VERSION 5.8 ;
BUSBITCHARS "[]" ;
DIVIDERCHAR "/" ;
UNITS
    DATABASE MICRONS 1000 ;
END UNITS

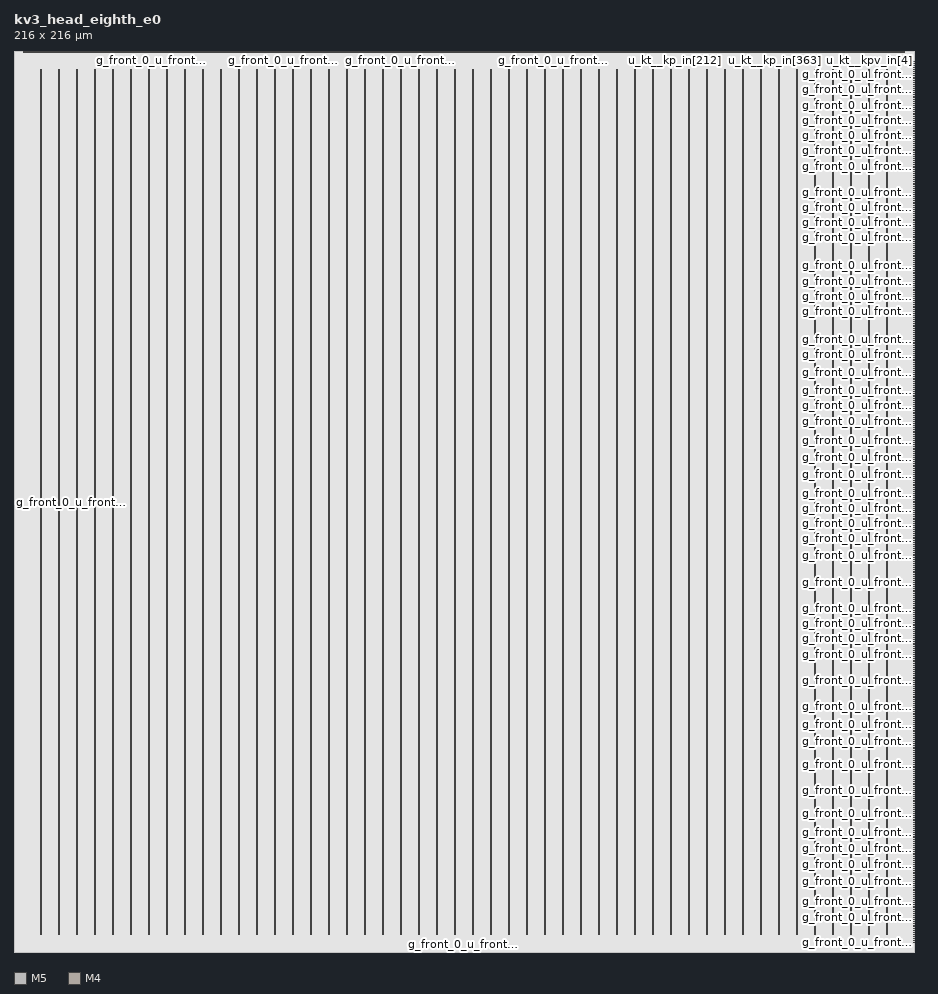
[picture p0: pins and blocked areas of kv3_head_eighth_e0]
MACRO kv3_head_eighth_e0
  FOREIGN kv3_head_eighth_e0 0 0 ;
  CLASS BLOCK ;
  SIZE 216 BY 216 ;
  PIN g_front_0_u_front__c_in[0]
    DIRECTION INPUT ;
    USE SIGNAL ;
    PORT
      LAYER M5 ;
        RECT  2.22 215.808 2.244 216 ;
    END
  END g_front_0_u_front__c_in[0]
  PIN g_front_0_u_front__c_in[1]
    DIRECTION INPUT ;
    USE SIGNAL ;
    PORT
      LAYER M5 ;
        RECT  2.364 215.808 2.388 216 ;
    END
  END g_front_0_u_front__c_in[1]
  PIN g_front_0_u_front__c_in[2]
    DIRECTION INPUT ;
    USE SIGNAL ;
    PORT
      LAYER M5 ;
        RECT  2.556 215.808 2.58 216 ;
    END
  END g_front_0_u_front__c_in[2]
  PIN g_front_0_u_front__c_in[3]
    DIRECTION INPUT ;
    USE SIGNAL ;
    PORT
      LAYER M5 ;
        RECT  2.7 215.808 2.724 216 ;
    END
  END g_front_0_u_front__c_in[3]
  PIN g_front_0_u_front__clk[0]
    DIRECTION INPUT ;
    USE SIGNAL ;
    PORT
      LAYER M5 ;
        RECT  2.844 215.808 2.868 216 ;
    END
  END g_front_0_u_front__clk[0]
  PIN g_front_0_u_front__e_in[0]
    DIRECTION INPUT ;
    USE SIGNAL ;
    PORT
      LAYER M5 ;
        RECT  3.036 215.808 3.06 216 ;
    END
  END g_front_0_u_front__e_in[0]
  PIN g_front_0_u_front__e_in[10]
    DIRECTION INPUT ;
    USE SIGNAL ;
    PORT
      LAYER M5 ;
        RECT  4.62 215.808 4.644 216 ;
    END
  END g_front_0_u_front__e_in[10]
  PIN g_front_0_u_front__e_in[11]
    DIRECTION INPUT ;
    USE SIGNAL ;
    PORT
      LAYER M5 ;
        RECT  4.764 215.808 4.788 216 ;
    END
  END g_front_0_u_front__e_in[11]
  PIN g_front_0_u_front__e_in[12]
    DIRECTION INPUT ;
    USE SIGNAL ;
    PORT
      LAYER M5 ;
        RECT  4.908 215.808 4.932 216 ;
    END
  END g_front_0_u_front__e_in[12]
  PIN g_front_0_u_front__e_in[13]
    DIRECTION INPUT ;
    USE SIGNAL ;
    PORT
      LAYER M5 ;
        RECT  5.1 215.808 5.124 216 ;
    END
  END g_front_0_u_front__e_in[13]
  PIN g_front_0_u_front__e_in[14]
    DIRECTION INPUT ;
    USE SIGNAL ;
    PORT
      LAYER M5 ;
        RECT  5.244 215.808 5.268 216 ;
    END
  END g_front_0_u_front__e_in[14]
  PIN g_front_0_u_front__e_in[15]
    DIRECTION INPUT ;
    USE SIGNAL ;
    PORT
      LAYER M5 ;
        RECT  5.388 215.808 5.412 216 ;
    END
  END g_front_0_u_front__e_in[15]
  PIN g_front_0_u_front__e_in[1]
    DIRECTION INPUT ;
    USE SIGNAL ;
    PORT
      LAYER M5 ;
        RECT  3.18 215.808 3.204 216 ;
    END
  END g_front_0_u_front__e_in[1]
  PIN g_front_0_u_front__e_in[2]
    DIRECTION INPUT ;
    USE SIGNAL ;
    PORT
      LAYER M5 ;
        RECT  3.324 215.808 3.348 216 ;
    END
  END g_front_0_u_front__e_in[2]
  PIN g_front_0_u_front__e_in[3]
    DIRECTION INPUT ;
    USE SIGNAL ;
    PORT
      LAYER M5 ;
        RECT  3.516 215.808 3.54 216 ;
    END
  END g_front_0_u_front__e_in[3]
  PIN g_front_0_u_front__e_in[4]
    DIRECTION INPUT ;
    USE SIGNAL ;
    PORT
      LAYER M5 ;
        RECT  3.66 215.808 3.684 216 ;
    END
  END g_front_0_u_front__e_in[4]
  PIN g_front_0_u_front__e_in[5]
    DIRECTION INPUT ;
    USE SIGNAL ;
    PORT
      LAYER M5 ;
        RECT  3.804 215.808 3.828 216 ;
    END
  END g_front_0_u_front__e_in[5]
  PIN g_front_0_u_front__e_in[6]
    DIRECTION INPUT ;
    USE SIGNAL ;
    PORT
      LAYER M5 ;
        RECT  3.996 215.808 4.02 216 ;
    END
  END g_front_0_u_front__e_in[6]
  PIN g_front_0_u_front__e_in[7]
    DIRECTION INPUT ;
    USE SIGNAL ;
    PORT
      LAYER M5 ;
        RECT  4.14 215.808 4.164 216 ;
    END
  END g_front_0_u_front__e_in[7]
  PIN g_front_0_u_front__e_in[8]
    DIRECTION INPUT ;
    USE SIGNAL ;
    PORT
      LAYER M5 ;
        RECT  4.284 215.808 4.308 216 ;
    END
  END g_front_0_u_front__e_in[8]
  PIN g_front_0_u_front__e_in[9]
    DIRECTION INPUT ;
    USE SIGNAL ;
    PORT
      LAYER M5 ;
        RECT  4.476 215.808 4.5 216 ;
    END
  END g_front_0_u_front__e_in[9]
  PIN g_front_0_u_front__f_t2[0]
    DIRECTION OUTPUT ;
    USE SIGNAL ;
    PORT
      LAYER M4 ;
        RECT  215.808 2.364 216 2.388 ;
    END
  END g_front_0_u_front__f_t2[0]
  PIN g_front_0_u_front__f_t2[100]
    DIRECTION OUTPUT ;
    USE SIGNAL ;
    PORT
      LAYER M4 ;
        RECT  215.808 47.82 216 47.844 ;
    END
  END g_front_0_u_front__f_t2[100]
  PIN g_front_0_u_front__f_t2[101]
    DIRECTION OUTPUT ;
    USE SIGNAL ;
    PORT
      LAYER M4 ;
        RECT  215.808 48.252 216 48.276 ;
    END
  END g_front_0_u_front__f_t2[101]
  PIN g_front_0_u_front__f_t2[102]
    DIRECTION OUTPUT ;
    USE SIGNAL ;
    PORT
      LAYER M4 ;
        RECT  215.808 48.732 216 48.756 ;
    END
  END g_front_0_u_front__f_t2[102]
  PIN g_front_0_u_front__f_t2[103]
    DIRECTION OUTPUT ;
    USE SIGNAL ;
    PORT
      LAYER M4 ;
        RECT  215.808 49.164 216 49.188 ;
    END
  END g_front_0_u_front__f_t2[103]
  PIN g_front_0_u_front__f_t2[104]
    DIRECTION OUTPUT ;
    USE SIGNAL ;
    PORT
      LAYER M4 ;
        RECT  215.808 49.596 216 49.62 ;
    END
  END g_front_0_u_front__f_t2[104]
  PIN g_front_0_u_front__f_t2[105]
    DIRECTION OUTPUT ;
    USE SIGNAL ;
    PORT
      LAYER M4 ;
        RECT  215.808 50.076 216 50.1 ;
    END
  END g_front_0_u_front__f_t2[105]
  PIN g_front_0_u_front__f_t2[106]
    DIRECTION OUTPUT ;
    USE SIGNAL ;
    PORT
      LAYER M4 ;
        RECT  215.808 50.508 216 50.532 ;
    END
  END g_front_0_u_front__f_t2[106]
  PIN g_front_0_u_front__f_t2[107]
    DIRECTION OUTPUT ;
    USE SIGNAL ;
    PORT
      LAYER M4 ;
        RECT  215.808 50.988 216 51.012 ;
    END
  END g_front_0_u_front__f_t2[107]
  PIN g_front_0_u_front__f_t2[108]
    DIRECTION OUTPUT ;
    USE SIGNAL ;
    PORT
      LAYER M4 ;
        RECT  215.808 51.42 216 51.444 ;
    END
  END g_front_0_u_front__f_t2[108]
  PIN g_front_0_u_front__f_t2[109]
    DIRECTION OUTPUT ;
    USE SIGNAL ;
    PORT
      LAYER M4 ;
        RECT  215.808 51.9 216 51.924 ;
    END
  END g_front_0_u_front__f_t2[109]
  PIN g_front_0_u_front__f_t2[10]
    DIRECTION OUTPUT ;
    USE SIGNAL ;
    PORT
      LAYER M4 ;
        RECT  215.808 6.924 216 6.948 ;
    END
  END g_front_0_u_front__f_t2[10]
  PIN g_front_0_u_front__f_t2[110]
    DIRECTION OUTPUT ;
    USE SIGNAL ;
    PORT
      LAYER M4 ;
        RECT  215.808 52.332 216 52.356 ;
    END
  END g_front_0_u_front__f_t2[110]
  PIN g_front_0_u_front__f_t2[111]
    DIRECTION OUTPUT ;
    USE SIGNAL ;
    PORT
      LAYER M4 ;
        RECT  215.808 52.812 216 52.836 ;
    END
  END g_front_0_u_front__f_t2[111]
  PIN g_front_0_u_front__f_t2[112]
    DIRECTION OUTPUT ;
    USE SIGNAL ;
    PORT
      LAYER M4 ;
        RECT  215.808 53.244 216 53.268 ;
    END
  END g_front_0_u_front__f_t2[112]
  PIN g_front_0_u_front__f_t2[113]
    DIRECTION OUTPUT ;
    USE SIGNAL ;
    PORT
      LAYER M4 ;
        RECT  215.808 53.724 216 53.748 ;
    END
  END g_front_0_u_front__f_t2[113]
  PIN g_front_0_u_front__f_t2[114]
    DIRECTION OUTPUT ;
    USE SIGNAL ;
    PORT
      LAYER M4 ;
        RECT  215.808 54.156 216 54.18 ;
    END
  END g_front_0_u_front__f_t2[114]
  PIN g_front_0_u_front__f_t2[115]
    DIRECTION OUTPUT ;
    USE SIGNAL ;
    PORT
      LAYER M4 ;
        RECT  215.808 54.636 216 54.66 ;
    END
  END g_front_0_u_front__f_t2[115]
  PIN g_front_0_u_front__f_t2[116]
    DIRECTION OUTPUT ;
    USE SIGNAL ;
    PORT
      LAYER M4 ;
        RECT  215.808 55.068 216 55.092 ;
    END
  END g_front_0_u_front__f_t2[116]
  PIN g_front_0_u_front__f_t2[117]
    DIRECTION OUTPUT ;
    USE SIGNAL ;
    PORT
      LAYER M4 ;
        RECT  215.808 55.5 216 55.524 ;
    END
  END g_front_0_u_front__f_t2[117]
  PIN g_front_0_u_front__f_t2[118]
    DIRECTION OUTPUT ;
    USE SIGNAL ;
    PORT
      LAYER M4 ;
        RECT  215.808 55.98 216 56.004 ;
    END
  END g_front_0_u_front__f_t2[118]
  PIN g_front_0_u_front__f_t2[119]
    DIRECTION OUTPUT ;
    USE SIGNAL ;
    PORT
      LAYER M4 ;
        RECT  215.808 56.412 216 56.436 ;
    END
  END g_front_0_u_front__f_t2[119]
  PIN g_front_0_u_front__f_t2[11]
    DIRECTION OUTPUT ;
    USE SIGNAL ;
    PORT
      LAYER M4 ;
        RECT  215.808 7.356 216 7.38 ;
    END
  END g_front_0_u_front__f_t2[11]
  PIN g_front_0_u_front__f_t2[120]
    DIRECTION OUTPUT ;
    USE SIGNAL ;
    PORT
      LAYER M4 ;
        RECT  215.808 56.892 216 56.916 ;
    END
  END g_front_0_u_front__f_t2[120]
  PIN g_front_0_u_front__f_t2[121]
    DIRECTION OUTPUT ;
    USE SIGNAL ;
    PORT
      LAYER M4 ;
        RECT  215.808 57.324 216 57.348 ;
    END
  END g_front_0_u_front__f_t2[121]
  PIN g_front_0_u_front__f_t2[122]
    DIRECTION OUTPUT ;
    USE SIGNAL ;
    PORT
      LAYER M4 ;
        RECT  215.808 57.804 216 57.828 ;
    END
  END g_front_0_u_front__f_t2[122]
  PIN g_front_0_u_front__f_t2[123]
    DIRECTION OUTPUT ;
    USE SIGNAL ;
    PORT
      LAYER M4 ;
        RECT  215.808 58.236 216 58.26 ;
    END
  END g_front_0_u_front__f_t2[123]
  PIN g_front_0_u_front__f_t2[124]
    DIRECTION OUTPUT ;
    USE SIGNAL ;
    PORT
      LAYER M4 ;
        RECT  215.808 58.716 216 58.74 ;
    END
  END g_front_0_u_front__f_t2[124]
  PIN g_front_0_u_front__f_t2[125]
    DIRECTION OUTPUT ;
    USE SIGNAL ;
    PORT
      LAYER M4 ;
        RECT  215.808 59.148 216 59.172 ;
    END
  END g_front_0_u_front__f_t2[125]
  PIN g_front_0_u_front__f_t2[126]
    DIRECTION OUTPUT ;
    USE SIGNAL ;
    PORT
      LAYER M4 ;
        RECT  215.808 59.628 216 59.652 ;
    END
  END g_front_0_u_front__f_t2[126]
  PIN g_front_0_u_front__f_t2[127]
    DIRECTION OUTPUT ;
    USE SIGNAL ;
    PORT
      LAYER M4 ;
        RECT  215.808 60.06 216 60.084 ;
    END
  END g_front_0_u_front__f_t2[127]
  PIN g_front_0_u_front__f_t2[128]
    DIRECTION OUTPUT ;
    USE SIGNAL ;
    PORT
      LAYER M4 ;
        RECT  215.808 60.54 216 60.564 ;
    END
  END g_front_0_u_front__f_t2[128]
  PIN g_front_0_u_front__f_t2[129]
    DIRECTION OUTPUT ;
    USE SIGNAL ;
    PORT
      LAYER M4 ;
        RECT  215.808 60.972 216 60.996 ;
    END
  END g_front_0_u_front__f_t2[129]
  PIN g_front_0_u_front__f_t2[12]
    DIRECTION OUTPUT ;
    USE SIGNAL ;
    PORT
      LAYER M4 ;
        RECT  215.808 7.836 216 7.86 ;
    END
  END g_front_0_u_front__f_t2[12]
  PIN g_front_0_u_front__f_t2[130]
    DIRECTION OUTPUT ;
    USE SIGNAL ;
    PORT
      LAYER M4 ;
        RECT  215.808 61.404 216 61.428 ;
    END
  END g_front_0_u_front__f_t2[130]
  PIN g_front_0_u_front__f_t2[131]
    DIRECTION OUTPUT ;
    USE SIGNAL ;
    PORT
      LAYER M4 ;
        RECT  215.808 61.884 216 61.908 ;
    END
  END g_front_0_u_front__f_t2[131]
  PIN g_front_0_u_front__f_t2[132]
    DIRECTION OUTPUT ;
    USE SIGNAL ;
    PORT
      LAYER M4 ;
        RECT  215.808 62.316 216 62.34 ;
    END
  END g_front_0_u_front__f_t2[132]
  PIN g_front_0_u_front__f_t2[133]
    DIRECTION OUTPUT ;
    USE SIGNAL ;
    PORT
      LAYER M4 ;
        RECT  215.808 62.796 216 62.82 ;
    END
  END g_front_0_u_front__f_t2[133]
  PIN g_front_0_u_front__f_t2[134]
    DIRECTION OUTPUT ;
    USE SIGNAL ;
    PORT
      LAYER M4 ;
        RECT  215.808 63.228 216 63.252 ;
    END
  END g_front_0_u_front__f_t2[134]
  PIN g_front_0_u_front__f_t2[135]
    DIRECTION OUTPUT ;
    USE SIGNAL ;
    PORT
      LAYER M4 ;
        RECT  215.808 63.708 216 63.732 ;
    END
  END g_front_0_u_front__f_t2[135]
  PIN g_front_0_u_front__f_t2[136]
    DIRECTION OUTPUT ;
    USE SIGNAL ;
    PORT
      LAYER M4 ;
        RECT  215.808 64.14 216 64.164 ;
    END
  END g_front_0_u_front__f_t2[136]
  PIN g_front_0_u_front__f_t2[137]
    DIRECTION OUTPUT ;
    USE SIGNAL ;
    PORT
      LAYER M4 ;
        RECT  215.808 64.62 216 64.644 ;
    END
  END g_front_0_u_front__f_t2[137]
  PIN g_front_0_u_front__f_t2[138]
    DIRECTION OUTPUT ;
    USE SIGNAL ;
    PORT
      LAYER M4 ;
        RECT  215.808 65.052 216 65.076 ;
    END
  END g_front_0_u_front__f_t2[138]
  PIN g_front_0_u_front__f_t2[139]
    DIRECTION OUTPUT ;
    USE SIGNAL ;
    PORT
      LAYER M4 ;
        RECT  215.808 65.532 216 65.556 ;
    END
  END g_front_0_u_front__f_t2[139]
  PIN g_front_0_u_front__f_t2[13]
    DIRECTION OUTPUT ;
    USE SIGNAL ;
    PORT
      LAYER M4 ;
        RECT  215.808 8.268 216 8.292 ;
    END
  END g_front_0_u_front__f_t2[13]
  PIN g_front_0_u_front__f_t2[140]
    DIRECTION OUTPUT ;
    USE SIGNAL ;
    PORT
      LAYER M4 ;
        RECT  215.808 65.964 216 65.988 ;
    END
  END g_front_0_u_front__f_t2[140]
  PIN g_front_0_u_front__f_t2[141]
    DIRECTION OUTPUT ;
    USE SIGNAL ;
    PORT
      LAYER M4 ;
        RECT  215.808 66.444 216 66.468 ;
    END
  END g_front_0_u_front__f_t2[141]
  PIN g_front_0_u_front__f_t2[142]
    DIRECTION OUTPUT ;
    USE SIGNAL ;
    PORT
      LAYER M4 ;
        RECT  215.808 66.876 216 66.9 ;
    END
  END g_front_0_u_front__f_t2[142]
  PIN g_front_0_u_front__f_t2[143]
    DIRECTION OUTPUT ;
    USE SIGNAL ;
    PORT
      LAYER M4 ;
        RECT  215.808 67.356 216 67.38 ;
    END
  END g_front_0_u_front__f_t2[143]
  PIN g_front_0_u_front__f_t2[144]
    DIRECTION OUTPUT ;
    USE SIGNAL ;
    PORT
      LAYER M4 ;
        RECT  215.808 67.788 216 67.812 ;
    END
  END g_front_0_u_front__f_t2[144]
  PIN g_front_0_u_front__f_t2[145]
    DIRECTION OUTPUT ;
    USE SIGNAL ;
    PORT
      LAYER M4 ;
        RECT  215.808 68.22 216 68.244 ;
    END
  END g_front_0_u_front__f_t2[145]
  PIN g_front_0_u_front__f_t2[146]
    DIRECTION OUTPUT ;
    USE SIGNAL ;
    PORT
      LAYER M4 ;
        RECT  215.808 68.7 216 68.724 ;
    END
  END g_front_0_u_front__f_t2[146]
  PIN g_front_0_u_front__f_t2[147]
    DIRECTION OUTPUT ;
    USE SIGNAL ;
    PORT
      LAYER M4 ;
        RECT  215.808 69.132 216 69.156 ;
    END
  END g_front_0_u_front__f_t2[147]
  PIN g_front_0_u_front__f_t2[148]
    DIRECTION OUTPUT ;
    USE SIGNAL ;
    PORT
      LAYER M4 ;
        RECT  215.808 69.612 216 69.636 ;
    END
  END g_front_0_u_front__f_t2[148]
  PIN g_front_0_u_front__f_t2[149]
    DIRECTION OUTPUT ;
    USE SIGNAL ;
    PORT
      LAYER M4 ;
        RECT  215.808 70.044 216 70.068 ;
    END
  END g_front_0_u_front__f_t2[149]
  PIN g_front_0_u_front__f_t2[14]
    DIRECTION OUTPUT ;
    USE SIGNAL ;
    PORT
      LAYER M4 ;
        RECT  215.808 8.748 216 8.772 ;
    END
  END g_front_0_u_front__f_t2[14]
  PIN g_front_0_u_front__f_t2[150]
    DIRECTION OUTPUT ;
    USE SIGNAL ;
    PORT
      LAYER M4 ;
        RECT  215.808 70.524 216 70.548 ;
    END
  END g_front_0_u_front__f_t2[150]
  PIN g_front_0_u_front__f_t2[151]
    DIRECTION OUTPUT ;
    USE SIGNAL ;
    PORT
      LAYER M4 ;
        RECT  215.808 70.956 216 70.98 ;
    END
  END g_front_0_u_front__f_t2[151]
  PIN g_front_0_u_front__f_t2[152]
    DIRECTION OUTPUT ;
    USE SIGNAL ;
    PORT
      LAYER M4 ;
        RECT  215.808 71.436 216 71.46 ;
    END
  END g_front_0_u_front__f_t2[152]
  PIN g_front_0_u_front__f_t2[153]
    DIRECTION OUTPUT ;
    USE SIGNAL ;
    PORT
      LAYER M4 ;
        RECT  215.808 71.868 216 71.892 ;
    END
  END g_front_0_u_front__f_t2[153]
  PIN g_front_0_u_front__f_t2[154]
    DIRECTION OUTPUT ;
    USE SIGNAL ;
    PORT
      LAYER M4 ;
        RECT  215.808 72.348 216 72.372 ;
    END
  END g_front_0_u_front__f_t2[154]
  PIN g_front_0_u_front__f_t2[155]
    DIRECTION OUTPUT ;
    USE SIGNAL ;
    PORT
      LAYER M4 ;
        RECT  215.808 72.78 216 72.804 ;
    END
  END g_front_0_u_front__f_t2[155]
  PIN g_front_0_u_front__f_t2[156]
    DIRECTION OUTPUT ;
    USE SIGNAL ;
    PORT
      LAYER M4 ;
        RECT  215.808 73.26 216 73.284 ;
    END
  END g_front_0_u_front__f_t2[156]
  PIN g_front_0_u_front__f_t2[157]
    DIRECTION OUTPUT ;
    USE SIGNAL ;
    PORT
      LAYER M4 ;
        RECT  215.808 73.692 216 73.716 ;
    END
  END g_front_0_u_front__f_t2[157]
  PIN g_front_0_u_front__f_t2[158]
    DIRECTION OUTPUT ;
    USE SIGNAL ;
    PORT
      LAYER M4 ;
        RECT  215.808 74.124 216 74.148 ;
    END
  END g_front_0_u_front__f_t2[158]
  PIN g_front_0_u_front__f_t2[159]
    DIRECTION OUTPUT ;
    USE SIGNAL ;
    PORT
      LAYER M4 ;
        RECT  215.808 74.604 216 74.628 ;
    END
  END g_front_0_u_front__f_t2[159]
  PIN g_front_0_u_front__f_t2[15]
    DIRECTION OUTPUT ;
    USE SIGNAL ;
    PORT
      LAYER M4 ;
        RECT  215.808 9.18 216 9.204 ;
    END
  END g_front_0_u_front__f_t2[15]
  PIN g_front_0_u_front__f_t2[160]
    DIRECTION OUTPUT ;
    USE SIGNAL ;
    PORT
      LAYER M4 ;
        RECT  215.808 75.036 216 75.06 ;
    END
  END g_front_0_u_front__f_t2[160]
  PIN g_front_0_u_front__f_t2[161]
    DIRECTION OUTPUT ;
    USE SIGNAL ;
    PORT
      LAYER M4 ;
        RECT  215.808 75.516 216 75.54 ;
    END
  END g_front_0_u_front__f_t2[161]
  PIN g_front_0_u_front__f_t2[162]
    DIRECTION OUTPUT ;
    USE SIGNAL ;
    PORT
      LAYER M4 ;
        RECT  215.808 75.948 216 75.972 ;
    END
  END g_front_0_u_front__f_t2[162]
  PIN g_front_0_u_front__f_t2[163]
    DIRECTION OUTPUT ;
    USE SIGNAL ;
    PORT
      LAYER M4 ;
        RECT  215.808 76.428 216 76.452 ;
    END
  END g_front_0_u_front__f_t2[163]
  PIN g_front_0_u_front__f_t2[164]
    DIRECTION OUTPUT ;
    USE SIGNAL ;
    PORT
      LAYER M4 ;
        RECT  215.808 76.86 216 76.884 ;
    END
  END g_front_0_u_front__f_t2[164]
  PIN g_front_0_u_front__f_t2[165]
    DIRECTION OUTPUT ;
    USE SIGNAL ;
    PORT
      LAYER M4 ;
        RECT  215.808 77.34 216 77.364 ;
    END
  END g_front_0_u_front__f_t2[165]
  PIN g_front_0_u_front__f_t2[166]
    DIRECTION OUTPUT ;
    USE SIGNAL ;
    PORT
      LAYER M4 ;
        RECT  215.808 77.772 216 77.796 ;
    END
  END g_front_0_u_front__f_t2[166]
  PIN g_front_0_u_front__f_t2[167]
    DIRECTION OUTPUT ;
    USE SIGNAL ;
    PORT
      LAYER M4 ;
        RECT  215.808 78.252 216 78.276 ;
    END
  END g_front_0_u_front__f_t2[167]
  PIN g_front_0_u_front__f_t2[168]
    DIRECTION OUTPUT ;
    USE SIGNAL ;
    PORT
      LAYER M4 ;
        RECT  215.808 78.684 216 78.708 ;
    END
  END g_front_0_u_front__f_t2[168]
  PIN g_front_0_u_front__f_t2[169]
    DIRECTION OUTPUT ;
    USE SIGNAL ;
    PORT
      LAYER M4 ;
        RECT  215.808 79.164 216 79.188 ;
    END
  END g_front_0_u_front__f_t2[169]
  PIN g_front_0_u_front__f_t2[16]
    DIRECTION OUTPUT ;
    USE SIGNAL ;
    PORT
      LAYER M4 ;
        RECT  215.808 9.66 216 9.684 ;
    END
  END g_front_0_u_front__f_t2[16]
  PIN g_front_0_u_front__f_t2[170]
    DIRECTION OUTPUT ;
    USE SIGNAL ;
    PORT
      LAYER M4 ;
        RECT  215.808 79.596 216 79.62 ;
    END
  END g_front_0_u_front__f_t2[170]
  PIN g_front_0_u_front__f_t2[171]
    DIRECTION OUTPUT ;
    USE SIGNAL ;
    PORT
      LAYER M4 ;
        RECT  215.808 80.028 216 80.052 ;
    END
  END g_front_0_u_front__f_t2[171]
  PIN g_front_0_u_front__f_t2[172]
    DIRECTION OUTPUT ;
    USE SIGNAL ;
    PORT
      LAYER M4 ;
        RECT  215.808 80.508 216 80.532 ;
    END
  END g_front_0_u_front__f_t2[172]
  PIN g_front_0_u_front__f_t2[173]
    DIRECTION OUTPUT ;
    USE SIGNAL ;
    PORT
      LAYER M4 ;
        RECT  215.808 80.94 216 80.964 ;
    END
  END g_front_0_u_front__f_t2[173]
  PIN g_front_0_u_front__f_t2[174]
    DIRECTION OUTPUT ;
    USE SIGNAL ;
    PORT
      LAYER M4 ;
        RECT  215.808 81.42 216 81.444 ;
    END
  END g_front_0_u_front__f_t2[174]
  PIN g_front_0_u_front__f_t2[175]
    DIRECTION OUTPUT ;
    USE SIGNAL ;
    PORT
      LAYER M4 ;
        RECT  215.808 81.852 216 81.876 ;
    END
  END g_front_0_u_front__f_t2[175]
  PIN g_front_0_u_front__f_t2[176]
    DIRECTION OUTPUT ;
    USE SIGNAL ;
    PORT
      LAYER M4 ;
        RECT  215.808 82.332 216 82.356 ;
    END
  END g_front_0_u_front__f_t2[176]
  PIN g_front_0_u_front__f_t2[177]
    DIRECTION OUTPUT ;
    USE SIGNAL ;
    PORT
      LAYER M4 ;
        RECT  215.808 82.764 216 82.788 ;
    END
  END g_front_0_u_front__f_t2[177]
  PIN g_front_0_u_front__f_t2[178]
    DIRECTION OUTPUT ;
    USE SIGNAL ;
    PORT
      LAYER M4 ;
        RECT  215.808 83.244 216 83.268 ;
    END
  END g_front_0_u_front__f_t2[178]
  PIN g_front_0_u_front__f_t2[179]
    DIRECTION OUTPUT ;
    USE SIGNAL ;
    PORT
      LAYER M4 ;
        RECT  215.808 83.676 216 83.7 ;
    END
  END g_front_0_u_front__f_t2[179]
  PIN g_front_0_u_front__f_t2[17]
    DIRECTION OUTPUT ;
    USE SIGNAL ;
    PORT
      LAYER M4 ;
        RECT  215.808 10.092 216 10.116 ;
    END
  END g_front_0_u_front__f_t2[17]
  PIN g_front_0_u_front__f_t2[180]
    DIRECTION OUTPUT ;
    USE SIGNAL ;
    PORT
      LAYER M4 ;
        RECT  215.808 84.156 216 84.18 ;
    END
  END g_front_0_u_front__f_t2[180]
  PIN g_front_0_u_front__f_t2[181]
    DIRECTION OUTPUT ;
    USE SIGNAL ;
    PORT
      LAYER M4 ;
        RECT  215.808 84.588 216 84.612 ;
    END
  END g_front_0_u_front__f_t2[181]
  PIN g_front_0_u_front__f_t2[182]
    DIRECTION OUTPUT ;
    USE SIGNAL ;
    PORT
      LAYER M4 ;
        RECT  215.808 85.068 216 85.092 ;
    END
  END g_front_0_u_front__f_t2[182]
  PIN g_front_0_u_front__f_t2[183]
    DIRECTION OUTPUT ;
    USE SIGNAL ;
    PORT
      LAYER M4 ;
        RECT  215.808 85.5 216 85.524 ;
    END
  END g_front_0_u_front__f_t2[183]
  PIN g_front_0_u_front__f_t2[184]
    DIRECTION OUTPUT ;
    USE SIGNAL ;
    PORT
      LAYER M4 ;
        RECT  215.808 85.98 216 86.004 ;
    END
  END g_front_0_u_front__f_t2[184]
  PIN g_front_0_u_front__f_t2[185]
    DIRECTION OUTPUT ;
    USE SIGNAL ;
    PORT
      LAYER M4 ;
        RECT  215.808 86.412 216 86.436 ;
    END
  END g_front_0_u_front__f_t2[185]
  PIN g_front_0_u_front__f_t2[186]
    DIRECTION OUTPUT ;
    USE SIGNAL ;
    PORT
      LAYER M4 ;
        RECT  215.808 86.844 216 86.868 ;
    END
  END g_front_0_u_front__f_t2[186]
  PIN g_front_0_u_front__f_t2[187]
    DIRECTION OUTPUT ;
    USE SIGNAL ;
    PORT
      LAYER M4 ;
        RECT  215.808 87.324 216 87.348 ;
    END
  END g_front_0_u_front__f_t2[187]
  PIN g_front_0_u_front__f_t2[188]
    DIRECTION OUTPUT ;
    USE SIGNAL ;
    PORT
      LAYER M4 ;
        RECT  215.808 87.756 216 87.78 ;
    END
  END g_front_0_u_front__f_t2[188]
  PIN g_front_0_u_front__f_t2[189]
    DIRECTION OUTPUT ;
    USE SIGNAL ;
    PORT
      LAYER M4 ;
        RECT  215.808 88.236 216 88.26 ;
    END
  END g_front_0_u_front__f_t2[189]
  PIN g_front_0_u_front__f_t2[18]
    DIRECTION OUTPUT ;
    USE SIGNAL ;
    PORT
      LAYER M4 ;
        RECT  215.808 10.572 216 10.596 ;
    END
  END g_front_0_u_front__f_t2[18]
  PIN g_front_0_u_front__f_t2[190]
    DIRECTION OUTPUT ;
    USE SIGNAL ;
    PORT
      LAYER M4 ;
        RECT  215.808 88.668 216 88.692 ;
    END
  END g_front_0_u_front__f_t2[190]
  PIN g_front_0_u_front__f_t2[191]
    DIRECTION OUTPUT ;
    USE SIGNAL ;
    PORT
      LAYER M4 ;
        RECT  215.808 89.148 216 89.172 ;
    END
  END g_front_0_u_front__f_t2[191]
  PIN g_front_0_u_front__f_t2[192]
    DIRECTION OUTPUT ;
    USE SIGNAL ;
    PORT
      LAYER M4 ;
        RECT  215.808 89.58 216 89.604 ;
    END
  END g_front_0_u_front__f_t2[192]
  PIN g_front_0_u_front__f_t2[193]
    DIRECTION OUTPUT ;
    USE SIGNAL ;
    PORT
      LAYER M4 ;
        RECT  215.808 90.06 216 90.084 ;
    END
  END g_front_0_u_front__f_t2[193]
  PIN g_front_0_u_front__f_t2[194]
    DIRECTION OUTPUT ;
    USE SIGNAL ;
    PORT
      LAYER M4 ;
        RECT  215.808 90.492 216 90.516 ;
    END
  END g_front_0_u_front__f_t2[194]
  PIN g_front_0_u_front__f_t2[195]
    DIRECTION OUTPUT ;
    USE SIGNAL ;
    PORT
      LAYER M4 ;
        RECT  215.808 90.972 216 90.996 ;
    END
  END g_front_0_u_front__f_t2[195]
  PIN g_front_0_u_front__f_t2[196]
    DIRECTION OUTPUT ;
    USE SIGNAL ;
    PORT
      LAYER M4 ;
        RECT  215.808 91.404 216 91.428 ;
    END
  END g_front_0_u_front__f_t2[196]
  PIN g_front_0_u_front__f_t2[197]
    DIRECTION OUTPUT ;
    USE SIGNAL ;
    PORT
      LAYER M4 ;
        RECT  215.808 91.884 216 91.908 ;
    END
  END g_front_0_u_front__f_t2[197]
  PIN g_front_0_u_front__f_t2[198]
    DIRECTION OUTPUT ;
    USE SIGNAL ;
    PORT
      LAYER M4 ;
        RECT  215.808 92.316 216 92.34 ;
    END
  END g_front_0_u_front__f_t2[198]
  PIN g_front_0_u_front__f_t2[199]
    DIRECTION OUTPUT ;
    USE SIGNAL ;
    PORT
      LAYER M4 ;
        RECT  215.808 92.748 216 92.772 ;
    END
  END g_front_0_u_front__f_t2[199]
  PIN g_front_0_u_front__f_t2[19]
    DIRECTION OUTPUT ;
    USE SIGNAL ;
    PORT
      LAYER M4 ;
        RECT  215.808 11.004 216 11.028 ;
    END
  END g_front_0_u_front__f_t2[19]
  PIN g_front_0_u_front__f_t2[1]
    DIRECTION OUTPUT ;
    USE SIGNAL ;
    PORT
      LAYER M4 ;
        RECT  215.808 2.844 216 2.868 ;
    END
  END g_front_0_u_front__f_t2[1]
  PIN g_front_0_u_front__f_t2[200]
    DIRECTION OUTPUT ;
    USE SIGNAL ;
    PORT
      LAYER M4 ;
        RECT  215.808 93.228 216 93.252 ;
    END
  END g_front_0_u_front__f_t2[200]
  PIN g_front_0_u_front__f_t2[201]
    DIRECTION OUTPUT ;
    USE SIGNAL ;
    PORT
      LAYER M4 ;
        RECT  215.808 93.66 216 93.684 ;
    END
  END g_front_0_u_front__f_t2[201]
  PIN g_front_0_u_front__f_t2[202]
    DIRECTION OUTPUT ;
    USE SIGNAL ;
    PORT
      LAYER M4 ;
        RECT  215.808 94.14 216 94.164 ;
    END
  END g_front_0_u_front__f_t2[202]
  PIN g_front_0_u_front__f_t2[203]
    DIRECTION OUTPUT ;
    USE SIGNAL ;
    PORT
      LAYER M4 ;
        RECT  215.808 94.572 216 94.596 ;
    END
  END g_front_0_u_front__f_t2[203]
  PIN g_front_0_u_front__f_t2[204]
    DIRECTION OUTPUT ;
    USE SIGNAL ;
    PORT
      LAYER M4 ;
        RECT  215.808 95.052 216 95.076 ;
    END
  END g_front_0_u_front__f_t2[204]
  PIN g_front_0_u_front__f_t2[205]
    DIRECTION OUTPUT ;
    USE SIGNAL ;
    PORT
      LAYER M4 ;
        RECT  215.808 95.484 216 95.508 ;
    END
  END g_front_0_u_front__f_t2[205]
  PIN g_front_0_u_front__f_t2[206]
    DIRECTION OUTPUT ;
    USE SIGNAL ;
    PORT
      LAYER M4 ;
        RECT  215.808 95.964 216 95.988 ;
    END
  END g_front_0_u_front__f_t2[206]
  PIN g_front_0_u_front__f_t2[207]
    DIRECTION OUTPUT ;
    USE SIGNAL ;
    PORT
      LAYER M4 ;
        RECT  215.808 96.396 216 96.42 ;
    END
  END g_front_0_u_front__f_t2[207]
  PIN g_front_0_u_front__f_t2[208]
    DIRECTION OUTPUT ;
    USE SIGNAL ;
    PORT
      LAYER M4 ;
        RECT  215.808 96.876 216 96.9 ;
    END
  END g_front_0_u_front__f_t2[208]
  PIN g_front_0_u_front__f_t2[209]
    DIRECTION OUTPUT ;
    USE SIGNAL ;
    PORT
      LAYER M4 ;
        RECT  215.808 97.308 216 97.332 ;
    END
  END g_front_0_u_front__f_t2[209]
  PIN g_front_0_u_front__f_t2[20]
    DIRECTION OUTPUT ;
    USE SIGNAL ;
    PORT
      LAYER M4 ;
        RECT  215.808 11.484 216 11.508 ;
    END
  END g_front_0_u_front__f_t2[20]
  PIN g_front_0_u_front__f_t2[210]
    DIRECTION OUTPUT ;
    USE SIGNAL ;
    PORT
      LAYER M4 ;
        RECT  215.808 97.788 216 97.812 ;
    END
  END g_front_0_u_front__f_t2[210]
  PIN g_front_0_u_front__f_t2[211]
    DIRECTION OUTPUT ;
    USE SIGNAL ;
    PORT
      LAYER M4 ;
        RECT  215.808 98.22 216 98.244 ;
    END
  END g_front_0_u_front__f_t2[211]
  PIN g_front_0_u_front__f_t2[212]
    DIRECTION OUTPUT ;
    USE SIGNAL ;
    PORT
      LAYER M4 ;
        RECT  215.808 98.652 216 98.676 ;
    END
  END g_front_0_u_front__f_t2[212]
  PIN g_front_0_u_front__f_t2[213]
    DIRECTION OUTPUT ;
    USE SIGNAL ;
    PORT
      LAYER M4 ;
        RECT  215.808 99.132 216 99.156 ;
    END
  END g_front_0_u_front__f_t2[213]
  PIN g_front_0_u_front__f_t2[214]
    DIRECTION OUTPUT ;
    USE SIGNAL ;
    PORT
      LAYER M4 ;
        RECT  215.808 99.564 216 99.588 ;
    END
  END g_front_0_u_front__f_t2[214]
  PIN g_front_0_u_front__f_t2[215]
    DIRECTION OUTPUT ;
    USE SIGNAL ;
    PORT
      LAYER M4 ;
        RECT  215.808 100.044 216 100.068 ;
    END
  END g_front_0_u_front__f_t2[215]
  PIN g_front_0_u_front__f_t2[216]
    DIRECTION OUTPUT ;
    USE SIGNAL ;
    PORT
      LAYER M4 ;
        RECT  215.808 100.476 216 100.5 ;
    END
  END g_front_0_u_front__f_t2[216]
  PIN g_front_0_u_front__f_t2[217]
    DIRECTION OUTPUT ;
    USE SIGNAL ;
    PORT
      LAYER M4 ;
        RECT  215.808 100.956 216 100.98 ;
    END
  END g_front_0_u_front__f_t2[217]
  PIN g_front_0_u_front__f_t2[218]
    DIRECTION OUTPUT ;
    USE SIGNAL ;
    PORT
      LAYER M4 ;
        RECT  215.808 101.388 216 101.412 ;
    END
  END g_front_0_u_front__f_t2[218]
  PIN g_front_0_u_front__f_t2[219]
    DIRECTION OUTPUT ;
    USE SIGNAL ;
    PORT
      LAYER M4 ;
        RECT  215.808 101.868 216 101.892 ;
    END
  END g_front_0_u_front__f_t2[219]
  PIN g_front_0_u_front__f_t2[21]
    DIRECTION OUTPUT ;
    USE SIGNAL ;
    PORT
      LAYER M4 ;
        RECT  215.808 11.916 216 11.94 ;
    END
  END g_front_0_u_front__f_t2[21]
  PIN g_front_0_u_front__f_t2[220]
    DIRECTION OUTPUT ;
    USE SIGNAL ;
    PORT
      LAYER M4 ;
        RECT  215.808 102.3 216 102.324 ;
    END
  END g_front_0_u_front__f_t2[220]
  PIN g_front_0_u_front__f_t2[221]
    DIRECTION OUTPUT ;
    USE SIGNAL ;
    PORT
      LAYER M4 ;
        RECT  215.808 102.78 216 102.804 ;
    END
  END g_front_0_u_front__f_t2[221]
  PIN g_front_0_u_front__f_t2[222]
    DIRECTION OUTPUT ;
    USE SIGNAL ;
    PORT
      LAYER M4 ;
        RECT  215.808 103.212 216 103.236 ;
    END
  END g_front_0_u_front__f_t2[222]
  PIN g_front_0_u_front__f_t2[223]
    DIRECTION OUTPUT ;
    USE SIGNAL ;
    PORT
      LAYER M4 ;
        RECT  215.808 103.692 216 103.716 ;
    END
  END g_front_0_u_front__f_t2[223]
  PIN g_front_0_u_front__f_t2[224]
    DIRECTION OUTPUT ;
    USE SIGNAL ;
    PORT
      LAYER M4 ;
        RECT  215.808 104.124 216 104.148 ;
    END
  END g_front_0_u_front__f_t2[224]
  PIN g_front_0_u_front__f_t2[225]
    DIRECTION OUTPUT ;
    USE SIGNAL ;
    PORT
      LAYER M4 ;
        RECT  215.808 104.604 216 104.628 ;
    END
  END g_front_0_u_front__f_t2[225]
  PIN g_front_0_u_front__f_t2[226]
    DIRECTION OUTPUT ;
    USE SIGNAL ;
    PORT
      LAYER M4 ;
        RECT  215.808 105.036 216 105.06 ;
    END
  END g_front_0_u_front__f_t2[226]
  PIN g_front_0_u_front__f_t2[227]
    DIRECTION OUTPUT ;
    USE SIGNAL ;
    PORT
      LAYER M4 ;
        RECT  215.808 105.468 216 105.492 ;
    END
  END g_front_0_u_front__f_t2[227]
  PIN g_front_0_u_front__f_t2[228]
    DIRECTION OUTPUT ;
    USE SIGNAL ;
    PORT
      LAYER M4 ;
        RECT  215.808 105.948 216 105.972 ;
    END
  END g_front_0_u_front__f_t2[228]
  PIN g_front_0_u_front__f_t2[229]
    DIRECTION OUTPUT ;
    USE SIGNAL ;
    PORT
      LAYER M4 ;
        RECT  215.808 106.38 216 106.404 ;
    END
  END g_front_0_u_front__f_t2[229]
  PIN g_front_0_u_front__f_t2[22]
    DIRECTION OUTPUT ;
    USE SIGNAL ;
    PORT
      LAYER M4 ;
        RECT  215.808 12.348 216 12.372 ;
    END
  END g_front_0_u_front__f_t2[22]
  PIN g_front_0_u_front__f_t2[230]
    DIRECTION OUTPUT ;
    USE SIGNAL ;
    PORT
      LAYER M4 ;
        RECT  215.808 106.86 216 106.884 ;
    END
  END g_front_0_u_front__f_t2[230]
  PIN g_front_0_u_front__f_t2[231]
    DIRECTION OUTPUT ;
    USE SIGNAL ;
    PORT
      LAYER M4 ;
        RECT  215.808 107.292 216 107.316 ;
    END
  END g_front_0_u_front__f_t2[231]
  PIN g_front_0_u_front__f_t2[232]
    DIRECTION OUTPUT ;
    USE SIGNAL ;
    PORT
      LAYER M4 ;
        RECT  215.808 107.772 216 107.796 ;
    END
  END g_front_0_u_front__f_t2[232]
  PIN g_front_0_u_front__f_t2[23]
    DIRECTION OUTPUT ;
    USE SIGNAL ;
    PORT
      LAYER M4 ;
        RECT  215.808 12.828 216 12.852 ;
    END
  END g_front_0_u_front__f_t2[23]
  PIN g_front_0_u_front__f_t2[24]
    DIRECTION OUTPUT ;
    USE SIGNAL ;
    PORT
      LAYER M4 ;
        RECT  215.808 13.26 216 13.284 ;
    END
  END g_front_0_u_front__f_t2[24]
  PIN g_front_0_u_front__f_t2[25]
    DIRECTION OUTPUT ;
    USE SIGNAL ;
    PORT
      LAYER M4 ;
        RECT  215.808 13.74 216 13.764 ;
    END
  END g_front_0_u_front__f_t2[25]
  PIN g_front_0_u_front__f_t2[26]
    DIRECTION OUTPUT ;
    USE SIGNAL ;
    PORT
      LAYER M4 ;
        RECT  215.808 14.172 216 14.196 ;
    END
  END g_front_0_u_front__f_t2[26]
  PIN g_front_0_u_front__f_t2[27]
    DIRECTION OUTPUT ;
    USE SIGNAL ;
    PORT
      LAYER M4 ;
        RECT  215.808 14.652 216 14.676 ;
    END
  END g_front_0_u_front__f_t2[27]
  PIN g_front_0_u_front__f_t2[28]
    DIRECTION OUTPUT ;
    USE SIGNAL ;
    PORT
      LAYER M4 ;
        RECT  215.808 15.084 216 15.108 ;
    END
  END g_front_0_u_front__f_t2[28]
  PIN g_front_0_u_front__f_t2[29]
    DIRECTION OUTPUT ;
    USE SIGNAL ;
    PORT
      LAYER M4 ;
        RECT  215.808 15.564 216 15.588 ;
    END
  END g_front_0_u_front__f_t2[29]
  PIN g_front_0_u_front__f_t2[2]
    DIRECTION OUTPUT ;
    USE SIGNAL ;
    PORT
      LAYER M4 ;
        RECT  215.808 3.276 216 3.3 ;
    END
  END g_front_0_u_front__f_t2[2]
  PIN g_front_0_u_front__f_t2[30]
    DIRECTION OUTPUT ;
    USE SIGNAL ;
    PORT
      LAYER M4 ;
        RECT  215.808 15.996 216 16.02 ;
    END
  END g_front_0_u_front__f_t2[30]
  PIN g_front_0_u_front__f_t2[31]
    DIRECTION OUTPUT ;
    USE SIGNAL ;
    PORT
      LAYER M4 ;
        RECT  215.808 16.476 216 16.5 ;
    END
  END g_front_0_u_front__f_t2[31]
  PIN g_front_0_u_front__f_t2[32]
    DIRECTION OUTPUT ;
    USE SIGNAL ;
    PORT
      LAYER M4 ;
        RECT  215.808 16.908 216 16.932 ;
    END
  END g_front_0_u_front__f_t2[32]
  PIN g_front_0_u_front__f_t2[33]
    DIRECTION OUTPUT ;
    USE SIGNAL ;
    PORT
      LAYER M4 ;
        RECT  215.808 17.388 216 17.412 ;
    END
  END g_front_0_u_front__f_t2[33]
  PIN g_front_0_u_front__f_t2[34]
    DIRECTION OUTPUT ;
    USE SIGNAL ;
    PORT
      LAYER M4 ;
        RECT  215.808 17.82 216 17.844 ;
    END
  END g_front_0_u_front__f_t2[34]
  PIN g_front_0_u_front__f_t2[35]
    DIRECTION OUTPUT ;
    USE SIGNAL ;
    PORT
      LAYER M4 ;
        RECT  215.808 18.252 216 18.276 ;
    END
  END g_front_0_u_front__f_t2[35]
  PIN g_front_0_u_front__f_t2[36]
    DIRECTION OUTPUT ;
    USE SIGNAL ;
    PORT
      LAYER M4 ;
        RECT  215.808 18.732 216 18.756 ;
    END
  END g_front_0_u_front__f_t2[36]
  PIN g_front_0_u_front__f_t2[37]
    DIRECTION OUTPUT ;
    USE SIGNAL ;
    PORT
      LAYER M4 ;
        RECT  215.808 19.164 216 19.188 ;
    END
  END g_front_0_u_front__f_t2[37]
  PIN g_front_0_u_front__f_t2[38]
    DIRECTION OUTPUT ;
    USE SIGNAL ;
    PORT
      LAYER M4 ;
        RECT  215.808 19.644 216 19.668 ;
    END
  END g_front_0_u_front__f_t2[38]
  PIN g_front_0_u_front__f_t2[39]
    DIRECTION OUTPUT ;
    USE SIGNAL ;
    PORT
      LAYER M4 ;
        RECT  215.808 20.076 216 20.1 ;
    END
  END g_front_0_u_front__f_t2[39]
  PIN g_front_0_u_front__f_t2[3]
    DIRECTION OUTPUT ;
    USE SIGNAL ;
    PORT
      LAYER M4 ;
        RECT  215.808 3.756 216 3.78 ;
    END
  END g_front_0_u_front__f_t2[3]
  PIN g_front_0_u_front__f_t2[40]
    DIRECTION OUTPUT ;
    USE SIGNAL ;
    PORT
      LAYER M4 ;
        RECT  215.808 20.556 216 20.58 ;
    END
  END g_front_0_u_front__f_t2[40]
  PIN g_front_0_u_front__f_t2[41]
    DIRECTION OUTPUT ;
    USE SIGNAL ;
    PORT
      LAYER M4 ;
        RECT  215.808 20.988 216 21.012 ;
    END
  END g_front_0_u_front__f_t2[41]
  PIN g_front_0_u_front__f_t2[42]
    DIRECTION OUTPUT ;
    USE SIGNAL ;
    PORT
      LAYER M4 ;
        RECT  215.808 21.468 216 21.492 ;
    END
  END g_front_0_u_front__f_t2[42]
  PIN g_front_0_u_front__f_t2[43]
    DIRECTION OUTPUT ;
    USE SIGNAL ;
    PORT
      LAYER M4 ;
        RECT  215.808 21.9 216 21.924 ;
    END
  END g_front_0_u_front__f_t2[43]
  PIN g_front_0_u_front__f_t2[44]
    DIRECTION OUTPUT ;
    USE SIGNAL ;
    PORT
      LAYER M4 ;
        RECT  215.808 22.38 216 22.404 ;
    END
  END g_front_0_u_front__f_t2[44]
  PIN g_front_0_u_front__f_t2[45]
    DIRECTION OUTPUT ;
    USE SIGNAL ;
    PORT
      LAYER M4 ;
        RECT  215.808 22.812 216 22.836 ;
    END
  END g_front_0_u_front__f_t2[45]
  PIN g_front_0_u_front__f_t2[46]
    DIRECTION OUTPUT ;
    USE SIGNAL ;
    PORT
      LAYER M4 ;
        RECT  215.808 23.292 216 23.316 ;
    END
  END g_front_0_u_front__f_t2[46]
  PIN g_front_0_u_front__f_t2[47]
    DIRECTION OUTPUT ;
    USE SIGNAL ;
    PORT
      LAYER M4 ;
        RECT  215.808 23.724 216 23.748 ;
    END
  END g_front_0_u_front__f_t2[47]
  PIN g_front_0_u_front__f_t2[48]
    DIRECTION OUTPUT ;
    USE SIGNAL ;
    PORT
      LAYER M4 ;
        RECT  215.808 24.156 216 24.18 ;
    END
  END g_front_0_u_front__f_t2[48]
  PIN g_front_0_u_front__f_t2[49]
    DIRECTION OUTPUT ;
    USE SIGNAL ;
    PORT
      LAYER M4 ;
        RECT  215.808 24.636 216 24.66 ;
    END
  END g_front_0_u_front__f_t2[49]
  PIN g_front_0_u_front__f_t2[4]
    DIRECTION OUTPUT ;
    USE SIGNAL ;
    PORT
      LAYER M4 ;
        RECT  215.808 4.188 216 4.212 ;
    END
  END g_front_0_u_front__f_t2[4]
  PIN g_front_0_u_front__f_t2[50]
    DIRECTION OUTPUT ;
    USE SIGNAL ;
    PORT
      LAYER M4 ;
        RECT  215.808 25.068 216 25.092 ;
    END
  END g_front_0_u_front__f_t2[50]
  PIN g_front_0_u_front__f_t2[51]
    DIRECTION OUTPUT ;
    USE SIGNAL ;
    PORT
      LAYER M4 ;
        RECT  215.808 25.548 216 25.572 ;
    END
  END g_front_0_u_front__f_t2[51]
  PIN g_front_0_u_front__f_t2[52]
    DIRECTION OUTPUT ;
    USE SIGNAL ;
    PORT
      LAYER M4 ;
        RECT  215.808 25.98 216 26.004 ;
    END
  END g_front_0_u_front__f_t2[52]
  PIN g_front_0_u_front__f_t2[53]
    DIRECTION OUTPUT ;
    USE SIGNAL ;
    PORT
      LAYER M4 ;
        RECT  215.808 26.46 216 26.484 ;
    END
  END g_front_0_u_front__f_t2[53]
  PIN g_front_0_u_front__f_t2[54]
    DIRECTION OUTPUT ;
    USE SIGNAL ;
    PORT
      LAYER M4 ;
        RECT  215.808 26.892 216 26.916 ;
    END
  END g_front_0_u_front__f_t2[54]
  PIN g_front_0_u_front__f_t2[55]
    DIRECTION OUTPUT ;
    USE SIGNAL ;
    PORT
      LAYER M4 ;
        RECT  215.808 27.372 216 27.396 ;
    END
  END g_front_0_u_front__f_t2[55]
  PIN g_front_0_u_front__f_t2[56]
    DIRECTION OUTPUT ;
    USE SIGNAL ;
    PORT
      LAYER M4 ;
        RECT  215.808 27.804 216 27.828 ;
    END
  END g_front_0_u_front__f_t2[56]
  PIN g_front_0_u_front__f_t2[57]
    DIRECTION OUTPUT ;
    USE SIGNAL ;
    PORT
      LAYER M4 ;
        RECT  215.808 28.284 216 28.308 ;
    END
  END g_front_0_u_front__f_t2[57]
  PIN g_front_0_u_front__f_t2[58]
    DIRECTION OUTPUT ;
    USE SIGNAL ;
    PORT
      LAYER M4 ;
        RECT  215.808 28.716 216 28.74 ;
    END
  END g_front_0_u_front__f_t2[58]
  PIN g_front_0_u_front__f_t2[59]
    DIRECTION OUTPUT ;
    USE SIGNAL ;
    PORT
      LAYER M4 ;
        RECT  215.808 29.196 216 29.22 ;
    END
  END g_front_0_u_front__f_t2[59]
  PIN g_front_0_u_front__f_t2[5]
    DIRECTION OUTPUT ;
    USE SIGNAL ;
    PORT
      LAYER M4 ;
        RECT  215.808 4.668 216 4.692 ;
    END
  END g_front_0_u_front__f_t2[5]
  PIN g_front_0_u_front__f_t2[60]
    DIRECTION OUTPUT ;
    USE SIGNAL ;
    PORT
      LAYER M4 ;
        RECT  215.808 29.628 216 29.652 ;
    END
  END g_front_0_u_front__f_t2[60]
  PIN g_front_0_u_front__f_t2[61]
    DIRECTION OUTPUT ;
    USE SIGNAL ;
    PORT
      LAYER M4 ;
        RECT  215.808 30.108 216 30.132 ;
    END
  END g_front_0_u_front__f_t2[61]
  PIN g_front_0_u_front__f_t2[62]
    DIRECTION OUTPUT ;
    USE SIGNAL ;
    PORT
      LAYER M4 ;
        RECT  215.808 30.54 216 30.564 ;
    END
  END g_front_0_u_front__f_t2[62]
  PIN g_front_0_u_front__f_t2[63]
    DIRECTION OUTPUT ;
    USE SIGNAL ;
    PORT
      LAYER M4 ;
        RECT  215.808 30.972 216 30.996 ;
    END
  END g_front_0_u_front__f_t2[63]
  PIN g_front_0_u_front__f_t2[64]
    DIRECTION OUTPUT ;
    USE SIGNAL ;
    PORT
      LAYER M4 ;
        RECT  215.808 31.452 216 31.476 ;
    END
  END g_front_0_u_front__f_t2[64]
  PIN g_front_0_u_front__f_t2[65]
    DIRECTION OUTPUT ;
    USE SIGNAL ;
    PORT
      LAYER M4 ;
        RECT  215.808 31.884 216 31.908 ;
    END
  END g_front_0_u_front__f_t2[65]
  PIN g_front_0_u_front__f_t2[66]
    DIRECTION OUTPUT ;
    USE SIGNAL ;
    PORT
      LAYER M4 ;
        RECT  215.808 32.364 216 32.388 ;
    END
  END g_front_0_u_front__f_t2[66]
  PIN g_front_0_u_front__f_t2[67]
    DIRECTION OUTPUT ;
    USE SIGNAL ;
    PORT
      LAYER M4 ;
        RECT  215.808 32.796 216 32.82 ;
    END
  END g_front_0_u_front__f_t2[67]
  PIN g_front_0_u_front__f_t2[68]
    DIRECTION OUTPUT ;
    USE SIGNAL ;
    PORT
      LAYER M4 ;
        RECT  215.808 33.276 216 33.3 ;
    END
  END g_front_0_u_front__f_t2[68]
  PIN g_front_0_u_front__f_t2[69]
    DIRECTION OUTPUT ;
    USE SIGNAL ;
    PORT
      LAYER M4 ;
        RECT  215.808 33.708 216 33.732 ;
    END
  END g_front_0_u_front__f_t2[69]
  PIN g_front_0_u_front__f_t2[6]
    DIRECTION OUTPUT ;
    USE SIGNAL ;
    PORT
      LAYER M4 ;
        RECT  215.808 5.1 216 5.124 ;
    END
  END g_front_0_u_front__f_t2[6]
  PIN g_front_0_u_front__f_t2[70]
    DIRECTION OUTPUT ;
    USE SIGNAL ;
    PORT
      LAYER M4 ;
        RECT  215.808 34.188 216 34.212 ;
    END
  END g_front_0_u_front__f_t2[70]
  PIN g_front_0_u_front__f_t2[71]
    DIRECTION OUTPUT ;
    USE SIGNAL ;
    PORT
      LAYER M4 ;
        RECT  215.808 34.62 216 34.644 ;
    END
  END g_front_0_u_front__f_t2[71]
  PIN g_front_0_u_front__f_t2[72]
    DIRECTION OUTPUT ;
    USE SIGNAL ;
    PORT
      LAYER M4 ;
        RECT  215.808 35.1 216 35.124 ;
    END
  END g_front_0_u_front__f_t2[72]
  PIN g_front_0_u_front__f_t2[73]
    DIRECTION OUTPUT ;
    USE SIGNAL ;
    PORT
      LAYER M4 ;
        RECT  215.808 35.532 216 35.556 ;
    END
  END g_front_0_u_front__f_t2[73]
  PIN g_front_0_u_front__f_t2[74]
    DIRECTION OUTPUT ;
    USE SIGNAL ;
    PORT
      LAYER M4 ;
        RECT  215.808 36.012 216 36.036 ;
    END
  END g_front_0_u_front__f_t2[74]
  PIN g_front_0_u_front__f_t2[75]
    DIRECTION OUTPUT ;
    USE SIGNAL ;
    PORT
      LAYER M4 ;
        RECT  215.808 36.444 216 36.468 ;
    END
  END g_front_0_u_front__f_t2[75]
  PIN g_front_0_u_front__f_t2[76]
    DIRECTION OUTPUT ;
    USE SIGNAL ;
    PORT
      LAYER M4 ;
        RECT  215.808 36.876 216 36.9 ;
    END
  END g_front_0_u_front__f_t2[76]
  PIN g_front_0_u_front__f_t2[77]
    DIRECTION OUTPUT ;
    USE SIGNAL ;
    PORT
      LAYER M4 ;
        RECT  215.808 37.356 216 37.38 ;
    END
  END g_front_0_u_front__f_t2[77]
  PIN g_front_0_u_front__f_t2[78]
    DIRECTION OUTPUT ;
    USE SIGNAL ;
    PORT
      LAYER M4 ;
        RECT  215.808 37.788 216 37.812 ;
    END
  END g_front_0_u_front__f_t2[78]
  PIN g_front_0_u_front__f_t2[79]
    DIRECTION OUTPUT ;
    USE SIGNAL ;
    PORT
      LAYER M4 ;
        RECT  215.808 38.268 216 38.292 ;
    END
  END g_front_0_u_front__f_t2[79]
  PIN g_front_0_u_front__f_t2[7]
    DIRECTION OUTPUT ;
    USE SIGNAL ;
    PORT
      LAYER M4 ;
        RECT  215.808 5.532 216 5.556 ;
    END
  END g_front_0_u_front__f_t2[7]
  PIN g_front_0_u_front__f_t2[80]
    DIRECTION OUTPUT ;
    USE SIGNAL ;
    PORT
      LAYER M4 ;
        RECT  215.808 38.7 216 38.724 ;
    END
  END g_front_0_u_front__f_t2[80]
  PIN g_front_0_u_front__f_t2[81]
    DIRECTION OUTPUT ;
    USE SIGNAL ;
    PORT
      LAYER M4 ;
        RECT  215.808 39.18 216 39.204 ;
    END
  END g_front_0_u_front__f_t2[81]
  PIN g_front_0_u_front__f_t2[82]
    DIRECTION OUTPUT ;
    USE SIGNAL ;
    PORT
      LAYER M4 ;
        RECT  215.808 39.612 216 39.636 ;
    END
  END g_front_0_u_front__f_t2[82]
  PIN g_front_0_u_front__f_t2[83]
    DIRECTION OUTPUT ;
    USE SIGNAL ;
    PORT
      LAYER M4 ;
        RECT  215.808 40.092 216 40.116 ;
    END
  END g_front_0_u_front__f_t2[83]
  PIN g_front_0_u_front__f_t2[84]
    DIRECTION OUTPUT ;
    USE SIGNAL ;
    PORT
      LAYER M4 ;
        RECT  215.808 40.524 216 40.548 ;
    END
  END g_front_0_u_front__f_t2[84]
  PIN g_front_0_u_front__f_t2[85]
    DIRECTION OUTPUT ;
    USE SIGNAL ;
    PORT
      LAYER M4 ;
        RECT  215.808 41.004 216 41.028 ;
    END
  END g_front_0_u_front__f_t2[85]
  PIN g_front_0_u_front__f_t2[86]
    DIRECTION OUTPUT ;
    USE SIGNAL ;
    PORT
      LAYER M4 ;
        RECT  215.808 41.436 216 41.46 ;
    END
  END g_front_0_u_front__f_t2[86]
  PIN g_front_0_u_front__f_t2[87]
    DIRECTION OUTPUT ;
    USE SIGNAL ;
    PORT
      LAYER M4 ;
        RECT  215.808 41.916 216 41.94 ;
    END
  END g_front_0_u_front__f_t2[87]
  PIN g_front_0_u_front__f_t2[88]
    DIRECTION OUTPUT ;
    USE SIGNAL ;
    PORT
      LAYER M4 ;
        RECT  215.808 42.348 216 42.372 ;
    END
  END g_front_0_u_front__f_t2[88]
  PIN g_front_0_u_front__f_t2[89]
    DIRECTION OUTPUT ;
    USE SIGNAL ;
    PORT
      LAYER M4 ;
        RECT  215.808 42.78 216 42.804 ;
    END
  END g_front_0_u_front__f_t2[89]
  PIN g_front_0_u_front__f_t2[8]
    DIRECTION OUTPUT ;
    USE SIGNAL ;
    PORT
      LAYER M4 ;
        RECT  215.808 6.012 216 6.036 ;
    END
  END g_front_0_u_front__f_t2[8]
  PIN g_front_0_u_front__f_t2[90]
    DIRECTION OUTPUT ;
    USE SIGNAL ;
    PORT
      LAYER M4 ;
        RECT  215.808 43.26 216 43.284 ;
    END
  END g_front_0_u_front__f_t2[90]
  PIN g_front_0_u_front__f_t2[91]
    DIRECTION OUTPUT ;
    USE SIGNAL ;
    PORT
      LAYER M4 ;
        RECT  215.808 43.692 216 43.716 ;
    END
  END g_front_0_u_front__f_t2[91]
  PIN g_front_0_u_front__f_t2[92]
    DIRECTION OUTPUT ;
    USE SIGNAL ;
    PORT
      LAYER M4 ;
        RECT  215.808 44.172 216 44.196 ;
    END
  END g_front_0_u_front__f_t2[92]
  PIN g_front_0_u_front__f_t2[93]
    DIRECTION OUTPUT ;
    USE SIGNAL ;
    PORT
      LAYER M4 ;
        RECT  215.808 44.604 216 44.628 ;
    END
  END g_front_0_u_front__f_t2[93]
  PIN g_front_0_u_front__f_t2[94]
    DIRECTION OUTPUT ;
    USE SIGNAL ;
    PORT
      LAYER M4 ;
        RECT  215.808 45.084 216 45.108 ;
    END
  END g_front_0_u_front__f_t2[94]
  PIN g_front_0_u_front__f_t2[95]
    DIRECTION OUTPUT ;
    USE SIGNAL ;
    PORT
      LAYER M4 ;
        RECT  215.808 45.516 216 45.54 ;
    END
  END g_front_0_u_front__f_t2[95]
  PIN g_front_0_u_front__f_t2[96]
    DIRECTION OUTPUT ;
    USE SIGNAL ;
    PORT
      LAYER M4 ;
        RECT  215.808 45.996 216 46.02 ;
    END
  END g_front_0_u_front__f_t2[96]
  PIN g_front_0_u_front__f_t2[97]
    DIRECTION OUTPUT ;
    USE SIGNAL ;
    PORT
      LAYER M4 ;
        RECT  215.808 46.428 216 46.452 ;
    END
  END g_front_0_u_front__f_t2[97]
  PIN g_front_0_u_front__f_t2[98]
    DIRECTION OUTPUT ;
    USE SIGNAL ;
    PORT
      LAYER M4 ;
        RECT  215.808 46.908 216 46.932 ;
    END
  END g_front_0_u_front__f_t2[98]
  PIN g_front_0_u_front__f_t2[99]
    DIRECTION OUTPUT ;
    USE SIGNAL ;
    PORT
      LAYER M4 ;
        RECT  215.808 47.34 216 47.364 ;
    END
  END g_front_0_u_front__f_t2[99]
  PIN g_front_0_u_front__f_t2[9]
    DIRECTION OUTPUT ;
    USE SIGNAL ;
    PORT
      LAYER M4 ;
        RECT  215.808 6.444 216 6.468 ;
    END
  END g_front_0_u_front__f_t2[9]
  PIN g_front_0_u_front__f_t3[0]
    DIRECTION OUTPUT ;
    USE SIGNAL ;
    PORT
      LAYER M4 ;
        RECT  215.808 108.204 216 108.228 ;
    END
  END g_front_0_u_front__f_t3[0]
  PIN g_front_0_u_front__f_t3[100]
    DIRECTION OUTPUT ;
    USE SIGNAL ;
    PORT
      LAYER M4 ;
        RECT  215.808 153.66 216 153.684 ;
    END
  END g_front_0_u_front__f_t3[100]
  PIN g_front_0_u_front__f_t3[101]
    DIRECTION OUTPUT ;
    USE SIGNAL ;
    PORT
      LAYER M4 ;
        RECT  215.808 154.092 216 154.116 ;
    END
  END g_front_0_u_front__f_t3[101]
  PIN g_front_0_u_front__f_t3[102]
    DIRECTION OUTPUT ;
    USE SIGNAL ;
    PORT
      LAYER M4 ;
        RECT  215.808 154.572 216 154.596 ;
    END
  END g_front_0_u_front__f_t3[102]
  PIN g_front_0_u_front__f_t3[103]
    DIRECTION OUTPUT ;
    USE SIGNAL ;
    PORT
      LAYER M4 ;
        RECT  215.808 155.004 216 155.028 ;
    END
  END g_front_0_u_front__f_t3[103]
  PIN g_front_0_u_front__f_t3[104]
    DIRECTION OUTPUT ;
    USE SIGNAL ;
    PORT
      LAYER M4 ;
        RECT  215.808 155.436 216 155.46 ;
    END
  END g_front_0_u_front__f_t3[104]
  PIN g_front_0_u_front__f_t3[105]
    DIRECTION OUTPUT ;
    USE SIGNAL ;
    PORT
      LAYER M4 ;
        RECT  215.808 155.916 216 155.94 ;
    END
  END g_front_0_u_front__f_t3[105]
  PIN g_front_0_u_front__f_t3[106]
    DIRECTION OUTPUT ;
    USE SIGNAL ;
    PORT
      LAYER M4 ;
        RECT  215.808 156.348 216 156.372 ;
    END
  END g_front_0_u_front__f_t3[106]
  PIN g_front_0_u_front__f_t3[107]
    DIRECTION OUTPUT ;
    USE SIGNAL ;
    PORT
      LAYER M4 ;
        RECT  215.808 156.828 216 156.852 ;
    END
  END g_front_0_u_front__f_t3[107]
  PIN g_front_0_u_front__f_t3[108]
    DIRECTION OUTPUT ;
    USE SIGNAL ;
    PORT
      LAYER M4 ;
        RECT  215.808 157.26 216 157.284 ;
    END
  END g_front_0_u_front__f_t3[108]
  PIN g_front_0_u_front__f_t3[109]
    DIRECTION OUTPUT ;
    USE SIGNAL ;
    PORT
      LAYER M4 ;
        RECT  215.808 157.74 216 157.764 ;
    END
  END g_front_0_u_front__f_t3[109]
  PIN g_front_0_u_front__f_t3[10]
    DIRECTION OUTPUT ;
    USE SIGNAL ;
    PORT
      LAYER M4 ;
        RECT  215.808 112.764 216 112.788 ;
    END
  END g_front_0_u_front__f_t3[10]
  PIN g_front_0_u_front__f_t3[110]
    DIRECTION OUTPUT ;
    USE SIGNAL ;
    PORT
      LAYER M4 ;
        RECT  215.808 158.172 216 158.196 ;
    END
  END g_front_0_u_front__f_t3[110]
  PIN g_front_0_u_front__f_t3[111]
    DIRECTION OUTPUT ;
    USE SIGNAL ;
    PORT
      LAYER M4 ;
        RECT  215.808 158.652 216 158.676 ;
    END
  END g_front_0_u_front__f_t3[111]
  PIN g_front_0_u_front__f_t3[112]
    DIRECTION OUTPUT ;
    USE SIGNAL ;
    PORT
      LAYER M4 ;
        RECT  215.808 159.084 216 159.108 ;
    END
  END g_front_0_u_front__f_t3[112]
  PIN g_front_0_u_front__f_t3[113]
    DIRECTION OUTPUT ;
    USE SIGNAL ;
    PORT
      LAYER M4 ;
        RECT  215.808 159.564 216 159.588 ;
    END
  END g_front_0_u_front__f_t3[113]
  PIN g_front_0_u_front__f_t3[114]
    DIRECTION OUTPUT ;
    USE SIGNAL ;
    PORT
      LAYER M4 ;
        RECT  215.808 159.996 216 160.02 ;
    END
  END g_front_0_u_front__f_t3[114]
  PIN g_front_0_u_front__f_t3[115]
    DIRECTION OUTPUT ;
    USE SIGNAL ;
    PORT
      LAYER M4 ;
        RECT  215.808 160.476 216 160.5 ;
    END
  END g_front_0_u_front__f_t3[115]
  PIN g_front_0_u_front__f_t3[116]
    DIRECTION OUTPUT ;
    USE SIGNAL ;
    PORT
      LAYER M4 ;
        RECT  215.808 160.908 216 160.932 ;
    END
  END g_front_0_u_front__f_t3[116]
  PIN g_front_0_u_front__f_t3[117]
    DIRECTION OUTPUT ;
    USE SIGNAL ;
    PORT
      LAYER M4 ;
        RECT  215.808 161.34 216 161.364 ;
    END
  END g_front_0_u_front__f_t3[117]
  PIN g_front_0_u_front__f_t3[118]
    DIRECTION OUTPUT ;
    USE SIGNAL ;
    PORT
      LAYER M4 ;
        RECT  215.808 161.82 216 161.844 ;
    END
  END g_front_0_u_front__f_t3[118]
  PIN g_front_0_u_front__f_t3[119]
    DIRECTION OUTPUT ;
    USE SIGNAL ;
    PORT
      LAYER M4 ;
        RECT  215.808 162.252 216 162.276 ;
    END
  END g_front_0_u_front__f_t3[119]
  PIN g_front_0_u_front__f_t3[11]
    DIRECTION OUTPUT ;
    USE SIGNAL ;
    PORT
      LAYER M4 ;
        RECT  215.808 113.196 216 113.22 ;
    END
  END g_front_0_u_front__f_t3[11]
  PIN g_front_0_u_front__f_t3[120]
    DIRECTION OUTPUT ;
    USE SIGNAL ;
    PORT
      LAYER M4 ;
        RECT  215.808 162.732 216 162.756 ;
    END
  END g_front_0_u_front__f_t3[120]
  PIN g_front_0_u_front__f_t3[121]
    DIRECTION OUTPUT ;
    USE SIGNAL ;
    PORT
      LAYER M4 ;
        RECT  215.808 163.164 216 163.188 ;
    END
  END g_front_0_u_front__f_t3[121]
  PIN g_front_0_u_front__f_t3[122]
    DIRECTION OUTPUT ;
    USE SIGNAL ;
    PORT
      LAYER M4 ;
        RECT  215.808 163.644 216 163.668 ;
    END
  END g_front_0_u_front__f_t3[122]
  PIN g_front_0_u_front__f_t3[123]
    DIRECTION OUTPUT ;
    USE SIGNAL ;
    PORT
      LAYER M4 ;
        RECT  215.808 164.076 216 164.1 ;
    END
  END g_front_0_u_front__f_t3[123]
  PIN g_front_0_u_front__f_t3[124]
    DIRECTION OUTPUT ;
    USE SIGNAL ;
    PORT
      LAYER M4 ;
        RECT  215.808 164.556 216 164.58 ;
    END
  END g_front_0_u_front__f_t3[124]
  PIN g_front_0_u_front__f_t3[125]
    DIRECTION OUTPUT ;
    USE SIGNAL ;
    PORT
      LAYER M4 ;
        RECT  215.808 164.988 216 165.012 ;
    END
  END g_front_0_u_front__f_t3[125]
  PIN g_front_0_u_front__f_t3[126]
    DIRECTION OUTPUT ;
    USE SIGNAL ;
    PORT
      LAYER M4 ;
        RECT  215.808 165.468 216 165.492 ;
    END
  END g_front_0_u_front__f_t3[126]
  PIN g_front_0_u_front__f_t3[127]
    DIRECTION OUTPUT ;
    USE SIGNAL ;
    PORT
      LAYER M4 ;
        RECT  215.808 165.9 216 165.924 ;
    END
  END g_front_0_u_front__f_t3[127]
  PIN g_front_0_u_front__f_t3[128]
    DIRECTION OUTPUT ;
    USE SIGNAL ;
    PORT
      LAYER M4 ;
        RECT  215.808 166.38 216 166.404 ;
    END
  END g_front_0_u_front__f_t3[128]
  PIN g_front_0_u_front__f_t3[129]
    DIRECTION OUTPUT ;
    USE SIGNAL ;
    PORT
      LAYER M4 ;
        RECT  215.808 166.812 216 166.836 ;
    END
  END g_front_0_u_front__f_t3[129]
  PIN g_front_0_u_front__f_t3[12]
    DIRECTION OUTPUT ;
    USE SIGNAL ;
    PORT
      LAYER M4 ;
        RECT  215.808 113.676 216 113.7 ;
    END
  END g_front_0_u_front__f_t3[12]
  PIN g_front_0_u_front__f_t3[130]
    DIRECTION OUTPUT ;
    USE SIGNAL ;
    PORT
      LAYER M4 ;
        RECT  215.808 167.244 216 167.268 ;
    END
  END g_front_0_u_front__f_t3[130]
  PIN g_front_0_u_front__f_t3[131]
    DIRECTION OUTPUT ;
    USE SIGNAL ;
    PORT
      LAYER M4 ;
        RECT  215.808 167.724 216 167.748 ;
    END
  END g_front_0_u_front__f_t3[131]
  PIN g_front_0_u_front__f_t3[132]
    DIRECTION OUTPUT ;
    USE SIGNAL ;
    PORT
      LAYER M4 ;
        RECT  215.808 168.156 216 168.18 ;
    END
  END g_front_0_u_front__f_t3[132]
  PIN g_front_0_u_front__f_t3[133]
    DIRECTION OUTPUT ;
    USE SIGNAL ;
    PORT
      LAYER M4 ;
        RECT  215.808 168.636 216 168.66 ;
    END
  END g_front_0_u_front__f_t3[133]
  PIN g_front_0_u_front__f_t3[134]
    DIRECTION OUTPUT ;
    USE SIGNAL ;
    PORT
      LAYER M4 ;
        RECT  215.808 169.068 216 169.092 ;
    END
  END g_front_0_u_front__f_t3[134]
  PIN g_front_0_u_front__f_t3[135]
    DIRECTION OUTPUT ;
    USE SIGNAL ;
    PORT
      LAYER M4 ;
        RECT  215.808 169.548 216 169.572 ;
    END
  END g_front_0_u_front__f_t3[135]
  PIN g_front_0_u_front__f_t3[136]
    DIRECTION OUTPUT ;
    USE SIGNAL ;
    PORT
      LAYER M4 ;
        RECT  215.808 169.98 216 170.004 ;
    END
  END g_front_0_u_front__f_t3[136]
  PIN g_front_0_u_front__f_t3[137]
    DIRECTION OUTPUT ;
    USE SIGNAL ;
    PORT
      LAYER M4 ;
        RECT  215.808 170.46 216 170.484 ;
    END
  END g_front_0_u_front__f_t3[137]
  PIN g_front_0_u_front__f_t3[138]
    DIRECTION OUTPUT ;
    USE SIGNAL ;
    PORT
      LAYER M4 ;
        RECT  215.808 170.892 216 170.916 ;
    END
  END g_front_0_u_front__f_t3[138]
  PIN g_front_0_u_front__f_t3[139]
    DIRECTION OUTPUT ;
    USE SIGNAL ;
    PORT
      LAYER M4 ;
        RECT  215.808 171.372 216 171.396 ;
    END
  END g_front_0_u_front__f_t3[139]
  PIN g_front_0_u_front__f_t3[13]
    DIRECTION OUTPUT ;
    USE SIGNAL ;
    PORT
      LAYER M4 ;
        RECT  215.808 114.108 216 114.132 ;
    END
  END g_front_0_u_front__f_t3[13]
  PIN g_front_0_u_front__f_t3[140]
    DIRECTION OUTPUT ;
    USE SIGNAL ;
    PORT
      LAYER M4 ;
        RECT  215.808 171.804 216 171.828 ;
    END
  END g_front_0_u_front__f_t3[140]
  PIN g_front_0_u_front__f_t3[141]
    DIRECTION OUTPUT ;
    USE SIGNAL ;
    PORT
      LAYER M4 ;
        RECT  215.808 172.284 216 172.308 ;
    END
  END g_front_0_u_front__f_t3[141]
  PIN g_front_0_u_front__f_t3[142]
    DIRECTION OUTPUT ;
    USE SIGNAL ;
    PORT
      LAYER M4 ;
        RECT  215.808 172.716 216 172.74 ;
    END
  END g_front_0_u_front__f_t3[142]
  PIN g_front_0_u_front__f_t3[143]
    DIRECTION OUTPUT ;
    USE SIGNAL ;
    PORT
      LAYER M4 ;
        RECT  215.808 173.196 216 173.22 ;
    END
  END g_front_0_u_front__f_t3[143]
  PIN g_front_0_u_front__f_t3[144]
    DIRECTION OUTPUT ;
    USE SIGNAL ;
    PORT
      LAYER M4 ;
        RECT  215.808 173.628 216 173.652 ;
    END
  END g_front_0_u_front__f_t3[144]
  PIN g_front_0_u_front__f_t3[145]
    DIRECTION OUTPUT ;
    USE SIGNAL ;
    PORT
      LAYER M4 ;
        RECT  215.808 174.06 216 174.084 ;
    END
  END g_front_0_u_front__f_t3[145]
  PIN g_front_0_u_front__f_t3[146]
    DIRECTION OUTPUT ;
    USE SIGNAL ;
    PORT
      LAYER M4 ;
        RECT  215.808 174.54 216 174.564 ;
    END
  END g_front_0_u_front__f_t3[146]
  PIN g_front_0_u_front__f_t3[147]
    DIRECTION OUTPUT ;
    USE SIGNAL ;
    PORT
      LAYER M4 ;
        RECT  215.808 174.972 216 174.996 ;
    END
  END g_front_0_u_front__f_t3[147]
  PIN g_front_0_u_front__f_t3[148]
    DIRECTION OUTPUT ;
    USE SIGNAL ;
    PORT
      LAYER M4 ;
        RECT  215.808 175.452 216 175.476 ;
    END
  END g_front_0_u_front__f_t3[148]
  PIN g_front_0_u_front__f_t3[149]
    DIRECTION OUTPUT ;
    USE SIGNAL ;
    PORT
      LAYER M4 ;
        RECT  215.808 175.884 216 175.908 ;
    END
  END g_front_0_u_front__f_t3[149]
  PIN g_front_0_u_front__f_t3[14]
    DIRECTION OUTPUT ;
    USE SIGNAL ;
    PORT
      LAYER M4 ;
        RECT  215.808 114.588 216 114.612 ;
    END
  END g_front_0_u_front__f_t3[14]
  PIN g_front_0_u_front__f_t3[150]
    DIRECTION OUTPUT ;
    USE SIGNAL ;
    PORT
      LAYER M4 ;
        RECT  215.808 176.364 216 176.388 ;
    END
  END g_front_0_u_front__f_t3[150]
  PIN g_front_0_u_front__f_t3[151]
    DIRECTION OUTPUT ;
    USE SIGNAL ;
    PORT
      LAYER M4 ;
        RECT  215.808 176.796 216 176.82 ;
    END
  END g_front_0_u_front__f_t3[151]
  PIN g_front_0_u_front__f_t3[152]
    DIRECTION OUTPUT ;
    USE SIGNAL ;
    PORT
      LAYER M4 ;
        RECT  215.808 177.276 216 177.3 ;
    END
  END g_front_0_u_front__f_t3[152]
  PIN g_front_0_u_front__f_t3[153]
    DIRECTION OUTPUT ;
    USE SIGNAL ;
    PORT
      LAYER M4 ;
        RECT  215.808 177.708 216 177.732 ;
    END
  END g_front_0_u_front__f_t3[153]
  PIN g_front_0_u_front__f_t3[154]
    DIRECTION OUTPUT ;
    USE SIGNAL ;
    PORT
      LAYER M4 ;
        RECT  215.808 178.188 216 178.212 ;
    END
  END g_front_0_u_front__f_t3[154]
  PIN g_front_0_u_front__f_t3[155]
    DIRECTION OUTPUT ;
    USE SIGNAL ;
    PORT
      LAYER M4 ;
        RECT  215.808 178.62 216 178.644 ;
    END
  END g_front_0_u_front__f_t3[155]
  PIN g_front_0_u_front__f_t3[156]
    DIRECTION OUTPUT ;
    USE SIGNAL ;
    PORT
      LAYER M4 ;
        RECT  215.808 179.1 216 179.124 ;
    END
  END g_front_0_u_front__f_t3[156]
  PIN g_front_0_u_front__f_t3[157]
    DIRECTION OUTPUT ;
    USE SIGNAL ;
    PORT
      LAYER M4 ;
        RECT  215.808 179.532 216 179.556 ;
    END
  END g_front_0_u_front__f_t3[157]
  PIN g_front_0_u_front__f_t3[158]
    DIRECTION OUTPUT ;
    USE SIGNAL ;
    PORT
      LAYER M4 ;
        RECT  215.808 179.964 216 179.988 ;
    END
  END g_front_0_u_front__f_t3[158]
  PIN g_front_0_u_front__f_t3[159]
    DIRECTION OUTPUT ;
    USE SIGNAL ;
    PORT
      LAYER M4 ;
        RECT  215.808 180.444 216 180.468 ;
    END
  END g_front_0_u_front__f_t3[159]
  PIN g_front_0_u_front__f_t3[15]
    DIRECTION OUTPUT ;
    USE SIGNAL ;
    PORT
      LAYER M4 ;
        RECT  215.808 115.02 216 115.044 ;
    END
  END g_front_0_u_front__f_t3[15]
  PIN g_front_0_u_front__f_t3[160]
    DIRECTION OUTPUT ;
    USE SIGNAL ;
    PORT
      LAYER M4 ;
        RECT  215.808 180.876 216 180.9 ;
    END
  END g_front_0_u_front__f_t3[160]
  PIN g_front_0_u_front__f_t3[161]
    DIRECTION OUTPUT ;
    USE SIGNAL ;
    PORT
      LAYER M4 ;
        RECT  215.808 181.356 216 181.38 ;
    END
  END g_front_0_u_front__f_t3[161]
  PIN g_front_0_u_front__f_t3[162]
    DIRECTION OUTPUT ;
    USE SIGNAL ;
    PORT
      LAYER M4 ;
        RECT  215.808 181.788 216 181.812 ;
    END
  END g_front_0_u_front__f_t3[162]
  PIN g_front_0_u_front__f_t3[163]
    DIRECTION OUTPUT ;
    USE SIGNAL ;
    PORT
      LAYER M4 ;
        RECT  215.808 182.268 216 182.292 ;
    END
  END g_front_0_u_front__f_t3[163]
  PIN g_front_0_u_front__f_t3[164]
    DIRECTION OUTPUT ;
    USE SIGNAL ;
    PORT
      LAYER M4 ;
        RECT  215.808 182.7 216 182.724 ;
    END
  END g_front_0_u_front__f_t3[164]
  PIN g_front_0_u_front__f_t3[165]
    DIRECTION OUTPUT ;
    USE SIGNAL ;
    PORT
      LAYER M4 ;
        RECT  215.808 183.18 216 183.204 ;
    END
  END g_front_0_u_front__f_t3[165]
  PIN g_front_0_u_front__f_t3[166]
    DIRECTION OUTPUT ;
    USE SIGNAL ;
    PORT
      LAYER M4 ;
        RECT  215.808 183.612 216 183.636 ;
    END
  END g_front_0_u_front__f_t3[166]
  PIN g_front_0_u_front__f_t3[167]
    DIRECTION OUTPUT ;
    USE SIGNAL ;
    PORT
      LAYER M4 ;
        RECT  215.808 184.092 216 184.116 ;
    END
  END g_front_0_u_front__f_t3[167]
  PIN g_front_0_u_front__f_t3[168]
    DIRECTION OUTPUT ;
    USE SIGNAL ;
    PORT
      LAYER M4 ;
        RECT  215.808 184.524 216 184.548 ;
    END
  END g_front_0_u_front__f_t3[168]
  PIN g_front_0_u_front__f_t3[169]
    DIRECTION OUTPUT ;
    USE SIGNAL ;
    PORT
      LAYER M4 ;
        RECT  215.808 185.004 216 185.028 ;
    END
  END g_front_0_u_front__f_t3[169]
  PIN g_front_0_u_front__f_t3[16]
    DIRECTION OUTPUT ;
    USE SIGNAL ;
    PORT
      LAYER M4 ;
        RECT  215.808 115.5 216 115.524 ;
    END
  END g_front_0_u_front__f_t3[16]
  PIN g_front_0_u_front__f_t3[170]
    DIRECTION OUTPUT ;
    USE SIGNAL ;
    PORT
      LAYER M4 ;
        RECT  215.808 185.436 216 185.46 ;
    END
  END g_front_0_u_front__f_t3[170]
  PIN g_front_0_u_front__f_t3[171]
    DIRECTION OUTPUT ;
    USE SIGNAL ;
    PORT
      LAYER M4 ;
        RECT  215.808 185.868 216 185.892 ;
    END
  END g_front_0_u_front__f_t3[171]
  PIN g_front_0_u_front__f_t3[172]
    DIRECTION OUTPUT ;
    USE SIGNAL ;
    PORT
      LAYER M4 ;
        RECT  215.808 186.348 216 186.372 ;
    END
  END g_front_0_u_front__f_t3[172]
  PIN g_front_0_u_front__f_t3[173]
    DIRECTION OUTPUT ;
    USE SIGNAL ;
    PORT
      LAYER M4 ;
        RECT  215.808 186.78 216 186.804 ;
    END
  END g_front_0_u_front__f_t3[173]
  PIN g_front_0_u_front__f_t3[174]
    DIRECTION OUTPUT ;
    USE SIGNAL ;
    PORT
      LAYER M4 ;
        RECT  215.808 187.26 216 187.284 ;
    END
  END g_front_0_u_front__f_t3[174]
  PIN g_front_0_u_front__f_t3[175]
    DIRECTION OUTPUT ;
    USE SIGNAL ;
    PORT
      LAYER M4 ;
        RECT  215.808 187.692 216 187.716 ;
    END
  END g_front_0_u_front__f_t3[175]
  PIN g_front_0_u_front__f_t3[176]
    DIRECTION OUTPUT ;
    USE SIGNAL ;
    PORT
      LAYER M4 ;
        RECT  215.808 188.172 216 188.196 ;
    END
  END g_front_0_u_front__f_t3[176]
  PIN g_front_0_u_front__f_t3[177]
    DIRECTION OUTPUT ;
    USE SIGNAL ;
    PORT
      LAYER M4 ;
        RECT  215.808 188.604 216 188.628 ;
    END
  END g_front_0_u_front__f_t3[177]
  PIN g_front_0_u_front__f_t3[178]
    DIRECTION OUTPUT ;
    USE SIGNAL ;
    PORT
      LAYER M4 ;
        RECT  215.808 189.084 216 189.108 ;
    END
  END g_front_0_u_front__f_t3[178]
  PIN g_front_0_u_front__f_t3[179]
    DIRECTION OUTPUT ;
    USE SIGNAL ;
    PORT
      LAYER M4 ;
        RECT  215.808 189.516 216 189.54 ;
    END
  END g_front_0_u_front__f_t3[179]
  PIN g_front_0_u_front__f_t3[17]
    DIRECTION OUTPUT ;
    USE SIGNAL ;
    PORT
      LAYER M4 ;
        RECT  215.808 115.932 216 115.956 ;
    END
  END g_front_0_u_front__f_t3[17]
  PIN g_front_0_u_front__f_t3[180]
    DIRECTION OUTPUT ;
    USE SIGNAL ;
    PORT
      LAYER M4 ;
        RECT  215.808 189.996 216 190.02 ;
    END
  END g_front_0_u_front__f_t3[180]
  PIN g_front_0_u_front__f_t3[181]
    DIRECTION OUTPUT ;
    USE SIGNAL ;
    PORT
      LAYER M4 ;
        RECT  215.808 190.428 216 190.452 ;
    END
  END g_front_0_u_front__f_t3[181]
  PIN g_front_0_u_front__f_t3[182]
    DIRECTION OUTPUT ;
    USE SIGNAL ;
    PORT
      LAYER M4 ;
        RECT  215.808 190.908 216 190.932 ;
    END
  END g_front_0_u_front__f_t3[182]
  PIN g_front_0_u_front__f_t3[183]
    DIRECTION OUTPUT ;
    USE SIGNAL ;
    PORT
      LAYER M4 ;
        RECT  215.808 191.34 216 191.364 ;
    END
  END g_front_0_u_front__f_t3[183]
  PIN g_front_0_u_front__f_t3[184]
    DIRECTION OUTPUT ;
    USE SIGNAL ;
    PORT
      LAYER M4 ;
        RECT  215.808 191.82 216 191.844 ;
    END
  END g_front_0_u_front__f_t3[184]
  PIN g_front_0_u_front__f_t3[185]
    DIRECTION OUTPUT ;
    USE SIGNAL ;
    PORT
      LAYER M4 ;
        RECT  215.808 192.252 216 192.276 ;
    END
  END g_front_0_u_front__f_t3[185]
  PIN g_front_0_u_front__f_t3[186]
    DIRECTION OUTPUT ;
    USE SIGNAL ;
    PORT
      LAYER M4 ;
        RECT  215.808 192.684 216 192.708 ;
    END
  END g_front_0_u_front__f_t3[186]
  PIN g_front_0_u_front__f_t3[187]
    DIRECTION OUTPUT ;
    USE SIGNAL ;
    PORT
      LAYER M4 ;
        RECT  215.808 193.164 216 193.188 ;
    END
  END g_front_0_u_front__f_t3[187]
  PIN g_front_0_u_front__f_t3[188]
    DIRECTION OUTPUT ;
    USE SIGNAL ;
    PORT
      LAYER M4 ;
        RECT  215.808 193.596 216 193.62 ;
    END
  END g_front_0_u_front__f_t3[188]
  PIN g_front_0_u_front__f_t3[189]
    DIRECTION OUTPUT ;
    USE SIGNAL ;
    PORT
      LAYER M4 ;
        RECT  215.808 194.076 216 194.1 ;
    END
  END g_front_0_u_front__f_t3[189]
  PIN g_front_0_u_front__f_t3[18]
    DIRECTION OUTPUT ;
    USE SIGNAL ;
    PORT
      LAYER M4 ;
        RECT  215.808 116.412 216 116.436 ;
    END
  END g_front_0_u_front__f_t3[18]
  PIN g_front_0_u_front__f_t3[190]
    DIRECTION OUTPUT ;
    USE SIGNAL ;
    PORT
      LAYER M4 ;
        RECT  215.808 194.508 216 194.532 ;
    END
  END g_front_0_u_front__f_t3[190]
  PIN g_front_0_u_front__f_t3[191]
    DIRECTION OUTPUT ;
    USE SIGNAL ;
    PORT
      LAYER M4 ;
        RECT  215.808 194.988 216 195.012 ;
    END
  END g_front_0_u_front__f_t3[191]
  PIN g_front_0_u_front__f_t3[192]
    DIRECTION OUTPUT ;
    USE SIGNAL ;
    PORT
      LAYER M4 ;
        RECT  215.808 195.42 216 195.444 ;
    END
  END g_front_0_u_front__f_t3[192]
  PIN g_front_0_u_front__f_t3[193]
    DIRECTION OUTPUT ;
    USE SIGNAL ;
    PORT
      LAYER M4 ;
        RECT  215.808 195.9 216 195.924 ;
    END
  END g_front_0_u_front__f_t3[193]
  PIN g_front_0_u_front__f_t3[194]
    DIRECTION OUTPUT ;
    USE SIGNAL ;
    PORT
      LAYER M4 ;
        RECT  215.808 196.332 216 196.356 ;
    END
  END g_front_0_u_front__f_t3[194]
  PIN g_front_0_u_front__f_t3[195]
    DIRECTION OUTPUT ;
    USE SIGNAL ;
    PORT
      LAYER M4 ;
        RECT  215.808 196.812 216 196.836 ;
    END
  END g_front_0_u_front__f_t3[195]
  PIN g_front_0_u_front__f_t3[196]
    DIRECTION OUTPUT ;
    USE SIGNAL ;
    PORT
      LAYER M4 ;
        RECT  215.808 197.244 216 197.268 ;
    END
  END g_front_0_u_front__f_t3[196]
  PIN g_front_0_u_front__f_t3[197]
    DIRECTION OUTPUT ;
    USE SIGNAL ;
    PORT
      LAYER M4 ;
        RECT  215.808 197.724 216 197.748 ;
    END
  END g_front_0_u_front__f_t3[197]
  PIN g_front_0_u_front__f_t3[198]
    DIRECTION OUTPUT ;
    USE SIGNAL ;
    PORT
      LAYER M4 ;
        RECT  215.808 198.156 216 198.18 ;
    END
  END g_front_0_u_front__f_t3[198]
  PIN g_front_0_u_front__f_t3[199]
    DIRECTION OUTPUT ;
    USE SIGNAL ;
    PORT
      LAYER M4 ;
        RECT  215.808 198.588 216 198.612 ;
    END
  END g_front_0_u_front__f_t3[199]
  PIN g_front_0_u_front__f_t3[19]
    DIRECTION OUTPUT ;
    USE SIGNAL ;
    PORT
      LAYER M4 ;
        RECT  215.808 116.844 216 116.868 ;
    END
  END g_front_0_u_front__f_t3[19]
  PIN g_front_0_u_front__f_t3[1]
    DIRECTION OUTPUT ;
    USE SIGNAL ;
    PORT
      LAYER M4 ;
        RECT  215.808 108.684 216 108.708 ;
    END
  END g_front_0_u_front__f_t3[1]
  PIN g_front_0_u_front__f_t3[200]
    DIRECTION OUTPUT ;
    USE SIGNAL ;
    PORT
      LAYER M4 ;
        RECT  215.808 199.068 216 199.092 ;
    END
  END g_front_0_u_front__f_t3[200]
  PIN g_front_0_u_front__f_t3[201]
    DIRECTION OUTPUT ;
    USE SIGNAL ;
    PORT
      LAYER M4 ;
        RECT  215.808 199.5 216 199.524 ;
    END
  END g_front_0_u_front__f_t3[201]
  PIN g_front_0_u_front__f_t3[202]
    DIRECTION OUTPUT ;
    USE SIGNAL ;
    PORT
      LAYER M4 ;
        RECT  215.808 199.98 216 200.004 ;
    END
  END g_front_0_u_front__f_t3[202]
  PIN g_front_0_u_front__f_t3[203]
    DIRECTION OUTPUT ;
    USE SIGNAL ;
    PORT
      LAYER M4 ;
        RECT  215.808 200.412 216 200.436 ;
    END
  END g_front_0_u_front__f_t3[203]
  PIN g_front_0_u_front__f_t3[204]
    DIRECTION OUTPUT ;
    USE SIGNAL ;
    PORT
      LAYER M4 ;
        RECT  215.808 200.892 216 200.916 ;
    END
  END g_front_0_u_front__f_t3[204]
  PIN g_front_0_u_front__f_t3[205]
    DIRECTION OUTPUT ;
    USE SIGNAL ;
    PORT
      LAYER M4 ;
        RECT  215.808 201.324 216 201.348 ;
    END
  END g_front_0_u_front__f_t3[205]
  PIN g_front_0_u_front__f_t3[206]
    DIRECTION OUTPUT ;
    USE SIGNAL ;
    PORT
      LAYER M4 ;
        RECT  215.808 201.804 216 201.828 ;
    END
  END g_front_0_u_front__f_t3[206]
  PIN g_front_0_u_front__f_t3[207]
    DIRECTION OUTPUT ;
    USE SIGNAL ;
    PORT
      LAYER M4 ;
        RECT  215.808 202.236 216 202.26 ;
    END
  END g_front_0_u_front__f_t3[207]
  PIN g_front_0_u_front__f_t3[208]
    DIRECTION OUTPUT ;
    USE SIGNAL ;
    PORT
      LAYER M4 ;
        RECT  215.808 202.716 216 202.74 ;
    END
  END g_front_0_u_front__f_t3[208]
  PIN g_front_0_u_front__f_t3[209]
    DIRECTION OUTPUT ;
    USE SIGNAL ;
    PORT
      LAYER M4 ;
        RECT  215.808 203.148 216 203.172 ;
    END
  END g_front_0_u_front__f_t3[209]
  PIN g_front_0_u_front__f_t3[20]
    DIRECTION OUTPUT ;
    USE SIGNAL ;
    PORT
      LAYER M4 ;
        RECT  215.808 117.324 216 117.348 ;
    END
  END g_front_0_u_front__f_t3[20]
  PIN g_front_0_u_front__f_t3[210]
    DIRECTION OUTPUT ;
    USE SIGNAL ;
    PORT
      LAYER M4 ;
        RECT  215.808 203.628 216 203.652 ;
    END
  END g_front_0_u_front__f_t3[210]
  PIN g_front_0_u_front__f_t3[211]
    DIRECTION OUTPUT ;
    USE SIGNAL ;
    PORT
      LAYER M4 ;
        RECT  215.808 204.06 216 204.084 ;
    END
  END g_front_0_u_front__f_t3[211]
  PIN g_front_0_u_front__f_t3[212]
    DIRECTION OUTPUT ;
    USE SIGNAL ;
    PORT
      LAYER M4 ;
        RECT  215.808 204.492 216 204.516 ;
    END
  END g_front_0_u_front__f_t3[212]
  PIN g_front_0_u_front__f_t3[213]
    DIRECTION OUTPUT ;
    USE SIGNAL ;
    PORT
      LAYER M4 ;
        RECT  215.808 204.972 216 204.996 ;
    END
  END g_front_0_u_front__f_t3[213]
  PIN g_front_0_u_front__f_t3[214]
    DIRECTION OUTPUT ;
    USE SIGNAL ;
    PORT
      LAYER M4 ;
        RECT  215.808 205.404 216 205.428 ;
    END
  END g_front_0_u_front__f_t3[214]
  PIN g_front_0_u_front__f_t3[215]
    DIRECTION OUTPUT ;
    USE SIGNAL ;
    PORT
      LAYER M4 ;
        RECT  215.808 205.884 216 205.908 ;
    END
  END g_front_0_u_front__f_t3[215]
  PIN g_front_0_u_front__f_t3[216]
    DIRECTION OUTPUT ;
    USE SIGNAL ;
    PORT
      LAYER M4 ;
        RECT  215.808 206.316 216 206.34 ;
    END
  END g_front_0_u_front__f_t3[216]
  PIN g_front_0_u_front__f_t3[217]
    DIRECTION OUTPUT ;
    USE SIGNAL ;
    PORT
      LAYER M4 ;
        RECT  215.808 206.796 216 206.82 ;
    END
  END g_front_0_u_front__f_t3[217]
  PIN g_front_0_u_front__f_t3[218]
    DIRECTION OUTPUT ;
    USE SIGNAL ;
    PORT
      LAYER M4 ;
        RECT  215.808 207.228 216 207.252 ;
    END
  END g_front_0_u_front__f_t3[218]
  PIN g_front_0_u_front__f_t3[219]
    DIRECTION OUTPUT ;
    USE SIGNAL ;
    PORT
      LAYER M4 ;
        RECT  215.808 207.708 216 207.732 ;
    END
  END g_front_0_u_front__f_t3[219]
  PIN g_front_0_u_front__f_t3[21]
    DIRECTION OUTPUT ;
    USE SIGNAL ;
    PORT
      LAYER M4 ;
        RECT  215.808 117.756 216 117.78 ;
    END
  END g_front_0_u_front__f_t3[21]
  PIN g_front_0_u_front__f_t3[220]
    DIRECTION OUTPUT ;
    USE SIGNAL ;
    PORT
      LAYER M4 ;
        RECT  215.808 208.14 216 208.164 ;
    END
  END g_front_0_u_front__f_t3[220]
  PIN g_front_0_u_front__f_t3[221]
    DIRECTION OUTPUT ;
    USE SIGNAL ;
    PORT
      LAYER M4 ;
        RECT  215.808 208.62 216 208.644 ;
    END
  END g_front_0_u_front__f_t3[221]
  PIN g_front_0_u_front__f_t3[222]
    DIRECTION OUTPUT ;
    USE SIGNAL ;
    PORT
      LAYER M4 ;
        RECT  215.808 209.052 216 209.076 ;
    END
  END g_front_0_u_front__f_t3[222]
  PIN g_front_0_u_front__f_t3[223]
    DIRECTION OUTPUT ;
    USE SIGNAL ;
    PORT
      LAYER M4 ;
        RECT  215.808 209.532 216 209.556 ;
    END
  END g_front_0_u_front__f_t3[223]
  PIN g_front_0_u_front__f_t3[224]
    DIRECTION OUTPUT ;
    USE SIGNAL ;
    PORT
      LAYER M4 ;
        RECT  215.808 209.964 216 209.988 ;
    END
  END g_front_0_u_front__f_t3[224]
  PIN g_front_0_u_front__f_t3[225]
    DIRECTION OUTPUT ;
    USE SIGNAL ;
    PORT
      LAYER M4 ;
        RECT  215.808 210.444 216 210.468 ;
    END
  END g_front_0_u_front__f_t3[225]
  PIN g_front_0_u_front__f_t3[226]
    DIRECTION OUTPUT ;
    USE SIGNAL ;
    PORT
      LAYER M4 ;
        RECT  215.808 210.876 216 210.9 ;
    END
  END g_front_0_u_front__f_t3[226]
  PIN g_front_0_u_front__f_t3[227]
    DIRECTION OUTPUT ;
    USE SIGNAL ;
    PORT
      LAYER M4 ;
        RECT  215.808 211.308 216 211.332 ;
    END
  END g_front_0_u_front__f_t3[227]
  PIN g_front_0_u_front__f_t3[228]
    DIRECTION OUTPUT ;
    USE SIGNAL ;
    PORT
      LAYER M4 ;
        RECT  215.808 211.788 216 211.812 ;
    END
  END g_front_0_u_front__f_t3[228]
  PIN g_front_0_u_front__f_t3[229]
    DIRECTION OUTPUT ;
    USE SIGNAL ;
    PORT
      LAYER M4 ;
        RECT  215.808 212.22 216 212.244 ;
    END
  END g_front_0_u_front__f_t3[229]
  PIN g_front_0_u_front__f_t3[22]
    DIRECTION OUTPUT ;
    USE SIGNAL ;
    PORT
      LAYER M4 ;
        RECT  215.808 118.188 216 118.212 ;
    END
  END g_front_0_u_front__f_t3[22]
  PIN g_front_0_u_front__f_t3[230]
    DIRECTION OUTPUT ;
    USE SIGNAL ;
    PORT
      LAYER M4 ;
        RECT  215.808 212.7 216 212.724 ;
    END
  END g_front_0_u_front__f_t3[230]
  PIN g_front_0_u_front__f_t3[231]
    DIRECTION OUTPUT ;
    USE SIGNAL ;
    PORT
      LAYER M4 ;
        RECT  215.808 213.132 216 213.156 ;
    END
  END g_front_0_u_front__f_t3[231]
  PIN g_front_0_u_front__f_t3[232]
    DIRECTION OUTPUT ;
    USE SIGNAL ;
    PORT
      LAYER M4 ;
        RECT  215.808 213.612 216 213.636 ;
    END
  END g_front_0_u_front__f_t3[232]
  PIN g_front_0_u_front__f_t3[23]
    DIRECTION OUTPUT ;
    USE SIGNAL ;
    PORT
      LAYER M4 ;
        RECT  215.808 118.668 216 118.692 ;
    END
  END g_front_0_u_front__f_t3[23]
  PIN g_front_0_u_front__f_t3[24]
    DIRECTION OUTPUT ;
    USE SIGNAL ;
    PORT
      LAYER M4 ;
        RECT  215.808 119.1 216 119.124 ;
    END
  END g_front_0_u_front__f_t3[24]
  PIN g_front_0_u_front__f_t3[25]
    DIRECTION OUTPUT ;
    USE SIGNAL ;
    PORT
      LAYER M4 ;
        RECT  215.808 119.58 216 119.604 ;
    END
  END g_front_0_u_front__f_t3[25]
  PIN g_front_0_u_front__f_t3[26]
    DIRECTION OUTPUT ;
    USE SIGNAL ;
    PORT
      LAYER M4 ;
        RECT  215.808 120.012 216 120.036 ;
    END
  END g_front_0_u_front__f_t3[26]
  PIN g_front_0_u_front__f_t3[27]
    DIRECTION OUTPUT ;
    USE SIGNAL ;
    PORT
      LAYER M4 ;
        RECT  215.808 120.492 216 120.516 ;
    END
  END g_front_0_u_front__f_t3[27]
  PIN g_front_0_u_front__f_t3[28]
    DIRECTION OUTPUT ;
    USE SIGNAL ;
    PORT
      LAYER M4 ;
        RECT  215.808 120.924 216 120.948 ;
    END
  END g_front_0_u_front__f_t3[28]
  PIN g_front_0_u_front__f_t3[29]
    DIRECTION OUTPUT ;
    USE SIGNAL ;
    PORT
      LAYER M4 ;
        RECT  215.808 121.404 216 121.428 ;
    END
  END g_front_0_u_front__f_t3[29]
  PIN g_front_0_u_front__f_t3[2]
    DIRECTION OUTPUT ;
    USE SIGNAL ;
    PORT
      LAYER M4 ;
        RECT  215.808 109.116 216 109.14 ;
    END
  END g_front_0_u_front__f_t3[2]
  PIN g_front_0_u_front__f_t3[30]
    DIRECTION OUTPUT ;
    USE SIGNAL ;
    PORT
      LAYER M4 ;
        RECT  215.808 121.836 216 121.86 ;
    END
  END g_front_0_u_front__f_t3[30]
  PIN g_front_0_u_front__f_t3[31]
    DIRECTION OUTPUT ;
    USE SIGNAL ;
    PORT
      LAYER M4 ;
        RECT  215.808 122.316 216 122.34 ;
    END
  END g_front_0_u_front__f_t3[31]
  PIN g_front_0_u_front__f_t3[32]
    DIRECTION OUTPUT ;
    USE SIGNAL ;
    PORT
      LAYER M4 ;
        RECT  215.808 122.748 216 122.772 ;
    END
  END g_front_0_u_front__f_t3[32]
  PIN g_front_0_u_front__f_t3[33]
    DIRECTION OUTPUT ;
    USE SIGNAL ;
    PORT
      LAYER M4 ;
        RECT  215.808 123.228 216 123.252 ;
    END
  END g_front_0_u_front__f_t3[33]
  PIN g_front_0_u_front__f_t3[34]
    DIRECTION OUTPUT ;
    USE SIGNAL ;
    PORT
      LAYER M4 ;
        RECT  215.808 123.66 216 123.684 ;
    END
  END g_front_0_u_front__f_t3[34]
  PIN g_front_0_u_front__f_t3[35]
    DIRECTION OUTPUT ;
    USE SIGNAL ;
    PORT
      LAYER M4 ;
        RECT  215.808 124.092 216 124.116 ;
    END
  END g_front_0_u_front__f_t3[35]
  PIN g_front_0_u_front__f_t3[36]
    DIRECTION OUTPUT ;
    USE SIGNAL ;
    PORT
      LAYER M4 ;
        RECT  215.808 124.572 216 124.596 ;
    END
  END g_front_0_u_front__f_t3[36]
  PIN g_front_0_u_front__f_t3[37]
    DIRECTION OUTPUT ;
    USE SIGNAL ;
    PORT
      LAYER M4 ;
        RECT  215.808 125.004 216 125.028 ;
    END
  END g_front_0_u_front__f_t3[37]
  PIN g_front_0_u_front__f_t3[38]
    DIRECTION OUTPUT ;
    USE SIGNAL ;
    PORT
      LAYER M4 ;
        RECT  215.808 125.484 216 125.508 ;
    END
  END g_front_0_u_front__f_t3[38]
  PIN g_front_0_u_front__f_t3[39]
    DIRECTION OUTPUT ;
    USE SIGNAL ;
    PORT
      LAYER M4 ;
        RECT  215.808 125.916 216 125.94 ;
    END
  END g_front_0_u_front__f_t3[39]
  PIN g_front_0_u_front__f_t3[3]
    DIRECTION OUTPUT ;
    USE SIGNAL ;
    PORT
      LAYER M4 ;
        RECT  215.808 109.596 216 109.62 ;
    END
  END g_front_0_u_front__f_t3[3]
  PIN g_front_0_u_front__f_t3[40]
    DIRECTION OUTPUT ;
    USE SIGNAL ;
    PORT
      LAYER M4 ;
        RECT  215.808 126.396 216 126.42 ;
    END
  END g_front_0_u_front__f_t3[40]
  PIN g_front_0_u_front__f_t3[41]
    DIRECTION OUTPUT ;
    USE SIGNAL ;
    PORT
      LAYER M4 ;
        RECT  215.808 126.828 216 126.852 ;
    END
  END g_front_0_u_front__f_t3[41]
  PIN g_front_0_u_front__f_t3[42]
    DIRECTION OUTPUT ;
    USE SIGNAL ;
    PORT
      LAYER M4 ;
        RECT  215.808 127.308 216 127.332 ;
    END
  END g_front_0_u_front__f_t3[42]
  PIN g_front_0_u_front__f_t3[43]
    DIRECTION OUTPUT ;
    USE SIGNAL ;
    PORT
      LAYER M4 ;
        RECT  215.808 127.74 216 127.764 ;
    END
  END g_front_0_u_front__f_t3[43]
  PIN g_front_0_u_front__f_t3[44]
    DIRECTION OUTPUT ;
    USE SIGNAL ;
    PORT
      LAYER M4 ;
        RECT  215.808 128.22 216 128.244 ;
    END
  END g_front_0_u_front__f_t3[44]
  PIN g_front_0_u_front__f_t3[45]
    DIRECTION OUTPUT ;
    USE SIGNAL ;
    PORT
      LAYER M4 ;
        RECT  215.808 128.652 216 128.676 ;
    END
  END g_front_0_u_front__f_t3[45]
  PIN g_front_0_u_front__f_t3[46]
    DIRECTION OUTPUT ;
    USE SIGNAL ;
    PORT
      LAYER M4 ;
        RECT  215.808 129.132 216 129.156 ;
    END
  END g_front_0_u_front__f_t3[46]
  PIN g_front_0_u_front__f_t3[47]
    DIRECTION OUTPUT ;
    USE SIGNAL ;
    PORT
      LAYER M4 ;
        RECT  215.808 129.564 216 129.588 ;
    END
  END g_front_0_u_front__f_t3[47]
  PIN g_front_0_u_front__f_t3[48]
    DIRECTION OUTPUT ;
    USE SIGNAL ;
    PORT
      LAYER M4 ;
        RECT  215.808 129.996 216 130.02 ;
    END
  END g_front_0_u_front__f_t3[48]
  PIN g_front_0_u_front__f_t3[49]
    DIRECTION OUTPUT ;
    USE SIGNAL ;
    PORT
      LAYER M4 ;
        RECT  215.808 130.476 216 130.5 ;
    END
  END g_front_0_u_front__f_t3[49]
  PIN g_front_0_u_front__f_t3[4]
    DIRECTION OUTPUT ;
    USE SIGNAL ;
    PORT
      LAYER M4 ;
        RECT  215.808 110.028 216 110.052 ;
    END
  END g_front_0_u_front__f_t3[4]
  PIN g_front_0_u_front__f_t3[50]
    DIRECTION OUTPUT ;
    USE SIGNAL ;
    PORT
      LAYER M4 ;
        RECT  215.808 130.908 216 130.932 ;
    END
  END g_front_0_u_front__f_t3[50]
  PIN g_front_0_u_front__f_t3[51]
    DIRECTION OUTPUT ;
    USE SIGNAL ;
    PORT
      LAYER M4 ;
        RECT  215.808 131.388 216 131.412 ;
    END
  END g_front_0_u_front__f_t3[51]
  PIN g_front_0_u_front__f_t3[52]
    DIRECTION OUTPUT ;
    USE SIGNAL ;
    PORT
      LAYER M4 ;
        RECT  215.808 131.82 216 131.844 ;
    END
  END g_front_0_u_front__f_t3[52]
  PIN g_front_0_u_front__f_t3[53]
    DIRECTION OUTPUT ;
    USE SIGNAL ;
    PORT
      LAYER M4 ;
        RECT  215.808 132.3 216 132.324 ;
    END
  END g_front_0_u_front__f_t3[53]
  PIN g_front_0_u_front__f_t3[54]
    DIRECTION OUTPUT ;
    USE SIGNAL ;
    PORT
      LAYER M4 ;
        RECT  215.808 132.732 216 132.756 ;
    END
  END g_front_0_u_front__f_t3[54]
  PIN g_front_0_u_front__f_t3[55]
    DIRECTION OUTPUT ;
    USE SIGNAL ;
    PORT
      LAYER M4 ;
        RECT  215.808 133.212 216 133.236 ;
    END
  END g_front_0_u_front__f_t3[55]
  PIN g_front_0_u_front__f_t3[56]
    DIRECTION OUTPUT ;
    USE SIGNAL ;
    PORT
      LAYER M4 ;
        RECT  215.808 133.644 216 133.668 ;
    END
  END g_front_0_u_front__f_t3[56]
  PIN g_front_0_u_front__f_t3[57]
    DIRECTION OUTPUT ;
    USE SIGNAL ;
    PORT
      LAYER M4 ;
        RECT  215.808 134.124 216 134.148 ;
    END
  END g_front_0_u_front__f_t3[57]
  PIN g_front_0_u_front__f_t3[58]
    DIRECTION OUTPUT ;
    USE SIGNAL ;
    PORT
      LAYER M4 ;
        RECT  215.808 134.556 216 134.58 ;
    END
  END g_front_0_u_front__f_t3[58]
  PIN g_front_0_u_front__f_t3[59]
    DIRECTION OUTPUT ;
    USE SIGNAL ;
    PORT
      LAYER M4 ;
        RECT  215.808 135.036 216 135.06 ;
    END
  END g_front_0_u_front__f_t3[59]
  PIN g_front_0_u_front__f_t3[5]
    DIRECTION OUTPUT ;
    USE SIGNAL ;
    PORT
      LAYER M4 ;
        RECT  215.808 110.508 216 110.532 ;
    END
  END g_front_0_u_front__f_t3[5]
  PIN g_front_0_u_front__f_t3[60]
    DIRECTION OUTPUT ;
    USE SIGNAL ;
    PORT
      LAYER M4 ;
        RECT  215.808 135.468 216 135.492 ;
    END
  END g_front_0_u_front__f_t3[60]
  PIN g_front_0_u_front__f_t3[61]
    DIRECTION OUTPUT ;
    USE SIGNAL ;
    PORT
      LAYER M4 ;
        RECT  215.808 135.948 216 135.972 ;
    END
  END g_front_0_u_front__f_t3[61]
  PIN g_front_0_u_front__f_t3[62]
    DIRECTION OUTPUT ;
    USE SIGNAL ;
    PORT
      LAYER M4 ;
        RECT  215.808 136.38 216 136.404 ;
    END
  END g_front_0_u_front__f_t3[62]
  PIN g_front_0_u_front__f_t3[63]
    DIRECTION OUTPUT ;
    USE SIGNAL ;
    PORT
      LAYER M4 ;
        RECT  215.808 136.812 216 136.836 ;
    END
  END g_front_0_u_front__f_t3[63]
  PIN g_front_0_u_front__f_t3[64]
    DIRECTION OUTPUT ;
    USE SIGNAL ;
    PORT
      LAYER M4 ;
        RECT  215.808 137.292 216 137.316 ;
    END
  END g_front_0_u_front__f_t3[64]
  PIN g_front_0_u_front__f_t3[65]
    DIRECTION OUTPUT ;
    USE SIGNAL ;
    PORT
      LAYER M4 ;
        RECT  215.808 137.724 216 137.748 ;
    END
  END g_front_0_u_front__f_t3[65]
  PIN g_front_0_u_front__f_t3[66]
    DIRECTION OUTPUT ;
    USE SIGNAL ;
    PORT
      LAYER M4 ;
        RECT  215.808 138.204 216 138.228 ;
    END
  END g_front_0_u_front__f_t3[66]
  PIN g_front_0_u_front__f_t3[67]
    DIRECTION OUTPUT ;
    USE SIGNAL ;
    PORT
      LAYER M4 ;
        RECT  215.808 138.636 216 138.66 ;
    END
  END g_front_0_u_front__f_t3[67]
  PIN g_front_0_u_front__f_t3[68]
    DIRECTION OUTPUT ;
    USE SIGNAL ;
    PORT
      LAYER M4 ;
        RECT  215.808 139.116 216 139.14 ;
    END
  END g_front_0_u_front__f_t3[68]
  PIN g_front_0_u_front__f_t3[69]
    DIRECTION OUTPUT ;
    USE SIGNAL ;
    PORT
      LAYER M4 ;
        RECT  215.808 139.548 216 139.572 ;
    END
  END g_front_0_u_front__f_t3[69]
  PIN g_front_0_u_front__f_t3[6]
    DIRECTION OUTPUT ;
    USE SIGNAL ;
    PORT
      LAYER M4 ;
        RECT  215.808 110.94 216 110.964 ;
    END
  END g_front_0_u_front__f_t3[6]
  PIN g_front_0_u_front__f_t3[70]
    DIRECTION OUTPUT ;
    USE SIGNAL ;
    PORT
      LAYER M4 ;
        RECT  215.808 140.028 216 140.052 ;
    END
  END g_front_0_u_front__f_t3[70]
  PIN g_front_0_u_front__f_t3[71]
    DIRECTION OUTPUT ;
    USE SIGNAL ;
    PORT
      LAYER M4 ;
        RECT  215.808 140.46 216 140.484 ;
    END
  END g_front_0_u_front__f_t3[71]
  PIN g_front_0_u_front__f_t3[72]
    DIRECTION OUTPUT ;
    USE SIGNAL ;
    PORT
      LAYER M4 ;
        RECT  215.808 140.94 216 140.964 ;
    END
  END g_front_0_u_front__f_t3[72]
  PIN g_front_0_u_front__f_t3[73]
    DIRECTION OUTPUT ;
    USE SIGNAL ;
    PORT
      LAYER M4 ;
        RECT  215.808 141.372 216 141.396 ;
    END
  END g_front_0_u_front__f_t3[73]
  PIN g_front_0_u_front__f_t3[74]
    DIRECTION OUTPUT ;
    USE SIGNAL ;
    PORT
      LAYER M4 ;
        RECT  215.808 141.852 216 141.876 ;
    END
  END g_front_0_u_front__f_t3[74]
  PIN g_front_0_u_front__f_t3[75]
    DIRECTION OUTPUT ;
    USE SIGNAL ;
    PORT
      LAYER M4 ;
        RECT  215.808 142.284 216 142.308 ;
    END
  END g_front_0_u_front__f_t3[75]
  PIN g_front_0_u_front__f_t3[76]
    DIRECTION OUTPUT ;
    USE SIGNAL ;
    PORT
      LAYER M4 ;
        RECT  215.808 142.716 216 142.74 ;
    END
  END g_front_0_u_front__f_t3[76]
  PIN g_front_0_u_front__f_t3[77]
    DIRECTION OUTPUT ;
    USE SIGNAL ;
    PORT
      LAYER M4 ;
        RECT  215.808 143.196 216 143.22 ;
    END
  END g_front_0_u_front__f_t3[77]
  PIN g_front_0_u_front__f_t3[78]
    DIRECTION OUTPUT ;
    USE SIGNAL ;
    PORT
      LAYER M4 ;
        RECT  215.808 143.628 216 143.652 ;
    END
  END g_front_0_u_front__f_t3[78]
  PIN g_front_0_u_front__f_t3[79]
    DIRECTION OUTPUT ;
    USE SIGNAL ;
    PORT
      LAYER M4 ;
        RECT  215.808 144.108 216 144.132 ;
    END
  END g_front_0_u_front__f_t3[79]
  PIN g_front_0_u_front__f_t3[7]
    DIRECTION OUTPUT ;
    USE SIGNAL ;
    PORT
      LAYER M4 ;
        RECT  215.808 111.372 216 111.396 ;
    END
  END g_front_0_u_front__f_t3[7]
  PIN g_front_0_u_front__f_t3[80]
    DIRECTION OUTPUT ;
    USE SIGNAL ;
    PORT
      LAYER M4 ;
        RECT  215.808 144.54 216 144.564 ;
    END
  END g_front_0_u_front__f_t3[80]
  PIN g_front_0_u_front__f_t3[81]
    DIRECTION OUTPUT ;
    USE SIGNAL ;
    PORT
      LAYER M4 ;
        RECT  215.808 145.02 216 145.044 ;
    END
  END g_front_0_u_front__f_t3[81]
  PIN g_front_0_u_front__f_t3[82]
    DIRECTION OUTPUT ;
    USE SIGNAL ;
    PORT
      LAYER M4 ;
        RECT  215.808 145.452 216 145.476 ;
    END
  END g_front_0_u_front__f_t3[82]
  PIN g_front_0_u_front__f_t3[83]
    DIRECTION OUTPUT ;
    USE SIGNAL ;
    PORT
      LAYER M4 ;
        RECT  215.808 145.932 216 145.956 ;
    END
  END g_front_0_u_front__f_t3[83]
  PIN g_front_0_u_front__f_t3[84]
    DIRECTION OUTPUT ;
    USE SIGNAL ;
    PORT
      LAYER M4 ;
        RECT  215.808 146.364 216 146.388 ;
    END
  END g_front_0_u_front__f_t3[84]
  PIN g_front_0_u_front__f_t3[85]
    DIRECTION OUTPUT ;
    USE SIGNAL ;
    PORT
      LAYER M4 ;
        RECT  215.808 146.844 216 146.868 ;
    END
  END g_front_0_u_front__f_t3[85]
  PIN g_front_0_u_front__f_t3[86]
    DIRECTION OUTPUT ;
    USE SIGNAL ;
    PORT
      LAYER M4 ;
        RECT  215.808 147.276 216 147.3 ;
    END
  END g_front_0_u_front__f_t3[86]
  PIN g_front_0_u_front__f_t3[87]
    DIRECTION OUTPUT ;
    USE SIGNAL ;
    PORT
      LAYER M4 ;
        RECT  215.808 147.756 216 147.78 ;
    END
  END g_front_0_u_front__f_t3[87]
  PIN g_front_0_u_front__f_t3[88]
    DIRECTION OUTPUT ;
    USE SIGNAL ;
    PORT
      LAYER M4 ;
        RECT  215.808 148.188 216 148.212 ;
    END
  END g_front_0_u_front__f_t3[88]
  PIN g_front_0_u_front__f_t3[89]
    DIRECTION OUTPUT ;
    USE SIGNAL ;
    PORT
      LAYER M4 ;
        RECT  215.808 148.62 216 148.644 ;
    END
  END g_front_0_u_front__f_t3[89]
  PIN g_front_0_u_front__f_t3[8]
    DIRECTION OUTPUT ;
    USE SIGNAL ;
    PORT
      LAYER M4 ;
        RECT  215.808 111.852 216 111.876 ;
    END
  END g_front_0_u_front__f_t3[8]
  PIN g_front_0_u_front__f_t3[90]
    DIRECTION OUTPUT ;
    USE SIGNAL ;
    PORT
      LAYER M4 ;
        RECT  215.808 149.1 216 149.124 ;
    END
  END g_front_0_u_front__f_t3[90]
  PIN g_front_0_u_front__f_t3[91]
    DIRECTION OUTPUT ;
    USE SIGNAL ;
    PORT
      LAYER M4 ;
        RECT  215.808 149.532 216 149.556 ;
    END
  END g_front_0_u_front__f_t3[91]
  PIN g_front_0_u_front__f_t3[92]
    DIRECTION OUTPUT ;
    USE SIGNAL ;
    PORT
      LAYER M4 ;
        RECT  215.808 150.012 216 150.036 ;
    END
  END g_front_0_u_front__f_t3[92]
  PIN g_front_0_u_front__f_t3[93]
    DIRECTION OUTPUT ;
    USE SIGNAL ;
    PORT
      LAYER M4 ;
        RECT  215.808 150.444 216 150.468 ;
    END
  END g_front_0_u_front__f_t3[93]
  PIN g_front_0_u_front__f_t3[94]
    DIRECTION OUTPUT ;
    USE SIGNAL ;
    PORT
      LAYER M4 ;
        RECT  215.808 150.924 216 150.948 ;
    END
  END g_front_0_u_front__f_t3[94]
  PIN g_front_0_u_front__f_t3[95]
    DIRECTION OUTPUT ;
    USE SIGNAL ;
    PORT
      LAYER M4 ;
        RECT  215.808 151.356 216 151.38 ;
    END
  END g_front_0_u_front__f_t3[95]
  PIN g_front_0_u_front__f_t3[96]
    DIRECTION OUTPUT ;
    USE SIGNAL ;
    PORT
      LAYER M4 ;
        RECT  215.808 151.836 216 151.86 ;
    END
  END g_front_0_u_front__f_t3[96]
  PIN g_front_0_u_front__f_t3[97]
    DIRECTION OUTPUT ;
    USE SIGNAL ;
    PORT
      LAYER M4 ;
        RECT  215.808 152.268 216 152.292 ;
    END
  END g_front_0_u_front__f_t3[97]
  PIN g_front_0_u_front__f_t3[98]
    DIRECTION OUTPUT ;
    USE SIGNAL ;
    PORT
      LAYER M4 ;
        RECT  215.808 152.748 216 152.772 ;
    END
  END g_front_0_u_front__f_t3[98]
  PIN g_front_0_u_front__f_t3[99]
    DIRECTION OUTPUT ;
    USE SIGNAL ;
    PORT
      LAYER M4 ;
        RECT  215.808 153.18 216 153.204 ;
    END
  END g_front_0_u_front__f_t3[99]
  PIN g_front_0_u_front__f_t3[9]
    DIRECTION OUTPUT ;
    USE SIGNAL ;
    PORT
      LAYER M4 ;
        RECT  215.808 112.284 216 112.308 ;
    END
  END g_front_0_u_front__f_t3[9]
  PIN g_front_0_u_front__hid[0]
    DIRECTION INPUT ;
    USE SIGNAL ;
    PORT
      LAYER M4 ;
        RECT  0 107.964 0.192 107.988 ;
    END
  END g_front_0_u_front__hid[0]
  PIN g_front_0_u_front__hid[1]
    DIRECTION INPUT ;
    USE SIGNAL ;
    PORT
      LAYER M5 ;
        RECT  107.964 0 107.988 0.192 ;
    END
  END g_front_0_u_front__hid[1]
  PIN g_front_0_u_front__lt_in[0]
    DIRECTION INPUT ;
    USE SIGNAL ;
    PORT
      LAYER M5 ;
        RECT  5.58 215.808 5.604 216 ;
    END
  END g_front_0_u_front__lt_in[0]
  PIN g_front_0_u_front__lt_in[10]
    DIRECTION INPUT ;
    USE SIGNAL ;
    PORT
      LAYER M5 ;
        RECT  7.164 215.808 7.188 216 ;
    END
  END g_front_0_u_front__lt_in[10]
  PIN g_front_0_u_front__lt_in[11]
    DIRECTION INPUT ;
    USE SIGNAL ;
    PORT
      LAYER M5 ;
        RECT  7.308 215.808 7.332 216 ;
    END
  END g_front_0_u_front__lt_in[11]
  PIN g_front_0_u_front__lt_in[1]
    DIRECTION INPUT ;
    USE SIGNAL ;
    PORT
      LAYER M5 ;
        RECT  5.724 215.808 5.748 216 ;
    END
  END g_front_0_u_front__lt_in[1]
  PIN g_front_0_u_front__lt_in[2]
    DIRECTION INPUT ;
    USE SIGNAL ;
    PORT
      LAYER M5 ;
        RECT  5.868 215.808 5.892 216 ;
    END
  END g_front_0_u_front__lt_in[2]
  PIN g_front_0_u_front__lt_in[3]
    DIRECTION INPUT ;
    USE SIGNAL ;
    PORT
      LAYER M5 ;
        RECT  6.06 215.808 6.084 216 ;
    END
  END g_front_0_u_front__lt_in[3]
  PIN g_front_0_u_front__lt_in[4]
    DIRECTION INPUT ;
    USE SIGNAL ;
    PORT
      LAYER M5 ;
        RECT  6.204 215.808 6.228 216 ;
    END
  END g_front_0_u_front__lt_in[4]
  PIN g_front_0_u_front__lt_in[5]
    DIRECTION INPUT ;
    USE SIGNAL ;
    PORT
      LAYER M5 ;
        RECT  6.348 215.808 6.372 216 ;
    END
  END g_front_0_u_front__lt_in[5]
  PIN g_front_0_u_front__lt_in[6]
    DIRECTION INPUT ;
    USE SIGNAL ;
    PORT
      LAYER M5 ;
        RECT  6.54 215.808 6.564 216 ;
    END
  END g_front_0_u_front__lt_in[6]
  PIN g_front_0_u_front__lt_in[7]
    DIRECTION INPUT ;
    USE SIGNAL ;
    PORT
      LAYER M5 ;
        RECT  6.684 215.808 6.708 216 ;
    END
  END g_front_0_u_front__lt_in[7]
  PIN g_front_0_u_front__lt_in[8]
    DIRECTION INPUT ;
    USE SIGNAL ;
    PORT
      LAYER M5 ;
        RECT  6.828 215.808 6.852 216 ;
    END
  END g_front_0_u_front__lt_in[8]
  PIN g_front_0_u_front__lt_in[9]
    DIRECTION INPUT ;
    USE SIGNAL ;
    PORT
      LAYER M5 ;
        RECT  6.972 215.808 6.996 216 ;
    END
  END g_front_0_u_front__lt_in[9]
  PIN g_front_0_u_front__pack_fault[0]
    DIRECTION OUTPUT ;
    USE SIGNAL ;
    PORT
      LAYER M5 ;
        RECT  7.452 215.808 7.476 216 ;
    END
  END g_front_0_u_front__pack_fault[0]
  PIN g_front_0_u_front__q_beat_in[0]
    DIRECTION INPUT ;
    USE SIGNAL ;
    PORT
      LAYER M5 ;
        RECT  7.644 215.808 7.668 216 ;
    END
  END g_front_0_u_front__q_beat_in[0]
  PIN g_front_0_u_front__q_beat_in[1]
    DIRECTION INPUT ;
    USE SIGNAL ;
    PORT
      LAYER M5 ;
        RECT  7.788 215.808 7.812 216 ;
    END
  END g_front_0_u_front__q_beat_in[1]
  PIN g_front_0_u_front__q_beat_in[2]
    DIRECTION INPUT ;
    USE SIGNAL ;
    PORT
      LAYER M5 ;
        RECT  7.932 215.808 7.956 216 ;
    END
  END g_front_0_u_front__q_beat_in[2]
  PIN g_front_0_u_front__q_beat_in[3]
    DIRECTION INPUT ;
    USE SIGNAL ;
    PORT
      LAYER M5 ;
        RECT  8.124 215.808 8.148 216 ;
    END
  END g_front_0_u_front__q_beat_in[3]
  PIN g_front_0_u_front__q_beat_in[4]
    DIRECTION INPUT ;
    USE SIGNAL ;
    PORT
      LAYER M5 ;
        RECT  8.268 215.808 8.292 216 ;
    END
  END g_front_0_u_front__q_beat_in[4]
  PIN g_front_0_u_front__q_beat_in[5]
    DIRECTION INPUT ;
    USE SIGNAL ;
    PORT
      LAYER M5 ;
        RECT  8.412 215.808 8.436 216 ;
    END
  END g_front_0_u_front__q_beat_in[5]
  PIN g_front_0_u_front__q_data_in[0]
    DIRECTION INPUT ;
    USE SIGNAL ;
    PORT
      LAYER M5 ;
        RECT  8.604 215.808 8.628 216 ;
    END
  END g_front_0_u_front__q_data_in[0]
  PIN g_front_0_u_front__q_data_in[100]
    DIRECTION INPUT ;
    USE SIGNAL ;
    PORT
      LAYER M5 ;
        RECT  24.492 215.808 24.516 216 ;
    END
  END g_front_0_u_front__q_data_in[100]
  PIN g_front_0_u_front__q_data_in[101]
    DIRECTION INPUT ;
    USE SIGNAL ;
    PORT
      LAYER M5 ;
        RECT  24.636 215.808 24.66 216 ;
    END
  END g_front_0_u_front__q_data_in[101]
  PIN g_front_0_u_front__q_data_in[102]
    DIRECTION INPUT ;
    USE SIGNAL ;
    PORT
      LAYER M5 ;
        RECT  24.78 215.808 24.804 216 ;
    END
  END g_front_0_u_front__q_data_in[102]
  PIN g_front_0_u_front__q_data_in[103]
    DIRECTION INPUT ;
    USE SIGNAL ;
    PORT
      LAYER M5 ;
        RECT  24.972 215.808 24.996 216 ;
    END
  END g_front_0_u_front__q_data_in[103]
  PIN g_front_0_u_front__q_data_in[104]
    DIRECTION INPUT ;
    USE SIGNAL ;
    PORT
      LAYER M5 ;
        RECT  25.116 215.808 25.14 216 ;
    END
  END g_front_0_u_front__q_data_in[104]
  PIN g_front_0_u_front__q_data_in[105]
    DIRECTION INPUT ;
    USE SIGNAL ;
    PORT
      LAYER M5 ;
        RECT  25.26 215.808 25.284 216 ;
    END
  END g_front_0_u_front__q_data_in[105]
  PIN g_front_0_u_front__q_data_in[106]
    DIRECTION INPUT ;
    USE SIGNAL ;
    PORT
      LAYER M5 ;
        RECT  25.452 215.808 25.476 216 ;
    END
  END g_front_0_u_front__q_data_in[106]
  PIN g_front_0_u_front__q_data_in[107]
    DIRECTION INPUT ;
    USE SIGNAL ;
    PORT
      LAYER M5 ;
        RECT  25.596 215.808 25.62 216 ;
    END
  END g_front_0_u_front__q_data_in[107]
  PIN g_front_0_u_front__q_data_in[108]
    DIRECTION INPUT ;
    USE SIGNAL ;
    PORT
      LAYER M5 ;
        RECT  25.74 215.808 25.764 216 ;
    END
  END g_front_0_u_front__q_data_in[108]
  PIN g_front_0_u_front__q_data_in[109]
    DIRECTION INPUT ;
    USE SIGNAL ;
    PORT
      LAYER M5 ;
        RECT  25.884 215.808 25.908 216 ;
    END
  END g_front_0_u_front__q_data_in[109]
  PIN g_front_0_u_front__q_data_in[10]
    DIRECTION INPUT ;
    USE SIGNAL ;
    PORT
      LAYER M5 ;
        RECT  10.188 215.808 10.212 216 ;
    END
  END g_front_0_u_front__q_data_in[10]
  PIN g_front_0_u_front__q_data_in[110]
    DIRECTION INPUT ;
    USE SIGNAL ;
    PORT
      LAYER M5 ;
        RECT  26.076 215.808 26.1 216 ;
    END
  END g_front_0_u_front__q_data_in[110]
  PIN g_front_0_u_front__q_data_in[111]
    DIRECTION INPUT ;
    USE SIGNAL ;
    PORT
      LAYER M5 ;
        RECT  26.22 215.808 26.244 216 ;
    END
  END g_front_0_u_front__q_data_in[111]
  PIN g_front_0_u_front__q_data_in[112]
    DIRECTION INPUT ;
    USE SIGNAL ;
    PORT
      LAYER M5 ;
        RECT  26.364 215.808 26.388 216 ;
    END
  END g_front_0_u_front__q_data_in[112]
  PIN g_front_0_u_front__q_data_in[113]
    DIRECTION INPUT ;
    USE SIGNAL ;
    PORT
      LAYER M5 ;
        RECT  26.556 215.808 26.58 216 ;
    END
  END g_front_0_u_front__q_data_in[113]
  PIN g_front_0_u_front__q_data_in[114]
    DIRECTION INPUT ;
    USE SIGNAL ;
    PORT
      LAYER M5 ;
        RECT  26.7 215.808 26.724 216 ;
    END
  END g_front_0_u_front__q_data_in[114]
  PIN g_front_0_u_front__q_data_in[115]
    DIRECTION INPUT ;
    USE SIGNAL ;
    PORT
      LAYER M5 ;
        RECT  26.844 215.808 26.868 216 ;
    END
  END g_front_0_u_front__q_data_in[115]
  PIN g_front_0_u_front__q_data_in[116]
    DIRECTION INPUT ;
    USE SIGNAL ;
    PORT
      LAYER M5 ;
        RECT  27.036 215.808 27.06 216 ;
    END
  END g_front_0_u_front__q_data_in[116]
  PIN g_front_0_u_front__q_data_in[117]
    DIRECTION INPUT ;
    USE SIGNAL ;
    PORT
      LAYER M5 ;
        RECT  27.18 215.808 27.204 216 ;
    END
  END g_front_0_u_front__q_data_in[117]
  PIN g_front_0_u_front__q_data_in[118]
    DIRECTION INPUT ;
    USE SIGNAL ;
    PORT
      LAYER M5 ;
        RECT  27.324 215.808 27.348 216 ;
    END
  END g_front_0_u_front__q_data_in[118]
  PIN g_front_0_u_front__q_data_in[119]
    DIRECTION INPUT ;
    USE SIGNAL ;
    PORT
      LAYER M5 ;
        RECT  27.516 215.808 27.54 216 ;
    END
  END g_front_0_u_front__q_data_in[119]
  PIN g_front_0_u_front__q_data_in[11]
    DIRECTION INPUT ;
    USE SIGNAL ;
    PORT
      LAYER M5 ;
        RECT  10.332 215.808 10.356 216 ;
    END
  END g_front_0_u_front__q_data_in[11]
  PIN g_front_0_u_front__q_data_in[120]
    DIRECTION INPUT ;
    USE SIGNAL ;
    PORT
      LAYER M5 ;
        RECT  27.66 215.808 27.684 216 ;
    END
  END g_front_0_u_front__q_data_in[120]
  PIN g_front_0_u_front__q_data_in[121]
    DIRECTION INPUT ;
    USE SIGNAL ;
    PORT
      LAYER M5 ;
        RECT  27.804 215.808 27.828 216 ;
    END
  END g_front_0_u_front__q_data_in[121]
  PIN g_front_0_u_front__q_data_in[122]
    DIRECTION INPUT ;
    USE SIGNAL ;
    PORT
      LAYER M5 ;
        RECT  27.996 215.808 28.02 216 ;
    END
  END g_front_0_u_front__q_data_in[122]
  PIN g_front_0_u_front__q_data_in[123]
    DIRECTION INPUT ;
    USE SIGNAL ;
    PORT
      LAYER M5 ;
        RECT  28.14 215.808 28.164 216 ;
    END
  END g_front_0_u_front__q_data_in[123]
  PIN g_front_0_u_front__q_data_in[124]
    DIRECTION INPUT ;
    USE SIGNAL ;
    PORT
      LAYER M5 ;
        RECT  28.284 215.808 28.308 216 ;
    END
  END g_front_0_u_front__q_data_in[124]
  PIN g_front_0_u_front__q_data_in[125]
    DIRECTION INPUT ;
    USE SIGNAL ;
    PORT
      LAYER M5 ;
        RECT  28.428 215.808 28.452 216 ;
    END
  END g_front_0_u_front__q_data_in[125]
  PIN g_front_0_u_front__q_data_in[126]
    DIRECTION INPUT ;
    USE SIGNAL ;
    PORT
      LAYER M5 ;
        RECT  28.62 215.808 28.644 216 ;
    END
  END g_front_0_u_front__q_data_in[126]
  PIN g_front_0_u_front__q_data_in[127]
    DIRECTION INPUT ;
    USE SIGNAL ;
    PORT
      LAYER M5 ;
        RECT  28.764 215.808 28.788 216 ;
    END
  END g_front_0_u_front__q_data_in[127]
  PIN g_front_0_u_front__q_data_in[128]
    DIRECTION INPUT ;
    USE SIGNAL ;
    PORT
      LAYER M5 ;
        RECT  28.908 215.808 28.932 216 ;
    END
  END g_front_0_u_front__q_data_in[128]
  PIN g_front_0_u_front__q_data_in[129]
    DIRECTION INPUT ;
    USE SIGNAL ;
    PORT
      LAYER M5 ;
        RECT  29.1 215.808 29.124 216 ;
    END
  END g_front_0_u_front__q_data_in[129]
  PIN g_front_0_u_front__q_data_in[12]
    DIRECTION INPUT ;
    USE SIGNAL ;
    PORT
      LAYER M5 ;
        RECT  10.476 215.808 10.5 216 ;
    END
  END g_front_0_u_front__q_data_in[12]
  PIN g_front_0_u_front__q_data_in[130]
    DIRECTION INPUT ;
    USE SIGNAL ;
    PORT
      LAYER M5 ;
        RECT  29.244 215.808 29.268 216 ;
    END
  END g_front_0_u_front__q_data_in[130]
  PIN g_front_0_u_front__q_data_in[131]
    DIRECTION INPUT ;
    USE SIGNAL ;
    PORT
      LAYER M5 ;
        RECT  29.388 215.808 29.412 216 ;
    END
  END g_front_0_u_front__q_data_in[131]
  PIN g_front_0_u_front__q_data_in[132]
    DIRECTION INPUT ;
    USE SIGNAL ;
    PORT
      LAYER M5 ;
        RECT  29.58 215.808 29.604 216 ;
    END
  END g_front_0_u_front__q_data_in[132]
  PIN g_front_0_u_front__q_data_in[133]
    DIRECTION INPUT ;
    USE SIGNAL ;
    PORT
      LAYER M5 ;
        RECT  29.724 215.808 29.748 216 ;
    END
  END g_front_0_u_front__q_data_in[133]
  PIN g_front_0_u_front__q_data_in[134]
    DIRECTION INPUT ;
    USE SIGNAL ;
    PORT
      LAYER M5 ;
        RECT  29.868 215.808 29.892 216 ;
    END
  END g_front_0_u_front__q_data_in[134]
  PIN g_front_0_u_front__q_data_in[135]
    DIRECTION INPUT ;
    USE SIGNAL ;
    PORT
      LAYER M5 ;
        RECT  30.06 215.808 30.084 216 ;
    END
  END g_front_0_u_front__q_data_in[135]
  PIN g_front_0_u_front__q_data_in[136]
    DIRECTION INPUT ;
    USE SIGNAL ;
    PORT
      LAYER M5 ;
        RECT  30.204 215.808 30.228 216 ;
    END
  END g_front_0_u_front__q_data_in[136]
  PIN g_front_0_u_front__q_data_in[137]
    DIRECTION INPUT ;
    USE SIGNAL ;
    PORT
      LAYER M5 ;
        RECT  30.348 215.808 30.372 216 ;
    END
  END g_front_0_u_front__q_data_in[137]
  PIN g_front_0_u_front__q_data_in[138]
    DIRECTION INPUT ;
    USE SIGNAL ;
    PORT
      LAYER M5 ;
        RECT  30.492 215.808 30.516 216 ;
    END
  END g_front_0_u_front__q_data_in[138]
  PIN g_front_0_u_front__q_data_in[139]
    DIRECTION INPUT ;
    USE SIGNAL ;
    PORT
      LAYER M5 ;
        RECT  30.684 215.808 30.708 216 ;
    END
  END g_front_0_u_front__q_data_in[139]
  PIN g_front_0_u_front__q_data_in[13]
    DIRECTION INPUT ;
    USE SIGNAL ;
    PORT
      LAYER M5 ;
        RECT  10.668 215.808 10.692 216 ;
    END
  END g_front_0_u_front__q_data_in[13]
  PIN g_front_0_u_front__q_data_in[140]
    DIRECTION INPUT ;
    USE SIGNAL ;
    PORT
      LAYER M5 ;
        RECT  30.828 215.808 30.852 216 ;
    END
  END g_front_0_u_front__q_data_in[140]
  PIN g_front_0_u_front__q_data_in[141]
    DIRECTION INPUT ;
    USE SIGNAL ;
    PORT
      LAYER M5 ;
        RECT  30.972 215.808 30.996 216 ;
    END
  END g_front_0_u_front__q_data_in[141]
  PIN g_front_0_u_front__q_data_in[142]
    DIRECTION INPUT ;
    USE SIGNAL ;
    PORT
      LAYER M5 ;
        RECT  31.164 215.808 31.188 216 ;
    END
  END g_front_0_u_front__q_data_in[142]
  PIN g_front_0_u_front__q_data_in[143]
    DIRECTION INPUT ;
    USE SIGNAL ;
    PORT
      LAYER M5 ;
        RECT  31.308 215.808 31.332 216 ;
    END
  END g_front_0_u_front__q_data_in[143]
  PIN g_front_0_u_front__q_data_in[144]
    DIRECTION INPUT ;
    USE SIGNAL ;
    PORT
      LAYER M5 ;
        RECT  31.452 215.808 31.476 216 ;
    END
  END g_front_0_u_front__q_data_in[144]
  PIN g_front_0_u_front__q_data_in[145]
    DIRECTION INPUT ;
    USE SIGNAL ;
    PORT
      LAYER M5 ;
        RECT  31.644 215.808 31.668 216 ;
    END
  END g_front_0_u_front__q_data_in[145]
  PIN g_front_0_u_front__q_data_in[146]
    DIRECTION INPUT ;
    USE SIGNAL ;
    PORT
      LAYER M5 ;
        RECT  31.788 215.808 31.812 216 ;
    END
  END g_front_0_u_front__q_data_in[146]
  PIN g_front_0_u_front__q_data_in[147]
    DIRECTION INPUT ;
    USE SIGNAL ;
    PORT
      LAYER M5 ;
        RECT  31.932 215.808 31.956 216 ;
    END
  END g_front_0_u_front__q_data_in[147]
  PIN g_front_0_u_front__q_data_in[148]
    DIRECTION INPUT ;
    USE SIGNAL ;
    PORT
      LAYER M5 ;
        RECT  32.124 215.808 32.148 216 ;
    END
  END g_front_0_u_front__q_data_in[148]
  PIN g_front_0_u_front__q_data_in[149]
    DIRECTION INPUT ;
    USE SIGNAL ;
    PORT
      LAYER M5 ;
        RECT  32.268 215.808 32.292 216 ;
    END
  END g_front_0_u_front__q_data_in[149]
  PIN g_front_0_u_front__q_data_in[14]
    DIRECTION INPUT ;
    USE SIGNAL ;
    PORT
      LAYER M5 ;
        RECT  10.812 215.808 10.836 216 ;
    END
  END g_front_0_u_front__q_data_in[14]
  PIN g_front_0_u_front__q_data_in[150]
    DIRECTION INPUT ;
    USE SIGNAL ;
    PORT
      LAYER M5 ;
        RECT  32.412 215.808 32.436 216 ;
    END
  END g_front_0_u_front__q_data_in[150]
  PIN g_front_0_u_front__q_data_in[151]
    DIRECTION INPUT ;
    USE SIGNAL ;
    PORT
      LAYER M5 ;
        RECT  32.604 215.808 32.628 216 ;
    END
  END g_front_0_u_front__q_data_in[151]
  PIN g_front_0_u_front__q_data_in[152]
    DIRECTION INPUT ;
    USE SIGNAL ;
    PORT
      LAYER M5 ;
        RECT  32.748 215.808 32.772 216 ;
    END
  END g_front_0_u_front__q_data_in[152]
  PIN g_front_0_u_front__q_data_in[153]
    DIRECTION INPUT ;
    USE SIGNAL ;
    PORT
      LAYER M5 ;
        RECT  32.892 215.808 32.916 216 ;
    END
  END g_front_0_u_front__q_data_in[153]
  PIN g_front_0_u_front__q_data_in[154]
    DIRECTION INPUT ;
    USE SIGNAL ;
    PORT
      LAYER M5 ;
        RECT  33.036 215.808 33.06 216 ;
    END
  END g_front_0_u_front__q_data_in[154]
  PIN g_front_0_u_front__q_data_in[155]
    DIRECTION INPUT ;
    USE SIGNAL ;
    PORT
      LAYER M5 ;
        RECT  33.228 215.808 33.252 216 ;
    END
  END g_front_0_u_front__q_data_in[155]
  PIN g_front_0_u_front__q_data_in[156]
    DIRECTION INPUT ;
    USE SIGNAL ;
    PORT
      LAYER M5 ;
        RECT  33.372 215.808 33.396 216 ;
    END
  END g_front_0_u_front__q_data_in[156]
  PIN g_front_0_u_front__q_data_in[157]
    DIRECTION INPUT ;
    USE SIGNAL ;
    PORT
      LAYER M5 ;
        RECT  33.516 215.808 33.54 216 ;
    END
  END g_front_0_u_front__q_data_in[157]
  PIN g_front_0_u_front__q_data_in[158]
    DIRECTION INPUT ;
    USE SIGNAL ;
    PORT
      LAYER M5 ;
        RECT  33.708 215.808 33.732 216 ;
    END
  END g_front_0_u_front__q_data_in[158]
  PIN g_front_0_u_front__q_data_in[159]
    DIRECTION INPUT ;
    USE SIGNAL ;
    PORT
      LAYER M5 ;
        RECT  33.852 215.808 33.876 216 ;
    END
  END g_front_0_u_front__q_data_in[159]
  PIN g_front_0_u_front__q_data_in[15]
    DIRECTION INPUT ;
    USE SIGNAL ;
    PORT
      LAYER M5 ;
        RECT  10.956 215.808 10.98 216 ;
    END
  END g_front_0_u_front__q_data_in[15]
  PIN g_front_0_u_front__q_data_in[160]
    DIRECTION INPUT ;
    USE SIGNAL ;
    PORT
      LAYER M5 ;
        RECT  33.996 215.808 34.02 216 ;
    END
  END g_front_0_u_front__q_data_in[160]
  PIN g_front_0_u_front__q_data_in[161]
    DIRECTION INPUT ;
    USE SIGNAL ;
    PORT
      LAYER M5 ;
        RECT  34.188 215.808 34.212 216 ;
    END
  END g_front_0_u_front__q_data_in[161]
  PIN g_front_0_u_front__q_data_in[162]
    DIRECTION INPUT ;
    USE SIGNAL ;
    PORT
      LAYER M5 ;
        RECT  34.332 215.808 34.356 216 ;
    END
  END g_front_0_u_front__q_data_in[162]
  PIN g_front_0_u_front__q_data_in[163]
    DIRECTION INPUT ;
    USE SIGNAL ;
    PORT
      LAYER M5 ;
        RECT  34.476 215.808 34.5 216 ;
    END
  END g_front_0_u_front__q_data_in[163]
  PIN g_front_0_u_front__q_data_in[164]
    DIRECTION INPUT ;
    USE SIGNAL ;
    PORT
      LAYER M5 ;
        RECT  34.668 215.808 34.692 216 ;
    END
  END g_front_0_u_front__q_data_in[164]
  PIN g_front_0_u_front__q_data_in[165]
    DIRECTION INPUT ;
    USE SIGNAL ;
    PORT
      LAYER M5 ;
        RECT  34.812 215.808 34.836 216 ;
    END
  END g_front_0_u_front__q_data_in[165]
  PIN g_front_0_u_front__q_data_in[166]
    DIRECTION INPUT ;
    USE SIGNAL ;
    PORT
      LAYER M5 ;
        RECT  34.956 215.808 34.98 216 ;
    END
  END g_front_0_u_front__q_data_in[166]
  PIN g_front_0_u_front__q_data_in[167]
    DIRECTION INPUT ;
    USE SIGNAL ;
    PORT
      LAYER M5 ;
        RECT  35.1 215.808 35.124 216 ;
    END
  END g_front_0_u_front__q_data_in[167]
  PIN g_front_0_u_front__q_data_in[168]
    DIRECTION INPUT ;
    USE SIGNAL ;
    PORT
      LAYER M5 ;
        RECT  35.292 215.808 35.316 216 ;
    END
  END g_front_0_u_front__q_data_in[168]
  PIN g_front_0_u_front__q_data_in[169]
    DIRECTION INPUT ;
    USE SIGNAL ;
    PORT
      LAYER M5 ;
        RECT  35.436 215.808 35.46 216 ;
    END
  END g_front_0_u_front__q_data_in[169]
  PIN g_front_0_u_front__q_data_in[16]
    DIRECTION INPUT ;
    USE SIGNAL ;
    PORT
      LAYER M5 ;
        RECT  11.148 215.808 11.172 216 ;
    END
  END g_front_0_u_front__q_data_in[16]
  PIN g_front_0_u_front__q_data_in[170]
    DIRECTION INPUT ;
    USE SIGNAL ;
    PORT
      LAYER M5 ;
        RECT  35.58 215.808 35.604 216 ;
    END
  END g_front_0_u_front__q_data_in[170]
  PIN g_front_0_u_front__q_data_in[171]
    DIRECTION INPUT ;
    USE SIGNAL ;
    PORT
      LAYER M5 ;
        RECT  35.772 215.808 35.796 216 ;
    END
  END g_front_0_u_front__q_data_in[171]
  PIN g_front_0_u_front__q_data_in[172]
    DIRECTION INPUT ;
    USE SIGNAL ;
    PORT
      LAYER M5 ;
        RECT  35.916 215.808 35.94 216 ;
    END
  END g_front_0_u_front__q_data_in[172]
  PIN g_front_0_u_front__q_data_in[173]
    DIRECTION INPUT ;
    USE SIGNAL ;
    PORT
      LAYER M5 ;
        RECT  36.06 215.808 36.084 216 ;
    END
  END g_front_0_u_front__q_data_in[173]
  PIN g_front_0_u_front__q_data_in[174]
    DIRECTION INPUT ;
    USE SIGNAL ;
    PORT
      LAYER M5 ;
        RECT  36.252 215.808 36.276 216 ;
    END
  END g_front_0_u_front__q_data_in[174]
  PIN g_front_0_u_front__q_data_in[175]
    DIRECTION INPUT ;
    USE SIGNAL ;
    PORT
      LAYER M5 ;
        RECT  36.396 215.808 36.42 216 ;
    END
  END g_front_0_u_front__q_data_in[175]
  PIN g_front_0_u_front__q_data_in[176]
    DIRECTION INPUT ;
    USE SIGNAL ;
    PORT
      LAYER M5 ;
        RECT  36.54 215.808 36.564 216 ;
    END
  END g_front_0_u_front__q_data_in[176]
  PIN g_front_0_u_front__q_data_in[177]
    DIRECTION INPUT ;
    USE SIGNAL ;
    PORT
      LAYER M5 ;
        RECT  36.732 215.808 36.756 216 ;
    END
  END g_front_0_u_front__q_data_in[177]
  PIN g_front_0_u_front__q_data_in[178]
    DIRECTION INPUT ;
    USE SIGNAL ;
    PORT
      LAYER M5 ;
        RECT  36.876 215.808 36.9 216 ;
    END
  END g_front_0_u_front__q_data_in[178]
  PIN g_front_0_u_front__q_data_in[179]
    DIRECTION INPUT ;
    USE SIGNAL ;
    PORT
      LAYER M5 ;
        RECT  37.02 215.808 37.044 216 ;
    END
  END g_front_0_u_front__q_data_in[179]
  PIN g_front_0_u_front__q_data_in[17]
    DIRECTION INPUT ;
    USE SIGNAL ;
    PORT
      LAYER M5 ;
        RECT  11.292 215.808 11.316 216 ;
    END
  END g_front_0_u_front__q_data_in[17]
  PIN g_front_0_u_front__q_data_in[180]
    DIRECTION INPUT ;
    USE SIGNAL ;
    PORT
      LAYER M5 ;
        RECT  37.212 215.808 37.236 216 ;
    END
  END g_front_0_u_front__q_data_in[180]
  PIN g_front_0_u_front__q_data_in[181]
    DIRECTION INPUT ;
    USE SIGNAL ;
    PORT
      LAYER M5 ;
        RECT  37.356 215.808 37.38 216 ;
    END
  END g_front_0_u_front__q_data_in[181]
  PIN g_front_0_u_front__q_data_in[182]
    DIRECTION INPUT ;
    USE SIGNAL ;
    PORT
      LAYER M5 ;
        RECT  37.5 215.808 37.524 216 ;
    END
  END g_front_0_u_front__q_data_in[182]
  PIN g_front_0_u_front__q_data_in[183]
    DIRECTION INPUT ;
    USE SIGNAL ;
    PORT
      LAYER M5 ;
        RECT  37.644 215.808 37.668 216 ;
    END
  END g_front_0_u_front__q_data_in[183]
  PIN g_front_0_u_front__q_data_in[184]
    DIRECTION INPUT ;
    USE SIGNAL ;
    PORT
      LAYER M5 ;
        RECT  37.836 215.808 37.86 216 ;
    END
  END g_front_0_u_front__q_data_in[184]
  PIN g_front_0_u_front__q_data_in[185]
    DIRECTION INPUT ;
    USE SIGNAL ;
    PORT
      LAYER M5 ;
        RECT  37.98 215.808 38.004 216 ;
    END
  END g_front_0_u_front__q_data_in[185]
  PIN g_front_0_u_front__q_data_in[186]
    DIRECTION INPUT ;
    USE SIGNAL ;
    PORT
      LAYER M5 ;
        RECT  38.124 215.808 38.148 216 ;
    END
  END g_front_0_u_front__q_data_in[186]
  PIN g_front_0_u_front__q_data_in[187]
    DIRECTION INPUT ;
    USE SIGNAL ;
    PORT
      LAYER M5 ;
        RECT  38.316 215.808 38.34 216 ;
    END
  END g_front_0_u_front__q_data_in[187]
  PIN g_front_0_u_front__q_data_in[188]
    DIRECTION INPUT ;
    USE SIGNAL ;
    PORT
      LAYER M5 ;
        RECT  38.46 215.808 38.484 216 ;
    END
  END g_front_0_u_front__q_data_in[188]
  PIN g_front_0_u_front__q_data_in[189]
    DIRECTION INPUT ;
    USE SIGNAL ;
    PORT
      LAYER M5 ;
        RECT  38.604 215.808 38.628 216 ;
    END
  END g_front_0_u_front__q_data_in[189]
  PIN g_front_0_u_front__q_data_in[18]
    DIRECTION INPUT ;
    USE SIGNAL ;
    PORT
      LAYER M5 ;
        RECT  11.436 215.808 11.46 216 ;
    END
  END g_front_0_u_front__q_data_in[18]
  PIN g_front_0_u_front__q_data_in[190]
    DIRECTION INPUT ;
    USE SIGNAL ;
    PORT
      LAYER M5 ;
        RECT  38.796 215.808 38.82 216 ;
    END
  END g_front_0_u_front__q_data_in[190]
  PIN g_front_0_u_front__q_data_in[191]
    DIRECTION INPUT ;
    USE SIGNAL ;
    PORT
      LAYER M5 ;
        RECT  38.94 215.808 38.964 216 ;
    END
  END g_front_0_u_front__q_data_in[191]
  PIN g_front_0_u_front__q_data_in[192]
    DIRECTION INPUT ;
    USE SIGNAL ;
    PORT
      LAYER M5 ;
        RECT  39.084 215.808 39.108 216 ;
    END
  END g_front_0_u_front__q_data_in[192]
  PIN g_front_0_u_front__q_data_in[193]
    DIRECTION INPUT ;
    USE SIGNAL ;
    PORT
      LAYER M5 ;
        RECT  39.276 215.808 39.3 216 ;
    END
  END g_front_0_u_front__q_data_in[193]
  PIN g_front_0_u_front__q_data_in[194]
    DIRECTION INPUT ;
    USE SIGNAL ;
    PORT
      LAYER M5 ;
        RECT  39.42 215.808 39.444 216 ;
    END
  END g_front_0_u_front__q_data_in[194]
  PIN g_front_0_u_front__q_data_in[195]
    DIRECTION INPUT ;
    USE SIGNAL ;
    PORT
      LAYER M5 ;
        RECT  39.564 215.808 39.588 216 ;
    END
  END g_front_0_u_front__q_data_in[195]
  PIN g_front_0_u_front__q_data_in[196]
    DIRECTION INPUT ;
    USE SIGNAL ;
    PORT
      LAYER M5 ;
        RECT  39.756 215.808 39.78 216 ;
    END
  END g_front_0_u_front__q_data_in[196]
  PIN g_front_0_u_front__q_data_in[197]
    DIRECTION INPUT ;
    USE SIGNAL ;
    PORT
      LAYER M5 ;
        RECT  39.9 215.808 39.924 216 ;
    END
  END g_front_0_u_front__q_data_in[197]
  PIN g_front_0_u_front__q_data_in[198]
    DIRECTION INPUT ;
    USE SIGNAL ;
    PORT
      LAYER M5 ;
        RECT  40.044 215.808 40.068 216 ;
    END
  END g_front_0_u_front__q_data_in[198]
  PIN g_front_0_u_front__q_data_in[199]
    DIRECTION INPUT ;
    USE SIGNAL ;
    PORT
      LAYER M5 ;
        RECT  40.188 215.808 40.212 216 ;
    END
  END g_front_0_u_front__q_data_in[199]
  PIN g_front_0_u_front__q_data_in[19]
    DIRECTION INPUT ;
    USE SIGNAL ;
    PORT
      LAYER M5 ;
        RECT  11.58 215.808 11.604 216 ;
    END
  END g_front_0_u_front__q_data_in[19]
  PIN g_front_0_u_front__q_data_in[1]
    DIRECTION INPUT ;
    USE SIGNAL ;
    PORT
      LAYER M5 ;
        RECT  8.748 215.808 8.772 216 ;
    END
  END g_front_0_u_front__q_data_in[1]
  PIN g_front_0_u_front__q_data_in[200]
    DIRECTION INPUT ;
    USE SIGNAL ;
    PORT
      LAYER M5 ;
        RECT  40.38 215.808 40.404 216 ;
    END
  END g_front_0_u_front__q_data_in[200]
  PIN g_front_0_u_front__q_data_in[201]
    DIRECTION INPUT ;
    USE SIGNAL ;
    PORT
      LAYER M5 ;
        RECT  40.524 215.808 40.548 216 ;
    END
  END g_front_0_u_front__q_data_in[201]
  PIN g_front_0_u_front__q_data_in[202]
    DIRECTION INPUT ;
    USE SIGNAL ;
    PORT
      LAYER M5 ;
        RECT  40.668 215.808 40.692 216 ;
    END
  END g_front_0_u_front__q_data_in[202]
  PIN g_front_0_u_front__q_data_in[203]
    DIRECTION INPUT ;
    USE SIGNAL ;
    PORT
      LAYER M5 ;
        RECT  40.86 215.808 40.884 216 ;
    END
  END g_front_0_u_front__q_data_in[203]
  PIN g_front_0_u_front__q_data_in[204]
    DIRECTION INPUT ;
    USE SIGNAL ;
    PORT
      LAYER M5 ;
        RECT  41.004 215.808 41.028 216 ;
    END
  END g_front_0_u_front__q_data_in[204]
  PIN g_front_0_u_front__q_data_in[205]
    DIRECTION INPUT ;
    USE SIGNAL ;
    PORT
      LAYER M5 ;
        RECT  41.148 215.808 41.172 216 ;
    END
  END g_front_0_u_front__q_data_in[205]
  PIN g_front_0_u_front__q_data_in[206]
    DIRECTION INPUT ;
    USE SIGNAL ;
    PORT
      LAYER M5 ;
        RECT  41.34 215.808 41.364 216 ;
    END
  END g_front_0_u_front__q_data_in[206]
  PIN g_front_0_u_front__q_data_in[207]
    DIRECTION INPUT ;
    USE SIGNAL ;
    PORT
      LAYER M5 ;
        RECT  41.484 215.808 41.508 216 ;
    END
  END g_front_0_u_front__q_data_in[207]
  PIN g_front_0_u_front__q_data_in[208]
    DIRECTION INPUT ;
    USE SIGNAL ;
    PORT
      LAYER M5 ;
        RECT  41.628 215.808 41.652 216 ;
    END
  END g_front_0_u_front__q_data_in[208]
  PIN g_front_0_u_front__q_data_in[209]
    DIRECTION INPUT ;
    USE SIGNAL ;
    PORT
      LAYER M5 ;
        RECT  41.82 215.808 41.844 216 ;
    END
  END g_front_0_u_front__q_data_in[209]
  PIN g_front_0_u_front__q_data_in[20]
    DIRECTION INPUT ;
    USE SIGNAL ;
    PORT
      LAYER M5 ;
        RECT  11.772 215.808 11.796 216 ;
    END
  END g_front_0_u_front__q_data_in[20]
  PIN g_front_0_u_front__q_data_in[210]
    DIRECTION INPUT ;
    USE SIGNAL ;
    PORT
      LAYER M5 ;
        RECT  41.964 215.808 41.988 216 ;
    END
  END g_front_0_u_front__q_data_in[210]
  PIN g_front_0_u_front__q_data_in[211]
    DIRECTION INPUT ;
    USE SIGNAL ;
    PORT
      LAYER M5 ;
        RECT  42.108 215.808 42.132 216 ;
    END
  END g_front_0_u_front__q_data_in[211]
  PIN g_front_0_u_front__q_data_in[212]
    DIRECTION INPUT ;
    USE SIGNAL ;
    PORT
      LAYER M5 ;
        RECT  42.252 215.808 42.276 216 ;
    END
  END g_front_0_u_front__q_data_in[212]
  PIN g_front_0_u_front__q_data_in[213]
    DIRECTION INPUT ;
    USE SIGNAL ;
    PORT
      LAYER M5 ;
        RECT  42.444 215.808 42.468 216 ;
    END
  END g_front_0_u_front__q_data_in[213]
  PIN g_front_0_u_front__q_data_in[214]
    DIRECTION INPUT ;
    USE SIGNAL ;
    PORT
      LAYER M5 ;
        RECT  42.588 215.808 42.612 216 ;
    END
  END g_front_0_u_front__q_data_in[214]
  PIN g_front_0_u_front__q_data_in[215]
    DIRECTION INPUT ;
    USE SIGNAL ;
    PORT
      LAYER M5 ;
        RECT  42.732 215.808 42.756 216 ;
    END
  END g_front_0_u_front__q_data_in[215]
  PIN g_front_0_u_front__q_data_in[216]
    DIRECTION INPUT ;
    USE SIGNAL ;
    PORT
      LAYER M5 ;
        RECT  42.924 215.808 42.948 216 ;
    END
  END g_front_0_u_front__q_data_in[216]
  PIN g_front_0_u_front__q_data_in[217]
    DIRECTION INPUT ;
    USE SIGNAL ;
    PORT
      LAYER M5 ;
        RECT  43.068 215.808 43.092 216 ;
    END
  END g_front_0_u_front__q_data_in[217]
  PIN g_front_0_u_front__q_data_in[218]
    DIRECTION INPUT ;
    USE SIGNAL ;
    PORT
      LAYER M5 ;
        RECT  43.212 215.808 43.236 216 ;
    END
  END g_front_0_u_front__q_data_in[218]
  PIN g_front_0_u_front__q_data_in[219]
    DIRECTION INPUT ;
    USE SIGNAL ;
    PORT
      LAYER M5 ;
        RECT  43.404 215.808 43.428 216 ;
    END
  END g_front_0_u_front__q_data_in[219]
  PIN g_front_0_u_front__q_data_in[21]
    DIRECTION INPUT ;
    USE SIGNAL ;
    PORT
      LAYER M5 ;
        RECT  11.916 215.808 11.94 216 ;
    END
  END g_front_0_u_front__q_data_in[21]
  PIN g_front_0_u_front__q_data_in[220]
    DIRECTION INPUT ;
    USE SIGNAL ;
    PORT
      LAYER M5 ;
        RECT  43.548 215.808 43.572 216 ;
    END
  END g_front_0_u_front__q_data_in[220]
  PIN g_front_0_u_front__q_data_in[221]
    DIRECTION INPUT ;
    USE SIGNAL ;
    PORT
      LAYER M5 ;
        RECT  43.692 215.808 43.716 216 ;
    END
  END g_front_0_u_front__q_data_in[221]
  PIN g_front_0_u_front__q_data_in[222]
    DIRECTION INPUT ;
    USE SIGNAL ;
    PORT
      LAYER M5 ;
        RECT  43.884 215.808 43.908 216 ;
    END
  END g_front_0_u_front__q_data_in[222]
  PIN g_front_0_u_front__q_data_in[223]
    DIRECTION INPUT ;
    USE SIGNAL ;
    PORT
      LAYER M5 ;
        RECT  44.028 215.808 44.052 216 ;
    END
  END g_front_0_u_front__q_data_in[223]
  PIN g_front_0_u_front__q_data_in[224]
    DIRECTION INPUT ;
    USE SIGNAL ;
    PORT
      LAYER M5 ;
        RECT  44.172 215.808 44.196 216 ;
    END
  END g_front_0_u_front__q_data_in[224]
  PIN g_front_0_u_front__q_data_in[225]
    DIRECTION INPUT ;
    USE SIGNAL ;
    PORT
      LAYER M5 ;
        RECT  44.364 215.808 44.388 216 ;
    END
  END g_front_0_u_front__q_data_in[225]
  PIN g_front_0_u_front__q_data_in[226]
    DIRECTION INPUT ;
    USE SIGNAL ;
    PORT
      LAYER M5 ;
        RECT  44.508 215.808 44.532 216 ;
    END
  END g_front_0_u_front__q_data_in[226]
  PIN g_front_0_u_front__q_data_in[227]
    DIRECTION INPUT ;
    USE SIGNAL ;
    PORT
      LAYER M5 ;
        RECT  44.652 215.808 44.676 216 ;
    END
  END g_front_0_u_front__q_data_in[227]
  PIN g_front_0_u_front__q_data_in[228]
    DIRECTION INPUT ;
    USE SIGNAL ;
    PORT
      LAYER M5 ;
        RECT  44.796 215.808 44.82 216 ;
    END
  END g_front_0_u_front__q_data_in[228]
  PIN g_front_0_u_front__q_data_in[229]
    DIRECTION INPUT ;
    USE SIGNAL ;
    PORT
      LAYER M5 ;
        RECT  44.988 215.808 45.012 216 ;
    END
  END g_front_0_u_front__q_data_in[229]
  PIN g_front_0_u_front__q_data_in[22]
    DIRECTION INPUT ;
    USE SIGNAL ;
    PORT
      LAYER M5 ;
        RECT  12.06 215.808 12.084 216 ;
    END
  END g_front_0_u_front__q_data_in[22]
  PIN g_front_0_u_front__q_data_in[230]
    DIRECTION INPUT ;
    USE SIGNAL ;
    PORT
      LAYER M5 ;
        RECT  45.132 215.808 45.156 216 ;
    END
  END g_front_0_u_front__q_data_in[230]
  PIN g_front_0_u_front__q_data_in[231]
    DIRECTION INPUT ;
    USE SIGNAL ;
    PORT
      LAYER M5 ;
        RECT  45.276 215.808 45.3 216 ;
    END
  END g_front_0_u_front__q_data_in[231]
  PIN g_front_0_u_front__q_data_in[232]
    DIRECTION INPUT ;
    USE SIGNAL ;
    PORT
      LAYER M5 ;
        RECT  45.468 215.808 45.492 216 ;
    END
  END g_front_0_u_front__q_data_in[232]
  PIN g_front_0_u_front__q_data_in[233]
    DIRECTION INPUT ;
    USE SIGNAL ;
    PORT
      LAYER M5 ;
        RECT  45.612 215.808 45.636 216 ;
    END
  END g_front_0_u_front__q_data_in[233]
  PIN g_front_0_u_front__q_data_in[234]
    DIRECTION INPUT ;
    USE SIGNAL ;
    PORT
      LAYER M5 ;
        RECT  45.756 215.808 45.78 216 ;
    END
  END g_front_0_u_front__q_data_in[234]
  PIN g_front_0_u_front__q_data_in[235]
    DIRECTION INPUT ;
    USE SIGNAL ;
    PORT
      LAYER M5 ;
        RECT  45.948 215.808 45.972 216 ;
    END
  END g_front_0_u_front__q_data_in[235]
  PIN g_front_0_u_front__q_data_in[236]
    DIRECTION INPUT ;
    USE SIGNAL ;
    PORT
      LAYER M5 ;
        RECT  46.092 215.808 46.116 216 ;
    END
  END g_front_0_u_front__q_data_in[236]
  PIN g_front_0_u_front__q_data_in[237]
    DIRECTION INPUT ;
    USE SIGNAL ;
    PORT
      LAYER M5 ;
        RECT  46.236 215.808 46.26 216 ;
    END
  END g_front_0_u_front__q_data_in[237]
  PIN g_front_0_u_front__q_data_in[238]
    DIRECTION INPUT ;
    USE SIGNAL ;
    PORT
      LAYER M5 ;
        RECT  46.428 215.808 46.452 216 ;
    END
  END g_front_0_u_front__q_data_in[238]
  PIN g_front_0_u_front__q_data_in[239]
    DIRECTION INPUT ;
    USE SIGNAL ;
    PORT
      LAYER M5 ;
        RECT  46.572 215.808 46.596 216 ;
    END
  END g_front_0_u_front__q_data_in[239]
  PIN g_front_0_u_front__q_data_in[23]
    DIRECTION INPUT ;
    USE SIGNAL ;
    PORT
      LAYER M5 ;
        RECT  12.252 215.808 12.276 216 ;
    END
  END g_front_0_u_front__q_data_in[23]
  PIN g_front_0_u_front__q_data_in[240]
    DIRECTION INPUT ;
    USE SIGNAL ;
    PORT
      LAYER M5 ;
        RECT  46.716 215.808 46.74 216 ;
    END
  END g_front_0_u_front__q_data_in[240]
  PIN g_front_0_u_front__q_data_in[241]
    DIRECTION INPUT ;
    USE SIGNAL ;
    PORT
      LAYER M5 ;
        RECT  46.86 215.808 46.884 216 ;
    END
  END g_front_0_u_front__q_data_in[241]
  PIN g_front_0_u_front__q_data_in[242]
    DIRECTION INPUT ;
    USE SIGNAL ;
    PORT
      LAYER M5 ;
        RECT  47.052 215.808 47.076 216 ;
    END
  END g_front_0_u_front__q_data_in[242]
  PIN g_front_0_u_front__q_data_in[243]
    DIRECTION INPUT ;
    USE SIGNAL ;
    PORT
      LAYER M5 ;
        RECT  47.196 215.808 47.22 216 ;
    END
  END g_front_0_u_front__q_data_in[243]
  PIN g_front_0_u_front__q_data_in[244]
    DIRECTION INPUT ;
    USE SIGNAL ;
    PORT
      LAYER M5 ;
        RECT  47.34 215.808 47.364 216 ;
    END
  END g_front_0_u_front__q_data_in[244]
  PIN g_front_0_u_front__q_data_in[245]
    DIRECTION INPUT ;
    USE SIGNAL ;
    PORT
      LAYER M5 ;
        RECT  47.532 215.808 47.556 216 ;
    END
  END g_front_0_u_front__q_data_in[245]
  PIN g_front_0_u_front__q_data_in[246]
    DIRECTION INPUT ;
    USE SIGNAL ;
    PORT
      LAYER M5 ;
        RECT  47.676 215.808 47.7 216 ;
    END
  END g_front_0_u_front__q_data_in[246]
  PIN g_front_0_u_front__q_data_in[247]
    DIRECTION INPUT ;
    USE SIGNAL ;
    PORT
      LAYER M5 ;
        RECT  47.82 215.808 47.844 216 ;
    END
  END g_front_0_u_front__q_data_in[247]
  PIN g_front_0_u_front__q_data_in[248]
    DIRECTION INPUT ;
    USE SIGNAL ;
    PORT
      LAYER M5 ;
        RECT  48.012 215.808 48.036 216 ;
    END
  END g_front_0_u_front__q_data_in[248]
  PIN g_front_0_u_front__q_data_in[249]
    DIRECTION INPUT ;
    USE SIGNAL ;
    PORT
      LAYER M5 ;
        RECT  48.156 215.808 48.18 216 ;
    END
  END g_front_0_u_front__q_data_in[249]
  PIN g_front_0_u_front__q_data_in[24]
    DIRECTION INPUT ;
    USE SIGNAL ;
    PORT
      LAYER M5 ;
        RECT  12.396 215.808 12.42 216 ;
    END
  END g_front_0_u_front__q_data_in[24]
  PIN g_front_0_u_front__q_data_in[250]
    DIRECTION INPUT ;
    USE SIGNAL ;
    PORT
      LAYER M5 ;
        RECT  48.3 215.808 48.324 216 ;
    END
  END g_front_0_u_front__q_data_in[250]
  PIN g_front_0_u_front__q_data_in[251]
    DIRECTION INPUT ;
    USE SIGNAL ;
    PORT
      LAYER M5 ;
        RECT  48.492 215.808 48.516 216 ;
    END
  END g_front_0_u_front__q_data_in[251]
  PIN g_front_0_u_front__q_data_in[252]
    DIRECTION INPUT ;
    USE SIGNAL ;
    PORT
      LAYER M5 ;
        RECT  48.636 215.808 48.66 216 ;
    END
  END g_front_0_u_front__q_data_in[252]
  PIN g_front_0_u_front__q_data_in[253]
    DIRECTION INPUT ;
    USE SIGNAL ;
    PORT
      LAYER M5 ;
        RECT  48.78 215.808 48.804 216 ;
    END
  END g_front_0_u_front__q_data_in[253]
  PIN g_front_0_u_front__q_data_in[254]
    DIRECTION INPUT ;
    USE SIGNAL ;
    PORT
      LAYER M5 ;
        RECT  48.972 215.808 48.996 216 ;
    END
  END g_front_0_u_front__q_data_in[254]
  PIN g_front_0_u_front__q_data_in[255]
    DIRECTION INPUT ;
    USE SIGNAL ;
    PORT
      LAYER M5 ;
        RECT  49.116 215.808 49.14 216 ;
    END
  END g_front_0_u_front__q_data_in[255]
  PIN g_front_0_u_front__q_data_in[256]
    DIRECTION INPUT ;
    USE SIGNAL ;
    PORT
      LAYER M5 ;
        RECT  49.26 215.808 49.284 216 ;
    END
  END g_front_0_u_front__q_data_in[256]
  PIN g_front_0_u_front__q_data_in[257]
    DIRECTION INPUT ;
    USE SIGNAL ;
    PORT
      LAYER M5 ;
        RECT  49.404 215.808 49.428 216 ;
    END
  END g_front_0_u_front__q_data_in[257]
  PIN g_front_0_u_front__q_data_in[258]
    DIRECTION INPUT ;
    USE SIGNAL ;
    PORT
      LAYER M5 ;
        RECT  49.596 215.808 49.62 216 ;
    END
  END g_front_0_u_front__q_data_in[258]
  PIN g_front_0_u_front__q_data_in[259]
    DIRECTION INPUT ;
    USE SIGNAL ;
    PORT
      LAYER M5 ;
        RECT  49.74 215.808 49.764 216 ;
    END
  END g_front_0_u_front__q_data_in[259]
  PIN g_front_0_u_front__q_data_in[25]
    DIRECTION INPUT ;
    USE SIGNAL ;
    PORT
      LAYER M5 ;
        RECT  12.54 215.808 12.564 216 ;
    END
  END g_front_0_u_front__q_data_in[25]
  PIN g_front_0_u_front__q_data_in[260]
    DIRECTION INPUT ;
    USE SIGNAL ;
    PORT
      LAYER M5 ;
        RECT  49.884 215.808 49.908 216 ;
    END
  END g_front_0_u_front__q_data_in[260]
  PIN g_front_0_u_front__q_data_in[261]
    DIRECTION INPUT ;
    USE SIGNAL ;
    PORT
      LAYER M5 ;
        RECT  50.076 215.808 50.1 216 ;
    END
  END g_front_0_u_front__q_data_in[261]
  PIN g_front_0_u_front__q_data_in[262]
    DIRECTION INPUT ;
    USE SIGNAL ;
    PORT
      LAYER M5 ;
        RECT  50.22 215.808 50.244 216 ;
    END
  END g_front_0_u_front__q_data_in[262]
  PIN g_front_0_u_front__q_data_in[263]
    DIRECTION INPUT ;
    USE SIGNAL ;
    PORT
      LAYER M5 ;
        RECT  50.364 215.808 50.388 216 ;
    END
  END g_front_0_u_front__q_data_in[263]
  PIN g_front_0_u_front__q_data_in[264]
    DIRECTION INPUT ;
    USE SIGNAL ;
    PORT
      LAYER M5 ;
        RECT  50.556 215.808 50.58 216 ;
    END
  END g_front_0_u_front__q_data_in[264]
  PIN g_front_0_u_front__q_data_in[265]
    DIRECTION INPUT ;
    USE SIGNAL ;
    PORT
      LAYER M5 ;
        RECT  50.7 215.808 50.724 216 ;
    END
  END g_front_0_u_front__q_data_in[265]
  PIN g_front_0_u_front__q_data_in[266]
    DIRECTION INPUT ;
    USE SIGNAL ;
    PORT
      LAYER M5 ;
        RECT  50.844 215.808 50.868 216 ;
    END
  END g_front_0_u_front__q_data_in[266]
  PIN g_front_0_u_front__q_data_in[267]
    DIRECTION INPUT ;
    USE SIGNAL ;
    PORT
      LAYER M5 ;
        RECT  51.036 215.808 51.06 216 ;
    END
  END g_front_0_u_front__q_data_in[267]
  PIN g_front_0_u_front__q_data_in[268]
    DIRECTION INPUT ;
    USE SIGNAL ;
    PORT
      LAYER M5 ;
        RECT  51.18 215.808 51.204 216 ;
    END
  END g_front_0_u_front__q_data_in[268]
  PIN g_front_0_u_front__q_data_in[269]
    DIRECTION INPUT ;
    USE SIGNAL ;
    PORT
      LAYER M5 ;
        RECT  51.324 215.808 51.348 216 ;
    END
  END g_front_0_u_front__q_data_in[269]
  PIN g_front_0_u_front__q_data_in[26]
    DIRECTION INPUT ;
    USE SIGNAL ;
    PORT
      LAYER M5 ;
        RECT  12.732 215.808 12.756 216 ;
    END
  END g_front_0_u_front__q_data_in[26]
  PIN g_front_0_u_front__q_data_in[270]
    DIRECTION INPUT ;
    USE SIGNAL ;
    PORT
      LAYER M5 ;
        RECT  51.516 215.808 51.54 216 ;
    END
  END g_front_0_u_front__q_data_in[270]
  PIN g_front_0_u_front__q_data_in[271]
    DIRECTION INPUT ;
    USE SIGNAL ;
    PORT
      LAYER M5 ;
        RECT  51.66 215.808 51.684 216 ;
    END
  END g_front_0_u_front__q_data_in[271]
  PIN g_front_0_u_front__q_data_in[272]
    DIRECTION INPUT ;
    USE SIGNAL ;
    PORT
      LAYER M5 ;
        RECT  51.804 215.808 51.828 216 ;
    END
  END g_front_0_u_front__q_data_in[272]
  PIN g_front_0_u_front__q_data_in[273]
    DIRECTION INPUT ;
    USE SIGNAL ;
    PORT
      LAYER M5 ;
        RECT  51.948 215.808 51.972 216 ;
    END
  END g_front_0_u_front__q_data_in[273]
  PIN g_front_0_u_front__q_data_in[274]
    DIRECTION INPUT ;
    USE SIGNAL ;
    PORT
      LAYER M5 ;
        RECT  52.14 215.808 52.164 216 ;
    END
  END g_front_0_u_front__q_data_in[274]
  PIN g_front_0_u_front__q_data_in[275]
    DIRECTION INPUT ;
    USE SIGNAL ;
    PORT
      LAYER M5 ;
        RECT  52.284 215.808 52.308 216 ;
    END
  END g_front_0_u_front__q_data_in[275]
  PIN g_front_0_u_front__q_data_in[276]
    DIRECTION INPUT ;
    USE SIGNAL ;
    PORT
      LAYER M5 ;
        RECT  52.428 215.808 52.452 216 ;
    END
  END g_front_0_u_front__q_data_in[276]
  PIN g_front_0_u_front__q_data_in[277]
    DIRECTION INPUT ;
    USE SIGNAL ;
    PORT
      LAYER M5 ;
        RECT  52.62 215.808 52.644 216 ;
    END
  END g_front_0_u_front__q_data_in[277]
  PIN g_front_0_u_front__q_data_in[278]
    DIRECTION INPUT ;
    USE SIGNAL ;
    PORT
      LAYER M5 ;
        RECT  52.764 215.808 52.788 216 ;
    END
  END g_front_0_u_front__q_data_in[278]
  PIN g_front_0_u_front__q_data_in[279]
    DIRECTION INPUT ;
    USE SIGNAL ;
    PORT
      LAYER M5 ;
        RECT  52.908 215.808 52.932 216 ;
    END
  END g_front_0_u_front__q_data_in[279]
  PIN g_front_0_u_front__q_data_in[27]
    DIRECTION INPUT ;
    USE SIGNAL ;
    PORT
      LAYER M5 ;
        RECT  12.876 215.808 12.9 216 ;
    END
  END g_front_0_u_front__q_data_in[27]
  PIN g_front_0_u_front__q_data_in[280]
    DIRECTION INPUT ;
    USE SIGNAL ;
    PORT
      LAYER M5 ;
        RECT  53.1 215.808 53.124 216 ;
    END
  END g_front_0_u_front__q_data_in[280]
  PIN g_front_0_u_front__q_data_in[281]
    DIRECTION INPUT ;
    USE SIGNAL ;
    PORT
      LAYER M5 ;
        RECT  53.244 215.808 53.268 216 ;
    END
  END g_front_0_u_front__q_data_in[281]
  PIN g_front_0_u_front__q_data_in[282]
    DIRECTION INPUT ;
    USE SIGNAL ;
    PORT
      LAYER M5 ;
        RECT  53.388 215.808 53.412 216 ;
    END
  END g_front_0_u_front__q_data_in[282]
  PIN g_front_0_u_front__q_data_in[283]
    DIRECTION INPUT ;
    USE SIGNAL ;
    PORT
      LAYER M5 ;
        RECT  53.58 215.808 53.604 216 ;
    END
  END g_front_0_u_front__q_data_in[283]
  PIN g_front_0_u_front__q_data_in[284]
    DIRECTION INPUT ;
    USE SIGNAL ;
    PORT
      LAYER M5 ;
        RECT  53.724 215.808 53.748 216 ;
    END
  END g_front_0_u_front__q_data_in[284]
  PIN g_front_0_u_front__q_data_in[285]
    DIRECTION INPUT ;
    USE SIGNAL ;
    PORT
      LAYER M5 ;
        RECT  53.868 215.808 53.892 216 ;
    END
  END g_front_0_u_front__q_data_in[285]
  PIN g_front_0_u_front__q_data_in[286]
    DIRECTION INPUT ;
    USE SIGNAL ;
    PORT
      LAYER M5 ;
        RECT  54.012 215.808 54.036 216 ;
    END
  END g_front_0_u_front__q_data_in[286]
  PIN g_front_0_u_front__q_data_in[287]
    DIRECTION INPUT ;
    USE SIGNAL ;
    PORT
      LAYER M5 ;
        RECT  54.204 215.808 54.228 216 ;
    END
  END g_front_0_u_front__q_data_in[287]
  PIN g_front_0_u_front__q_data_in[288]
    DIRECTION INPUT ;
    USE SIGNAL ;
    PORT
      LAYER M5 ;
        RECT  54.348 215.808 54.372 216 ;
    END
  END g_front_0_u_front__q_data_in[288]
  PIN g_front_0_u_front__q_data_in[289]
    DIRECTION INPUT ;
    USE SIGNAL ;
    PORT
      LAYER M5 ;
        RECT  54.492 215.808 54.516 216 ;
    END
  END g_front_0_u_front__q_data_in[289]
  PIN g_front_0_u_front__q_data_in[28]
    DIRECTION INPUT ;
    USE SIGNAL ;
    PORT
      LAYER M5 ;
        RECT  13.02 215.808 13.044 216 ;
    END
  END g_front_0_u_front__q_data_in[28]
  PIN g_front_0_u_front__q_data_in[290]
    DIRECTION INPUT ;
    USE SIGNAL ;
    PORT
      LAYER M5 ;
        RECT  54.684 215.808 54.708 216 ;
    END
  END g_front_0_u_front__q_data_in[290]
  PIN g_front_0_u_front__q_data_in[291]
    DIRECTION INPUT ;
    USE SIGNAL ;
    PORT
      LAYER M5 ;
        RECT  54.828 215.808 54.852 216 ;
    END
  END g_front_0_u_front__q_data_in[291]
  PIN g_front_0_u_front__q_data_in[292]
    DIRECTION INPUT ;
    USE SIGNAL ;
    PORT
      LAYER M5 ;
        RECT  54.972 215.808 54.996 216 ;
    END
  END g_front_0_u_front__q_data_in[292]
  PIN g_front_0_u_front__q_data_in[293]
    DIRECTION INPUT ;
    USE SIGNAL ;
    PORT
      LAYER M5 ;
        RECT  55.164 215.808 55.188 216 ;
    END
  END g_front_0_u_front__q_data_in[293]
  PIN g_front_0_u_front__q_data_in[294]
    DIRECTION INPUT ;
    USE SIGNAL ;
    PORT
      LAYER M5 ;
        RECT  55.308 215.808 55.332 216 ;
    END
  END g_front_0_u_front__q_data_in[294]
  PIN g_front_0_u_front__q_data_in[295]
    DIRECTION INPUT ;
    USE SIGNAL ;
    PORT
      LAYER M5 ;
        RECT  55.452 215.808 55.476 216 ;
    END
  END g_front_0_u_front__q_data_in[295]
  PIN g_front_0_u_front__q_data_in[296]
    DIRECTION INPUT ;
    USE SIGNAL ;
    PORT
      LAYER M5 ;
        RECT  55.644 215.808 55.668 216 ;
    END
  END g_front_0_u_front__q_data_in[296]
  PIN g_front_0_u_front__q_data_in[297]
    DIRECTION INPUT ;
    USE SIGNAL ;
    PORT
      LAYER M5 ;
        RECT  55.788 215.808 55.812 216 ;
    END
  END g_front_0_u_front__q_data_in[297]
  PIN g_front_0_u_front__q_data_in[298]
    DIRECTION INPUT ;
    USE SIGNAL ;
    PORT
      LAYER M5 ;
        RECT  55.932 215.808 55.956 216 ;
    END
  END g_front_0_u_front__q_data_in[298]
  PIN g_front_0_u_front__q_data_in[299]
    DIRECTION INPUT ;
    USE SIGNAL ;
    PORT
      LAYER M5 ;
        RECT  56.124 215.808 56.148 216 ;
    END
  END g_front_0_u_front__q_data_in[299]
  PIN g_front_0_u_front__q_data_in[29]
    DIRECTION INPUT ;
    USE SIGNAL ;
    PORT
      LAYER M5 ;
        RECT  13.212 215.808 13.236 216 ;
    END
  END g_front_0_u_front__q_data_in[29]
  PIN g_front_0_u_front__q_data_in[2]
    DIRECTION INPUT ;
    USE SIGNAL ;
    PORT
      LAYER M5 ;
        RECT  8.892 215.808 8.916 216 ;
    END
  END g_front_0_u_front__q_data_in[2]
  PIN g_front_0_u_front__q_data_in[300]
    DIRECTION INPUT ;
    USE SIGNAL ;
    PORT
      LAYER M5 ;
        RECT  56.268 215.808 56.292 216 ;
    END
  END g_front_0_u_front__q_data_in[300]
  PIN g_front_0_u_front__q_data_in[301]
    DIRECTION INPUT ;
    USE SIGNAL ;
    PORT
      LAYER M5 ;
        RECT  56.412 215.808 56.436 216 ;
    END
  END g_front_0_u_front__q_data_in[301]
  PIN g_front_0_u_front__q_data_in[302]
    DIRECTION INPUT ;
    USE SIGNAL ;
    PORT
      LAYER M5 ;
        RECT  56.556 215.808 56.58 216 ;
    END
  END g_front_0_u_front__q_data_in[302]
  PIN g_front_0_u_front__q_data_in[303]
    DIRECTION INPUT ;
    USE SIGNAL ;
    PORT
      LAYER M5 ;
        RECT  56.748 215.808 56.772 216 ;
    END
  END g_front_0_u_front__q_data_in[303]
  PIN g_front_0_u_front__q_data_in[304]
    DIRECTION INPUT ;
    USE SIGNAL ;
    PORT
      LAYER M5 ;
        RECT  56.892 215.808 56.916 216 ;
    END
  END g_front_0_u_front__q_data_in[304]
  PIN g_front_0_u_front__q_data_in[305]
    DIRECTION INPUT ;
    USE SIGNAL ;
    PORT
      LAYER M5 ;
        RECT  57.036 215.808 57.06 216 ;
    END
  END g_front_0_u_front__q_data_in[305]
  PIN g_front_0_u_front__q_data_in[306]
    DIRECTION INPUT ;
    USE SIGNAL ;
    PORT
      LAYER M5 ;
        RECT  57.228 215.808 57.252 216 ;
    END
  END g_front_0_u_front__q_data_in[306]
  PIN g_front_0_u_front__q_data_in[307]
    DIRECTION INPUT ;
    USE SIGNAL ;
    PORT
      LAYER M5 ;
        RECT  57.372 215.808 57.396 216 ;
    END
  END g_front_0_u_front__q_data_in[307]
  PIN g_front_0_u_front__q_data_in[308]
    DIRECTION INPUT ;
    USE SIGNAL ;
    PORT
      LAYER M5 ;
        RECT  57.516 215.808 57.54 216 ;
    END
  END g_front_0_u_front__q_data_in[308]
  PIN g_front_0_u_front__q_data_in[309]
    DIRECTION INPUT ;
    USE SIGNAL ;
    PORT
      LAYER M5 ;
        RECT  57.708 215.808 57.732 216 ;
    END
  END g_front_0_u_front__q_data_in[309]
  PIN g_front_0_u_front__q_data_in[30]
    DIRECTION INPUT ;
    USE SIGNAL ;
    PORT
      LAYER M5 ;
        RECT  13.356 215.808 13.38 216 ;
    END
  END g_front_0_u_front__q_data_in[30]
  PIN g_front_0_u_front__q_data_in[310]
    DIRECTION INPUT ;
    USE SIGNAL ;
    PORT
      LAYER M5 ;
        RECT  57.852 215.808 57.876 216 ;
    END
  END g_front_0_u_front__q_data_in[310]
  PIN g_front_0_u_front__q_data_in[311]
    DIRECTION INPUT ;
    USE SIGNAL ;
    PORT
      LAYER M5 ;
        RECT  57.996 215.808 58.02 216 ;
    END
  END g_front_0_u_front__q_data_in[311]
  PIN g_front_0_u_front__q_data_in[312]
    DIRECTION INPUT ;
    USE SIGNAL ;
    PORT
      LAYER M5 ;
        RECT  58.188 215.808 58.212 216 ;
    END
  END g_front_0_u_front__q_data_in[312]
  PIN g_front_0_u_front__q_data_in[313]
    DIRECTION INPUT ;
    USE SIGNAL ;
    PORT
      LAYER M5 ;
        RECT  58.332 215.808 58.356 216 ;
    END
  END g_front_0_u_front__q_data_in[313]
  PIN g_front_0_u_front__q_data_in[314]
    DIRECTION INPUT ;
    USE SIGNAL ;
    PORT
      LAYER M5 ;
        RECT  58.476 215.808 58.5 216 ;
    END
  END g_front_0_u_front__q_data_in[314]
  PIN g_front_0_u_front__q_data_in[315]
    DIRECTION INPUT ;
    USE SIGNAL ;
    PORT
      LAYER M5 ;
        RECT  58.62 215.808 58.644 216 ;
    END
  END g_front_0_u_front__q_data_in[315]
  PIN g_front_0_u_front__q_data_in[316]
    DIRECTION INPUT ;
    USE SIGNAL ;
    PORT
      LAYER M5 ;
        RECT  58.812 215.808 58.836 216 ;
    END
  END g_front_0_u_front__q_data_in[316]
  PIN g_front_0_u_front__q_data_in[317]
    DIRECTION INPUT ;
    USE SIGNAL ;
    PORT
      LAYER M5 ;
        RECT  58.956 215.808 58.98 216 ;
    END
  END g_front_0_u_front__q_data_in[317]
  PIN g_front_0_u_front__q_data_in[318]
    DIRECTION INPUT ;
    USE SIGNAL ;
    PORT
      LAYER M5 ;
        RECT  59.1 215.808 59.124 216 ;
    END
  END g_front_0_u_front__q_data_in[318]
  PIN g_front_0_u_front__q_data_in[319]
    DIRECTION INPUT ;
    USE SIGNAL ;
    PORT
      LAYER M5 ;
        RECT  59.292 215.808 59.316 216 ;
    END
  END g_front_0_u_front__q_data_in[319]
  PIN g_front_0_u_front__q_data_in[31]
    DIRECTION INPUT ;
    USE SIGNAL ;
    PORT
      LAYER M5 ;
        RECT  13.5 215.808 13.524 216 ;
    END
  END g_front_0_u_front__q_data_in[31]
  PIN g_front_0_u_front__q_data_in[320]
    DIRECTION INPUT ;
    USE SIGNAL ;
    PORT
      LAYER M5 ;
        RECT  59.436 215.808 59.46 216 ;
    END
  END g_front_0_u_front__q_data_in[320]
  PIN g_front_0_u_front__q_data_in[321]
    DIRECTION INPUT ;
    USE SIGNAL ;
    PORT
      LAYER M5 ;
        RECT  59.58 215.808 59.604 216 ;
    END
  END g_front_0_u_front__q_data_in[321]
  PIN g_front_0_u_front__q_data_in[322]
    DIRECTION INPUT ;
    USE SIGNAL ;
    PORT
      LAYER M5 ;
        RECT  59.772 215.808 59.796 216 ;
    END
  END g_front_0_u_front__q_data_in[322]
  PIN g_front_0_u_front__q_data_in[323]
    DIRECTION INPUT ;
    USE SIGNAL ;
    PORT
      LAYER M5 ;
        RECT  59.916 215.808 59.94 216 ;
    END
  END g_front_0_u_front__q_data_in[323]
  PIN g_front_0_u_front__q_data_in[324]
    DIRECTION INPUT ;
    USE SIGNAL ;
    PORT
      LAYER M5 ;
        RECT  60.06 215.808 60.084 216 ;
    END
  END g_front_0_u_front__q_data_in[324]
  PIN g_front_0_u_front__q_data_in[325]
    DIRECTION INPUT ;
    USE SIGNAL ;
    PORT
      LAYER M5 ;
        RECT  60.252 215.808 60.276 216 ;
    END
  END g_front_0_u_front__q_data_in[325]
  PIN g_front_0_u_front__q_data_in[326]
    DIRECTION INPUT ;
    USE SIGNAL ;
    PORT
      LAYER M5 ;
        RECT  60.396 215.808 60.42 216 ;
    END
  END g_front_0_u_front__q_data_in[326]
  PIN g_front_0_u_front__q_data_in[327]
    DIRECTION INPUT ;
    USE SIGNAL ;
    PORT
      LAYER M5 ;
        RECT  60.54 215.808 60.564 216 ;
    END
  END g_front_0_u_front__q_data_in[327]
  PIN g_front_0_u_front__q_data_in[328]
    DIRECTION INPUT ;
    USE SIGNAL ;
    PORT
      LAYER M5 ;
        RECT  60.732 215.808 60.756 216 ;
    END
  END g_front_0_u_front__q_data_in[328]
  PIN g_front_0_u_front__q_data_in[329]
    DIRECTION INPUT ;
    USE SIGNAL ;
    PORT
      LAYER M5 ;
        RECT  60.876 215.808 60.9 216 ;
    END
  END g_front_0_u_front__q_data_in[329]
  PIN g_front_0_u_front__q_data_in[32]
    DIRECTION INPUT ;
    USE SIGNAL ;
    PORT
      LAYER M5 ;
        RECT  13.692 215.808 13.716 216 ;
    END
  END g_front_0_u_front__q_data_in[32]
  PIN g_front_0_u_front__q_data_in[330]
    DIRECTION INPUT ;
    USE SIGNAL ;
    PORT
      LAYER M5 ;
        RECT  61.02 215.808 61.044 216 ;
    END
  END g_front_0_u_front__q_data_in[330]
  PIN g_front_0_u_front__q_data_in[331]
    DIRECTION INPUT ;
    USE SIGNAL ;
    PORT
      LAYER M5 ;
        RECT  61.164 215.808 61.188 216 ;
    END
  END g_front_0_u_front__q_data_in[331]
  PIN g_front_0_u_front__q_data_in[332]
    DIRECTION INPUT ;
    USE SIGNAL ;
    PORT
      LAYER M5 ;
        RECT  61.356 215.808 61.38 216 ;
    END
  END g_front_0_u_front__q_data_in[332]
  PIN g_front_0_u_front__q_data_in[333]
    DIRECTION INPUT ;
    USE SIGNAL ;
    PORT
      LAYER M5 ;
        RECT  61.5 215.808 61.524 216 ;
    END
  END g_front_0_u_front__q_data_in[333]
  PIN g_front_0_u_front__q_data_in[334]
    DIRECTION INPUT ;
    USE SIGNAL ;
    PORT
      LAYER M5 ;
        RECT  61.644 215.808 61.668 216 ;
    END
  END g_front_0_u_front__q_data_in[334]
  PIN g_front_0_u_front__q_data_in[335]
    DIRECTION INPUT ;
    USE SIGNAL ;
    PORT
      LAYER M5 ;
        RECT  61.836 215.808 61.86 216 ;
    END
  END g_front_0_u_front__q_data_in[335]
  PIN g_front_0_u_front__q_data_in[336]
    DIRECTION INPUT ;
    USE SIGNAL ;
    PORT
      LAYER M5 ;
        RECT  61.98 215.808 62.004 216 ;
    END
  END g_front_0_u_front__q_data_in[336]
  PIN g_front_0_u_front__q_data_in[337]
    DIRECTION INPUT ;
    USE SIGNAL ;
    PORT
      LAYER M5 ;
        RECT  62.124 215.808 62.148 216 ;
    END
  END g_front_0_u_front__q_data_in[337]
  PIN g_front_0_u_front__q_data_in[338]
    DIRECTION INPUT ;
    USE SIGNAL ;
    PORT
      LAYER M5 ;
        RECT  62.316 215.808 62.34 216 ;
    END
  END g_front_0_u_front__q_data_in[338]
  PIN g_front_0_u_front__q_data_in[339]
    DIRECTION INPUT ;
    USE SIGNAL ;
    PORT
      LAYER M5 ;
        RECT  62.46 215.808 62.484 216 ;
    END
  END g_front_0_u_front__q_data_in[339]
  PIN g_front_0_u_front__q_data_in[33]
    DIRECTION INPUT ;
    USE SIGNAL ;
    PORT
      LAYER M5 ;
        RECT  13.836 215.808 13.86 216 ;
    END
  END g_front_0_u_front__q_data_in[33]
  PIN g_front_0_u_front__q_data_in[340]
    DIRECTION INPUT ;
    USE SIGNAL ;
    PORT
      LAYER M5 ;
        RECT  62.604 215.808 62.628 216 ;
    END
  END g_front_0_u_front__q_data_in[340]
  PIN g_front_0_u_front__q_data_in[341]
    DIRECTION INPUT ;
    USE SIGNAL ;
    PORT
      LAYER M5 ;
        RECT  62.796 215.808 62.82 216 ;
    END
  END g_front_0_u_front__q_data_in[341]
  PIN g_front_0_u_front__q_data_in[342]
    DIRECTION INPUT ;
    USE SIGNAL ;
    PORT
      LAYER M5 ;
        RECT  62.94 215.808 62.964 216 ;
    END
  END g_front_0_u_front__q_data_in[342]
  PIN g_front_0_u_front__q_data_in[343]
    DIRECTION INPUT ;
    USE SIGNAL ;
    PORT
      LAYER M5 ;
        RECT  63.084 215.808 63.108 216 ;
    END
  END g_front_0_u_front__q_data_in[343]
  PIN g_front_0_u_front__q_data_in[344]
    DIRECTION INPUT ;
    USE SIGNAL ;
    PORT
      LAYER M5 ;
        RECT  63.276 215.808 63.3 216 ;
    END
  END g_front_0_u_front__q_data_in[344]
  PIN g_front_0_u_front__q_data_in[345]
    DIRECTION INPUT ;
    USE SIGNAL ;
    PORT
      LAYER M5 ;
        RECT  63.42 215.808 63.444 216 ;
    END
  END g_front_0_u_front__q_data_in[345]
  PIN g_front_0_u_front__q_data_in[346]
    DIRECTION INPUT ;
    USE SIGNAL ;
    PORT
      LAYER M5 ;
        RECT  63.564 215.808 63.588 216 ;
    END
  END g_front_0_u_front__q_data_in[346]
  PIN g_front_0_u_front__q_data_in[347]
    DIRECTION INPUT ;
    USE SIGNAL ;
    PORT
      LAYER M5 ;
        RECT  63.708 215.808 63.732 216 ;
    END
  END g_front_0_u_front__q_data_in[347]
  PIN g_front_0_u_front__q_data_in[348]
    DIRECTION INPUT ;
    USE SIGNAL ;
    PORT
      LAYER M5 ;
        RECT  63.9 215.808 63.924 216 ;
    END
  END g_front_0_u_front__q_data_in[348]
  PIN g_front_0_u_front__q_data_in[349]
    DIRECTION INPUT ;
    USE SIGNAL ;
    PORT
      LAYER M5 ;
        RECT  64.044 215.808 64.068 216 ;
    END
  END g_front_0_u_front__q_data_in[349]
  PIN g_front_0_u_front__q_data_in[34]
    DIRECTION INPUT ;
    USE SIGNAL ;
    PORT
      LAYER M5 ;
        RECT  13.98 215.808 14.004 216 ;
    END
  END g_front_0_u_front__q_data_in[34]
  PIN g_front_0_u_front__q_data_in[350]
    DIRECTION INPUT ;
    USE SIGNAL ;
    PORT
      LAYER M5 ;
        RECT  64.188 215.808 64.212 216 ;
    END
  END g_front_0_u_front__q_data_in[350]
  PIN g_front_0_u_front__q_data_in[351]
    DIRECTION INPUT ;
    USE SIGNAL ;
    PORT
      LAYER M5 ;
        RECT  64.38 215.808 64.404 216 ;
    END
  END g_front_0_u_front__q_data_in[351]
  PIN g_front_0_u_front__q_data_in[352]
    DIRECTION INPUT ;
    USE SIGNAL ;
    PORT
      LAYER M5 ;
        RECT  64.524 215.808 64.548 216 ;
    END
  END g_front_0_u_front__q_data_in[352]
  PIN g_front_0_u_front__q_data_in[353]
    DIRECTION INPUT ;
    USE SIGNAL ;
    PORT
      LAYER M5 ;
        RECT  64.668 215.808 64.692 216 ;
    END
  END g_front_0_u_front__q_data_in[353]
  PIN g_front_0_u_front__q_data_in[354]
    DIRECTION INPUT ;
    USE SIGNAL ;
    PORT
      LAYER M5 ;
        RECT  64.86 215.808 64.884 216 ;
    END
  END g_front_0_u_front__q_data_in[354]
  PIN g_front_0_u_front__q_data_in[355]
    DIRECTION INPUT ;
    USE SIGNAL ;
    PORT
      LAYER M5 ;
        RECT  65.004 215.808 65.028 216 ;
    END
  END g_front_0_u_front__q_data_in[355]
  PIN g_front_0_u_front__q_data_in[356]
    DIRECTION INPUT ;
    USE SIGNAL ;
    PORT
      LAYER M5 ;
        RECT  65.148 215.808 65.172 216 ;
    END
  END g_front_0_u_front__q_data_in[356]
  PIN g_front_0_u_front__q_data_in[357]
    DIRECTION INPUT ;
    USE SIGNAL ;
    PORT
      LAYER M5 ;
        RECT  65.34 215.808 65.364 216 ;
    END
  END g_front_0_u_front__q_data_in[357]
  PIN g_front_0_u_front__q_data_in[358]
    DIRECTION INPUT ;
    USE SIGNAL ;
    PORT
      LAYER M5 ;
        RECT  65.484 215.808 65.508 216 ;
    END
  END g_front_0_u_front__q_data_in[358]
  PIN g_front_0_u_front__q_data_in[359]
    DIRECTION INPUT ;
    USE SIGNAL ;
    PORT
      LAYER M5 ;
        RECT  65.628 215.808 65.652 216 ;
    END
  END g_front_0_u_front__q_data_in[359]
  PIN g_front_0_u_front__q_data_in[35]
    DIRECTION INPUT ;
    USE SIGNAL ;
    PORT
      LAYER M5 ;
        RECT  14.124 215.808 14.148 216 ;
    END
  END g_front_0_u_front__q_data_in[35]
  PIN g_front_0_u_front__q_data_in[360]
    DIRECTION INPUT ;
    USE SIGNAL ;
    PORT
      LAYER M5 ;
        RECT  65.772 215.808 65.796 216 ;
    END
  END g_front_0_u_front__q_data_in[360]
  PIN g_front_0_u_front__q_data_in[361]
    DIRECTION INPUT ;
    USE SIGNAL ;
    PORT
      LAYER M5 ;
        RECT  65.964 215.808 65.988 216 ;
    END
  END g_front_0_u_front__q_data_in[361]
  PIN g_front_0_u_front__q_data_in[362]
    DIRECTION INPUT ;
    USE SIGNAL ;
    PORT
      LAYER M5 ;
        RECT  66.108 215.808 66.132 216 ;
    END
  END g_front_0_u_front__q_data_in[362]
  PIN g_front_0_u_front__q_data_in[363]
    DIRECTION INPUT ;
    USE SIGNAL ;
    PORT
      LAYER M5 ;
        RECT  66.252 215.808 66.276 216 ;
    END
  END g_front_0_u_front__q_data_in[363]
  PIN g_front_0_u_front__q_data_in[364]
    DIRECTION INPUT ;
    USE SIGNAL ;
    PORT
      LAYER M5 ;
        RECT  66.444 215.808 66.468 216 ;
    END
  END g_front_0_u_front__q_data_in[364]
  PIN g_front_0_u_front__q_data_in[365]
    DIRECTION INPUT ;
    USE SIGNAL ;
    PORT
      LAYER M5 ;
        RECT  66.588 215.808 66.612 216 ;
    END
  END g_front_0_u_front__q_data_in[365]
  PIN g_front_0_u_front__q_data_in[366]
    DIRECTION INPUT ;
    USE SIGNAL ;
    PORT
      LAYER M5 ;
        RECT  66.732 215.808 66.756 216 ;
    END
  END g_front_0_u_front__q_data_in[366]
  PIN g_front_0_u_front__q_data_in[367]
    DIRECTION INPUT ;
    USE SIGNAL ;
    PORT
      LAYER M5 ;
        RECT  66.924 215.808 66.948 216 ;
    END
  END g_front_0_u_front__q_data_in[367]
  PIN g_front_0_u_front__q_data_in[368]
    DIRECTION INPUT ;
    USE SIGNAL ;
    PORT
      LAYER M5 ;
        RECT  67.068 215.808 67.092 216 ;
    END
  END g_front_0_u_front__q_data_in[368]
  PIN g_front_0_u_front__q_data_in[369]
    DIRECTION INPUT ;
    USE SIGNAL ;
    PORT
      LAYER M5 ;
        RECT  67.212 215.808 67.236 216 ;
    END
  END g_front_0_u_front__q_data_in[369]
  PIN g_front_0_u_front__q_data_in[36]
    DIRECTION INPUT ;
    USE SIGNAL ;
    PORT
      LAYER M5 ;
        RECT  14.316 215.808 14.34 216 ;
    END
  END g_front_0_u_front__q_data_in[36]
  PIN g_front_0_u_front__q_data_in[370]
    DIRECTION INPUT ;
    USE SIGNAL ;
    PORT
      LAYER M5 ;
        RECT  67.404 215.808 67.428 216 ;
    END
  END g_front_0_u_front__q_data_in[370]
  PIN g_front_0_u_front__q_data_in[371]
    DIRECTION INPUT ;
    USE SIGNAL ;
    PORT
      LAYER M5 ;
        RECT  67.548 215.808 67.572 216 ;
    END
  END g_front_0_u_front__q_data_in[371]
  PIN g_front_0_u_front__q_data_in[372]
    DIRECTION INPUT ;
    USE SIGNAL ;
    PORT
      LAYER M5 ;
        RECT  67.692 215.808 67.716 216 ;
    END
  END g_front_0_u_front__q_data_in[372]
  PIN g_front_0_u_front__q_data_in[373]
    DIRECTION INPUT ;
    USE SIGNAL ;
    PORT
      LAYER M5 ;
        RECT  67.884 215.808 67.908 216 ;
    END
  END g_front_0_u_front__q_data_in[373]
  PIN g_front_0_u_front__q_data_in[374]
    DIRECTION INPUT ;
    USE SIGNAL ;
    PORT
      LAYER M5 ;
        RECT  68.028 215.808 68.052 216 ;
    END
  END g_front_0_u_front__q_data_in[374]
  PIN g_front_0_u_front__q_data_in[375]
    DIRECTION INPUT ;
    USE SIGNAL ;
    PORT
      LAYER M5 ;
        RECT  68.172 215.808 68.196 216 ;
    END
  END g_front_0_u_front__q_data_in[375]
  PIN g_front_0_u_front__q_data_in[376]
    DIRECTION INPUT ;
    USE SIGNAL ;
    PORT
      LAYER M5 ;
        RECT  68.316 215.808 68.34 216 ;
    END
  END g_front_0_u_front__q_data_in[376]
  PIN g_front_0_u_front__q_data_in[377]
    DIRECTION INPUT ;
    USE SIGNAL ;
    PORT
      LAYER M5 ;
        RECT  68.508 215.808 68.532 216 ;
    END
  END g_front_0_u_front__q_data_in[377]
  PIN g_front_0_u_front__q_data_in[378]
    DIRECTION INPUT ;
    USE SIGNAL ;
    PORT
      LAYER M5 ;
        RECT  68.652 215.808 68.676 216 ;
    END
  END g_front_0_u_front__q_data_in[378]
  PIN g_front_0_u_front__q_data_in[379]
    DIRECTION INPUT ;
    USE SIGNAL ;
    PORT
      LAYER M5 ;
        RECT  68.796 215.808 68.82 216 ;
    END
  END g_front_0_u_front__q_data_in[379]
  PIN g_front_0_u_front__q_data_in[37]
    DIRECTION INPUT ;
    USE SIGNAL ;
    PORT
      LAYER M5 ;
        RECT  14.46 215.808 14.484 216 ;
    END
  END g_front_0_u_front__q_data_in[37]
  PIN g_front_0_u_front__q_data_in[380]
    DIRECTION INPUT ;
    USE SIGNAL ;
    PORT
      LAYER M5 ;
        RECT  68.988 215.808 69.012 216 ;
    END
  END g_front_0_u_front__q_data_in[380]
  PIN g_front_0_u_front__q_data_in[381]
    DIRECTION INPUT ;
    USE SIGNAL ;
    PORT
      LAYER M5 ;
        RECT  69.132 215.808 69.156 216 ;
    END
  END g_front_0_u_front__q_data_in[381]
  PIN g_front_0_u_front__q_data_in[382]
    DIRECTION INPUT ;
    USE SIGNAL ;
    PORT
      LAYER M5 ;
        RECT  69.276 215.808 69.3 216 ;
    END
  END g_front_0_u_front__q_data_in[382]
  PIN g_front_0_u_front__q_data_in[383]
    DIRECTION INPUT ;
    USE SIGNAL ;
    PORT
      LAYER M5 ;
        RECT  69.468 215.808 69.492 216 ;
    END
  END g_front_0_u_front__q_data_in[383]
  PIN g_front_0_u_front__q_data_in[384]
    DIRECTION INPUT ;
    USE SIGNAL ;
    PORT
      LAYER M5 ;
        RECT  69.612 215.808 69.636 216 ;
    END
  END g_front_0_u_front__q_data_in[384]
  PIN g_front_0_u_front__q_data_in[385]
    DIRECTION INPUT ;
    USE SIGNAL ;
    PORT
      LAYER M5 ;
        RECT  69.756 215.808 69.78 216 ;
    END
  END g_front_0_u_front__q_data_in[385]
  PIN g_front_0_u_front__q_data_in[386]
    DIRECTION INPUT ;
    USE SIGNAL ;
    PORT
      LAYER M5 ;
        RECT  69.948 215.808 69.972 216 ;
    END
  END g_front_0_u_front__q_data_in[386]
  PIN g_front_0_u_front__q_data_in[387]
    DIRECTION INPUT ;
    USE SIGNAL ;
    PORT
      LAYER M5 ;
        RECT  70.092 215.808 70.116 216 ;
    END
  END g_front_0_u_front__q_data_in[387]
  PIN g_front_0_u_front__q_data_in[388]
    DIRECTION INPUT ;
    USE SIGNAL ;
    PORT
      LAYER M5 ;
        RECT  70.236 215.808 70.26 216 ;
    END
  END g_front_0_u_front__q_data_in[388]
  PIN g_front_0_u_front__q_data_in[389]
    DIRECTION INPUT ;
    USE SIGNAL ;
    PORT
      LAYER M5 ;
        RECT  70.38 215.808 70.404 216 ;
    END
  END g_front_0_u_front__q_data_in[389]
  PIN g_front_0_u_front__q_data_in[38]
    DIRECTION INPUT ;
    USE SIGNAL ;
    PORT
      LAYER M5 ;
        RECT  14.604 215.808 14.628 216 ;
    END
  END g_front_0_u_front__q_data_in[38]
  PIN g_front_0_u_front__q_data_in[390]
    DIRECTION INPUT ;
    USE SIGNAL ;
    PORT
      LAYER M5 ;
        RECT  70.572 215.808 70.596 216 ;
    END
  END g_front_0_u_front__q_data_in[390]
  PIN g_front_0_u_front__q_data_in[391]
    DIRECTION INPUT ;
    USE SIGNAL ;
    PORT
      LAYER M5 ;
        RECT  70.716 215.808 70.74 216 ;
    END
  END g_front_0_u_front__q_data_in[391]
  PIN g_front_0_u_front__q_data_in[392]
    DIRECTION INPUT ;
    USE SIGNAL ;
    PORT
      LAYER M5 ;
        RECT  70.86 215.808 70.884 216 ;
    END
  END g_front_0_u_front__q_data_in[392]
  PIN g_front_0_u_front__q_data_in[393]
    DIRECTION INPUT ;
    USE SIGNAL ;
    PORT
      LAYER M5 ;
        RECT  71.052 215.808 71.076 216 ;
    END
  END g_front_0_u_front__q_data_in[393]
  PIN g_front_0_u_front__q_data_in[394]
    DIRECTION INPUT ;
    USE SIGNAL ;
    PORT
      LAYER M5 ;
        RECT  71.196 215.808 71.22 216 ;
    END
  END g_front_0_u_front__q_data_in[394]
  PIN g_front_0_u_front__q_data_in[395]
    DIRECTION INPUT ;
    USE SIGNAL ;
    PORT
      LAYER M5 ;
        RECT  71.34 215.808 71.364 216 ;
    END
  END g_front_0_u_front__q_data_in[395]
  PIN g_front_0_u_front__q_data_in[396]
    DIRECTION INPUT ;
    USE SIGNAL ;
    PORT
      LAYER M5 ;
        RECT  71.532 215.808 71.556 216 ;
    END
  END g_front_0_u_front__q_data_in[396]
  PIN g_front_0_u_front__q_data_in[397]
    DIRECTION INPUT ;
    USE SIGNAL ;
    PORT
      LAYER M5 ;
        RECT  71.676 215.808 71.7 216 ;
    END
  END g_front_0_u_front__q_data_in[397]
  PIN g_front_0_u_front__q_data_in[398]
    DIRECTION INPUT ;
    USE SIGNAL ;
    PORT
      LAYER M5 ;
        RECT  71.82 215.808 71.844 216 ;
    END
  END g_front_0_u_front__q_data_in[398]
  PIN g_front_0_u_front__q_data_in[399]
    DIRECTION INPUT ;
    USE SIGNAL ;
    PORT
      LAYER M5 ;
        RECT  72.012 215.808 72.036 216 ;
    END
  END g_front_0_u_front__q_data_in[399]
  PIN g_front_0_u_front__q_data_in[39]
    DIRECTION INPUT ;
    USE SIGNAL ;
    PORT
      LAYER M5 ;
        RECT  14.796 215.808 14.82 216 ;
    END
  END g_front_0_u_front__q_data_in[39]
  PIN g_front_0_u_front__q_data_in[3]
    DIRECTION INPUT ;
    USE SIGNAL ;
    PORT
      LAYER M5 ;
        RECT  9.084 215.808 9.108 216 ;
    END
  END g_front_0_u_front__q_data_in[3]
  PIN g_front_0_u_front__q_data_in[400]
    DIRECTION INPUT ;
    USE SIGNAL ;
    PORT
      LAYER M5 ;
        RECT  72.156 215.808 72.18 216 ;
    END
  END g_front_0_u_front__q_data_in[400]
  PIN g_front_0_u_front__q_data_in[401]
    DIRECTION INPUT ;
    USE SIGNAL ;
    PORT
      LAYER M5 ;
        RECT  72.3 215.808 72.324 216 ;
    END
  END g_front_0_u_front__q_data_in[401]
  PIN g_front_0_u_front__q_data_in[402]
    DIRECTION INPUT ;
    USE SIGNAL ;
    PORT
      LAYER M5 ;
        RECT  72.492 215.808 72.516 216 ;
    END
  END g_front_0_u_front__q_data_in[402]
  PIN g_front_0_u_front__q_data_in[403]
    DIRECTION INPUT ;
    USE SIGNAL ;
    PORT
      LAYER M5 ;
        RECT  72.636 215.808 72.66 216 ;
    END
  END g_front_0_u_front__q_data_in[403]
  PIN g_front_0_u_front__q_data_in[404]
    DIRECTION INPUT ;
    USE SIGNAL ;
    PORT
      LAYER M5 ;
        RECT  72.78 215.808 72.804 216 ;
    END
  END g_front_0_u_front__q_data_in[404]
  PIN g_front_0_u_front__q_data_in[405]
    DIRECTION INPUT ;
    USE SIGNAL ;
    PORT
      LAYER M5 ;
        RECT  72.924 215.808 72.948 216 ;
    END
  END g_front_0_u_front__q_data_in[405]
  PIN g_front_0_u_front__q_data_in[406]
    DIRECTION INPUT ;
    USE SIGNAL ;
    PORT
      LAYER M5 ;
        RECT  73.116 215.808 73.14 216 ;
    END
  END g_front_0_u_front__q_data_in[406]
  PIN g_front_0_u_front__q_data_in[407]
    DIRECTION INPUT ;
    USE SIGNAL ;
    PORT
      LAYER M5 ;
        RECT  73.26 215.808 73.284 216 ;
    END
  END g_front_0_u_front__q_data_in[407]
  PIN g_front_0_u_front__q_data_in[408]
    DIRECTION INPUT ;
    USE SIGNAL ;
    PORT
      LAYER M5 ;
        RECT  73.404 215.808 73.428 216 ;
    END
  END g_front_0_u_front__q_data_in[408]
  PIN g_front_0_u_front__q_data_in[409]
    DIRECTION INPUT ;
    USE SIGNAL ;
    PORT
      LAYER M5 ;
        RECT  73.596 215.808 73.62 216 ;
    END
  END g_front_0_u_front__q_data_in[409]
  PIN g_front_0_u_front__q_data_in[40]
    DIRECTION INPUT ;
    USE SIGNAL ;
    PORT
      LAYER M5 ;
        RECT  14.94 215.808 14.964 216 ;
    END
  END g_front_0_u_front__q_data_in[40]
  PIN g_front_0_u_front__q_data_in[410]
    DIRECTION INPUT ;
    USE SIGNAL ;
    PORT
      LAYER M5 ;
        RECT  73.74 215.808 73.764 216 ;
    END
  END g_front_0_u_front__q_data_in[410]
  PIN g_front_0_u_front__q_data_in[411]
    DIRECTION INPUT ;
    USE SIGNAL ;
    PORT
      LAYER M5 ;
        RECT  73.884 215.808 73.908 216 ;
    END
  END g_front_0_u_front__q_data_in[411]
  PIN g_front_0_u_front__q_data_in[412]
    DIRECTION INPUT ;
    USE SIGNAL ;
    PORT
      LAYER M5 ;
        RECT  74.076 215.808 74.1 216 ;
    END
  END g_front_0_u_front__q_data_in[412]
  PIN g_front_0_u_front__q_data_in[413]
    DIRECTION INPUT ;
    USE SIGNAL ;
    PORT
      LAYER M5 ;
        RECT  74.22 215.808 74.244 216 ;
    END
  END g_front_0_u_front__q_data_in[413]
  PIN g_front_0_u_front__q_data_in[414]
    DIRECTION INPUT ;
    USE SIGNAL ;
    PORT
      LAYER M5 ;
        RECT  74.364 215.808 74.388 216 ;
    END
  END g_front_0_u_front__q_data_in[414]
  PIN g_front_0_u_front__q_data_in[415]
    DIRECTION INPUT ;
    USE SIGNAL ;
    PORT
      LAYER M5 ;
        RECT  74.556 215.808 74.58 216 ;
    END
  END g_front_0_u_front__q_data_in[415]
  PIN g_front_0_u_front__q_data_in[416]
    DIRECTION INPUT ;
    USE SIGNAL ;
    PORT
      LAYER M5 ;
        RECT  74.7 215.808 74.724 216 ;
    END
  END g_front_0_u_front__q_data_in[416]
  PIN g_front_0_u_front__q_data_in[417]
    DIRECTION INPUT ;
    USE SIGNAL ;
    PORT
      LAYER M5 ;
        RECT  74.844 215.808 74.868 216 ;
    END
  END g_front_0_u_front__q_data_in[417]
  PIN g_front_0_u_front__q_data_in[418]
    DIRECTION INPUT ;
    USE SIGNAL ;
    PORT
      LAYER M5 ;
        RECT  75.036 215.808 75.06 216 ;
    END
  END g_front_0_u_front__q_data_in[418]
  PIN g_front_0_u_front__q_data_in[419]
    DIRECTION INPUT ;
    USE SIGNAL ;
    PORT
      LAYER M5 ;
        RECT  75.18 215.808 75.204 216 ;
    END
  END g_front_0_u_front__q_data_in[419]
  PIN g_front_0_u_front__q_data_in[41]
    DIRECTION INPUT ;
    USE SIGNAL ;
    PORT
      LAYER M5 ;
        RECT  15.084 215.808 15.108 216 ;
    END
  END g_front_0_u_front__q_data_in[41]
  PIN g_front_0_u_front__q_data_in[420]
    DIRECTION INPUT ;
    USE SIGNAL ;
    PORT
      LAYER M5 ;
        RECT  75.324 215.808 75.348 216 ;
    END
  END g_front_0_u_front__q_data_in[420]
  PIN g_front_0_u_front__q_data_in[421]
    DIRECTION INPUT ;
    USE SIGNAL ;
    PORT
      LAYER M5 ;
        RECT  75.468 215.808 75.492 216 ;
    END
  END g_front_0_u_front__q_data_in[421]
  PIN g_front_0_u_front__q_data_in[422]
    DIRECTION INPUT ;
    USE SIGNAL ;
    PORT
      LAYER M5 ;
        RECT  75.66 215.808 75.684 216 ;
    END
  END g_front_0_u_front__q_data_in[422]
  PIN g_front_0_u_front__q_data_in[423]
    DIRECTION INPUT ;
    USE SIGNAL ;
    PORT
      LAYER M5 ;
        RECT  75.804 215.808 75.828 216 ;
    END
  END g_front_0_u_front__q_data_in[423]
  PIN g_front_0_u_front__q_data_in[424]
    DIRECTION INPUT ;
    USE SIGNAL ;
    PORT
      LAYER M5 ;
        RECT  75.948 215.808 75.972 216 ;
    END
  END g_front_0_u_front__q_data_in[424]
  PIN g_front_0_u_front__q_data_in[425]
    DIRECTION INPUT ;
    USE SIGNAL ;
    PORT
      LAYER M5 ;
        RECT  76.14 215.808 76.164 216 ;
    END
  END g_front_0_u_front__q_data_in[425]
  PIN g_front_0_u_front__q_data_in[426]
    DIRECTION INPUT ;
    USE SIGNAL ;
    PORT
      LAYER M5 ;
        RECT  76.284 215.808 76.308 216 ;
    END
  END g_front_0_u_front__q_data_in[426]
  PIN g_front_0_u_front__q_data_in[427]
    DIRECTION INPUT ;
    USE SIGNAL ;
    PORT
      LAYER M5 ;
        RECT  76.428 215.808 76.452 216 ;
    END
  END g_front_0_u_front__q_data_in[427]
  PIN g_front_0_u_front__q_data_in[428]
    DIRECTION INPUT ;
    USE SIGNAL ;
    PORT
      LAYER M5 ;
        RECT  76.62 215.808 76.644 216 ;
    END
  END g_front_0_u_front__q_data_in[428]
  PIN g_front_0_u_front__q_data_in[429]
    DIRECTION INPUT ;
    USE SIGNAL ;
    PORT
      LAYER M5 ;
        RECT  76.764 215.808 76.788 216 ;
    END
  END g_front_0_u_front__q_data_in[429]
  PIN g_front_0_u_front__q_data_in[42]
    DIRECTION INPUT ;
    USE SIGNAL ;
    PORT
      LAYER M5 ;
        RECT  15.276 215.808 15.3 216 ;
    END
  END g_front_0_u_front__q_data_in[42]
  PIN g_front_0_u_front__q_data_in[430]
    DIRECTION INPUT ;
    USE SIGNAL ;
    PORT
      LAYER M5 ;
        RECT  76.908 215.808 76.932 216 ;
    END
  END g_front_0_u_front__q_data_in[430]
  PIN g_front_0_u_front__q_data_in[431]
    DIRECTION INPUT ;
    USE SIGNAL ;
    PORT
      LAYER M5 ;
        RECT  77.1 215.808 77.124 216 ;
    END
  END g_front_0_u_front__q_data_in[431]
  PIN g_front_0_u_front__q_data_in[432]
    DIRECTION INPUT ;
    USE SIGNAL ;
    PORT
      LAYER M5 ;
        RECT  77.244 215.808 77.268 216 ;
    END
  END g_front_0_u_front__q_data_in[432]
  PIN g_front_0_u_front__q_data_in[433]
    DIRECTION INPUT ;
    USE SIGNAL ;
    PORT
      LAYER M5 ;
        RECT  77.388 215.808 77.412 216 ;
    END
  END g_front_0_u_front__q_data_in[433]
  PIN g_front_0_u_front__q_data_in[434]
    DIRECTION INPUT ;
    USE SIGNAL ;
    PORT
      LAYER M5 ;
        RECT  77.532 215.808 77.556 216 ;
    END
  END g_front_0_u_front__q_data_in[434]
  PIN g_front_0_u_front__q_data_in[435]
    DIRECTION INPUT ;
    USE SIGNAL ;
    PORT
      LAYER M5 ;
        RECT  77.724 215.808 77.748 216 ;
    END
  END g_front_0_u_front__q_data_in[435]
  PIN g_front_0_u_front__q_data_in[436]
    DIRECTION INPUT ;
    USE SIGNAL ;
    PORT
      LAYER M5 ;
        RECT  77.868 215.808 77.892 216 ;
    END
  END g_front_0_u_front__q_data_in[436]
  PIN g_front_0_u_front__q_data_in[437]
    DIRECTION INPUT ;
    USE SIGNAL ;
    PORT
      LAYER M5 ;
        RECT  78.012 215.808 78.036 216 ;
    END
  END g_front_0_u_front__q_data_in[437]
  PIN g_front_0_u_front__q_data_in[438]
    DIRECTION INPUT ;
    USE SIGNAL ;
    PORT
      LAYER M5 ;
        RECT  78.204 215.808 78.228 216 ;
    END
  END g_front_0_u_front__q_data_in[438]
  PIN g_front_0_u_front__q_data_in[439]
    DIRECTION INPUT ;
    USE SIGNAL ;
    PORT
      LAYER M5 ;
        RECT  78.348 215.808 78.372 216 ;
    END
  END g_front_0_u_front__q_data_in[439]
  PIN g_front_0_u_front__q_data_in[43]
    DIRECTION INPUT ;
    USE SIGNAL ;
    PORT
      LAYER M5 ;
        RECT  15.42 215.808 15.444 216 ;
    END
  END g_front_0_u_front__q_data_in[43]
  PIN g_front_0_u_front__q_data_in[440]
    DIRECTION INPUT ;
    USE SIGNAL ;
    PORT
      LAYER M5 ;
        RECT  78.492 215.808 78.516 216 ;
    END
  END g_front_0_u_front__q_data_in[440]
  PIN g_front_0_u_front__q_data_in[441]
    DIRECTION INPUT ;
    USE SIGNAL ;
    PORT
      LAYER M5 ;
        RECT  78.684 215.808 78.708 216 ;
    END
  END g_front_0_u_front__q_data_in[441]
  PIN g_front_0_u_front__q_data_in[442]
    DIRECTION INPUT ;
    USE SIGNAL ;
    PORT
      LAYER M5 ;
        RECT  78.828 215.808 78.852 216 ;
    END
  END g_front_0_u_front__q_data_in[442]
  PIN g_front_0_u_front__q_data_in[443]
    DIRECTION INPUT ;
    USE SIGNAL ;
    PORT
      LAYER M5 ;
        RECT  78.972 215.808 78.996 216 ;
    END
  END g_front_0_u_front__q_data_in[443]
  PIN g_front_0_u_front__q_data_in[444]
    DIRECTION INPUT ;
    USE SIGNAL ;
    PORT
      LAYER M5 ;
        RECT  79.164 215.808 79.188 216 ;
    END
  END g_front_0_u_front__q_data_in[444]
  PIN g_front_0_u_front__q_data_in[445]
    DIRECTION INPUT ;
    USE SIGNAL ;
    PORT
      LAYER M5 ;
        RECT  79.308 215.808 79.332 216 ;
    END
  END g_front_0_u_front__q_data_in[445]
  PIN g_front_0_u_front__q_data_in[446]
    DIRECTION INPUT ;
    USE SIGNAL ;
    PORT
      LAYER M5 ;
        RECT  79.452 215.808 79.476 216 ;
    END
  END g_front_0_u_front__q_data_in[446]
  PIN g_front_0_u_front__q_data_in[447]
    DIRECTION INPUT ;
    USE SIGNAL ;
    PORT
      LAYER M5 ;
        RECT  79.644 215.808 79.668 216 ;
    END
  END g_front_0_u_front__q_data_in[447]
  PIN g_front_0_u_front__q_data_in[448]
    DIRECTION INPUT ;
    USE SIGNAL ;
    PORT
      LAYER M5 ;
        RECT  79.788 215.808 79.812 216 ;
    END
  END g_front_0_u_front__q_data_in[448]
  PIN g_front_0_u_front__q_data_in[449]
    DIRECTION INPUT ;
    USE SIGNAL ;
    PORT
      LAYER M5 ;
        RECT  79.932 215.808 79.956 216 ;
    END
  END g_front_0_u_front__q_data_in[449]
  PIN g_front_0_u_front__q_data_in[44]
    DIRECTION INPUT ;
    USE SIGNAL ;
    PORT
      LAYER M5 ;
        RECT  15.564 215.808 15.588 216 ;
    END
  END g_front_0_u_front__q_data_in[44]
  PIN g_front_0_u_front__q_data_in[450]
    DIRECTION INPUT ;
    USE SIGNAL ;
    PORT
      LAYER M5 ;
        RECT  80.076 215.808 80.1 216 ;
    END
  END g_front_0_u_front__q_data_in[450]
  PIN g_front_0_u_front__q_data_in[451]
    DIRECTION INPUT ;
    USE SIGNAL ;
    PORT
      LAYER M5 ;
        RECT  80.268 215.808 80.292 216 ;
    END
  END g_front_0_u_front__q_data_in[451]
  PIN g_front_0_u_front__q_data_in[452]
    DIRECTION INPUT ;
    USE SIGNAL ;
    PORT
      LAYER M5 ;
        RECT  80.412 215.808 80.436 216 ;
    END
  END g_front_0_u_front__q_data_in[452]
  PIN g_front_0_u_front__q_data_in[453]
    DIRECTION INPUT ;
    USE SIGNAL ;
    PORT
      LAYER M5 ;
        RECT  80.556 215.808 80.58 216 ;
    END
  END g_front_0_u_front__q_data_in[453]
  PIN g_front_0_u_front__q_data_in[454]
    DIRECTION INPUT ;
    USE SIGNAL ;
    PORT
      LAYER M5 ;
        RECT  80.748 215.808 80.772 216 ;
    END
  END g_front_0_u_front__q_data_in[454]
  PIN g_front_0_u_front__q_data_in[455]
    DIRECTION INPUT ;
    USE SIGNAL ;
    PORT
      LAYER M5 ;
        RECT  80.892 215.808 80.916 216 ;
    END
  END g_front_0_u_front__q_data_in[455]
  PIN g_front_0_u_front__q_data_in[456]
    DIRECTION INPUT ;
    USE SIGNAL ;
    PORT
      LAYER M5 ;
        RECT  81.036 215.808 81.06 216 ;
    END
  END g_front_0_u_front__q_data_in[456]
  PIN g_front_0_u_front__q_data_in[457]
    DIRECTION INPUT ;
    USE SIGNAL ;
    PORT
      LAYER M5 ;
        RECT  81.228 215.808 81.252 216 ;
    END
  END g_front_0_u_front__q_data_in[457]
  PIN g_front_0_u_front__q_data_in[458]
    DIRECTION INPUT ;
    USE SIGNAL ;
    PORT
      LAYER M5 ;
        RECT  81.372 215.808 81.396 216 ;
    END
  END g_front_0_u_front__q_data_in[458]
  PIN g_front_0_u_front__q_data_in[459]
    DIRECTION INPUT ;
    USE SIGNAL ;
    PORT
      LAYER M5 ;
        RECT  81.516 215.808 81.54 216 ;
    END
  END g_front_0_u_front__q_data_in[459]
  PIN g_front_0_u_front__q_data_in[45]
    DIRECTION INPUT ;
    USE SIGNAL ;
    PORT
      LAYER M5 ;
        RECT  15.756 215.808 15.78 216 ;
    END
  END g_front_0_u_front__q_data_in[45]
  PIN g_front_0_u_front__q_data_in[460]
    DIRECTION INPUT ;
    USE SIGNAL ;
    PORT
      LAYER M5 ;
        RECT  81.708 215.808 81.732 216 ;
    END
  END g_front_0_u_front__q_data_in[460]
  PIN g_front_0_u_front__q_data_in[461]
    DIRECTION INPUT ;
    USE SIGNAL ;
    PORT
      LAYER M5 ;
        RECT  81.852 215.808 81.876 216 ;
    END
  END g_front_0_u_front__q_data_in[461]
  PIN g_front_0_u_front__q_data_in[462]
    DIRECTION INPUT ;
    USE SIGNAL ;
    PORT
      LAYER M5 ;
        RECT  81.996 215.808 82.02 216 ;
    END
  END g_front_0_u_front__q_data_in[462]
  PIN g_front_0_u_front__q_data_in[463]
    DIRECTION INPUT ;
    USE SIGNAL ;
    PORT
      LAYER M5 ;
        RECT  82.14 215.808 82.164 216 ;
    END
  END g_front_0_u_front__q_data_in[463]
  PIN g_front_0_u_front__q_data_in[464]
    DIRECTION INPUT ;
    USE SIGNAL ;
    PORT
      LAYER M5 ;
        RECT  82.332 215.808 82.356 216 ;
    END
  END g_front_0_u_front__q_data_in[464]
  PIN g_front_0_u_front__q_data_in[465]
    DIRECTION INPUT ;
    USE SIGNAL ;
    PORT
      LAYER M5 ;
        RECT  82.476 215.808 82.5 216 ;
    END
  END g_front_0_u_front__q_data_in[465]
  PIN g_front_0_u_front__q_data_in[466]
    DIRECTION INPUT ;
    USE SIGNAL ;
    PORT
      LAYER M5 ;
        RECT  82.62 215.808 82.644 216 ;
    END
  END g_front_0_u_front__q_data_in[466]
  PIN g_front_0_u_front__q_data_in[467]
    DIRECTION INPUT ;
    USE SIGNAL ;
    PORT
      LAYER M5 ;
        RECT  82.812 215.808 82.836 216 ;
    END
  END g_front_0_u_front__q_data_in[467]
  PIN g_front_0_u_front__q_data_in[468]
    DIRECTION INPUT ;
    USE SIGNAL ;
    PORT
      LAYER M5 ;
        RECT  82.956 215.808 82.98 216 ;
    END
  END g_front_0_u_front__q_data_in[468]
  PIN g_front_0_u_front__q_data_in[469]
    DIRECTION INPUT ;
    USE SIGNAL ;
    PORT
      LAYER M5 ;
        RECT  83.1 215.808 83.124 216 ;
    END
  END g_front_0_u_front__q_data_in[469]
  PIN g_front_0_u_front__q_data_in[46]
    DIRECTION INPUT ;
    USE SIGNAL ;
    PORT
      LAYER M5 ;
        RECT  15.9 215.808 15.924 216 ;
    END
  END g_front_0_u_front__q_data_in[46]
  PIN g_front_0_u_front__q_data_in[470]
    DIRECTION INPUT ;
    USE SIGNAL ;
    PORT
      LAYER M5 ;
        RECT  83.292 215.808 83.316 216 ;
    END
  END g_front_0_u_front__q_data_in[470]
  PIN g_front_0_u_front__q_data_in[471]
    DIRECTION INPUT ;
    USE SIGNAL ;
    PORT
      LAYER M5 ;
        RECT  83.436 215.808 83.46 216 ;
    END
  END g_front_0_u_front__q_data_in[471]
  PIN g_front_0_u_front__q_data_in[472]
    DIRECTION INPUT ;
    USE SIGNAL ;
    PORT
      LAYER M5 ;
        RECT  83.58 215.808 83.604 216 ;
    END
  END g_front_0_u_front__q_data_in[472]
  PIN g_front_0_u_front__q_data_in[473]
    DIRECTION INPUT ;
    USE SIGNAL ;
    PORT
      LAYER M5 ;
        RECT  83.772 215.808 83.796 216 ;
    END
  END g_front_0_u_front__q_data_in[473]
  PIN g_front_0_u_front__q_data_in[474]
    DIRECTION INPUT ;
    USE SIGNAL ;
    PORT
      LAYER M5 ;
        RECT  83.916 215.808 83.94 216 ;
    END
  END g_front_0_u_front__q_data_in[474]
  PIN g_front_0_u_front__q_data_in[475]
    DIRECTION INPUT ;
    USE SIGNAL ;
    PORT
      LAYER M5 ;
        RECT  84.06 215.808 84.084 216 ;
    END
  END g_front_0_u_front__q_data_in[475]
  PIN g_front_0_u_front__q_data_in[476]
    DIRECTION INPUT ;
    USE SIGNAL ;
    PORT
      LAYER M5 ;
        RECT  84.252 215.808 84.276 216 ;
    END
  END g_front_0_u_front__q_data_in[476]
  PIN g_front_0_u_front__q_data_in[477]
    DIRECTION INPUT ;
    USE SIGNAL ;
    PORT
      LAYER M5 ;
        RECT  84.396 215.808 84.42 216 ;
    END
  END g_front_0_u_front__q_data_in[477]
  PIN g_front_0_u_front__q_data_in[478]
    DIRECTION INPUT ;
    USE SIGNAL ;
    PORT
      LAYER M5 ;
        RECT  84.54 215.808 84.564 216 ;
    END
  END g_front_0_u_front__q_data_in[478]
  PIN g_front_0_u_front__q_data_in[479]
    DIRECTION INPUT ;
    USE SIGNAL ;
    PORT
      LAYER M5 ;
        RECT  84.684 215.808 84.708 216 ;
    END
  END g_front_0_u_front__q_data_in[479]
  PIN g_front_0_u_front__q_data_in[47]
    DIRECTION INPUT ;
    USE SIGNAL ;
    PORT
      LAYER M5 ;
        RECT  16.044 215.808 16.068 216 ;
    END
  END g_front_0_u_front__q_data_in[47]
  PIN g_front_0_u_front__q_data_in[480]
    DIRECTION INPUT ;
    USE SIGNAL ;
    PORT
      LAYER M5 ;
        RECT  84.876 215.808 84.9 216 ;
    END
  END g_front_0_u_front__q_data_in[480]
  PIN g_front_0_u_front__q_data_in[481]
    DIRECTION INPUT ;
    USE SIGNAL ;
    PORT
      LAYER M5 ;
        RECT  85.02 215.808 85.044 216 ;
    END
  END g_front_0_u_front__q_data_in[481]
  PIN g_front_0_u_front__q_data_in[482]
    DIRECTION INPUT ;
    USE SIGNAL ;
    PORT
      LAYER M5 ;
        RECT  85.164 215.808 85.188 216 ;
    END
  END g_front_0_u_front__q_data_in[482]
  PIN g_front_0_u_front__q_data_in[483]
    DIRECTION INPUT ;
    USE SIGNAL ;
    PORT
      LAYER M5 ;
        RECT  85.356 215.808 85.38 216 ;
    END
  END g_front_0_u_front__q_data_in[483]
  PIN g_front_0_u_front__q_data_in[484]
    DIRECTION INPUT ;
    USE SIGNAL ;
    PORT
      LAYER M5 ;
        RECT  85.5 215.808 85.524 216 ;
    END
  END g_front_0_u_front__q_data_in[484]
  PIN g_front_0_u_front__q_data_in[485]
    DIRECTION INPUT ;
    USE SIGNAL ;
    PORT
      LAYER M5 ;
        RECT  85.644 215.808 85.668 216 ;
    END
  END g_front_0_u_front__q_data_in[485]
  PIN g_front_0_u_front__q_data_in[486]
    DIRECTION INPUT ;
    USE SIGNAL ;
    PORT
      LAYER M5 ;
        RECT  85.836 215.808 85.86 216 ;
    END
  END g_front_0_u_front__q_data_in[486]
  PIN g_front_0_u_front__q_data_in[487]
    DIRECTION INPUT ;
    USE SIGNAL ;
    PORT
      LAYER M5 ;
        RECT  85.98 215.808 86.004 216 ;
    END
  END g_front_0_u_front__q_data_in[487]
  PIN g_front_0_u_front__q_data_in[488]
    DIRECTION INPUT ;
    USE SIGNAL ;
    PORT
      LAYER M5 ;
        RECT  86.124 215.808 86.148 216 ;
    END
  END g_front_0_u_front__q_data_in[488]
  PIN g_front_0_u_front__q_data_in[489]
    DIRECTION INPUT ;
    USE SIGNAL ;
    PORT
      LAYER M5 ;
        RECT  86.316 215.808 86.34 216 ;
    END
  END g_front_0_u_front__q_data_in[489]
  PIN g_front_0_u_front__q_data_in[48]
    DIRECTION INPUT ;
    USE SIGNAL ;
    PORT
      LAYER M5 ;
        RECT  16.236 215.808 16.26 216 ;
    END
  END g_front_0_u_front__q_data_in[48]
  PIN g_front_0_u_front__q_data_in[490]
    DIRECTION INPUT ;
    USE SIGNAL ;
    PORT
      LAYER M5 ;
        RECT  86.46 215.808 86.484 216 ;
    END
  END g_front_0_u_front__q_data_in[490]
  PIN g_front_0_u_front__q_data_in[491]
    DIRECTION INPUT ;
    USE SIGNAL ;
    PORT
      LAYER M5 ;
        RECT  86.604 215.808 86.628 216 ;
    END
  END g_front_0_u_front__q_data_in[491]
  PIN g_front_0_u_front__q_data_in[492]
    DIRECTION INPUT ;
    USE SIGNAL ;
    PORT
      LAYER M5 ;
        RECT  86.796 215.808 86.82 216 ;
    END
  END g_front_0_u_front__q_data_in[492]
  PIN g_front_0_u_front__q_data_in[493]
    DIRECTION INPUT ;
    USE SIGNAL ;
    PORT
      LAYER M5 ;
        RECT  86.94 215.808 86.964 216 ;
    END
  END g_front_0_u_front__q_data_in[493]
  PIN g_front_0_u_front__q_data_in[494]
    DIRECTION INPUT ;
    USE SIGNAL ;
    PORT
      LAYER M5 ;
        RECT  87.084 215.808 87.108 216 ;
    END
  END g_front_0_u_front__q_data_in[494]
  PIN g_front_0_u_front__q_data_in[495]
    DIRECTION INPUT ;
    USE SIGNAL ;
    PORT
      LAYER M5 ;
        RECT  87.228 215.808 87.252 216 ;
    END
  END g_front_0_u_front__q_data_in[495]
  PIN g_front_0_u_front__q_data_in[496]
    DIRECTION INPUT ;
    USE SIGNAL ;
    PORT
      LAYER M5 ;
        RECT  87.42 215.808 87.444 216 ;
    END
  END g_front_0_u_front__q_data_in[496]
  PIN g_front_0_u_front__q_data_in[497]
    DIRECTION INPUT ;
    USE SIGNAL ;
    PORT
      LAYER M5 ;
        RECT  87.564 215.808 87.588 216 ;
    END
  END g_front_0_u_front__q_data_in[497]
  PIN g_front_0_u_front__q_data_in[498]
    DIRECTION INPUT ;
    USE SIGNAL ;
    PORT
      LAYER M5 ;
        RECT  87.708 215.808 87.732 216 ;
    END
  END g_front_0_u_front__q_data_in[498]
  PIN g_front_0_u_front__q_data_in[499]
    DIRECTION INPUT ;
    USE SIGNAL ;
    PORT
      LAYER M5 ;
        RECT  87.9 215.808 87.924 216 ;
    END
  END g_front_0_u_front__q_data_in[499]
  PIN g_front_0_u_front__q_data_in[49]
    DIRECTION INPUT ;
    USE SIGNAL ;
    PORT
      LAYER M5 ;
        RECT  16.38 215.808 16.404 216 ;
    END
  END g_front_0_u_front__q_data_in[49]
  PIN g_front_0_u_front__q_data_in[4]
    DIRECTION INPUT ;
    USE SIGNAL ;
    PORT
      LAYER M5 ;
        RECT  9.228 215.808 9.252 216 ;
    END
  END g_front_0_u_front__q_data_in[4]
  PIN g_front_0_u_front__q_data_in[500]
    DIRECTION INPUT ;
    USE SIGNAL ;
    PORT
      LAYER M5 ;
        RECT  88.044 215.808 88.068 216 ;
    END
  END g_front_0_u_front__q_data_in[500]
  PIN g_front_0_u_front__q_data_in[501]
    DIRECTION INPUT ;
    USE SIGNAL ;
    PORT
      LAYER M5 ;
        RECT  88.188 215.808 88.212 216 ;
    END
  END g_front_0_u_front__q_data_in[501]
  PIN g_front_0_u_front__q_data_in[502]
    DIRECTION INPUT ;
    USE SIGNAL ;
    PORT
      LAYER M5 ;
        RECT  88.38 215.808 88.404 216 ;
    END
  END g_front_0_u_front__q_data_in[502]
  PIN g_front_0_u_front__q_data_in[503]
    DIRECTION INPUT ;
    USE SIGNAL ;
    PORT
      LAYER M5 ;
        RECT  88.524 215.808 88.548 216 ;
    END
  END g_front_0_u_front__q_data_in[503]
  PIN g_front_0_u_front__q_data_in[504]
    DIRECTION INPUT ;
    USE SIGNAL ;
    PORT
      LAYER M5 ;
        RECT  88.668 215.808 88.692 216 ;
    END
  END g_front_0_u_front__q_data_in[504]
  PIN g_front_0_u_front__q_data_in[505]
    DIRECTION INPUT ;
    USE SIGNAL ;
    PORT
      LAYER M5 ;
        RECT  88.86 215.808 88.884 216 ;
    END
  END g_front_0_u_front__q_data_in[505]
  PIN g_front_0_u_front__q_data_in[506]
    DIRECTION INPUT ;
    USE SIGNAL ;
    PORT
      LAYER M5 ;
        RECT  89.004 215.808 89.028 216 ;
    END
  END g_front_0_u_front__q_data_in[506]
  PIN g_front_0_u_front__q_data_in[507]
    DIRECTION INPUT ;
    USE SIGNAL ;
    PORT
      LAYER M5 ;
        RECT  89.148 215.808 89.172 216 ;
    END
  END g_front_0_u_front__q_data_in[507]
  PIN g_front_0_u_front__q_data_in[508]
    DIRECTION INPUT ;
    USE SIGNAL ;
    PORT
      LAYER M5 ;
        RECT  89.292 215.808 89.316 216 ;
    END
  END g_front_0_u_front__q_data_in[508]
  PIN g_front_0_u_front__q_data_in[509]
    DIRECTION INPUT ;
    USE SIGNAL ;
    PORT
      LAYER M5 ;
        RECT  89.484 215.808 89.508 216 ;
    END
  END g_front_0_u_front__q_data_in[509]
  PIN g_front_0_u_front__q_data_in[50]
    DIRECTION INPUT ;
    USE SIGNAL ;
    PORT
      LAYER M5 ;
        RECT  16.524 215.808 16.548 216 ;
    END
  END g_front_0_u_front__q_data_in[50]
  PIN g_front_0_u_front__q_data_in[510]
    DIRECTION INPUT ;
    USE SIGNAL ;
    PORT
      LAYER M5 ;
        RECT  89.628 215.808 89.652 216 ;
    END
  END g_front_0_u_front__q_data_in[510]
  PIN g_front_0_u_front__q_data_in[511]
    DIRECTION INPUT ;
    USE SIGNAL ;
    PORT
      LAYER M5 ;
        RECT  89.772 215.808 89.796 216 ;
    END
  END g_front_0_u_front__q_data_in[511]
  PIN g_front_0_u_front__q_data_in[51]
    DIRECTION INPUT ;
    USE SIGNAL ;
    PORT
      LAYER M5 ;
        RECT  16.668 215.808 16.692 216 ;
    END
  END g_front_0_u_front__q_data_in[51]
  PIN g_front_0_u_front__q_data_in[52]
    DIRECTION INPUT ;
    USE SIGNAL ;
    PORT
      LAYER M5 ;
        RECT  16.86 215.808 16.884 216 ;
    END
  END g_front_0_u_front__q_data_in[52]
  PIN g_front_0_u_front__q_data_in[53]
    DIRECTION INPUT ;
    USE SIGNAL ;
    PORT
      LAYER M5 ;
        RECT  17.004 215.808 17.028 216 ;
    END
  END g_front_0_u_front__q_data_in[53]
  PIN g_front_0_u_front__q_data_in[54]
    DIRECTION INPUT ;
    USE SIGNAL ;
    PORT
      LAYER M5 ;
        RECT  17.148 215.808 17.172 216 ;
    END
  END g_front_0_u_front__q_data_in[54]
  PIN g_front_0_u_front__q_data_in[55]
    DIRECTION INPUT ;
    USE SIGNAL ;
    PORT
      LAYER M5 ;
        RECT  17.34 215.808 17.364 216 ;
    END
  END g_front_0_u_front__q_data_in[55]
  PIN g_front_0_u_front__q_data_in[56]
    DIRECTION INPUT ;
    USE SIGNAL ;
    PORT
      LAYER M5 ;
        RECT  17.484 215.808 17.508 216 ;
    END
  END g_front_0_u_front__q_data_in[56]
  PIN g_front_0_u_front__q_data_in[57]
    DIRECTION INPUT ;
    USE SIGNAL ;
    PORT
      LAYER M5 ;
        RECT  17.628 215.808 17.652 216 ;
    END
  END g_front_0_u_front__q_data_in[57]
  PIN g_front_0_u_front__q_data_in[58]
    DIRECTION INPUT ;
    USE SIGNAL ;
    PORT
      LAYER M5 ;
        RECT  17.82 215.808 17.844 216 ;
    END
  END g_front_0_u_front__q_data_in[58]
  PIN g_front_0_u_front__q_data_in[59]
    DIRECTION INPUT ;
    USE SIGNAL ;
    PORT
      LAYER M5 ;
        RECT  17.964 215.808 17.988 216 ;
    END
  END g_front_0_u_front__q_data_in[59]
  PIN g_front_0_u_front__q_data_in[5]
    DIRECTION INPUT ;
    USE SIGNAL ;
    PORT
      LAYER M5 ;
        RECT  9.372 215.808 9.396 216 ;
    END
  END g_front_0_u_front__q_data_in[5]
  PIN g_front_0_u_front__q_data_in[60]
    DIRECTION INPUT ;
    USE SIGNAL ;
    PORT
      LAYER M5 ;
        RECT  18.108 215.808 18.132 216 ;
    END
  END g_front_0_u_front__q_data_in[60]
  PIN g_front_0_u_front__q_data_in[61]
    DIRECTION INPUT ;
    USE SIGNAL ;
    PORT
      LAYER M5 ;
        RECT  18.3 215.808 18.324 216 ;
    END
  END g_front_0_u_front__q_data_in[61]
  PIN g_front_0_u_front__q_data_in[62]
    DIRECTION INPUT ;
    USE SIGNAL ;
    PORT
      LAYER M5 ;
        RECT  18.444 215.808 18.468 216 ;
    END
  END g_front_0_u_front__q_data_in[62]
  PIN g_front_0_u_front__q_data_in[63]
    DIRECTION INPUT ;
    USE SIGNAL ;
    PORT
      LAYER M5 ;
        RECT  18.588 215.808 18.612 216 ;
    END
  END g_front_0_u_front__q_data_in[63]
  PIN g_front_0_u_front__q_data_in[64]
    DIRECTION INPUT ;
    USE SIGNAL ;
    PORT
      LAYER M5 ;
        RECT  18.732 215.808 18.756 216 ;
    END
  END g_front_0_u_front__q_data_in[64]
  PIN g_front_0_u_front__q_data_in[65]
    DIRECTION INPUT ;
    USE SIGNAL ;
    PORT
      LAYER M5 ;
        RECT  18.924 215.808 18.948 216 ;
    END
  END g_front_0_u_front__q_data_in[65]
  PIN g_front_0_u_front__q_data_in[66]
    DIRECTION INPUT ;
    USE SIGNAL ;
    PORT
      LAYER M5 ;
        RECT  19.068 215.808 19.092 216 ;
    END
  END g_front_0_u_front__q_data_in[66]
  PIN g_front_0_u_front__q_data_in[67]
    DIRECTION INPUT ;
    USE SIGNAL ;
    PORT
      LAYER M5 ;
        RECT  19.212 215.808 19.236 216 ;
    END
  END g_front_0_u_front__q_data_in[67]
  PIN g_front_0_u_front__q_data_in[68]
    DIRECTION INPUT ;
    USE SIGNAL ;
    PORT
      LAYER M5 ;
        RECT  19.404 215.808 19.428 216 ;
    END
  END g_front_0_u_front__q_data_in[68]
  PIN g_front_0_u_front__q_data_in[69]
    DIRECTION INPUT ;
    USE SIGNAL ;
    PORT
      LAYER M5 ;
        RECT  19.548 215.808 19.572 216 ;
    END
  END g_front_0_u_front__q_data_in[69]
  PIN g_front_0_u_front__q_data_in[6]
    DIRECTION INPUT ;
    USE SIGNAL ;
    PORT
      LAYER M5 ;
        RECT  9.516 215.808 9.54 216 ;
    END
  END g_front_0_u_front__q_data_in[6]
  PIN g_front_0_u_front__q_data_in[70]
    DIRECTION INPUT ;
    USE SIGNAL ;
    PORT
      LAYER M5 ;
        RECT  19.692 215.808 19.716 216 ;
    END
  END g_front_0_u_front__q_data_in[70]
  PIN g_front_0_u_front__q_data_in[71]
    DIRECTION INPUT ;
    USE SIGNAL ;
    PORT
      LAYER M5 ;
        RECT  19.884 215.808 19.908 216 ;
    END
  END g_front_0_u_front__q_data_in[71]
  PIN g_front_0_u_front__q_data_in[72]
    DIRECTION INPUT ;
    USE SIGNAL ;
    PORT
      LAYER M5 ;
        RECT  20.028 215.808 20.052 216 ;
    END
  END g_front_0_u_front__q_data_in[72]
  PIN g_front_0_u_front__q_data_in[73]
    DIRECTION INPUT ;
    USE SIGNAL ;
    PORT
      LAYER M5 ;
        RECT  20.172 215.808 20.196 216 ;
    END
  END g_front_0_u_front__q_data_in[73]
  PIN g_front_0_u_front__q_data_in[74]
    DIRECTION INPUT ;
    USE SIGNAL ;
    PORT
      LAYER M5 ;
        RECT  20.364 215.808 20.388 216 ;
    END
  END g_front_0_u_front__q_data_in[74]
  PIN g_front_0_u_front__q_data_in[75]
    DIRECTION INPUT ;
    USE SIGNAL ;
    PORT
      LAYER M5 ;
        RECT  20.508 215.808 20.532 216 ;
    END
  END g_front_0_u_front__q_data_in[75]
  PIN g_front_0_u_front__q_data_in[76]
    DIRECTION INPUT ;
    USE SIGNAL ;
    PORT
      LAYER M5 ;
        RECT  20.652 215.808 20.676 216 ;
    END
  END g_front_0_u_front__q_data_in[76]
  PIN g_front_0_u_front__q_data_in[77]
    DIRECTION INPUT ;
    USE SIGNAL ;
    PORT
      LAYER M5 ;
        RECT  20.844 215.808 20.868 216 ;
    END
  END g_front_0_u_front__q_data_in[77]
  PIN g_front_0_u_front__q_data_in[78]
    DIRECTION INPUT ;
    USE SIGNAL ;
    PORT
      LAYER M5 ;
        RECT  20.988 215.808 21.012 216 ;
    END
  END g_front_0_u_front__q_data_in[78]
  PIN g_front_0_u_front__q_data_in[79]
    DIRECTION INPUT ;
    USE SIGNAL ;
    PORT
      LAYER M5 ;
        RECT  21.132 215.808 21.156 216 ;
    END
  END g_front_0_u_front__q_data_in[79]
  PIN g_front_0_u_front__q_data_in[7]
    DIRECTION INPUT ;
    USE SIGNAL ;
    PORT
      LAYER M5 ;
        RECT  9.708 215.808 9.732 216 ;
    END
  END g_front_0_u_front__q_data_in[7]
  PIN g_front_0_u_front__q_data_in[80]
    DIRECTION INPUT ;
    USE SIGNAL ;
    PORT
      LAYER M5 ;
        RECT  21.276 215.808 21.3 216 ;
    END
  END g_front_0_u_front__q_data_in[80]
  PIN g_front_0_u_front__q_data_in[81]
    DIRECTION INPUT ;
    USE SIGNAL ;
    PORT
      LAYER M5 ;
        RECT  21.468 215.808 21.492 216 ;
    END
  END g_front_0_u_front__q_data_in[81]
  PIN g_front_0_u_front__q_data_in[82]
    DIRECTION INPUT ;
    USE SIGNAL ;
    PORT
      LAYER M5 ;
        RECT  21.612 215.808 21.636 216 ;
    END
  END g_front_0_u_front__q_data_in[82]
  PIN g_front_0_u_front__q_data_in[83]
    DIRECTION INPUT ;
    USE SIGNAL ;
    PORT
      LAYER M5 ;
        RECT  21.756 215.808 21.78 216 ;
    END
  END g_front_0_u_front__q_data_in[83]
  PIN g_front_0_u_front__q_data_in[84]
    DIRECTION INPUT ;
    USE SIGNAL ;
    PORT
      LAYER M5 ;
        RECT  21.948 215.808 21.972 216 ;
    END
  END g_front_0_u_front__q_data_in[84]
  PIN g_front_0_u_front__q_data_in[85]
    DIRECTION INPUT ;
    USE SIGNAL ;
    PORT
      LAYER M5 ;
        RECT  22.092 215.808 22.116 216 ;
    END
  END g_front_0_u_front__q_data_in[85]
  PIN g_front_0_u_front__q_data_in[86]
    DIRECTION INPUT ;
    USE SIGNAL ;
    PORT
      LAYER M5 ;
        RECT  22.236 215.808 22.26 216 ;
    END
  END g_front_0_u_front__q_data_in[86]
  PIN g_front_0_u_front__q_data_in[87]
    DIRECTION INPUT ;
    USE SIGNAL ;
    PORT
      LAYER M5 ;
        RECT  22.428 215.808 22.452 216 ;
    END
  END g_front_0_u_front__q_data_in[87]
  PIN g_front_0_u_front__q_data_in[88]
    DIRECTION INPUT ;
    USE SIGNAL ;
    PORT
      LAYER M5 ;
        RECT  22.572 215.808 22.596 216 ;
    END
  END g_front_0_u_front__q_data_in[88]
  PIN g_front_0_u_front__q_data_in[89]
    DIRECTION INPUT ;
    USE SIGNAL ;
    PORT
      LAYER M5 ;
        RECT  22.716 215.808 22.74 216 ;
    END
  END g_front_0_u_front__q_data_in[89]
  PIN g_front_0_u_front__q_data_in[8]
    DIRECTION INPUT ;
    USE SIGNAL ;
    PORT
      LAYER M5 ;
        RECT  9.852 215.808 9.876 216 ;
    END
  END g_front_0_u_front__q_data_in[8]
  PIN g_front_0_u_front__q_data_in[90]
    DIRECTION INPUT ;
    USE SIGNAL ;
    PORT
      LAYER M5 ;
        RECT  22.908 215.808 22.932 216 ;
    END
  END g_front_0_u_front__q_data_in[90]
  PIN g_front_0_u_front__q_data_in[91]
    DIRECTION INPUT ;
    USE SIGNAL ;
    PORT
      LAYER M5 ;
        RECT  23.052 215.808 23.076 216 ;
    END
  END g_front_0_u_front__q_data_in[91]
  PIN g_front_0_u_front__q_data_in[92]
    DIRECTION INPUT ;
    USE SIGNAL ;
    PORT
      LAYER M5 ;
        RECT  23.196 215.808 23.22 216 ;
    END
  END g_front_0_u_front__q_data_in[92]
  PIN g_front_0_u_front__q_data_in[93]
    DIRECTION INPUT ;
    USE SIGNAL ;
    PORT
      LAYER M5 ;
        RECT  23.34 215.808 23.364 216 ;
    END
  END g_front_0_u_front__q_data_in[93]
  PIN g_front_0_u_front__q_data_in[94]
    DIRECTION INPUT ;
    USE SIGNAL ;
    PORT
      LAYER M5 ;
        RECT  23.532 215.808 23.556 216 ;
    END
  END g_front_0_u_front__q_data_in[94]
  PIN g_front_0_u_front__q_data_in[95]
    DIRECTION INPUT ;
    USE SIGNAL ;
    PORT
      LAYER M5 ;
        RECT  23.676 215.808 23.7 216 ;
    END
  END g_front_0_u_front__q_data_in[95]
  PIN g_front_0_u_front__q_data_in[96]
    DIRECTION INPUT ;
    USE SIGNAL ;
    PORT
      LAYER M5 ;
        RECT  23.82 215.808 23.844 216 ;
    END
  END g_front_0_u_front__q_data_in[96]
  PIN g_front_0_u_front__q_data_in[97]
    DIRECTION INPUT ;
    USE SIGNAL ;
    PORT
      LAYER M5 ;
        RECT  24.012 215.808 24.036 216 ;
    END
  END g_front_0_u_front__q_data_in[97]
  PIN g_front_0_u_front__q_data_in[98]
    DIRECTION INPUT ;
    USE SIGNAL ;
    PORT
      LAYER M5 ;
        RECT  24.156 215.808 24.18 216 ;
    END
  END g_front_0_u_front__q_data_in[98]
  PIN g_front_0_u_front__q_data_in[99]
    DIRECTION INPUT ;
    USE SIGNAL ;
    PORT
      LAYER M5 ;
        RECT  24.3 215.808 24.324 216 ;
    END
  END g_front_0_u_front__q_data_in[99]
  PIN g_front_0_u_front__q_data_in[9]
    DIRECTION INPUT ;
    USE SIGNAL ;
    PORT
      LAYER M5 ;
        RECT  9.996 215.808 10.02 216 ;
    END
  END g_front_0_u_front__q_data_in[9]
  PIN g_front_0_u_front__q_valid_in[0]
    DIRECTION INPUT ;
    USE SIGNAL ;
    PORT
      LAYER M5 ;
        RECT  89.964 215.808 89.988 216 ;
    END
  END g_front_0_u_front__q_valid_in[0]
  PIN g_front_0_u_front__row_in[0]
    DIRECTION INPUT ;
    USE SIGNAL ;
    PORT
      LAYER M5 ;
        RECT  90.108 215.808 90.132 216 ;
    END
  END g_front_0_u_front__row_in[0]
  PIN g_front_0_u_front__row_in[100]
    DIRECTION INPUT ;
    USE SIGNAL ;
    PORT
      LAYER M5 ;
        RECT  105.996 215.808 106.02 216 ;
    END
  END g_front_0_u_front__row_in[100]
  PIN g_front_0_u_front__row_in[101]
    DIRECTION INPUT ;
    USE SIGNAL ;
    PORT
      LAYER M5 ;
        RECT  106.14 215.808 106.164 216 ;
    END
  END g_front_0_u_front__row_in[101]
  PIN g_front_0_u_front__row_in[102]
    DIRECTION INPUT ;
    USE SIGNAL ;
    PORT
      LAYER M5 ;
        RECT  106.332 215.808 106.356 216 ;
    END
  END g_front_0_u_front__row_in[102]
  PIN g_front_0_u_front__row_in[103]
    DIRECTION INPUT ;
    USE SIGNAL ;
    PORT
      LAYER M5 ;
        RECT  106.476 215.808 106.5 216 ;
    END
  END g_front_0_u_front__row_in[103]
  PIN g_front_0_u_front__row_in[104]
    DIRECTION INPUT ;
    USE SIGNAL ;
    PORT
      LAYER M5 ;
        RECT  106.62 215.808 106.644 216 ;
    END
  END g_front_0_u_front__row_in[104]
  PIN g_front_0_u_front__row_in[105]
    DIRECTION INPUT ;
    USE SIGNAL ;
    PORT
      LAYER M5 ;
        RECT  106.812 215.808 106.836 216 ;
    END
  END g_front_0_u_front__row_in[105]
  PIN g_front_0_u_front__row_in[106]
    DIRECTION INPUT ;
    USE SIGNAL ;
    PORT
      LAYER M5 ;
        RECT  106.956 215.808 106.98 216 ;
    END
  END g_front_0_u_front__row_in[106]
  PIN g_front_0_u_front__row_in[107]
    DIRECTION INPUT ;
    USE SIGNAL ;
    PORT
      LAYER M5 ;
        RECT  107.1 215.808 107.124 216 ;
    END
  END g_front_0_u_front__row_in[107]
  PIN g_front_0_u_front__row_in[108]
    DIRECTION INPUT ;
    USE SIGNAL ;
    PORT
      LAYER M5 ;
        RECT  107.292 215.808 107.316 216 ;
    END
  END g_front_0_u_front__row_in[108]
  PIN g_front_0_u_front__row_in[109]
    DIRECTION INPUT ;
    USE SIGNAL ;
    PORT
      LAYER M5 ;
        RECT  107.436 215.808 107.46 216 ;
    END
  END g_front_0_u_front__row_in[109]
  PIN g_front_0_u_front__row_in[10]
    DIRECTION INPUT ;
    USE SIGNAL ;
    PORT
      LAYER M5 ;
        RECT  91.692 215.808 91.716 216 ;
    END
  END g_front_0_u_front__row_in[10]
  PIN g_front_0_u_front__row_in[110]
    DIRECTION INPUT ;
    USE SIGNAL ;
    PORT
      LAYER M5 ;
        RECT  107.58 215.808 107.604 216 ;
    END
  END g_front_0_u_front__row_in[110]
  PIN g_front_0_u_front__row_in[111]
    DIRECTION INPUT ;
    USE SIGNAL ;
    PORT
      LAYER M5 ;
        RECT  107.772 215.808 107.796 216 ;
    END
  END g_front_0_u_front__row_in[111]
  PIN g_front_0_u_front__row_in[112]
    DIRECTION INPUT ;
    USE SIGNAL ;
    PORT
      LAYER M5 ;
        RECT  107.916 215.808 107.94 216 ;
    END
  END g_front_0_u_front__row_in[112]
  PIN g_front_0_u_front__row_in[113]
    DIRECTION INPUT ;
    USE SIGNAL ;
    PORT
      LAYER M5 ;
        RECT  108.06 215.808 108.084 216 ;
    END
  END g_front_0_u_front__row_in[113]
  PIN g_front_0_u_front__row_in[114]
    DIRECTION INPUT ;
    USE SIGNAL ;
    PORT
      LAYER M5 ;
        RECT  108.204 215.808 108.228 216 ;
    END
  END g_front_0_u_front__row_in[114]
  PIN g_front_0_u_front__row_in[115]
    DIRECTION INPUT ;
    USE SIGNAL ;
    PORT
      LAYER M5 ;
        RECT  108.396 215.808 108.42 216 ;
    END
  END g_front_0_u_front__row_in[115]
  PIN g_front_0_u_front__row_in[116]
    DIRECTION INPUT ;
    USE SIGNAL ;
    PORT
      LAYER M5 ;
        RECT  108.54 215.808 108.564 216 ;
    END
  END g_front_0_u_front__row_in[116]
  PIN g_front_0_u_front__row_in[117]
    DIRECTION INPUT ;
    USE SIGNAL ;
    PORT
      LAYER M5 ;
        RECT  108.684 215.808 108.708 216 ;
    END
  END g_front_0_u_front__row_in[117]
  PIN g_front_0_u_front__row_in[118]
    DIRECTION INPUT ;
    USE SIGNAL ;
    PORT
      LAYER M5 ;
        RECT  108.876 215.808 108.9 216 ;
    END
  END g_front_0_u_front__row_in[118]
  PIN g_front_0_u_front__row_in[119]
    DIRECTION INPUT ;
    USE SIGNAL ;
    PORT
      LAYER M5 ;
        RECT  109.02 215.808 109.044 216 ;
    END
  END g_front_0_u_front__row_in[119]
  PIN g_front_0_u_front__row_in[11]
    DIRECTION INPUT ;
    USE SIGNAL ;
    PORT
      LAYER M5 ;
        RECT  91.836 215.808 91.86 216 ;
    END
  END g_front_0_u_front__row_in[11]
  PIN g_front_0_u_front__row_in[120]
    DIRECTION INPUT ;
    USE SIGNAL ;
    PORT
      LAYER M5 ;
        RECT  109.164 215.808 109.188 216 ;
    END
  END g_front_0_u_front__row_in[120]
  PIN g_front_0_u_front__row_in[121]
    DIRECTION INPUT ;
    USE SIGNAL ;
    PORT
      LAYER M5 ;
        RECT  109.356 215.808 109.38 216 ;
    END
  END g_front_0_u_front__row_in[121]
  PIN g_front_0_u_front__row_in[122]
    DIRECTION INPUT ;
    USE SIGNAL ;
    PORT
      LAYER M5 ;
        RECT  109.5 215.808 109.524 216 ;
    END
  END g_front_0_u_front__row_in[122]
  PIN g_front_0_u_front__row_in[123]
    DIRECTION INPUT ;
    USE SIGNAL ;
    PORT
      LAYER M5 ;
        RECT  109.644 215.808 109.668 216 ;
    END
  END g_front_0_u_front__row_in[123]
  PIN g_front_0_u_front__row_in[124]
    DIRECTION INPUT ;
    USE SIGNAL ;
    PORT
      LAYER M5 ;
        RECT  109.836 215.808 109.86 216 ;
    END
  END g_front_0_u_front__row_in[124]
  PIN g_front_0_u_front__row_in[125]
    DIRECTION INPUT ;
    USE SIGNAL ;
    PORT
      LAYER M5 ;
        RECT  109.98 215.808 110.004 216 ;
    END
  END g_front_0_u_front__row_in[125]
  PIN g_front_0_u_front__row_in[126]
    DIRECTION INPUT ;
    USE SIGNAL ;
    PORT
      LAYER M5 ;
        RECT  110.124 215.808 110.148 216 ;
    END
  END g_front_0_u_front__row_in[126]
  PIN g_front_0_u_front__row_in[127]
    DIRECTION INPUT ;
    USE SIGNAL ;
    PORT
      LAYER M5 ;
        RECT  110.316 215.808 110.34 216 ;
    END
  END g_front_0_u_front__row_in[127]
  PIN g_front_0_u_front__row_in[128]
    DIRECTION INPUT ;
    USE SIGNAL ;
    PORT
      LAYER M5 ;
        RECT  110.46 215.808 110.484 216 ;
    END
  END g_front_0_u_front__row_in[128]
  PIN g_front_0_u_front__row_in[129]
    DIRECTION INPUT ;
    USE SIGNAL ;
    PORT
      LAYER M5 ;
        RECT  110.604 215.808 110.628 216 ;
    END
  END g_front_0_u_front__row_in[129]
  PIN g_front_0_u_front__row_in[12]
    DIRECTION INPUT ;
    USE SIGNAL ;
    PORT
      LAYER M5 ;
        RECT  92.028 215.808 92.052 216 ;
    END
  END g_front_0_u_front__row_in[12]
  PIN g_front_0_u_front__row_in[130]
    DIRECTION INPUT ;
    USE SIGNAL ;
    PORT
      LAYER M5 ;
        RECT  110.748 215.808 110.772 216 ;
    END
  END g_front_0_u_front__row_in[130]
  PIN g_front_0_u_front__row_in[131]
    DIRECTION INPUT ;
    USE SIGNAL ;
    PORT
      LAYER M5 ;
        RECT  110.94 215.808 110.964 216 ;
    END
  END g_front_0_u_front__row_in[131]
  PIN g_front_0_u_front__row_in[132]
    DIRECTION INPUT ;
    USE SIGNAL ;
    PORT
      LAYER M5 ;
        RECT  111.084 215.808 111.108 216 ;
    END
  END g_front_0_u_front__row_in[132]
  PIN g_front_0_u_front__row_in[133]
    DIRECTION INPUT ;
    USE SIGNAL ;
    PORT
      LAYER M5 ;
        RECT  111.228 215.808 111.252 216 ;
    END
  END g_front_0_u_front__row_in[133]
  PIN g_front_0_u_front__row_in[134]
    DIRECTION INPUT ;
    USE SIGNAL ;
    PORT
      LAYER M5 ;
        RECT  111.42 215.808 111.444 216 ;
    END
  END g_front_0_u_front__row_in[134]
  PIN g_front_0_u_front__row_in[135]
    DIRECTION INPUT ;
    USE SIGNAL ;
    PORT
      LAYER M5 ;
        RECT  111.564 215.808 111.588 216 ;
    END
  END g_front_0_u_front__row_in[135]
  PIN g_front_0_u_front__row_in[136]
    DIRECTION INPUT ;
    USE SIGNAL ;
    PORT
      LAYER M5 ;
        RECT  111.708 215.808 111.732 216 ;
    END
  END g_front_0_u_front__row_in[136]
  PIN g_front_0_u_front__row_in[137]
    DIRECTION INPUT ;
    USE SIGNAL ;
    PORT
      LAYER M5 ;
        RECT  111.9 215.808 111.924 216 ;
    END
  END g_front_0_u_front__row_in[137]
  PIN g_front_0_u_front__row_in[138]
    DIRECTION INPUT ;
    USE SIGNAL ;
    PORT
      LAYER M5 ;
        RECT  112.044 215.808 112.068 216 ;
    END
  END g_front_0_u_front__row_in[138]
  PIN g_front_0_u_front__row_in[139]
    DIRECTION INPUT ;
    USE SIGNAL ;
    PORT
      LAYER M5 ;
        RECT  112.188 215.808 112.212 216 ;
    END
  END g_front_0_u_front__row_in[139]
  PIN g_front_0_u_front__row_in[13]
    DIRECTION INPUT ;
    USE SIGNAL ;
    PORT
      LAYER M5 ;
        RECT  92.172 215.808 92.196 216 ;
    END
  END g_front_0_u_front__row_in[13]
  PIN g_front_0_u_front__row_in[140]
    DIRECTION INPUT ;
    USE SIGNAL ;
    PORT
      LAYER M5 ;
        RECT  112.38 215.808 112.404 216 ;
    END
  END g_front_0_u_front__row_in[140]
  PIN g_front_0_u_front__row_in[141]
    DIRECTION INPUT ;
    USE SIGNAL ;
    PORT
      LAYER M5 ;
        RECT  112.524 215.808 112.548 216 ;
    END
  END g_front_0_u_front__row_in[141]
  PIN g_front_0_u_front__row_in[142]
    DIRECTION INPUT ;
    USE SIGNAL ;
    PORT
      LAYER M5 ;
        RECT  112.668 215.808 112.692 216 ;
    END
  END g_front_0_u_front__row_in[142]
  PIN g_front_0_u_front__row_in[143]
    DIRECTION INPUT ;
    USE SIGNAL ;
    PORT
      LAYER M5 ;
        RECT  112.812 215.808 112.836 216 ;
    END
  END g_front_0_u_front__row_in[143]
  PIN g_front_0_u_front__row_in[144]
    DIRECTION INPUT ;
    USE SIGNAL ;
    PORT
      LAYER M5 ;
        RECT  113.004 215.808 113.028 216 ;
    END
  END g_front_0_u_front__row_in[144]
  PIN g_front_0_u_front__row_in[145]
    DIRECTION INPUT ;
    USE SIGNAL ;
    PORT
      LAYER M5 ;
        RECT  113.148 215.808 113.172 216 ;
    END
  END g_front_0_u_front__row_in[145]
  PIN g_front_0_u_front__row_in[146]
    DIRECTION INPUT ;
    USE SIGNAL ;
    PORT
      LAYER M5 ;
        RECT  113.292 215.808 113.316 216 ;
    END
  END g_front_0_u_front__row_in[146]
  PIN g_front_0_u_front__row_in[147]
    DIRECTION INPUT ;
    USE SIGNAL ;
    PORT
      LAYER M5 ;
        RECT  113.484 215.808 113.508 216 ;
    END
  END g_front_0_u_front__row_in[147]
  PIN g_front_0_u_front__row_in[148]
    DIRECTION INPUT ;
    USE SIGNAL ;
    PORT
      LAYER M5 ;
        RECT  113.628 215.808 113.652 216 ;
    END
  END g_front_0_u_front__row_in[148]
  PIN g_front_0_u_front__row_in[149]
    DIRECTION INPUT ;
    USE SIGNAL ;
    PORT
      LAYER M5 ;
        RECT  113.772 215.808 113.796 216 ;
    END
  END g_front_0_u_front__row_in[149]
  PIN g_front_0_u_front__row_in[14]
    DIRECTION INPUT ;
    USE SIGNAL ;
    PORT
      LAYER M5 ;
        RECT  92.316 215.808 92.34 216 ;
    END
  END g_front_0_u_front__row_in[14]
  PIN g_front_0_u_front__row_in[150]
    DIRECTION INPUT ;
    USE SIGNAL ;
    PORT
      LAYER M5 ;
        RECT  113.964 215.808 113.988 216 ;
    END
  END g_front_0_u_front__row_in[150]
  PIN g_front_0_u_front__row_in[151]
    DIRECTION INPUT ;
    USE SIGNAL ;
    PORT
      LAYER M5 ;
        RECT  114.108 215.808 114.132 216 ;
    END
  END g_front_0_u_front__row_in[151]
  PIN g_front_0_u_front__row_in[152]
    DIRECTION INPUT ;
    USE SIGNAL ;
    PORT
      LAYER M5 ;
        RECT  114.252 215.808 114.276 216 ;
    END
  END g_front_0_u_front__row_in[152]
  PIN g_front_0_u_front__row_in[153]
    DIRECTION INPUT ;
    USE SIGNAL ;
    PORT
      LAYER M5 ;
        RECT  114.444 215.808 114.468 216 ;
    END
  END g_front_0_u_front__row_in[153]
  PIN g_front_0_u_front__row_in[154]
    DIRECTION INPUT ;
    USE SIGNAL ;
    PORT
      LAYER M5 ;
        RECT  114.588 215.808 114.612 216 ;
    END
  END g_front_0_u_front__row_in[154]
  PIN g_front_0_u_front__row_in[155]
    DIRECTION INPUT ;
    USE SIGNAL ;
    PORT
      LAYER M5 ;
        RECT  114.732 215.808 114.756 216 ;
    END
  END g_front_0_u_front__row_in[155]
  PIN g_front_0_u_front__row_in[156]
    DIRECTION INPUT ;
    USE SIGNAL ;
    PORT
      LAYER M5 ;
        RECT  114.924 215.808 114.948 216 ;
    END
  END g_front_0_u_front__row_in[156]
  PIN g_front_0_u_front__row_in[157]
    DIRECTION INPUT ;
    USE SIGNAL ;
    PORT
      LAYER M5 ;
        RECT  115.068 215.808 115.092 216 ;
    END
  END g_front_0_u_front__row_in[157]
  PIN g_front_0_u_front__row_in[158]
    DIRECTION INPUT ;
    USE SIGNAL ;
    PORT
      LAYER M5 ;
        RECT  115.212 215.808 115.236 216 ;
    END
  END g_front_0_u_front__row_in[158]
  PIN g_front_0_u_front__row_in[159]
    DIRECTION INPUT ;
    USE SIGNAL ;
    PORT
      LAYER M5 ;
        RECT  115.356 215.808 115.38 216 ;
    END
  END g_front_0_u_front__row_in[159]
  PIN g_front_0_u_front__row_in[15]
    DIRECTION INPUT ;
    USE SIGNAL ;
    PORT
      LAYER M5 ;
        RECT  92.508 215.808 92.532 216 ;
    END
  END g_front_0_u_front__row_in[15]
  PIN g_front_0_u_front__row_in[160]
    DIRECTION INPUT ;
    USE SIGNAL ;
    PORT
      LAYER M5 ;
        RECT  115.548 215.808 115.572 216 ;
    END
  END g_front_0_u_front__row_in[160]
  PIN g_front_0_u_front__row_in[161]
    DIRECTION INPUT ;
    USE SIGNAL ;
    PORT
      LAYER M5 ;
        RECT  115.692 215.808 115.716 216 ;
    END
  END g_front_0_u_front__row_in[161]
  PIN g_front_0_u_front__row_in[162]
    DIRECTION INPUT ;
    USE SIGNAL ;
    PORT
      LAYER M5 ;
        RECT  115.836 215.808 115.86 216 ;
    END
  END g_front_0_u_front__row_in[162]
  PIN g_front_0_u_front__row_in[163]
    DIRECTION INPUT ;
    USE SIGNAL ;
    PORT
      LAYER M5 ;
        RECT  116.028 215.808 116.052 216 ;
    END
  END g_front_0_u_front__row_in[163]
  PIN g_front_0_u_front__row_in[164]
    DIRECTION INPUT ;
    USE SIGNAL ;
    PORT
      LAYER M5 ;
        RECT  116.172 215.808 116.196 216 ;
    END
  END g_front_0_u_front__row_in[164]
  PIN g_front_0_u_front__row_in[165]
    DIRECTION INPUT ;
    USE SIGNAL ;
    PORT
      LAYER M5 ;
        RECT  116.316 215.808 116.34 216 ;
    END
  END g_front_0_u_front__row_in[165]
  PIN g_front_0_u_front__row_in[166]
    DIRECTION INPUT ;
    USE SIGNAL ;
    PORT
      LAYER M5 ;
        RECT  116.508 215.808 116.532 216 ;
    END
  END g_front_0_u_front__row_in[166]
  PIN g_front_0_u_front__row_in[167]
    DIRECTION INPUT ;
    USE SIGNAL ;
    PORT
      LAYER M5 ;
        RECT  116.652 215.808 116.676 216 ;
    END
  END g_front_0_u_front__row_in[167]
  PIN g_front_0_u_front__row_in[168]
    DIRECTION INPUT ;
    USE SIGNAL ;
    PORT
      LAYER M5 ;
        RECT  116.796 215.808 116.82 216 ;
    END
  END g_front_0_u_front__row_in[168]
  PIN g_front_0_u_front__row_in[169]
    DIRECTION INPUT ;
    USE SIGNAL ;
    PORT
      LAYER M5 ;
        RECT  116.988 215.808 117.012 216 ;
    END
  END g_front_0_u_front__row_in[169]
  PIN g_front_0_u_front__row_in[16]
    DIRECTION INPUT ;
    USE SIGNAL ;
    PORT
      LAYER M5 ;
        RECT  92.652 215.808 92.676 216 ;
    END
  END g_front_0_u_front__row_in[16]
  PIN g_front_0_u_front__row_in[170]
    DIRECTION INPUT ;
    USE SIGNAL ;
    PORT
      LAYER M5 ;
        RECT  117.132 215.808 117.156 216 ;
    END
  END g_front_0_u_front__row_in[170]
  PIN g_front_0_u_front__row_in[171]
    DIRECTION INPUT ;
    USE SIGNAL ;
    PORT
      LAYER M5 ;
        RECT  117.276 215.808 117.3 216 ;
    END
  END g_front_0_u_front__row_in[171]
  PIN g_front_0_u_front__row_in[172]
    DIRECTION INPUT ;
    USE SIGNAL ;
    PORT
      LAYER M5 ;
        RECT  117.42 215.808 117.444 216 ;
    END
  END g_front_0_u_front__row_in[172]
  PIN g_front_0_u_front__row_in[173]
    DIRECTION INPUT ;
    USE SIGNAL ;
    PORT
      LAYER M5 ;
        RECT  117.612 215.808 117.636 216 ;
    END
  END g_front_0_u_front__row_in[173]
  PIN g_front_0_u_front__row_in[174]
    DIRECTION INPUT ;
    USE SIGNAL ;
    PORT
      LAYER M5 ;
        RECT  117.756 215.808 117.78 216 ;
    END
  END g_front_0_u_front__row_in[174]
  PIN g_front_0_u_front__row_in[175]
    DIRECTION INPUT ;
    USE SIGNAL ;
    PORT
      LAYER M5 ;
        RECT  117.9 215.808 117.924 216 ;
    END
  END g_front_0_u_front__row_in[175]
  PIN g_front_0_u_front__row_in[176]
    DIRECTION INPUT ;
    USE SIGNAL ;
    PORT
      LAYER M5 ;
        RECT  118.092 215.808 118.116 216 ;
    END
  END g_front_0_u_front__row_in[176]
  PIN g_front_0_u_front__row_in[177]
    DIRECTION INPUT ;
    USE SIGNAL ;
    PORT
      LAYER M5 ;
        RECT  118.236 215.808 118.26 216 ;
    END
  END g_front_0_u_front__row_in[177]
  PIN g_front_0_u_front__row_in[178]
    DIRECTION INPUT ;
    USE SIGNAL ;
    PORT
      LAYER M5 ;
        RECT  118.38 215.808 118.404 216 ;
    END
  END g_front_0_u_front__row_in[178]
  PIN g_front_0_u_front__row_in[179]
    DIRECTION INPUT ;
    USE SIGNAL ;
    PORT
      LAYER M5 ;
        RECT  118.572 215.808 118.596 216 ;
    END
  END g_front_0_u_front__row_in[179]
  PIN g_front_0_u_front__row_in[17]
    DIRECTION INPUT ;
    USE SIGNAL ;
    PORT
      LAYER M5 ;
        RECT  92.796 215.808 92.82 216 ;
    END
  END g_front_0_u_front__row_in[17]
  PIN g_front_0_u_front__row_in[180]
    DIRECTION INPUT ;
    USE SIGNAL ;
    PORT
      LAYER M5 ;
        RECT  118.716 215.808 118.74 216 ;
    END
  END g_front_0_u_front__row_in[180]
  PIN g_front_0_u_front__row_in[181]
    DIRECTION INPUT ;
    USE SIGNAL ;
    PORT
      LAYER M5 ;
        RECT  118.86 215.808 118.884 216 ;
    END
  END g_front_0_u_front__row_in[181]
  PIN g_front_0_u_front__row_in[182]
    DIRECTION INPUT ;
    USE SIGNAL ;
    PORT
      LAYER M5 ;
        RECT  119.052 215.808 119.076 216 ;
    END
  END g_front_0_u_front__row_in[182]
  PIN g_front_0_u_front__row_in[183]
    DIRECTION INPUT ;
    USE SIGNAL ;
    PORT
      LAYER M5 ;
        RECT  119.196 215.808 119.22 216 ;
    END
  END g_front_0_u_front__row_in[183]
  PIN g_front_0_u_front__row_in[184]
    DIRECTION INPUT ;
    USE SIGNAL ;
    PORT
      LAYER M5 ;
        RECT  119.34 215.808 119.364 216 ;
    END
  END g_front_0_u_front__row_in[184]
  PIN g_front_0_u_front__row_in[185]
    DIRECTION INPUT ;
    USE SIGNAL ;
    PORT
      LAYER M5 ;
        RECT  119.532 215.808 119.556 216 ;
    END
  END g_front_0_u_front__row_in[185]
  PIN g_front_0_u_front__row_in[186]
    DIRECTION INPUT ;
    USE SIGNAL ;
    PORT
      LAYER M5 ;
        RECT  119.676 215.808 119.7 216 ;
    END
  END g_front_0_u_front__row_in[186]
  PIN g_front_0_u_front__row_in[187]
    DIRECTION INPUT ;
    USE SIGNAL ;
    PORT
      LAYER M5 ;
        RECT  119.82 215.808 119.844 216 ;
    END
  END g_front_0_u_front__row_in[187]
  PIN g_front_0_u_front__row_in[188]
    DIRECTION INPUT ;
    USE SIGNAL ;
    PORT
      LAYER M5 ;
        RECT  119.964 215.808 119.988 216 ;
    END
  END g_front_0_u_front__row_in[188]
  PIN g_front_0_u_front__row_in[189]
    DIRECTION INPUT ;
    USE SIGNAL ;
    PORT
      LAYER M5 ;
        RECT  120.156 215.808 120.18 216 ;
    END
  END g_front_0_u_front__row_in[189]
  PIN g_front_0_u_front__row_in[18]
    DIRECTION INPUT ;
    USE SIGNAL ;
    PORT
      LAYER M5 ;
        RECT  92.988 215.808 93.012 216 ;
    END
  END g_front_0_u_front__row_in[18]
  PIN g_front_0_u_front__row_in[190]
    DIRECTION INPUT ;
    USE SIGNAL ;
    PORT
      LAYER M5 ;
        RECT  120.3 215.808 120.324 216 ;
    END
  END g_front_0_u_front__row_in[190]
  PIN g_front_0_u_front__row_in[191]
    DIRECTION INPUT ;
    USE SIGNAL ;
    PORT
      LAYER M5 ;
        RECT  120.444 215.808 120.468 216 ;
    END
  END g_front_0_u_front__row_in[191]
  PIN g_front_0_u_front__row_in[192]
    DIRECTION INPUT ;
    USE SIGNAL ;
    PORT
      LAYER M5 ;
        RECT  120.636 215.808 120.66 216 ;
    END
  END g_front_0_u_front__row_in[192]
  PIN g_front_0_u_front__row_in[193]
    DIRECTION INPUT ;
    USE SIGNAL ;
    PORT
      LAYER M5 ;
        RECT  120.78 215.808 120.804 216 ;
    END
  END g_front_0_u_front__row_in[193]
  PIN g_front_0_u_front__row_in[194]
    DIRECTION INPUT ;
    USE SIGNAL ;
    PORT
      LAYER M5 ;
        RECT  120.924 215.808 120.948 216 ;
    END
  END g_front_0_u_front__row_in[194]
  PIN g_front_0_u_front__row_in[195]
    DIRECTION INPUT ;
    USE SIGNAL ;
    PORT
      LAYER M5 ;
        RECT  121.116 215.808 121.14 216 ;
    END
  END g_front_0_u_front__row_in[195]
  PIN g_front_0_u_front__row_in[196]
    DIRECTION INPUT ;
    USE SIGNAL ;
    PORT
      LAYER M5 ;
        RECT  121.26 215.808 121.284 216 ;
    END
  END g_front_0_u_front__row_in[196]
  PIN g_front_0_u_front__row_in[197]
    DIRECTION INPUT ;
    USE SIGNAL ;
    PORT
      LAYER M5 ;
        RECT  121.404 215.808 121.428 216 ;
    END
  END g_front_0_u_front__row_in[197]
  PIN g_front_0_u_front__row_in[198]
    DIRECTION INPUT ;
    USE SIGNAL ;
    PORT
      LAYER M5 ;
        RECT  121.596 215.808 121.62 216 ;
    END
  END g_front_0_u_front__row_in[198]
  PIN g_front_0_u_front__row_in[199]
    DIRECTION INPUT ;
    USE SIGNAL ;
    PORT
      LAYER M5 ;
        RECT  121.74 215.808 121.764 216 ;
    END
  END g_front_0_u_front__row_in[199]
  PIN g_front_0_u_front__row_in[19]
    DIRECTION INPUT ;
    USE SIGNAL ;
    PORT
      LAYER M5 ;
        RECT  93.132 215.808 93.156 216 ;
    END
  END g_front_0_u_front__row_in[19]
  PIN g_front_0_u_front__row_in[1]
    DIRECTION INPUT ;
    USE SIGNAL ;
    PORT
      LAYER M5 ;
        RECT  90.252 215.808 90.276 216 ;
    END
  END g_front_0_u_front__row_in[1]
  PIN g_front_0_u_front__row_in[200]
    DIRECTION INPUT ;
    USE SIGNAL ;
    PORT
      LAYER M5 ;
        RECT  121.884 215.808 121.908 216 ;
    END
  END g_front_0_u_front__row_in[200]
  PIN g_front_0_u_front__row_in[201]
    DIRECTION INPUT ;
    USE SIGNAL ;
    PORT
      LAYER M5 ;
        RECT  122.076 215.808 122.1 216 ;
    END
  END g_front_0_u_front__row_in[201]
  PIN g_front_0_u_front__row_in[202]
    DIRECTION INPUT ;
    USE SIGNAL ;
    PORT
      LAYER M5 ;
        RECT  122.22 215.808 122.244 216 ;
    END
  END g_front_0_u_front__row_in[202]
  PIN g_front_0_u_front__row_in[203]
    DIRECTION INPUT ;
    USE SIGNAL ;
    PORT
      LAYER M5 ;
        RECT  122.364 215.808 122.388 216 ;
    END
  END g_front_0_u_front__row_in[203]
  PIN g_front_0_u_front__row_in[204]
    DIRECTION INPUT ;
    USE SIGNAL ;
    PORT
      LAYER M5 ;
        RECT  122.508 215.808 122.532 216 ;
    END
  END g_front_0_u_front__row_in[204]
  PIN g_front_0_u_front__row_in[205]
    DIRECTION INPUT ;
    USE SIGNAL ;
    PORT
      LAYER M5 ;
        RECT  122.7 215.808 122.724 216 ;
    END
  END g_front_0_u_front__row_in[205]
  PIN g_front_0_u_front__row_in[206]
    DIRECTION INPUT ;
    USE SIGNAL ;
    PORT
      LAYER M5 ;
        RECT  122.844 215.808 122.868 216 ;
    END
  END g_front_0_u_front__row_in[206]
  PIN g_front_0_u_front__row_in[207]
    DIRECTION INPUT ;
    USE SIGNAL ;
    PORT
      LAYER M5 ;
        RECT  122.988 215.808 123.012 216 ;
    END
  END g_front_0_u_front__row_in[207]
  PIN g_front_0_u_front__row_in[208]
    DIRECTION INPUT ;
    USE SIGNAL ;
    PORT
      LAYER M5 ;
        RECT  123.18 215.808 123.204 216 ;
    END
  END g_front_0_u_front__row_in[208]
  PIN g_front_0_u_front__row_in[209]
    DIRECTION INPUT ;
    USE SIGNAL ;
    PORT
      LAYER M5 ;
        RECT  123.324 215.808 123.348 216 ;
    END
  END g_front_0_u_front__row_in[209]
  PIN g_front_0_u_front__row_in[20]
    DIRECTION INPUT ;
    USE SIGNAL ;
    PORT
      LAYER M5 ;
        RECT  93.276 215.808 93.3 216 ;
    END
  END g_front_0_u_front__row_in[20]
  PIN g_front_0_u_front__row_in[210]
    DIRECTION INPUT ;
    USE SIGNAL ;
    PORT
      LAYER M5 ;
        RECT  123.468 215.808 123.492 216 ;
    END
  END g_front_0_u_front__row_in[210]
  PIN g_front_0_u_front__row_in[211]
    DIRECTION INPUT ;
    USE SIGNAL ;
    PORT
      LAYER M5 ;
        RECT  123.66 215.808 123.684 216 ;
    END
  END g_front_0_u_front__row_in[211]
  PIN g_front_0_u_front__row_in[212]
    DIRECTION INPUT ;
    USE SIGNAL ;
    PORT
      LAYER M5 ;
        RECT  123.804 215.808 123.828 216 ;
    END
  END g_front_0_u_front__row_in[212]
  PIN g_front_0_u_front__row_in[213]
    DIRECTION INPUT ;
    USE SIGNAL ;
    PORT
      LAYER M5 ;
        RECT  123.948 215.808 123.972 216 ;
    END
  END g_front_0_u_front__row_in[213]
  PIN g_front_0_u_front__row_in[214]
    DIRECTION INPUT ;
    USE SIGNAL ;
    PORT
      LAYER M5 ;
        RECT  124.14 215.808 124.164 216 ;
    END
  END g_front_0_u_front__row_in[214]
  PIN g_front_0_u_front__row_in[215]
    DIRECTION INPUT ;
    USE SIGNAL ;
    PORT
      LAYER M5 ;
        RECT  124.284 215.808 124.308 216 ;
    END
  END g_front_0_u_front__row_in[215]
  PIN g_front_0_u_front__row_in[216]
    DIRECTION INPUT ;
    USE SIGNAL ;
    PORT
      LAYER M5 ;
        RECT  124.428 215.808 124.452 216 ;
    END
  END g_front_0_u_front__row_in[216]
  PIN g_front_0_u_front__row_in[217]
    DIRECTION INPUT ;
    USE SIGNAL ;
    PORT
      LAYER M5 ;
        RECT  124.572 215.808 124.596 216 ;
    END
  END g_front_0_u_front__row_in[217]
  PIN g_front_0_u_front__row_in[218]
    DIRECTION INPUT ;
    USE SIGNAL ;
    PORT
      LAYER M5 ;
        RECT  124.764 215.808 124.788 216 ;
    END
  END g_front_0_u_front__row_in[218]
  PIN g_front_0_u_front__row_in[219]
    DIRECTION INPUT ;
    USE SIGNAL ;
    PORT
      LAYER M5 ;
        RECT  124.908 215.808 124.932 216 ;
    END
  END g_front_0_u_front__row_in[219]
  PIN g_front_0_u_front__row_in[21]
    DIRECTION INPUT ;
    USE SIGNAL ;
    PORT
      LAYER M5 ;
        RECT  93.468 215.808 93.492 216 ;
    END
  END g_front_0_u_front__row_in[21]
  PIN g_front_0_u_front__row_in[220]
    DIRECTION INPUT ;
    USE SIGNAL ;
    PORT
      LAYER M5 ;
        RECT  125.052 215.808 125.076 216 ;
    END
  END g_front_0_u_front__row_in[220]
  PIN g_front_0_u_front__row_in[221]
    DIRECTION INPUT ;
    USE SIGNAL ;
    PORT
      LAYER M5 ;
        RECT  125.244 215.808 125.268 216 ;
    END
  END g_front_0_u_front__row_in[221]
  PIN g_front_0_u_front__row_in[222]
    DIRECTION INPUT ;
    USE SIGNAL ;
    PORT
      LAYER M5 ;
        RECT  125.388 215.808 125.412 216 ;
    END
  END g_front_0_u_front__row_in[222]
  PIN g_front_0_u_front__row_in[223]
    DIRECTION INPUT ;
    USE SIGNAL ;
    PORT
      LAYER M5 ;
        RECT  125.532 215.808 125.556 216 ;
    END
  END g_front_0_u_front__row_in[223]
  PIN g_front_0_u_front__row_in[224]
    DIRECTION INPUT ;
    USE SIGNAL ;
    PORT
      LAYER M5 ;
        RECT  125.724 215.808 125.748 216 ;
    END
  END g_front_0_u_front__row_in[224]
  PIN g_front_0_u_front__row_in[225]
    DIRECTION INPUT ;
    USE SIGNAL ;
    PORT
      LAYER M5 ;
        RECT  125.868 215.808 125.892 216 ;
    END
  END g_front_0_u_front__row_in[225]
  PIN g_front_0_u_front__row_in[226]
    DIRECTION INPUT ;
    USE SIGNAL ;
    PORT
      LAYER M5 ;
        RECT  126.012 215.808 126.036 216 ;
    END
  END g_front_0_u_front__row_in[226]
  PIN g_front_0_u_front__row_in[227]
    DIRECTION INPUT ;
    USE SIGNAL ;
    PORT
      LAYER M5 ;
        RECT  126.204 215.808 126.228 216 ;
    END
  END g_front_0_u_front__row_in[227]
  PIN g_front_0_u_front__row_in[228]
    DIRECTION INPUT ;
    USE SIGNAL ;
    PORT
      LAYER M5 ;
        RECT  126.348 215.808 126.372 216 ;
    END
  END g_front_0_u_front__row_in[228]
  PIN g_front_0_u_front__row_in[229]
    DIRECTION INPUT ;
    USE SIGNAL ;
    PORT
      LAYER M5 ;
        RECT  126.492 215.808 126.516 216 ;
    END
  END g_front_0_u_front__row_in[229]
  PIN g_front_0_u_front__row_in[22]
    DIRECTION INPUT ;
    USE SIGNAL ;
    PORT
      LAYER M5 ;
        RECT  93.612 215.808 93.636 216 ;
    END
  END g_front_0_u_front__row_in[22]
  PIN g_front_0_u_front__row_in[230]
    DIRECTION INPUT ;
    USE SIGNAL ;
    PORT
      LAYER M5 ;
        RECT  126.684 215.808 126.708 216 ;
    END
  END g_front_0_u_front__row_in[230]
  PIN g_front_0_u_front__row_in[231]
    DIRECTION INPUT ;
    USE SIGNAL ;
    PORT
      LAYER M5 ;
        RECT  126.828 215.808 126.852 216 ;
    END
  END g_front_0_u_front__row_in[231]
  PIN g_front_0_u_front__row_in[232]
    DIRECTION INPUT ;
    USE SIGNAL ;
    PORT
      LAYER M5 ;
        RECT  126.972 215.808 126.996 216 ;
    END
  END g_front_0_u_front__row_in[232]
  PIN g_front_0_u_front__row_in[233]
    DIRECTION INPUT ;
    USE SIGNAL ;
    PORT
      LAYER M5 ;
        RECT  127.116 215.808 127.14 216 ;
    END
  END g_front_0_u_front__row_in[233]
  PIN g_front_0_u_front__row_in[234]
    DIRECTION INPUT ;
    USE SIGNAL ;
    PORT
      LAYER M5 ;
        RECT  127.308 215.808 127.332 216 ;
    END
  END g_front_0_u_front__row_in[234]
  PIN g_front_0_u_front__row_in[235]
    DIRECTION INPUT ;
    USE SIGNAL ;
    PORT
      LAYER M5 ;
        RECT  127.452 215.808 127.476 216 ;
    END
  END g_front_0_u_front__row_in[235]
  PIN g_front_0_u_front__row_in[236]
    DIRECTION INPUT ;
    USE SIGNAL ;
    PORT
      LAYER M5 ;
        RECT  127.596 215.808 127.62 216 ;
    END
  END g_front_0_u_front__row_in[236]
  PIN g_front_0_u_front__row_in[237]
    DIRECTION INPUT ;
    USE SIGNAL ;
    PORT
      LAYER M5 ;
        RECT  127.788 215.808 127.812 216 ;
    END
  END g_front_0_u_front__row_in[237]
  PIN g_front_0_u_front__row_in[238]
    DIRECTION INPUT ;
    USE SIGNAL ;
    PORT
      LAYER M5 ;
        RECT  127.932 215.808 127.956 216 ;
    END
  END g_front_0_u_front__row_in[238]
  PIN g_front_0_u_front__row_in[239]
    DIRECTION INPUT ;
    USE SIGNAL ;
    PORT
      LAYER M5 ;
        RECT  128.076 215.808 128.1 216 ;
    END
  END g_front_0_u_front__row_in[239]
  PIN g_front_0_u_front__row_in[23]
    DIRECTION INPUT ;
    USE SIGNAL ;
    PORT
      LAYER M5 ;
        RECT  93.756 215.808 93.78 216 ;
    END
  END g_front_0_u_front__row_in[23]
  PIN g_front_0_u_front__row_in[240]
    DIRECTION INPUT ;
    USE SIGNAL ;
    PORT
      LAYER M5 ;
        RECT  128.268 215.808 128.292 216 ;
    END
  END g_front_0_u_front__row_in[240]
  PIN g_front_0_u_front__row_in[241]
    DIRECTION INPUT ;
    USE SIGNAL ;
    PORT
      LAYER M5 ;
        RECT  128.412 215.808 128.436 216 ;
    END
  END g_front_0_u_front__row_in[241]
  PIN g_front_0_u_front__row_in[242]
    DIRECTION INPUT ;
    USE SIGNAL ;
    PORT
      LAYER M5 ;
        RECT  128.556 215.808 128.58 216 ;
    END
  END g_front_0_u_front__row_in[242]
  PIN g_front_0_u_front__row_in[243]
    DIRECTION INPUT ;
    USE SIGNAL ;
    PORT
      LAYER M5 ;
        RECT  128.748 215.808 128.772 216 ;
    END
  END g_front_0_u_front__row_in[243]
  PIN g_front_0_u_front__row_in[244]
    DIRECTION INPUT ;
    USE SIGNAL ;
    PORT
      LAYER M5 ;
        RECT  128.892 215.808 128.916 216 ;
    END
  END g_front_0_u_front__row_in[244]
  PIN g_front_0_u_front__row_in[245]
    DIRECTION INPUT ;
    USE SIGNAL ;
    PORT
      LAYER M5 ;
        RECT  129.036 215.808 129.06 216 ;
    END
  END g_front_0_u_front__row_in[245]
  PIN g_front_0_u_front__row_in[246]
    DIRECTION INPUT ;
    USE SIGNAL ;
    PORT
      LAYER M5 ;
        RECT  129.18 215.808 129.204 216 ;
    END
  END g_front_0_u_front__row_in[246]
  PIN g_front_0_u_front__row_in[247]
    DIRECTION INPUT ;
    USE SIGNAL ;
    PORT
      LAYER M5 ;
        RECT  129.372 215.808 129.396 216 ;
    END
  END g_front_0_u_front__row_in[247]
  PIN g_front_0_u_front__row_in[248]
    DIRECTION INPUT ;
    USE SIGNAL ;
    PORT
      LAYER M5 ;
        RECT  129.516 215.808 129.54 216 ;
    END
  END g_front_0_u_front__row_in[248]
  PIN g_front_0_u_front__row_in[249]
    DIRECTION INPUT ;
    USE SIGNAL ;
    PORT
      LAYER M5 ;
        RECT  129.66 215.808 129.684 216 ;
    END
  END g_front_0_u_front__row_in[249]
  PIN g_front_0_u_front__row_in[24]
    DIRECTION INPUT ;
    USE SIGNAL ;
    PORT
      LAYER M5 ;
        RECT  93.9 215.808 93.924 216 ;
    END
  END g_front_0_u_front__row_in[24]
  PIN g_front_0_u_front__row_in[250]
    DIRECTION INPUT ;
    USE SIGNAL ;
    PORT
      LAYER M5 ;
        RECT  129.852 215.808 129.876 216 ;
    END
  END g_front_0_u_front__row_in[250]
  PIN g_front_0_u_front__row_in[251]
    DIRECTION INPUT ;
    USE SIGNAL ;
    PORT
      LAYER M5 ;
        RECT  129.996 215.808 130.02 216 ;
    END
  END g_front_0_u_front__row_in[251]
  PIN g_front_0_u_front__row_in[252]
    DIRECTION INPUT ;
    USE SIGNAL ;
    PORT
      LAYER M5 ;
        RECT  130.14 215.808 130.164 216 ;
    END
  END g_front_0_u_front__row_in[252]
  PIN g_front_0_u_front__row_in[253]
    DIRECTION INPUT ;
    USE SIGNAL ;
    PORT
      LAYER M5 ;
        RECT  130.332 215.808 130.356 216 ;
    END
  END g_front_0_u_front__row_in[253]
  PIN g_front_0_u_front__row_in[254]
    DIRECTION INPUT ;
    USE SIGNAL ;
    PORT
      LAYER M5 ;
        RECT  130.476 215.808 130.5 216 ;
    END
  END g_front_0_u_front__row_in[254]
  PIN g_front_0_u_front__row_in[255]
    DIRECTION INPUT ;
    USE SIGNAL ;
    PORT
      LAYER M5 ;
        RECT  130.62 215.808 130.644 216 ;
    END
  END g_front_0_u_front__row_in[255]
  PIN g_front_0_u_front__row_in[25]
    DIRECTION INPUT ;
    USE SIGNAL ;
    PORT
      LAYER M5 ;
        RECT  94.092 215.808 94.116 216 ;
    END
  END g_front_0_u_front__row_in[25]
  PIN g_front_0_u_front__row_in[26]
    DIRECTION INPUT ;
    USE SIGNAL ;
    PORT
      LAYER M5 ;
        RECT  94.236 215.808 94.26 216 ;
    END
  END g_front_0_u_front__row_in[26]
  PIN g_front_0_u_front__row_in[27]
    DIRECTION INPUT ;
    USE SIGNAL ;
    PORT
      LAYER M5 ;
        RECT  94.38 215.808 94.404 216 ;
    END
  END g_front_0_u_front__row_in[27]
  PIN g_front_0_u_front__row_in[28]
    DIRECTION INPUT ;
    USE SIGNAL ;
    PORT
      LAYER M5 ;
        RECT  94.572 215.808 94.596 216 ;
    END
  END g_front_0_u_front__row_in[28]
  PIN g_front_0_u_front__row_in[29]
    DIRECTION INPUT ;
    USE SIGNAL ;
    PORT
      LAYER M5 ;
        RECT  94.716 215.808 94.74 216 ;
    END
  END g_front_0_u_front__row_in[29]
  PIN g_front_0_u_front__row_in[2]
    DIRECTION INPUT ;
    USE SIGNAL ;
    PORT
      LAYER M5 ;
        RECT  90.444 215.808 90.468 216 ;
    END
  END g_front_0_u_front__row_in[2]
  PIN g_front_0_u_front__row_in[30]
    DIRECTION INPUT ;
    USE SIGNAL ;
    PORT
      LAYER M5 ;
        RECT  94.86 215.808 94.884 216 ;
    END
  END g_front_0_u_front__row_in[30]
  PIN g_front_0_u_front__row_in[31]
    DIRECTION INPUT ;
    USE SIGNAL ;
    PORT
      LAYER M5 ;
        RECT  95.052 215.808 95.076 216 ;
    END
  END g_front_0_u_front__row_in[31]
  PIN g_front_0_u_front__row_in[32]
    DIRECTION INPUT ;
    USE SIGNAL ;
    PORT
      LAYER M5 ;
        RECT  95.196 215.808 95.22 216 ;
    END
  END g_front_0_u_front__row_in[32]
  PIN g_front_0_u_front__row_in[33]
    DIRECTION INPUT ;
    USE SIGNAL ;
    PORT
      LAYER M5 ;
        RECT  95.34 215.808 95.364 216 ;
    END
  END g_front_0_u_front__row_in[33]
  PIN g_front_0_u_front__row_in[34]
    DIRECTION INPUT ;
    USE SIGNAL ;
    PORT
      LAYER M5 ;
        RECT  95.532 215.808 95.556 216 ;
    END
  END g_front_0_u_front__row_in[34]
  PIN g_front_0_u_front__row_in[35]
    DIRECTION INPUT ;
    USE SIGNAL ;
    PORT
      LAYER M5 ;
        RECT  95.676 215.808 95.7 216 ;
    END
  END g_front_0_u_front__row_in[35]
  PIN g_front_0_u_front__row_in[36]
    DIRECTION INPUT ;
    USE SIGNAL ;
    PORT
      LAYER M5 ;
        RECT  95.82 215.808 95.844 216 ;
    END
  END g_front_0_u_front__row_in[36]
  PIN g_front_0_u_front__row_in[37]
    DIRECTION INPUT ;
    USE SIGNAL ;
    PORT
      LAYER M5 ;
        RECT  96.012 215.808 96.036 216 ;
    END
  END g_front_0_u_front__row_in[37]
  PIN g_front_0_u_front__row_in[38]
    DIRECTION INPUT ;
    USE SIGNAL ;
    PORT
      LAYER M5 ;
        RECT  96.156 215.808 96.18 216 ;
    END
  END g_front_0_u_front__row_in[38]
  PIN g_front_0_u_front__row_in[39]
    DIRECTION INPUT ;
    USE SIGNAL ;
    PORT
      LAYER M5 ;
        RECT  96.3 215.808 96.324 216 ;
    END
  END g_front_0_u_front__row_in[39]
  PIN g_front_0_u_front__row_in[3]
    DIRECTION INPUT ;
    USE SIGNAL ;
    PORT
      LAYER M5 ;
        RECT  90.588 215.808 90.612 216 ;
    END
  END g_front_0_u_front__row_in[3]
  PIN g_front_0_u_front__row_in[40]
    DIRECTION INPUT ;
    USE SIGNAL ;
    PORT
      LAYER M5 ;
        RECT  96.444 215.808 96.468 216 ;
    END
  END g_front_0_u_front__row_in[40]
  PIN g_front_0_u_front__row_in[41]
    DIRECTION INPUT ;
    USE SIGNAL ;
    PORT
      LAYER M5 ;
        RECT  96.636 215.808 96.66 216 ;
    END
  END g_front_0_u_front__row_in[41]
  PIN g_front_0_u_front__row_in[42]
    DIRECTION INPUT ;
    USE SIGNAL ;
    PORT
      LAYER M5 ;
        RECT  96.78 215.808 96.804 216 ;
    END
  END g_front_0_u_front__row_in[42]
  PIN g_front_0_u_front__row_in[43]
    DIRECTION INPUT ;
    USE SIGNAL ;
    PORT
      LAYER M5 ;
        RECT  96.924 215.808 96.948 216 ;
    END
  END g_front_0_u_front__row_in[43]
  PIN g_front_0_u_front__row_in[44]
    DIRECTION INPUT ;
    USE SIGNAL ;
    PORT
      LAYER M5 ;
        RECT  97.116 215.808 97.14 216 ;
    END
  END g_front_0_u_front__row_in[44]
  PIN g_front_0_u_front__row_in[45]
    DIRECTION INPUT ;
    USE SIGNAL ;
    PORT
      LAYER M5 ;
        RECT  97.26 215.808 97.284 216 ;
    END
  END g_front_0_u_front__row_in[45]
  PIN g_front_0_u_front__row_in[46]
    DIRECTION INPUT ;
    USE SIGNAL ;
    PORT
      LAYER M5 ;
        RECT  97.404 215.808 97.428 216 ;
    END
  END g_front_0_u_front__row_in[46]
  PIN g_front_0_u_front__row_in[47]
    DIRECTION INPUT ;
    USE SIGNAL ;
    PORT
      LAYER M5 ;
        RECT  97.596 215.808 97.62 216 ;
    END
  END g_front_0_u_front__row_in[47]
  PIN g_front_0_u_front__row_in[48]
    DIRECTION INPUT ;
    USE SIGNAL ;
    PORT
      LAYER M5 ;
        RECT  97.74 215.808 97.764 216 ;
    END
  END g_front_0_u_front__row_in[48]
  PIN g_front_0_u_front__row_in[49]
    DIRECTION INPUT ;
    USE SIGNAL ;
    PORT
      LAYER M5 ;
        RECT  97.884 215.808 97.908 216 ;
    END
  END g_front_0_u_front__row_in[49]
  PIN g_front_0_u_front__row_in[4]
    DIRECTION INPUT ;
    USE SIGNAL ;
    PORT
      LAYER M5 ;
        RECT  90.732 215.808 90.756 216 ;
    END
  END g_front_0_u_front__row_in[4]
  PIN g_front_0_u_front__row_in[50]
    DIRECTION INPUT ;
    USE SIGNAL ;
    PORT
      LAYER M5 ;
        RECT  98.076 215.808 98.1 216 ;
    END
  END g_front_0_u_front__row_in[50]
  PIN g_front_0_u_front__row_in[51]
    DIRECTION INPUT ;
    USE SIGNAL ;
    PORT
      LAYER M5 ;
        RECT  98.22 215.808 98.244 216 ;
    END
  END g_front_0_u_front__row_in[51]
  PIN g_front_0_u_front__row_in[52]
    DIRECTION INPUT ;
    USE SIGNAL ;
    PORT
      LAYER M5 ;
        RECT  98.364 215.808 98.388 216 ;
    END
  END g_front_0_u_front__row_in[52]
  PIN g_front_0_u_front__row_in[53]
    DIRECTION INPUT ;
    USE SIGNAL ;
    PORT
      LAYER M5 ;
        RECT  98.556 215.808 98.58 216 ;
    END
  END g_front_0_u_front__row_in[53]
  PIN g_front_0_u_front__row_in[54]
    DIRECTION INPUT ;
    USE SIGNAL ;
    PORT
      LAYER M5 ;
        RECT  98.7 215.808 98.724 216 ;
    END
  END g_front_0_u_front__row_in[54]
  PIN g_front_0_u_front__row_in[55]
    DIRECTION INPUT ;
    USE SIGNAL ;
    PORT
      LAYER M5 ;
        RECT  98.844 215.808 98.868 216 ;
    END
  END g_front_0_u_front__row_in[55]
  PIN g_front_0_u_front__row_in[56]
    DIRECTION INPUT ;
    USE SIGNAL ;
    PORT
      LAYER M5 ;
        RECT  98.988 215.808 99.012 216 ;
    END
  END g_front_0_u_front__row_in[56]
  PIN g_front_0_u_front__row_in[57]
    DIRECTION INPUT ;
    USE SIGNAL ;
    PORT
      LAYER M5 ;
        RECT  99.18 215.808 99.204 216 ;
    END
  END g_front_0_u_front__row_in[57]
  PIN g_front_0_u_front__row_in[58]
    DIRECTION INPUT ;
    USE SIGNAL ;
    PORT
      LAYER M5 ;
        RECT  99.324 215.808 99.348 216 ;
    END
  END g_front_0_u_front__row_in[58]
  PIN g_front_0_u_front__row_in[59]
    DIRECTION INPUT ;
    USE SIGNAL ;
    PORT
      LAYER M5 ;
        RECT  99.468 215.808 99.492 216 ;
    END
  END g_front_0_u_front__row_in[59]
  PIN g_front_0_u_front__row_in[5]
    DIRECTION INPUT ;
    USE SIGNAL ;
    PORT
      LAYER M5 ;
        RECT  90.924 215.808 90.948 216 ;
    END
  END g_front_0_u_front__row_in[5]
  PIN g_front_0_u_front__row_in[60]
    DIRECTION INPUT ;
    USE SIGNAL ;
    PORT
      LAYER M5 ;
        RECT  99.66 215.808 99.684 216 ;
    END
  END g_front_0_u_front__row_in[60]
  PIN g_front_0_u_front__row_in[61]
    DIRECTION INPUT ;
    USE SIGNAL ;
    PORT
      LAYER M5 ;
        RECT  99.804 215.808 99.828 216 ;
    END
  END g_front_0_u_front__row_in[61]
  PIN g_front_0_u_front__row_in[62]
    DIRECTION INPUT ;
    USE SIGNAL ;
    PORT
      LAYER M5 ;
        RECT  99.948 215.808 99.972 216 ;
    END
  END g_front_0_u_front__row_in[62]
  PIN g_front_0_u_front__row_in[63]
    DIRECTION INPUT ;
    USE SIGNAL ;
    PORT
      LAYER M5 ;
        RECT  100.14 215.808 100.164 216 ;
    END
  END g_front_0_u_front__row_in[63]
  PIN g_front_0_u_front__row_in[64]
    DIRECTION INPUT ;
    USE SIGNAL ;
    PORT
      LAYER M5 ;
        RECT  100.284 215.808 100.308 216 ;
    END
  END g_front_0_u_front__row_in[64]
  PIN g_front_0_u_front__row_in[65]
    DIRECTION INPUT ;
    USE SIGNAL ;
    PORT
      LAYER M5 ;
        RECT  100.428 215.808 100.452 216 ;
    END
  END g_front_0_u_front__row_in[65]
  PIN g_front_0_u_front__row_in[66]
    DIRECTION INPUT ;
    USE SIGNAL ;
    PORT
      LAYER M5 ;
        RECT  100.62 215.808 100.644 216 ;
    END
  END g_front_0_u_front__row_in[66]
  PIN g_front_0_u_front__row_in[67]
    DIRECTION INPUT ;
    USE SIGNAL ;
    PORT
      LAYER M5 ;
        RECT  100.764 215.808 100.788 216 ;
    END
  END g_front_0_u_front__row_in[67]
  PIN g_front_0_u_front__row_in[68]
    DIRECTION INPUT ;
    USE SIGNAL ;
    PORT
      LAYER M5 ;
        RECT  100.908 215.808 100.932 216 ;
    END
  END g_front_0_u_front__row_in[68]
  PIN g_front_0_u_front__row_in[69]
    DIRECTION INPUT ;
    USE SIGNAL ;
    PORT
      LAYER M5 ;
        RECT  101.052 215.808 101.076 216 ;
    END
  END g_front_0_u_front__row_in[69]
  PIN g_front_0_u_front__row_in[6]
    DIRECTION INPUT ;
    USE SIGNAL ;
    PORT
      LAYER M5 ;
        RECT  91.068 215.808 91.092 216 ;
    END
  END g_front_0_u_front__row_in[6]
  PIN g_front_0_u_front__row_in[70]
    DIRECTION INPUT ;
    USE SIGNAL ;
    PORT
      LAYER M5 ;
        RECT  101.244 215.808 101.268 216 ;
    END
  END g_front_0_u_front__row_in[70]
  PIN g_front_0_u_front__row_in[71]
    DIRECTION INPUT ;
    USE SIGNAL ;
    PORT
      LAYER M5 ;
        RECT  101.388 215.808 101.412 216 ;
    END
  END g_front_0_u_front__row_in[71]
  PIN g_front_0_u_front__row_in[72]
    DIRECTION INPUT ;
    USE SIGNAL ;
    PORT
      LAYER M5 ;
        RECT  101.532 215.808 101.556 216 ;
    END
  END g_front_0_u_front__row_in[72]
  PIN g_front_0_u_front__row_in[73]
    DIRECTION INPUT ;
    USE SIGNAL ;
    PORT
      LAYER M5 ;
        RECT  101.724 215.808 101.748 216 ;
    END
  END g_front_0_u_front__row_in[73]
  PIN g_front_0_u_front__row_in[74]
    DIRECTION INPUT ;
    USE SIGNAL ;
    PORT
      LAYER M5 ;
        RECT  101.868 215.808 101.892 216 ;
    END
  END g_front_0_u_front__row_in[74]
  PIN g_front_0_u_front__row_in[75]
    DIRECTION INPUT ;
    USE SIGNAL ;
    PORT
      LAYER M5 ;
        RECT  102.012 215.808 102.036 216 ;
    END
  END g_front_0_u_front__row_in[75]
  PIN g_front_0_u_front__row_in[76]
    DIRECTION INPUT ;
    USE SIGNAL ;
    PORT
      LAYER M5 ;
        RECT  102.204 215.808 102.228 216 ;
    END
  END g_front_0_u_front__row_in[76]
  PIN g_front_0_u_front__row_in[77]
    DIRECTION INPUT ;
    USE SIGNAL ;
    PORT
      LAYER M5 ;
        RECT  102.348 215.808 102.372 216 ;
    END
  END g_front_0_u_front__row_in[77]
  PIN g_front_0_u_front__row_in[78]
    DIRECTION INPUT ;
    USE SIGNAL ;
    PORT
      LAYER M5 ;
        RECT  102.492 215.808 102.516 216 ;
    END
  END g_front_0_u_front__row_in[78]
  PIN g_front_0_u_front__row_in[79]
    DIRECTION INPUT ;
    USE SIGNAL ;
    PORT
      LAYER M5 ;
        RECT  102.684 215.808 102.708 216 ;
    END
  END g_front_0_u_front__row_in[79]
  PIN g_front_0_u_front__row_in[7]
    DIRECTION INPUT ;
    USE SIGNAL ;
    PORT
      LAYER M5 ;
        RECT  91.212 215.808 91.236 216 ;
    END
  END g_front_0_u_front__row_in[7]
  PIN g_front_0_u_front__row_in[80]
    DIRECTION INPUT ;
    USE SIGNAL ;
    PORT
      LAYER M5 ;
        RECT  102.828 215.808 102.852 216 ;
    END
  END g_front_0_u_front__row_in[80]
  PIN g_front_0_u_front__row_in[81]
    DIRECTION INPUT ;
    USE SIGNAL ;
    PORT
      LAYER M5 ;
        RECT  102.972 215.808 102.996 216 ;
    END
  END g_front_0_u_front__row_in[81]
  PIN g_front_0_u_front__row_in[82]
    DIRECTION INPUT ;
    USE SIGNAL ;
    PORT
      LAYER M5 ;
        RECT  103.164 215.808 103.188 216 ;
    END
  END g_front_0_u_front__row_in[82]
  PIN g_front_0_u_front__row_in[83]
    DIRECTION INPUT ;
    USE SIGNAL ;
    PORT
      LAYER M5 ;
        RECT  103.308 215.808 103.332 216 ;
    END
  END g_front_0_u_front__row_in[83]
  PIN g_front_0_u_front__row_in[84]
    DIRECTION INPUT ;
    USE SIGNAL ;
    PORT
      LAYER M5 ;
        RECT  103.452 215.808 103.476 216 ;
    END
  END g_front_0_u_front__row_in[84]
  PIN g_front_0_u_front__row_in[85]
    DIRECTION INPUT ;
    USE SIGNAL ;
    PORT
      LAYER M5 ;
        RECT  103.596 215.808 103.62 216 ;
    END
  END g_front_0_u_front__row_in[85]
  PIN g_front_0_u_front__row_in[86]
    DIRECTION INPUT ;
    USE SIGNAL ;
    PORT
      LAYER M5 ;
        RECT  103.788 215.808 103.812 216 ;
    END
  END g_front_0_u_front__row_in[86]
  PIN g_front_0_u_front__row_in[87]
    DIRECTION INPUT ;
    USE SIGNAL ;
    PORT
      LAYER M5 ;
        RECT  103.932 215.808 103.956 216 ;
    END
  END g_front_0_u_front__row_in[87]
  PIN g_front_0_u_front__row_in[88]
    DIRECTION INPUT ;
    USE SIGNAL ;
    PORT
      LAYER M5 ;
        RECT  104.076 215.808 104.1 216 ;
    END
  END g_front_0_u_front__row_in[88]
  PIN g_front_0_u_front__row_in[89]
    DIRECTION INPUT ;
    USE SIGNAL ;
    PORT
      LAYER M5 ;
        RECT  104.268 215.808 104.292 216 ;
    END
  END g_front_0_u_front__row_in[89]
  PIN g_front_0_u_front__row_in[8]
    DIRECTION INPUT ;
    USE SIGNAL ;
    PORT
      LAYER M5 ;
        RECT  91.404 215.808 91.428 216 ;
    END
  END g_front_0_u_front__row_in[8]
  PIN g_front_0_u_front__row_in[90]
    DIRECTION INPUT ;
    USE SIGNAL ;
    PORT
      LAYER M5 ;
        RECT  104.412 215.808 104.436 216 ;
    END
  END g_front_0_u_front__row_in[90]
  PIN g_front_0_u_front__row_in[91]
    DIRECTION INPUT ;
    USE SIGNAL ;
    PORT
      LAYER M5 ;
        RECT  104.556 215.808 104.58 216 ;
    END
  END g_front_0_u_front__row_in[91]
  PIN g_front_0_u_front__row_in[92]
    DIRECTION INPUT ;
    USE SIGNAL ;
    PORT
      LAYER M5 ;
        RECT  104.748 215.808 104.772 216 ;
    END
  END g_front_0_u_front__row_in[92]
  PIN g_front_0_u_front__row_in[93]
    DIRECTION INPUT ;
    USE SIGNAL ;
    PORT
      LAYER M5 ;
        RECT  104.892 215.808 104.916 216 ;
    END
  END g_front_0_u_front__row_in[93]
  PIN g_front_0_u_front__row_in[94]
    DIRECTION INPUT ;
    USE SIGNAL ;
    PORT
      LAYER M5 ;
        RECT  105.036 215.808 105.06 216 ;
    END
  END g_front_0_u_front__row_in[94]
  PIN g_front_0_u_front__row_in[95]
    DIRECTION INPUT ;
    USE SIGNAL ;
    PORT
      LAYER M5 ;
        RECT  105.228 215.808 105.252 216 ;
    END
  END g_front_0_u_front__row_in[95]
  PIN g_front_0_u_front__row_in[96]
    DIRECTION INPUT ;
    USE SIGNAL ;
    PORT
      LAYER M5 ;
        RECT  105.372 215.808 105.396 216 ;
    END
  END g_front_0_u_front__row_in[96]
  PIN g_front_0_u_front__row_in[97]
    DIRECTION INPUT ;
    USE SIGNAL ;
    PORT
      LAYER M5 ;
        RECT  105.516 215.808 105.54 216 ;
    END
  END g_front_0_u_front__row_in[97]
  PIN g_front_0_u_front__row_in[98]
    DIRECTION INPUT ;
    USE SIGNAL ;
    PORT
      LAYER M5 ;
        RECT  105.66 215.808 105.684 216 ;
    END
  END g_front_0_u_front__row_in[98]
  PIN g_front_0_u_front__row_in[99]
    DIRECTION INPUT ;
    USE SIGNAL ;
    PORT
      LAYER M5 ;
        RECT  105.852 215.808 105.876 216 ;
    END
  END g_front_0_u_front__row_in[99]
  PIN g_front_0_u_front__row_in[9]
    DIRECTION INPUT ;
    USE SIGNAL ;
    PORT
      LAYER M5 ;
        RECT  91.548 215.808 91.572 216 ;
    END
  END g_front_0_u_front__row_in[9]
  PIN g_front_0_u_front__rst_n[0]
    DIRECTION INPUT ;
    USE SIGNAL ;
    PORT
      LAYER M5 ;
        RECT  130.812 215.808 130.836 216 ;
    END
  END g_front_0_u_front__rst_n[0]
  PIN g_t_0_u_l8__clk[0]
    DIRECTION INPUT ;
    USE SIGNAL ;
    PORT
      LAYER M5 ;
        RECT  130.956 215.808 130.98 216 ;
    END
  END g_t_0_u_l8__clk[0]
  PIN g_t_0_u_stin__clk[0]
    DIRECTION INPUT ;
    USE SIGNAL ;
    PORT
      LAYER M5 ;
        RECT  131.1 215.808 131.124 216 ;
    END
  END g_t_0_u_stin__clk[0]
  PIN g_t_0_u_stin__rst_n[0]
    DIRECTION INPUT ;
    USE SIGNAL ;
    PORT
      LAYER M5 ;
        RECT  131.292 215.808 131.316 216 ;
    END
  END g_t_0_u_stin__rst_n[0]
  PIN g_t_0_u_stk__clk[0]
    DIRECTION INPUT ;
    USE SIGNAL ;
    PORT
      LAYER M5 ;
        RECT  131.436 215.808 131.46 216 ;
    END
  END g_t_0_u_stk__clk[0]
  PIN g_t_0_u_stk__rst_n[0]
    DIRECTION INPUT ;
    USE SIGNAL ;
    PORT
      LAYER M5 ;
        RECT  131.58 215.808 131.604 216 ;
    END
  END g_t_0_u_stk__rst_n[0]
  PIN g_t_1_u_l8__clk[0]
    DIRECTION INPUT ;
    USE SIGNAL ;
    PORT
      LAYER M5 ;
        RECT  131.724 215.808 131.748 216 ;
    END
  END g_t_1_u_l8__clk[0]
  PIN g_t_1_u_stin__clk[0]
    DIRECTION INPUT ;
    USE SIGNAL ;
    PORT
      LAYER M5 ;
        RECT  131.916 215.808 131.94 216 ;
    END
  END g_t_1_u_stin__clk[0]
  PIN g_t_1_u_stin__rst_n[0]
    DIRECTION INPUT ;
    USE SIGNAL ;
    PORT
      LAYER M5 ;
        RECT  132.06 215.808 132.084 216 ;
    END
  END g_t_1_u_stin__rst_n[0]
  PIN g_t_1_u_stk__clk[0]
    DIRECTION INPUT ;
    USE SIGNAL ;
    PORT
      LAYER M5 ;
        RECT  132.204 215.808 132.228 216 ;
    END
  END g_t_1_u_stk__clk[0]
  PIN g_t_1_u_stk__rst_n[0]
    DIRECTION INPUT ;
    USE SIGNAL ;
    PORT
      LAYER M5 ;
        RECT  132.396 215.808 132.42 216 ;
    END
  END g_t_1_u_stk__rst_n[0]
  PIN u_kt__clk[0]
    DIRECTION INPUT ;
    USE SIGNAL ;
    PORT
      LAYER M5 ;
        RECT  132.54 215.808 132.564 216 ;
    END
  END u_kt__clk[0]
  PIN u_kt__g_f[0]
    DIRECTION OUTPUT ;
    USE SIGNAL ;
    PORT
      LAYER M5 ;
        RECT  132.684 215.808 132.708 216 ;
    END
  END u_kt__g_f[0]
  PIN u_kt__gf_in[10]
    DIRECTION INPUT ;
    USE SIGNAL ;
    PORT
      LAYER M5 ;
        RECT  134.124 215.808 134.148 216 ;
    END
  END u_kt__gf_in[10]
  PIN u_kt__gf_in[11]
    DIRECTION INPUT ;
    USE SIGNAL ;
    PORT
      LAYER M5 ;
        RECT  134.268 215.808 134.292 216 ;
    END
  END u_kt__gf_in[11]
  PIN u_kt__gf_in[12]
    DIRECTION INPUT ;
    USE SIGNAL ;
    PORT
      LAYER M5 ;
        RECT  134.46 215.808 134.484 216 ;
    END
  END u_kt__gf_in[12]
  PIN u_kt__gf_in[13]
    DIRECTION INPUT ;
    USE SIGNAL ;
    PORT
      LAYER M5 ;
        RECT  134.604 215.808 134.628 216 ;
    END
  END u_kt__gf_in[13]
  PIN u_kt__gf_in[14]
    DIRECTION INPUT ;
    USE SIGNAL ;
    PORT
      LAYER M5 ;
        RECT  134.748 215.808 134.772 216 ;
    END
  END u_kt__gf_in[14]
  PIN u_kt__gf_in[15]
    DIRECTION INPUT ;
    USE SIGNAL ;
    PORT
      LAYER M5 ;
        RECT  134.94 215.808 134.964 216 ;
    END
  END u_kt__gf_in[15]
  PIN u_kt__gf_in[2]
    DIRECTION INPUT ;
    USE SIGNAL ;
    PORT
      LAYER M5 ;
        RECT  132.876 215.808 132.9 216 ;
    END
  END u_kt__gf_in[2]
  PIN u_kt__gf_in[3]
    DIRECTION INPUT ;
    USE SIGNAL ;
    PORT
      LAYER M5 ;
        RECT  133.02 215.808 133.044 216 ;
    END
  END u_kt__gf_in[3]
  PIN u_kt__gf_in[4]
    DIRECTION INPUT ;
    USE SIGNAL ;
    PORT
      LAYER M5 ;
        RECT  133.164 215.808 133.188 216 ;
    END
  END u_kt__gf_in[4]
  PIN u_kt__gf_in[5]
    DIRECTION INPUT ;
    USE SIGNAL ;
    PORT
      LAYER M5 ;
        RECT  133.356 215.808 133.38 216 ;
    END
  END u_kt__gf_in[5]
  PIN u_kt__gf_in[6]
    DIRECTION INPUT ;
    USE SIGNAL ;
    PORT
      LAYER M5 ;
        RECT  133.5 215.808 133.524 216 ;
    END
  END u_kt__gf_in[6]
  PIN u_kt__gf_in[7]
    DIRECTION INPUT ;
    USE SIGNAL ;
    PORT
      LAYER M5 ;
        RECT  133.644 215.808 133.668 216 ;
    END
  END u_kt__gf_in[7]
  PIN u_kt__gf_in[8]
    DIRECTION INPUT ;
    USE SIGNAL ;
    PORT
      LAYER M5 ;
        RECT  133.836 215.808 133.86 216 ;
    END
  END u_kt__gf_in[8]
  PIN u_kt__gf_in[9]
    DIRECTION INPUT ;
    USE SIGNAL ;
    PORT
      LAYER M5 ;
        RECT  133.98 215.808 134.004 216 ;
    END
  END u_kt__gf_in[9]
  PIN u_kt__kp_in[100]
    DIRECTION INPUT ;
    USE SIGNAL ;
    PORT
      LAYER M5 ;
        RECT  140.796 215.808 140.82 216 ;
    END
  END u_kt__kp_in[100]
  PIN u_kt__kp_in[101]
    DIRECTION INPUT ;
    USE SIGNAL ;
    PORT
      LAYER M5 ;
        RECT  140.94 215.808 140.964 216 ;
    END
  END u_kt__kp_in[101]
  PIN u_kt__kp_in[102]
    DIRECTION INPUT ;
    USE SIGNAL ;
    PORT
      LAYER M5 ;
        RECT  141.132 215.808 141.156 216 ;
    END
  END u_kt__kp_in[102]
  PIN u_kt__kp_in[103]
    DIRECTION INPUT ;
    USE SIGNAL ;
    PORT
      LAYER M5 ;
        RECT  141.276 215.808 141.3 216 ;
    END
  END u_kt__kp_in[103]
  PIN u_kt__kp_in[104]
    DIRECTION INPUT ;
    USE SIGNAL ;
    PORT
      LAYER M5 ;
        RECT  141.42 215.808 141.444 216 ;
    END
  END u_kt__kp_in[104]
  PIN u_kt__kp_in[105]
    DIRECTION INPUT ;
    USE SIGNAL ;
    PORT
      LAYER M5 ;
        RECT  141.612 215.808 141.636 216 ;
    END
  END u_kt__kp_in[105]
  PIN u_kt__kp_in[106]
    DIRECTION INPUT ;
    USE SIGNAL ;
    PORT
      LAYER M5 ;
        RECT  141.756 215.808 141.78 216 ;
    END
  END u_kt__kp_in[106]
  PIN u_kt__kp_in[107]
    DIRECTION INPUT ;
    USE SIGNAL ;
    PORT
      LAYER M5 ;
        RECT  141.9 215.808 141.924 216 ;
    END
  END u_kt__kp_in[107]
  PIN u_kt__kp_in[108]
    DIRECTION INPUT ;
    USE SIGNAL ;
    PORT
      LAYER M5 ;
        RECT  142.092 215.808 142.116 216 ;
    END
  END u_kt__kp_in[108]
  PIN u_kt__kp_in[109]
    DIRECTION INPUT ;
    USE SIGNAL ;
    PORT
      LAYER M5 ;
        RECT  142.236 215.808 142.26 216 ;
    END
  END u_kt__kp_in[109]
  PIN u_kt__kp_in[110]
    DIRECTION INPUT ;
    USE SIGNAL ;
    PORT
      LAYER M5 ;
        RECT  142.38 215.808 142.404 216 ;
    END
  END u_kt__kp_in[110]
  PIN u_kt__kp_in[111]
    DIRECTION INPUT ;
    USE SIGNAL ;
    PORT
      LAYER M5 ;
        RECT  142.572 215.808 142.596 216 ;
    END
  END u_kt__kp_in[111]
  PIN u_kt__kp_in[112]
    DIRECTION INPUT ;
    USE SIGNAL ;
    PORT
      LAYER M5 ;
        RECT  142.716 215.808 142.74 216 ;
    END
  END u_kt__kp_in[112]
  PIN u_kt__kp_in[113]
    DIRECTION INPUT ;
    USE SIGNAL ;
    PORT
      LAYER M5 ;
        RECT  142.86 215.808 142.884 216 ;
    END
  END u_kt__kp_in[113]
  PIN u_kt__kp_in[114]
    DIRECTION INPUT ;
    USE SIGNAL ;
    PORT
      LAYER M5 ;
        RECT  143.052 215.808 143.076 216 ;
    END
  END u_kt__kp_in[114]
  PIN u_kt__kp_in[115]
    DIRECTION INPUT ;
    USE SIGNAL ;
    PORT
      LAYER M5 ;
        RECT  143.196 215.808 143.22 216 ;
    END
  END u_kt__kp_in[115]
  PIN u_kt__kp_in[116]
    DIRECTION INPUT ;
    USE SIGNAL ;
    PORT
      LAYER M5 ;
        RECT  143.34 215.808 143.364 216 ;
    END
  END u_kt__kp_in[116]
  PIN u_kt__kp_in[117]
    DIRECTION INPUT ;
    USE SIGNAL ;
    PORT
      LAYER M5 ;
        RECT  143.484 215.808 143.508 216 ;
    END
  END u_kt__kp_in[117]
  PIN u_kt__kp_in[118]
    DIRECTION INPUT ;
    USE SIGNAL ;
    PORT
      LAYER M5 ;
        RECT  143.676 215.808 143.7 216 ;
    END
  END u_kt__kp_in[118]
  PIN u_kt__kp_in[119]
    DIRECTION INPUT ;
    USE SIGNAL ;
    PORT
      LAYER M5 ;
        RECT  143.82 215.808 143.844 216 ;
    END
  END u_kt__kp_in[119]
  PIN u_kt__kp_in[120]
    DIRECTION INPUT ;
    USE SIGNAL ;
    PORT
      LAYER M5 ;
        RECT  143.964 215.808 143.988 216 ;
    END
  END u_kt__kp_in[120]
  PIN u_kt__kp_in[121]
    DIRECTION INPUT ;
    USE SIGNAL ;
    PORT
      LAYER M5 ;
        RECT  144.156 215.808 144.18 216 ;
    END
  END u_kt__kp_in[121]
  PIN u_kt__kp_in[122]
    DIRECTION INPUT ;
    USE SIGNAL ;
    PORT
      LAYER M5 ;
        RECT  144.3 215.808 144.324 216 ;
    END
  END u_kt__kp_in[122]
  PIN u_kt__kp_in[123]
    DIRECTION INPUT ;
    USE SIGNAL ;
    PORT
      LAYER M5 ;
        RECT  144.444 215.808 144.468 216 ;
    END
  END u_kt__kp_in[123]
  PIN u_kt__kp_in[124]
    DIRECTION INPUT ;
    USE SIGNAL ;
    PORT
      LAYER M5 ;
        RECT  144.636 215.808 144.66 216 ;
    END
  END u_kt__kp_in[124]
  PIN u_kt__kp_in[125]
    DIRECTION INPUT ;
    USE SIGNAL ;
    PORT
      LAYER M5 ;
        RECT  144.78 215.808 144.804 216 ;
    END
  END u_kt__kp_in[125]
  PIN u_kt__kp_in[126]
    DIRECTION INPUT ;
    USE SIGNAL ;
    PORT
      LAYER M5 ;
        RECT  144.924 215.808 144.948 216 ;
    END
  END u_kt__kp_in[126]
  PIN u_kt__kp_in[127]
    DIRECTION INPUT ;
    USE SIGNAL ;
    PORT
      LAYER M5 ;
        RECT  145.116 215.808 145.14 216 ;
    END
  END u_kt__kp_in[127]
  PIN u_kt__kp_in[128]
    DIRECTION INPUT ;
    USE SIGNAL ;
    PORT
      LAYER M5 ;
        RECT  145.26 215.808 145.284 216 ;
    END
  END u_kt__kp_in[128]
  PIN u_kt__kp_in[129]
    DIRECTION INPUT ;
    USE SIGNAL ;
    PORT
      LAYER M5 ;
        RECT  145.404 215.808 145.428 216 ;
    END
  END u_kt__kp_in[129]
  PIN u_kt__kp_in[130]
    DIRECTION INPUT ;
    USE SIGNAL ;
    PORT
      LAYER M5 ;
        RECT  145.596 215.808 145.62 216 ;
    END
  END u_kt__kp_in[130]
  PIN u_kt__kp_in[131]
    DIRECTION INPUT ;
    USE SIGNAL ;
    PORT
      LAYER M5 ;
        RECT  145.74 215.808 145.764 216 ;
    END
  END u_kt__kp_in[131]
  PIN u_kt__kp_in[132]
    DIRECTION INPUT ;
    USE SIGNAL ;
    PORT
      LAYER M5 ;
        RECT  145.884 215.808 145.908 216 ;
    END
  END u_kt__kp_in[132]
  PIN u_kt__kp_in[133]
    DIRECTION INPUT ;
    USE SIGNAL ;
    PORT
      LAYER M5 ;
        RECT  146.028 215.808 146.052 216 ;
    END
  END u_kt__kp_in[133]
  PIN u_kt__kp_in[134]
    DIRECTION INPUT ;
    USE SIGNAL ;
    PORT
      LAYER M5 ;
        RECT  146.22 215.808 146.244 216 ;
    END
  END u_kt__kp_in[134]
  PIN u_kt__kp_in[135]
    DIRECTION INPUT ;
    USE SIGNAL ;
    PORT
      LAYER M5 ;
        RECT  146.364 215.808 146.388 216 ;
    END
  END u_kt__kp_in[135]
  PIN u_kt__kp_in[136]
    DIRECTION INPUT ;
    USE SIGNAL ;
    PORT
      LAYER M5 ;
        RECT  146.508 215.808 146.532 216 ;
    END
  END u_kt__kp_in[136]
  PIN u_kt__kp_in[137]
    DIRECTION INPUT ;
    USE SIGNAL ;
    PORT
      LAYER M5 ;
        RECT  146.7 215.808 146.724 216 ;
    END
  END u_kt__kp_in[137]
  PIN u_kt__kp_in[138]
    DIRECTION INPUT ;
    USE SIGNAL ;
    PORT
      LAYER M5 ;
        RECT  146.844 215.808 146.868 216 ;
    END
  END u_kt__kp_in[138]
  PIN u_kt__kp_in[139]
    DIRECTION INPUT ;
    USE SIGNAL ;
    PORT
      LAYER M5 ;
        RECT  146.988 215.808 147.012 216 ;
    END
  END u_kt__kp_in[139]
  PIN u_kt__kp_in[140]
    DIRECTION INPUT ;
    USE SIGNAL ;
    PORT
      LAYER M5 ;
        RECT  147.18 215.808 147.204 216 ;
    END
  END u_kt__kp_in[140]
  PIN u_kt__kp_in[141]
    DIRECTION INPUT ;
    USE SIGNAL ;
    PORT
      LAYER M5 ;
        RECT  147.324 215.808 147.348 216 ;
    END
  END u_kt__kp_in[141]
  PIN u_kt__kp_in[142]
    DIRECTION INPUT ;
    USE SIGNAL ;
    PORT
      LAYER M5 ;
        RECT  147.468 215.808 147.492 216 ;
    END
  END u_kt__kp_in[142]
  PIN u_kt__kp_in[143]
    DIRECTION INPUT ;
    USE SIGNAL ;
    PORT
      LAYER M5 ;
        RECT  147.66 215.808 147.684 216 ;
    END
  END u_kt__kp_in[143]
  PIN u_kt__kp_in[144]
    DIRECTION INPUT ;
    USE SIGNAL ;
    PORT
      LAYER M5 ;
        RECT  147.804 215.808 147.828 216 ;
    END
  END u_kt__kp_in[144]
  PIN u_kt__kp_in[145]
    DIRECTION INPUT ;
    USE SIGNAL ;
    PORT
      LAYER M5 ;
        RECT  147.948 215.808 147.972 216 ;
    END
  END u_kt__kp_in[145]
  PIN u_kt__kp_in[146]
    DIRECTION INPUT ;
    USE SIGNAL ;
    PORT
      LAYER M5 ;
        RECT  148.092 215.808 148.116 216 ;
    END
  END u_kt__kp_in[146]
  PIN u_kt__kp_in[147]
    DIRECTION INPUT ;
    USE SIGNAL ;
    PORT
      LAYER M5 ;
        RECT  148.284 215.808 148.308 216 ;
    END
  END u_kt__kp_in[147]
  PIN u_kt__kp_in[148]
    DIRECTION INPUT ;
    USE SIGNAL ;
    PORT
      LAYER M5 ;
        RECT  148.428 215.808 148.452 216 ;
    END
  END u_kt__kp_in[148]
  PIN u_kt__kp_in[149]
    DIRECTION INPUT ;
    USE SIGNAL ;
    PORT
      LAYER M5 ;
        RECT  148.572 215.808 148.596 216 ;
    END
  END u_kt__kp_in[149]
  PIN u_kt__kp_in[150]
    DIRECTION INPUT ;
    USE SIGNAL ;
    PORT
      LAYER M5 ;
        RECT  148.764 215.808 148.788 216 ;
    END
  END u_kt__kp_in[150]
  PIN u_kt__kp_in[151]
    DIRECTION INPUT ;
    USE SIGNAL ;
    PORT
      LAYER M5 ;
        RECT  148.908 215.808 148.932 216 ;
    END
  END u_kt__kp_in[151]
  PIN u_kt__kp_in[152]
    DIRECTION INPUT ;
    USE SIGNAL ;
    PORT
      LAYER M5 ;
        RECT  149.052 215.808 149.076 216 ;
    END
  END u_kt__kp_in[152]
  PIN u_kt__kp_in[153]
    DIRECTION INPUT ;
    USE SIGNAL ;
    PORT
      LAYER M5 ;
        RECT  149.244 215.808 149.268 216 ;
    END
  END u_kt__kp_in[153]
  PIN u_kt__kp_in[154]
    DIRECTION INPUT ;
    USE SIGNAL ;
    PORT
      LAYER M5 ;
        RECT  149.388 215.808 149.412 216 ;
    END
  END u_kt__kp_in[154]
  PIN u_kt__kp_in[155]
    DIRECTION INPUT ;
    USE SIGNAL ;
    PORT
      LAYER M5 ;
        RECT  149.532 215.808 149.556 216 ;
    END
  END u_kt__kp_in[155]
  PIN u_kt__kp_in[156]
    DIRECTION INPUT ;
    USE SIGNAL ;
    PORT
      LAYER M5 ;
        RECT  149.724 215.808 149.748 216 ;
    END
  END u_kt__kp_in[156]
  PIN u_kt__kp_in[157]
    DIRECTION INPUT ;
    USE SIGNAL ;
    PORT
      LAYER M5 ;
        RECT  149.868 215.808 149.892 216 ;
    END
  END u_kt__kp_in[157]
  PIN u_kt__kp_in[158]
    DIRECTION INPUT ;
    USE SIGNAL ;
    PORT
      LAYER M5 ;
        RECT  150.012 215.808 150.036 216 ;
    END
  END u_kt__kp_in[158]
  PIN u_kt__kp_in[159]
    DIRECTION INPUT ;
    USE SIGNAL ;
    PORT
      LAYER M5 ;
        RECT  150.204 215.808 150.228 216 ;
    END
  END u_kt__kp_in[159]
  PIN u_kt__kp_in[160]
    DIRECTION INPUT ;
    USE SIGNAL ;
    PORT
      LAYER M5 ;
        RECT  150.348 215.808 150.372 216 ;
    END
  END u_kt__kp_in[160]
  PIN u_kt__kp_in[161]
    DIRECTION INPUT ;
    USE SIGNAL ;
    PORT
      LAYER M5 ;
        RECT  150.492 215.808 150.516 216 ;
    END
  END u_kt__kp_in[161]
  PIN u_kt__kp_in[162]
    DIRECTION INPUT ;
    USE SIGNAL ;
    PORT
      LAYER M5 ;
        RECT  150.636 215.808 150.66 216 ;
    END
  END u_kt__kp_in[162]
  PIN u_kt__kp_in[163]
    DIRECTION INPUT ;
    USE SIGNAL ;
    PORT
      LAYER M5 ;
        RECT  150.828 215.808 150.852 216 ;
    END
  END u_kt__kp_in[163]
  PIN u_kt__kp_in[164]
    DIRECTION INPUT ;
    USE SIGNAL ;
    PORT
      LAYER M5 ;
        RECT  150.972 215.808 150.996 216 ;
    END
  END u_kt__kp_in[164]
  PIN u_kt__kp_in[165]
    DIRECTION INPUT ;
    USE SIGNAL ;
    PORT
      LAYER M5 ;
        RECT  151.116 215.808 151.14 216 ;
    END
  END u_kt__kp_in[165]
  PIN u_kt__kp_in[166]
    DIRECTION INPUT ;
    USE SIGNAL ;
    PORT
      LAYER M5 ;
        RECT  151.308 215.808 151.332 216 ;
    END
  END u_kt__kp_in[166]
  PIN u_kt__kp_in[167]
    DIRECTION INPUT ;
    USE SIGNAL ;
    PORT
      LAYER M5 ;
        RECT  151.452 215.808 151.476 216 ;
    END
  END u_kt__kp_in[167]
  PIN u_kt__kp_in[168]
    DIRECTION INPUT ;
    USE SIGNAL ;
    PORT
      LAYER M5 ;
        RECT  151.596 215.808 151.62 216 ;
    END
  END u_kt__kp_in[168]
  PIN u_kt__kp_in[169]
    DIRECTION INPUT ;
    USE SIGNAL ;
    PORT
      LAYER M5 ;
        RECT  151.788 215.808 151.812 216 ;
    END
  END u_kt__kp_in[169]
  PIN u_kt__kp_in[170]
    DIRECTION INPUT ;
    USE SIGNAL ;
    PORT
      LAYER M5 ;
        RECT  151.932 215.808 151.956 216 ;
    END
  END u_kt__kp_in[170]
  PIN u_kt__kp_in[171]
    DIRECTION INPUT ;
    USE SIGNAL ;
    PORT
      LAYER M5 ;
        RECT  152.076 215.808 152.1 216 ;
    END
  END u_kt__kp_in[171]
  PIN u_kt__kp_in[172]
    DIRECTION INPUT ;
    USE SIGNAL ;
    PORT
      LAYER M5 ;
        RECT  152.268 215.808 152.292 216 ;
    END
  END u_kt__kp_in[172]
  PIN u_kt__kp_in[173]
    DIRECTION INPUT ;
    USE SIGNAL ;
    PORT
      LAYER M5 ;
        RECT  152.412 215.808 152.436 216 ;
    END
  END u_kt__kp_in[173]
  PIN u_kt__kp_in[174]
    DIRECTION INPUT ;
    USE SIGNAL ;
    PORT
      LAYER M5 ;
        RECT  152.556 215.808 152.58 216 ;
    END
  END u_kt__kp_in[174]
  PIN u_kt__kp_in[175]
    DIRECTION INPUT ;
    USE SIGNAL ;
    PORT
      LAYER M5 ;
        RECT  152.7 215.808 152.724 216 ;
    END
  END u_kt__kp_in[175]
  PIN u_kt__kp_in[176]
    DIRECTION INPUT ;
    USE SIGNAL ;
    PORT
      LAYER M5 ;
        RECT  152.892 215.808 152.916 216 ;
    END
  END u_kt__kp_in[176]
  PIN u_kt__kp_in[177]
    DIRECTION INPUT ;
    USE SIGNAL ;
    PORT
      LAYER M5 ;
        RECT  153.036 215.808 153.06 216 ;
    END
  END u_kt__kp_in[177]
  PIN u_kt__kp_in[178]
    DIRECTION INPUT ;
    USE SIGNAL ;
    PORT
      LAYER M5 ;
        RECT  153.18 215.808 153.204 216 ;
    END
  END u_kt__kp_in[178]
  PIN u_kt__kp_in[179]
    DIRECTION INPUT ;
    USE SIGNAL ;
    PORT
      LAYER M5 ;
        RECT  153.372 215.808 153.396 216 ;
    END
  END u_kt__kp_in[179]
  PIN u_kt__kp_in[180]
    DIRECTION INPUT ;
    USE SIGNAL ;
    PORT
      LAYER M5 ;
        RECT  153.516 215.808 153.54 216 ;
    END
  END u_kt__kp_in[180]
  PIN u_kt__kp_in[181]
    DIRECTION INPUT ;
    USE SIGNAL ;
    PORT
      LAYER M5 ;
        RECT  153.66 215.808 153.684 216 ;
    END
  END u_kt__kp_in[181]
  PIN u_kt__kp_in[182]
    DIRECTION INPUT ;
    USE SIGNAL ;
    PORT
      LAYER M5 ;
        RECT  153.852 215.808 153.876 216 ;
    END
  END u_kt__kp_in[182]
  PIN u_kt__kp_in[183]
    DIRECTION INPUT ;
    USE SIGNAL ;
    PORT
      LAYER M5 ;
        RECT  153.996 215.808 154.02 216 ;
    END
  END u_kt__kp_in[183]
  PIN u_kt__kp_in[184]
    DIRECTION INPUT ;
    USE SIGNAL ;
    PORT
      LAYER M5 ;
        RECT  154.14 215.808 154.164 216 ;
    END
  END u_kt__kp_in[184]
  PIN u_kt__kp_in[185]
    DIRECTION INPUT ;
    USE SIGNAL ;
    PORT
      LAYER M5 ;
        RECT  154.332 215.808 154.356 216 ;
    END
  END u_kt__kp_in[185]
  PIN u_kt__kp_in[186]
    DIRECTION INPUT ;
    USE SIGNAL ;
    PORT
      LAYER M5 ;
        RECT  154.476 215.808 154.5 216 ;
    END
  END u_kt__kp_in[186]
  PIN u_kt__kp_in[187]
    DIRECTION INPUT ;
    USE SIGNAL ;
    PORT
      LAYER M5 ;
        RECT  154.62 215.808 154.644 216 ;
    END
  END u_kt__kp_in[187]
  PIN u_kt__kp_in[188]
    DIRECTION INPUT ;
    USE SIGNAL ;
    PORT
      LAYER M5 ;
        RECT  154.812 215.808 154.836 216 ;
    END
  END u_kt__kp_in[188]
  PIN u_kt__kp_in[189]
    DIRECTION INPUT ;
    USE SIGNAL ;
    PORT
      LAYER M5 ;
        RECT  154.956 215.808 154.98 216 ;
    END
  END u_kt__kp_in[189]
  PIN u_kt__kp_in[190]
    DIRECTION INPUT ;
    USE SIGNAL ;
    PORT
      LAYER M5 ;
        RECT  155.1 215.808 155.124 216 ;
    END
  END u_kt__kp_in[190]
  PIN u_kt__kp_in[191]
    DIRECTION INPUT ;
    USE SIGNAL ;
    PORT
      LAYER M5 ;
        RECT  155.244 215.808 155.268 216 ;
    END
  END u_kt__kp_in[191]
  PIN u_kt__kp_in[192]
    DIRECTION INPUT ;
    USE SIGNAL ;
    PORT
      LAYER M5 ;
        RECT  155.436 215.808 155.46 216 ;
    END
  END u_kt__kp_in[192]
  PIN u_kt__kp_in[193]
    DIRECTION INPUT ;
    USE SIGNAL ;
    PORT
      LAYER M5 ;
        RECT  155.58 215.808 155.604 216 ;
    END
  END u_kt__kp_in[193]
  PIN u_kt__kp_in[194]
    DIRECTION INPUT ;
    USE SIGNAL ;
    PORT
      LAYER M5 ;
        RECT  155.724 215.808 155.748 216 ;
    END
  END u_kt__kp_in[194]
  PIN u_kt__kp_in[195]
    DIRECTION INPUT ;
    USE SIGNAL ;
    PORT
      LAYER M5 ;
        RECT  155.916 215.808 155.94 216 ;
    END
  END u_kt__kp_in[195]
  PIN u_kt__kp_in[196]
    DIRECTION INPUT ;
    USE SIGNAL ;
    PORT
      LAYER M5 ;
        RECT  156.06 215.808 156.084 216 ;
    END
  END u_kt__kp_in[196]
  PIN u_kt__kp_in[197]
    DIRECTION INPUT ;
    USE SIGNAL ;
    PORT
      LAYER M5 ;
        RECT  156.204 215.808 156.228 216 ;
    END
  END u_kt__kp_in[197]
  PIN u_kt__kp_in[198]
    DIRECTION INPUT ;
    USE SIGNAL ;
    PORT
      LAYER M5 ;
        RECT  156.396 215.808 156.42 216 ;
    END
  END u_kt__kp_in[198]
  PIN u_kt__kp_in[199]
    DIRECTION INPUT ;
    USE SIGNAL ;
    PORT
      LAYER M5 ;
        RECT  156.54 215.808 156.564 216 ;
    END
  END u_kt__kp_in[199]
  PIN u_kt__kp_in[200]
    DIRECTION INPUT ;
    USE SIGNAL ;
    PORT
      LAYER M5 ;
        RECT  156.684 215.808 156.708 216 ;
    END
  END u_kt__kp_in[200]
  PIN u_kt__kp_in[201]
    DIRECTION INPUT ;
    USE SIGNAL ;
    PORT
      LAYER M5 ;
        RECT  156.876 215.808 156.9 216 ;
    END
  END u_kt__kp_in[201]
  PIN u_kt__kp_in[202]
    DIRECTION INPUT ;
    USE SIGNAL ;
    PORT
      LAYER M5 ;
        RECT  157.02 215.808 157.044 216 ;
    END
  END u_kt__kp_in[202]
  PIN u_kt__kp_in[203]
    DIRECTION INPUT ;
    USE SIGNAL ;
    PORT
      LAYER M5 ;
        RECT  157.164 215.808 157.188 216 ;
    END
  END u_kt__kp_in[203]
  PIN u_kt__kp_in[204]
    DIRECTION INPUT ;
    USE SIGNAL ;
    PORT
      LAYER M5 ;
        RECT  157.356 215.808 157.38 216 ;
    END
  END u_kt__kp_in[204]
  PIN u_kt__kp_in[205]
    DIRECTION INPUT ;
    USE SIGNAL ;
    PORT
      LAYER M5 ;
        RECT  157.5 215.808 157.524 216 ;
    END
  END u_kt__kp_in[205]
  PIN u_kt__kp_in[206]
    DIRECTION INPUT ;
    USE SIGNAL ;
    PORT
      LAYER M5 ;
        RECT  157.644 215.808 157.668 216 ;
    END
  END u_kt__kp_in[206]
  PIN u_kt__kp_in[207]
    DIRECTION INPUT ;
    USE SIGNAL ;
    PORT
      LAYER M5 ;
        RECT  157.788 215.808 157.812 216 ;
    END
  END u_kt__kp_in[207]
  PIN u_kt__kp_in[208]
    DIRECTION INPUT ;
    USE SIGNAL ;
    PORT
      LAYER M5 ;
        RECT  157.98 215.808 158.004 216 ;
    END
  END u_kt__kp_in[208]
  PIN u_kt__kp_in[209]
    DIRECTION INPUT ;
    USE SIGNAL ;
    PORT
      LAYER M5 ;
        RECT  158.124 215.808 158.148 216 ;
    END
  END u_kt__kp_in[209]
  PIN u_kt__kp_in[210]
    DIRECTION INPUT ;
    USE SIGNAL ;
    PORT
      LAYER M5 ;
        RECT  158.268 215.808 158.292 216 ;
    END
  END u_kt__kp_in[210]
  PIN u_kt__kp_in[211]
    DIRECTION INPUT ;
    USE SIGNAL ;
    PORT
      LAYER M5 ;
        RECT  158.46 215.808 158.484 216 ;
    END
  END u_kt__kp_in[211]
  PIN u_kt__kp_in[212]
    DIRECTION INPUT ;
    USE SIGNAL ;
    PORT
      LAYER M5 ;
        RECT  158.604 215.808 158.628 216 ;
    END
  END u_kt__kp_in[212]
  PIN u_kt__kp_in[213]
    DIRECTION INPUT ;
    USE SIGNAL ;
    PORT
      LAYER M5 ;
        RECT  158.748 215.808 158.772 216 ;
    END
  END u_kt__kp_in[213]
  PIN u_kt__kp_in[214]
    DIRECTION INPUT ;
    USE SIGNAL ;
    PORT
      LAYER M5 ;
        RECT  158.94 215.808 158.964 216 ;
    END
  END u_kt__kp_in[214]
  PIN u_kt__kp_in[215]
    DIRECTION INPUT ;
    USE SIGNAL ;
    PORT
      LAYER M5 ;
        RECT  159.084 215.808 159.108 216 ;
    END
  END u_kt__kp_in[215]
  PIN u_kt__kp_in[216]
    DIRECTION INPUT ;
    USE SIGNAL ;
    PORT
      LAYER M5 ;
        RECT  159.228 215.808 159.252 216 ;
    END
  END u_kt__kp_in[216]
  PIN u_kt__kp_in[217]
    DIRECTION INPUT ;
    USE SIGNAL ;
    PORT
      LAYER M5 ;
        RECT  159.42 215.808 159.444 216 ;
    END
  END u_kt__kp_in[217]
  PIN u_kt__kp_in[218]
    DIRECTION INPUT ;
    USE SIGNAL ;
    PORT
      LAYER M5 ;
        RECT  159.564 215.808 159.588 216 ;
    END
  END u_kt__kp_in[218]
  PIN u_kt__kp_in[219]
    DIRECTION INPUT ;
    USE SIGNAL ;
    PORT
      LAYER M5 ;
        RECT  159.708 215.808 159.732 216 ;
    END
  END u_kt__kp_in[219]
  PIN u_kt__kp_in[220]
    DIRECTION INPUT ;
    USE SIGNAL ;
    PORT
      LAYER M5 ;
        RECT  159.852 215.808 159.876 216 ;
    END
  END u_kt__kp_in[220]
  PIN u_kt__kp_in[221]
    DIRECTION INPUT ;
    USE SIGNAL ;
    PORT
      LAYER M5 ;
        RECT  160.044 215.808 160.068 216 ;
    END
  END u_kt__kp_in[221]
  PIN u_kt__kp_in[222]
    DIRECTION INPUT ;
    USE SIGNAL ;
    PORT
      LAYER M5 ;
        RECT  160.188 215.808 160.212 216 ;
    END
  END u_kt__kp_in[222]
  PIN u_kt__kp_in[223]
    DIRECTION INPUT ;
    USE SIGNAL ;
    PORT
      LAYER M5 ;
        RECT  160.332 215.808 160.356 216 ;
    END
  END u_kt__kp_in[223]
  PIN u_kt__kp_in[224]
    DIRECTION INPUT ;
    USE SIGNAL ;
    PORT
      LAYER M5 ;
        RECT  160.524 215.808 160.548 216 ;
    END
  END u_kt__kp_in[224]
  PIN u_kt__kp_in[225]
    DIRECTION INPUT ;
    USE SIGNAL ;
    PORT
      LAYER M5 ;
        RECT  160.668 215.808 160.692 216 ;
    END
  END u_kt__kp_in[225]
  PIN u_kt__kp_in[226]
    DIRECTION INPUT ;
    USE SIGNAL ;
    PORT
      LAYER M5 ;
        RECT  160.812 215.808 160.836 216 ;
    END
  END u_kt__kp_in[226]
  PIN u_kt__kp_in[227]
    DIRECTION INPUT ;
    USE SIGNAL ;
    PORT
      LAYER M5 ;
        RECT  161.004 215.808 161.028 216 ;
    END
  END u_kt__kp_in[227]
  PIN u_kt__kp_in[228]
    DIRECTION INPUT ;
    USE SIGNAL ;
    PORT
      LAYER M5 ;
        RECT  161.148 215.808 161.172 216 ;
    END
  END u_kt__kp_in[228]
  PIN u_kt__kp_in[229]
    DIRECTION INPUT ;
    USE SIGNAL ;
    PORT
      LAYER M5 ;
        RECT  161.292 215.808 161.316 216 ;
    END
  END u_kt__kp_in[229]
  PIN u_kt__kp_in[230]
    DIRECTION INPUT ;
    USE SIGNAL ;
    PORT
      LAYER M5 ;
        RECT  161.484 215.808 161.508 216 ;
    END
  END u_kt__kp_in[230]
  PIN u_kt__kp_in[231]
    DIRECTION INPUT ;
    USE SIGNAL ;
    PORT
      LAYER M5 ;
        RECT  161.628 215.808 161.652 216 ;
    END
  END u_kt__kp_in[231]
  PIN u_kt__kp_in[232]
    DIRECTION INPUT ;
    USE SIGNAL ;
    PORT
      LAYER M5 ;
        RECT  161.772 215.808 161.796 216 ;
    END
  END u_kt__kp_in[232]
  PIN u_kt__kp_in[233]
    DIRECTION INPUT ;
    USE SIGNAL ;
    PORT
      LAYER M5 ;
        RECT  161.964 215.808 161.988 216 ;
    END
  END u_kt__kp_in[233]
  PIN u_kt__kp_in[234]
    DIRECTION INPUT ;
    USE SIGNAL ;
    PORT
      LAYER M5 ;
        RECT  162.108 215.808 162.132 216 ;
    END
  END u_kt__kp_in[234]
  PIN u_kt__kp_in[235]
    DIRECTION INPUT ;
    USE SIGNAL ;
    PORT
      LAYER M5 ;
        RECT  162.252 215.808 162.276 216 ;
    END
  END u_kt__kp_in[235]
  PIN u_kt__kp_in[236]
    DIRECTION INPUT ;
    USE SIGNAL ;
    PORT
      LAYER M5 ;
        RECT  162.396 215.808 162.42 216 ;
    END
  END u_kt__kp_in[236]
  PIN u_kt__kp_in[237]
    DIRECTION INPUT ;
    USE SIGNAL ;
    PORT
      LAYER M5 ;
        RECT  162.588 215.808 162.612 216 ;
    END
  END u_kt__kp_in[237]
  PIN u_kt__kp_in[238]
    DIRECTION INPUT ;
    USE SIGNAL ;
    PORT
      LAYER M5 ;
        RECT  162.732 215.808 162.756 216 ;
    END
  END u_kt__kp_in[238]
  PIN u_kt__kp_in[239]
    DIRECTION INPUT ;
    USE SIGNAL ;
    PORT
      LAYER M5 ;
        RECT  162.876 215.808 162.9 216 ;
    END
  END u_kt__kp_in[239]
  PIN u_kt__kp_in[240]
    DIRECTION INPUT ;
    USE SIGNAL ;
    PORT
      LAYER M5 ;
        RECT  163.068 215.808 163.092 216 ;
    END
  END u_kt__kp_in[240]
  PIN u_kt__kp_in[241]
    DIRECTION INPUT ;
    USE SIGNAL ;
    PORT
      LAYER M5 ;
        RECT  163.212 215.808 163.236 216 ;
    END
  END u_kt__kp_in[241]
  PIN u_kt__kp_in[242]
    DIRECTION INPUT ;
    USE SIGNAL ;
    PORT
      LAYER M5 ;
        RECT  163.356 215.808 163.38 216 ;
    END
  END u_kt__kp_in[242]
  PIN u_kt__kp_in[243]
    DIRECTION INPUT ;
    USE SIGNAL ;
    PORT
      LAYER M5 ;
        RECT  163.548 215.808 163.572 216 ;
    END
  END u_kt__kp_in[243]
  PIN u_kt__kp_in[244]
    DIRECTION INPUT ;
    USE SIGNAL ;
    PORT
      LAYER M5 ;
        RECT  163.692 215.808 163.716 216 ;
    END
  END u_kt__kp_in[244]
  PIN u_kt__kp_in[245]
    DIRECTION INPUT ;
    USE SIGNAL ;
    PORT
      LAYER M5 ;
        RECT  163.836 215.808 163.86 216 ;
    END
  END u_kt__kp_in[245]
  PIN u_kt__kp_in[246]
    DIRECTION INPUT ;
    USE SIGNAL ;
    PORT
      LAYER M5 ;
        RECT  164.028 215.808 164.052 216 ;
    END
  END u_kt__kp_in[246]
  PIN u_kt__kp_in[247]
    DIRECTION INPUT ;
    USE SIGNAL ;
    PORT
      LAYER M5 ;
        RECT  164.172 215.808 164.196 216 ;
    END
  END u_kt__kp_in[247]
  PIN u_kt__kp_in[248]
    DIRECTION INPUT ;
    USE SIGNAL ;
    PORT
      LAYER M5 ;
        RECT  164.316 215.808 164.34 216 ;
    END
  END u_kt__kp_in[248]
  PIN u_kt__kp_in[249]
    DIRECTION INPUT ;
    USE SIGNAL ;
    PORT
      LAYER M5 ;
        RECT  164.46 215.808 164.484 216 ;
    END
  END u_kt__kp_in[249]
  PIN u_kt__kp_in[250]
    DIRECTION INPUT ;
    USE SIGNAL ;
    PORT
      LAYER M5 ;
        RECT  164.652 215.808 164.676 216 ;
    END
  END u_kt__kp_in[250]
  PIN u_kt__kp_in[251]
    DIRECTION INPUT ;
    USE SIGNAL ;
    PORT
      LAYER M5 ;
        RECT  164.796 215.808 164.82 216 ;
    END
  END u_kt__kp_in[251]
  PIN u_kt__kp_in[252]
    DIRECTION INPUT ;
    USE SIGNAL ;
    PORT
      LAYER M5 ;
        RECT  164.94 215.808 164.964 216 ;
    END
  END u_kt__kp_in[252]
  PIN u_kt__kp_in[253]
    DIRECTION INPUT ;
    USE SIGNAL ;
    PORT
      LAYER M5 ;
        RECT  165.132 215.808 165.156 216 ;
    END
  END u_kt__kp_in[253]
  PIN u_kt__kp_in[254]
    DIRECTION INPUT ;
    USE SIGNAL ;
    PORT
      LAYER M5 ;
        RECT  165.276 215.808 165.3 216 ;
    END
  END u_kt__kp_in[254]
  PIN u_kt__kp_in[255]
    DIRECTION INPUT ;
    USE SIGNAL ;
    PORT
      LAYER M5 ;
        RECT  165.42 215.808 165.444 216 ;
    END
  END u_kt__kp_in[255]
  PIN u_kt__kp_in[256]
    DIRECTION INPUT ;
    USE SIGNAL ;
    PORT
      LAYER M5 ;
        RECT  165.612 215.808 165.636 216 ;
    END
  END u_kt__kp_in[256]
  PIN u_kt__kp_in[257]
    DIRECTION INPUT ;
    USE SIGNAL ;
    PORT
      LAYER M5 ;
        RECT  165.756 215.808 165.78 216 ;
    END
  END u_kt__kp_in[257]
  PIN u_kt__kp_in[258]
    DIRECTION INPUT ;
    USE SIGNAL ;
    PORT
      LAYER M5 ;
        RECT  165.9 215.808 165.924 216 ;
    END
  END u_kt__kp_in[258]
  PIN u_kt__kp_in[259]
    DIRECTION INPUT ;
    USE SIGNAL ;
    PORT
      LAYER M5 ;
        RECT  166.092 215.808 166.116 216 ;
    END
  END u_kt__kp_in[259]
  PIN u_kt__kp_in[260]
    DIRECTION INPUT ;
    USE SIGNAL ;
    PORT
      LAYER M5 ;
        RECT  166.236 215.808 166.26 216 ;
    END
  END u_kt__kp_in[260]
  PIN u_kt__kp_in[261]
    DIRECTION INPUT ;
    USE SIGNAL ;
    PORT
      LAYER M5 ;
        RECT  166.38 215.808 166.404 216 ;
    END
  END u_kt__kp_in[261]
  PIN u_kt__kp_in[262]
    DIRECTION INPUT ;
    USE SIGNAL ;
    PORT
      LAYER M5 ;
        RECT  166.572 215.808 166.596 216 ;
    END
  END u_kt__kp_in[262]
  PIN u_kt__kp_in[263]
    DIRECTION INPUT ;
    USE SIGNAL ;
    PORT
      LAYER M5 ;
        RECT  166.716 215.808 166.74 216 ;
    END
  END u_kt__kp_in[263]
  PIN u_kt__kp_in[264]
    DIRECTION INPUT ;
    USE SIGNAL ;
    PORT
      LAYER M5 ;
        RECT  166.86 215.808 166.884 216 ;
    END
  END u_kt__kp_in[264]
  PIN u_kt__kp_in[265]
    DIRECTION INPUT ;
    USE SIGNAL ;
    PORT
      LAYER M5 ;
        RECT  167.004 215.808 167.028 216 ;
    END
  END u_kt__kp_in[265]
  PIN u_kt__kp_in[266]
    DIRECTION INPUT ;
    USE SIGNAL ;
    PORT
      LAYER M5 ;
        RECT  167.196 215.808 167.22 216 ;
    END
  END u_kt__kp_in[266]
  PIN u_kt__kp_in[267]
    DIRECTION INPUT ;
    USE SIGNAL ;
    PORT
      LAYER M5 ;
        RECT  167.34 215.808 167.364 216 ;
    END
  END u_kt__kp_in[267]
  PIN u_kt__kp_in[268]
    DIRECTION INPUT ;
    USE SIGNAL ;
    PORT
      LAYER M5 ;
        RECT  167.484 215.808 167.508 216 ;
    END
  END u_kt__kp_in[268]
  PIN u_kt__kp_in[269]
    DIRECTION INPUT ;
    USE SIGNAL ;
    PORT
      LAYER M5 ;
        RECT  167.676 215.808 167.7 216 ;
    END
  END u_kt__kp_in[269]
  PIN u_kt__kp_in[270]
    DIRECTION INPUT ;
    USE SIGNAL ;
    PORT
      LAYER M5 ;
        RECT  167.82 215.808 167.844 216 ;
    END
  END u_kt__kp_in[270]
  PIN u_kt__kp_in[271]
    DIRECTION INPUT ;
    USE SIGNAL ;
    PORT
      LAYER M5 ;
        RECT  167.964 215.808 167.988 216 ;
    END
  END u_kt__kp_in[271]
  PIN u_kt__kp_in[272]
    DIRECTION INPUT ;
    USE SIGNAL ;
    PORT
      LAYER M5 ;
        RECT  168.156 215.808 168.18 216 ;
    END
  END u_kt__kp_in[272]
  PIN u_kt__kp_in[273]
    DIRECTION INPUT ;
    USE SIGNAL ;
    PORT
      LAYER M5 ;
        RECT  168.3 215.808 168.324 216 ;
    END
  END u_kt__kp_in[273]
  PIN u_kt__kp_in[274]
    DIRECTION INPUT ;
    USE SIGNAL ;
    PORT
      LAYER M5 ;
        RECT  168.444 215.808 168.468 216 ;
    END
  END u_kt__kp_in[274]
  PIN u_kt__kp_in[275]
    DIRECTION INPUT ;
    USE SIGNAL ;
    PORT
      LAYER M5 ;
        RECT  168.636 215.808 168.66 216 ;
    END
  END u_kt__kp_in[275]
  PIN u_kt__kp_in[276]
    DIRECTION INPUT ;
    USE SIGNAL ;
    PORT
      LAYER M5 ;
        RECT  168.78 215.808 168.804 216 ;
    END
  END u_kt__kp_in[276]
  PIN u_kt__kp_in[277]
    DIRECTION INPUT ;
    USE SIGNAL ;
    PORT
      LAYER M5 ;
        RECT  168.924 215.808 168.948 216 ;
    END
  END u_kt__kp_in[277]
  PIN u_kt__kp_in[278]
    DIRECTION INPUT ;
    USE SIGNAL ;
    PORT
      LAYER M5 ;
        RECT  169.116 215.808 169.14 216 ;
    END
  END u_kt__kp_in[278]
  PIN u_kt__kp_in[279]
    DIRECTION INPUT ;
    USE SIGNAL ;
    PORT
      LAYER M5 ;
        RECT  169.26 215.808 169.284 216 ;
    END
  END u_kt__kp_in[279]
  PIN u_kt__kp_in[280]
    DIRECTION INPUT ;
    USE SIGNAL ;
    PORT
      LAYER M5 ;
        RECT  169.404 215.808 169.428 216 ;
    END
  END u_kt__kp_in[280]
  PIN u_kt__kp_in[281]
    DIRECTION INPUT ;
    USE SIGNAL ;
    PORT
      LAYER M5 ;
        RECT  169.548 215.808 169.572 216 ;
    END
  END u_kt__kp_in[281]
  PIN u_kt__kp_in[282]
    DIRECTION INPUT ;
    USE SIGNAL ;
    PORT
      LAYER M5 ;
        RECT  169.74 215.808 169.764 216 ;
    END
  END u_kt__kp_in[282]
  PIN u_kt__kp_in[283]
    DIRECTION INPUT ;
    USE SIGNAL ;
    PORT
      LAYER M5 ;
        RECT  169.884 215.808 169.908 216 ;
    END
  END u_kt__kp_in[283]
  PIN u_kt__kp_in[284]
    DIRECTION INPUT ;
    USE SIGNAL ;
    PORT
      LAYER M5 ;
        RECT  170.028 215.808 170.052 216 ;
    END
  END u_kt__kp_in[284]
  PIN u_kt__kp_in[285]
    DIRECTION INPUT ;
    USE SIGNAL ;
    PORT
      LAYER M5 ;
        RECT  170.22 215.808 170.244 216 ;
    END
  END u_kt__kp_in[285]
  PIN u_kt__kp_in[286]
    DIRECTION INPUT ;
    USE SIGNAL ;
    PORT
      LAYER M5 ;
        RECT  170.364 215.808 170.388 216 ;
    END
  END u_kt__kp_in[286]
  PIN u_kt__kp_in[287]
    DIRECTION INPUT ;
    USE SIGNAL ;
    PORT
      LAYER M5 ;
        RECT  170.508 215.808 170.532 216 ;
    END
  END u_kt__kp_in[287]
  PIN u_kt__kp_in[288]
    DIRECTION INPUT ;
    USE SIGNAL ;
    PORT
      LAYER M5 ;
        RECT  170.7 215.808 170.724 216 ;
    END
  END u_kt__kp_in[288]
  PIN u_kt__kp_in[289]
    DIRECTION INPUT ;
    USE SIGNAL ;
    PORT
      LAYER M5 ;
        RECT  170.844 215.808 170.868 216 ;
    END
  END u_kt__kp_in[289]
  PIN u_kt__kp_in[290]
    DIRECTION INPUT ;
    USE SIGNAL ;
    PORT
      LAYER M5 ;
        RECT  170.988 215.808 171.012 216 ;
    END
  END u_kt__kp_in[290]
  PIN u_kt__kp_in[291]
    DIRECTION INPUT ;
    USE SIGNAL ;
    PORT
      LAYER M5 ;
        RECT  171.18 215.808 171.204 216 ;
    END
  END u_kt__kp_in[291]
  PIN u_kt__kp_in[292]
    DIRECTION INPUT ;
    USE SIGNAL ;
    PORT
      LAYER M5 ;
        RECT  171.324 215.808 171.348 216 ;
    END
  END u_kt__kp_in[292]
  PIN u_kt__kp_in[293]
    DIRECTION INPUT ;
    USE SIGNAL ;
    PORT
      LAYER M5 ;
        RECT  171.468 215.808 171.492 216 ;
    END
  END u_kt__kp_in[293]
  PIN u_kt__kp_in[294]
    DIRECTION INPUT ;
    USE SIGNAL ;
    PORT
      LAYER M5 ;
        RECT  171.612 215.808 171.636 216 ;
    END
  END u_kt__kp_in[294]
  PIN u_kt__kp_in[295]
    DIRECTION INPUT ;
    USE SIGNAL ;
    PORT
      LAYER M5 ;
        RECT  171.804 215.808 171.828 216 ;
    END
  END u_kt__kp_in[295]
  PIN u_kt__kp_in[296]
    DIRECTION INPUT ;
    USE SIGNAL ;
    PORT
      LAYER M5 ;
        RECT  171.948 215.808 171.972 216 ;
    END
  END u_kt__kp_in[296]
  PIN u_kt__kp_in[297]
    DIRECTION INPUT ;
    USE SIGNAL ;
    PORT
      LAYER M5 ;
        RECT  172.092 215.808 172.116 216 ;
    END
  END u_kt__kp_in[297]
  PIN u_kt__kp_in[298]
    DIRECTION INPUT ;
    USE SIGNAL ;
    PORT
      LAYER M5 ;
        RECT  172.284 215.808 172.308 216 ;
    END
  END u_kt__kp_in[298]
  PIN u_kt__kp_in[299]
    DIRECTION INPUT ;
    USE SIGNAL ;
    PORT
      LAYER M5 ;
        RECT  172.428 215.808 172.452 216 ;
    END
  END u_kt__kp_in[299]
  PIN u_kt__kp_in[300]
    DIRECTION INPUT ;
    USE SIGNAL ;
    PORT
      LAYER M5 ;
        RECT  172.572 215.808 172.596 216 ;
    END
  END u_kt__kp_in[300]
  PIN u_kt__kp_in[301]
    DIRECTION INPUT ;
    USE SIGNAL ;
    PORT
      LAYER M5 ;
        RECT  172.764 215.808 172.788 216 ;
    END
  END u_kt__kp_in[301]
  PIN u_kt__kp_in[302]
    DIRECTION INPUT ;
    USE SIGNAL ;
    PORT
      LAYER M5 ;
        RECT  172.908 215.808 172.932 216 ;
    END
  END u_kt__kp_in[302]
  PIN u_kt__kp_in[303]
    DIRECTION INPUT ;
    USE SIGNAL ;
    PORT
      LAYER M5 ;
        RECT  173.052 215.808 173.076 216 ;
    END
  END u_kt__kp_in[303]
  PIN u_kt__kp_in[304]
    DIRECTION INPUT ;
    USE SIGNAL ;
    PORT
      LAYER M5 ;
        RECT  173.244 215.808 173.268 216 ;
    END
  END u_kt__kp_in[304]
  PIN u_kt__kp_in[305]
    DIRECTION INPUT ;
    USE SIGNAL ;
    PORT
      LAYER M5 ;
        RECT  173.388 215.808 173.412 216 ;
    END
  END u_kt__kp_in[305]
  PIN u_kt__kp_in[306]
    DIRECTION INPUT ;
    USE SIGNAL ;
    PORT
      LAYER M5 ;
        RECT  173.532 215.808 173.556 216 ;
    END
  END u_kt__kp_in[306]
  PIN u_kt__kp_in[307]
    DIRECTION INPUT ;
    USE SIGNAL ;
    PORT
      LAYER M5 ;
        RECT  173.724 215.808 173.748 216 ;
    END
  END u_kt__kp_in[307]
  PIN u_kt__kp_in[308]
    DIRECTION INPUT ;
    USE SIGNAL ;
    PORT
      LAYER M5 ;
        RECT  173.868 215.808 173.892 216 ;
    END
  END u_kt__kp_in[308]
  PIN u_kt__kp_in[309]
    DIRECTION INPUT ;
    USE SIGNAL ;
    PORT
      LAYER M5 ;
        RECT  174.012 215.808 174.036 216 ;
    END
  END u_kt__kp_in[309]
  PIN u_kt__kp_in[310]
    DIRECTION INPUT ;
    USE SIGNAL ;
    PORT
      LAYER M5 ;
        RECT  174.156 215.808 174.18 216 ;
    END
  END u_kt__kp_in[310]
  PIN u_kt__kp_in[311]
    DIRECTION INPUT ;
    USE SIGNAL ;
    PORT
      LAYER M5 ;
        RECT  174.348 215.808 174.372 216 ;
    END
  END u_kt__kp_in[311]
  PIN u_kt__kp_in[312]
    DIRECTION INPUT ;
    USE SIGNAL ;
    PORT
      LAYER M5 ;
        RECT  174.492 215.808 174.516 216 ;
    END
  END u_kt__kp_in[312]
  PIN u_kt__kp_in[313]
    DIRECTION INPUT ;
    USE SIGNAL ;
    PORT
      LAYER M5 ;
        RECT  174.636 215.808 174.66 216 ;
    END
  END u_kt__kp_in[313]
  PIN u_kt__kp_in[314]
    DIRECTION INPUT ;
    USE SIGNAL ;
    PORT
      LAYER M5 ;
        RECT  174.828 215.808 174.852 216 ;
    END
  END u_kt__kp_in[314]
  PIN u_kt__kp_in[315]
    DIRECTION INPUT ;
    USE SIGNAL ;
    PORT
      LAYER M5 ;
        RECT  174.972 215.808 174.996 216 ;
    END
  END u_kt__kp_in[315]
  PIN u_kt__kp_in[316]
    DIRECTION INPUT ;
    USE SIGNAL ;
    PORT
      LAYER M5 ;
        RECT  175.116 215.808 175.14 216 ;
    END
  END u_kt__kp_in[316]
  PIN u_kt__kp_in[317]
    DIRECTION INPUT ;
    USE SIGNAL ;
    PORT
      LAYER M5 ;
        RECT  175.308 215.808 175.332 216 ;
    END
  END u_kt__kp_in[317]
  PIN u_kt__kp_in[318]
    DIRECTION INPUT ;
    USE SIGNAL ;
    PORT
      LAYER M5 ;
        RECT  175.452 215.808 175.476 216 ;
    END
  END u_kt__kp_in[318]
  PIN u_kt__kp_in[319]
    DIRECTION INPUT ;
    USE SIGNAL ;
    PORT
      LAYER M5 ;
        RECT  175.596 215.808 175.62 216 ;
    END
  END u_kt__kp_in[319]
  PIN u_kt__kp_in[320]
    DIRECTION INPUT ;
    USE SIGNAL ;
    PORT
      LAYER M5 ;
        RECT  175.788 215.808 175.812 216 ;
    END
  END u_kt__kp_in[320]
  PIN u_kt__kp_in[321]
    DIRECTION INPUT ;
    USE SIGNAL ;
    PORT
      LAYER M5 ;
        RECT  175.932 215.808 175.956 216 ;
    END
  END u_kt__kp_in[321]
  PIN u_kt__kp_in[322]
    DIRECTION INPUT ;
    USE SIGNAL ;
    PORT
      LAYER M5 ;
        RECT  176.076 215.808 176.1 216 ;
    END
  END u_kt__kp_in[322]
  PIN u_kt__kp_in[323]
    DIRECTION INPUT ;
    USE SIGNAL ;
    PORT
      LAYER M5 ;
        RECT  176.22 215.808 176.244 216 ;
    END
  END u_kt__kp_in[323]
  PIN u_kt__kp_in[324]
    DIRECTION INPUT ;
    USE SIGNAL ;
    PORT
      LAYER M5 ;
        RECT  176.412 215.808 176.436 216 ;
    END
  END u_kt__kp_in[324]
  PIN u_kt__kp_in[325]
    DIRECTION INPUT ;
    USE SIGNAL ;
    PORT
      LAYER M5 ;
        RECT  176.556 215.808 176.58 216 ;
    END
  END u_kt__kp_in[325]
  PIN u_kt__kp_in[326]
    DIRECTION INPUT ;
    USE SIGNAL ;
    PORT
      LAYER M5 ;
        RECT  176.7 215.808 176.724 216 ;
    END
  END u_kt__kp_in[326]
  PIN u_kt__kp_in[327]
    DIRECTION INPUT ;
    USE SIGNAL ;
    PORT
      LAYER M5 ;
        RECT  176.892 215.808 176.916 216 ;
    END
  END u_kt__kp_in[327]
  PIN u_kt__kp_in[328]
    DIRECTION INPUT ;
    USE SIGNAL ;
    PORT
      LAYER M5 ;
        RECT  177.036 215.808 177.06 216 ;
    END
  END u_kt__kp_in[328]
  PIN u_kt__kp_in[329]
    DIRECTION INPUT ;
    USE SIGNAL ;
    PORT
      LAYER M5 ;
        RECT  177.18 215.808 177.204 216 ;
    END
  END u_kt__kp_in[329]
  PIN u_kt__kp_in[330]
    DIRECTION INPUT ;
    USE SIGNAL ;
    PORT
      LAYER M5 ;
        RECT  177.372 215.808 177.396 216 ;
    END
  END u_kt__kp_in[330]
  PIN u_kt__kp_in[331]
    DIRECTION INPUT ;
    USE SIGNAL ;
    PORT
      LAYER M5 ;
        RECT  177.516 215.808 177.54 216 ;
    END
  END u_kt__kp_in[331]
  PIN u_kt__kp_in[332]
    DIRECTION INPUT ;
    USE SIGNAL ;
    PORT
      LAYER M5 ;
        RECT  177.66 215.808 177.684 216 ;
    END
  END u_kt__kp_in[332]
  PIN u_kt__kp_in[333]
    DIRECTION INPUT ;
    USE SIGNAL ;
    PORT
      LAYER M5 ;
        RECT  177.852 215.808 177.876 216 ;
    END
  END u_kt__kp_in[333]
  PIN u_kt__kp_in[334]
    DIRECTION INPUT ;
    USE SIGNAL ;
    PORT
      LAYER M5 ;
        RECT  177.996 215.808 178.02 216 ;
    END
  END u_kt__kp_in[334]
  PIN u_kt__kp_in[335]
    DIRECTION INPUT ;
    USE SIGNAL ;
    PORT
      LAYER M5 ;
        RECT  178.14 215.808 178.164 216 ;
    END
  END u_kt__kp_in[335]
  PIN u_kt__kp_in[336]
    DIRECTION INPUT ;
    USE SIGNAL ;
    PORT
      LAYER M5 ;
        RECT  178.332 215.808 178.356 216 ;
    END
  END u_kt__kp_in[336]
  PIN u_kt__kp_in[337]
    DIRECTION INPUT ;
    USE SIGNAL ;
    PORT
      LAYER M5 ;
        RECT  178.476 215.808 178.5 216 ;
    END
  END u_kt__kp_in[337]
  PIN u_kt__kp_in[338]
    DIRECTION INPUT ;
    USE SIGNAL ;
    PORT
      LAYER M5 ;
        RECT  178.62 215.808 178.644 216 ;
    END
  END u_kt__kp_in[338]
  PIN u_kt__kp_in[339]
    DIRECTION INPUT ;
    USE SIGNAL ;
    PORT
      LAYER M5 ;
        RECT  178.764 215.808 178.788 216 ;
    END
  END u_kt__kp_in[339]
  PIN u_kt__kp_in[340]
    DIRECTION INPUT ;
    USE SIGNAL ;
    PORT
      LAYER M5 ;
        RECT  178.956 215.808 178.98 216 ;
    END
  END u_kt__kp_in[340]
  PIN u_kt__kp_in[341]
    DIRECTION INPUT ;
    USE SIGNAL ;
    PORT
      LAYER M5 ;
        RECT  179.1 215.808 179.124 216 ;
    END
  END u_kt__kp_in[341]
  PIN u_kt__kp_in[342]
    DIRECTION INPUT ;
    USE SIGNAL ;
    PORT
      LAYER M5 ;
        RECT  179.244 215.808 179.268 216 ;
    END
  END u_kt__kp_in[342]
  PIN u_kt__kp_in[343]
    DIRECTION INPUT ;
    USE SIGNAL ;
    PORT
      LAYER M5 ;
        RECT  179.436 215.808 179.46 216 ;
    END
  END u_kt__kp_in[343]
  PIN u_kt__kp_in[344]
    DIRECTION INPUT ;
    USE SIGNAL ;
    PORT
      LAYER M5 ;
        RECT  179.58 215.808 179.604 216 ;
    END
  END u_kt__kp_in[344]
  PIN u_kt__kp_in[345]
    DIRECTION INPUT ;
    USE SIGNAL ;
    PORT
      LAYER M5 ;
        RECT  179.724 215.808 179.748 216 ;
    END
  END u_kt__kp_in[345]
  PIN u_kt__kp_in[346]
    DIRECTION INPUT ;
    USE SIGNAL ;
    PORT
      LAYER M5 ;
        RECT  179.916 215.808 179.94 216 ;
    END
  END u_kt__kp_in[346]
  PIN u_kt__kp_in[347]
    DIRECTION INPUT ;
    USE SIGNAL ;
    PORT
      LAYER M5 ;
        RECT  180.06 215.808 180.084 216 ;
    END
  END u_kt__kp_in[347]
  PIN u_kt__kp_in[348]
    DIRECTION INPUT ;
    USE SIGNAL ;
    PORT
      LAYER M5 ;
        RECT  180.204 215.808 180.228 216 ;
    END
  END u_kt__kp_in[348]
  PIN u_kt__kp_in[349]
    DIRECTION INPUT ;
    USE SIGNAL ;
    PORT
      LAYER M5 ;
        RECT  180.396 215.808 180.42 216 ;
    END
  END u_kt__kp_in[349]
  PIN u_kt__kp_in[350]
    DIRECTION INPUT ;
    USE SIGNAL ;
    PORT
      LAYER M5 ;
        RECT  180.54 215.808 180.564 216 ;
    END
  END u_kt__kp_in[350]
  PIN u_kt__kp_in[351]
    DIRECTION INPUT ;
    USE SIGNAL ;
    PORT
      LAYER M5 ;
        RECT  180.684 215.808 180.708 216 ;
    END
  END u_kt__kp_in[351]
  PIN u_kt__kp_in[352]
    DIRECTION INPUT ;
    USE SIGNAL ;
    PORT
      LAYER M5 ;
        RECT  180.876 215.808 180.9 216 ;
    END
  END u_kt__kp_in[352]
  PIN u_kt__kp_in[353]
    DIRECTION INPUT ;
    USE SIGNAL ;
    PORT
      LAYER M5 ;
        RECT  181.02 215.808 181.044 216 ;
    END
  END u_kt__kp_in[353]
  PIN u_kt__kp_in[354]
    DIRECTION INPUT ;
    USE SIGNAL ;
    PORT
      LAYER M5 ;
        RECT  181.164 215.808 181.188 216 ;
    END
  END u_kt__kp_in[354]
  PIN u_kt__kp_in[355]
    DIRECTION INPUT ;
    USE SIGNAL ;
    PORT
      LAYER M5 ;
        RECT  181.308 215.808 181.332 216 ;
    END
  END u_kt__kp_in[355]
  PIN u_kt__kp_in[356]
    DIRECTION INPUT ;
    USE SIGNAL ;
    PORT
      LAYER M5 ;
        RECT  181.5 215.808 181.524 216 ;
    END
  END u_kt__kp_in[356]
  PIN u_kt__kp_in[357]
    DIRECTION INPUT ;
    USE SIGNAL ;
    PORT
      LAYER M5 ;
        RECT  181.644 215.808 181.668 216 ;
    END
  END u_kt__kp_in[357]
  PIN u_kt__kp_in[358]
    DIRECTION INPUT ;
    USE SIGNAL ;
    PORT
      LAYER M5 ;
        RECT  181.788 215.808 181.812 216 ;
    END
  END u_kt__kp_in[358]
  PIN u_kt__kp_in[359]
    DIRECTION INPUT ;
    USE SIGNAL ;
    PORT
      LAYER M5 ;
        RECT  181.98 215.808 182.004 216 ;
    END
  END u_kt__kp_in[359]
  PIN u_kt__kp_in[360]
    DIRECTION INPUT ;
    USE SIGNAL ;
    PORT
      LAYER M5 ;
        RECT  182.124 215.808 182.148 216 ;
    END
  END u_kt__kp_in[360]
  PIN u_kt__kp_in[361]
    DIRECTION INPUT ;
    USE SIGNAL ;
    PORT
      LAYER M5 ;
        RECT  182.268 215.808 182.292 216 ;
    END
  END u_kt__kp_in[361]
  PIN u_kt__kp_in[362]
    DIRECTION INPUT ;
    USE SIGNAL ;
    PORT
      LAYER M5 ;
        RECT  182.46 215.808 182.484 216 ;
    END
  END u_kt__kp_in[362]
  PIN u_kt__kp_in[363]
    DIRECTION INPUT ;
    USE SIGNAL ;
    PORT
      LAYER M5 ;
        RECT  182.604 215.808 182.628 216 ;
    END
  END u_kt__kp_in[363]
  PIN u_kt__kp_in[364]
    DIRECTION INPUT ;
    USE SIGNAL ;
    PORT
      LAYER M5 ;
        RECT  182.748 215.808 182.772 216 ;
    END
  END u_kt__kp_in[364]
  PIN u_kt__kp_in[365]
    DIRECTION INPUT ;
    USE SIGNAL ;
    PORT
      LAYER M5 ;
        RECT  182.94 215.808 182.964 216 ;
    END
  END u_kt__kp_in[365]
  PIN u_kt__kp_in[366]
    DIRECTION INPUT ;
    USE SIGNAL ;
    PORT
      LAYER M5 ;
        RECT  183.084 215.808 183.108 216 ;
    END
  END u_kt__kp_in[366]
  PIN u_kt__kp_in[367]
    DIRECTION INPUT ;
    USE SIGNAL ;
    PORT
      LAYER M5 ;
        RECT  183.228 215.808 183.252 216 ;
    END
  END u_kt__kp_in[367]
  PIN u_kt__kp_in[368]
    DIRECTION INPUT ;
    USE SIGNAL ;
    PORT
      LAYER M5 ;
        RECT  183.372 215.808 183.396 216 ;
    END
  END u_kt__kp_in[368]
  PIN u_kt__kp_in[369]
    DIRECTION INPUT ;
    USE SIGNAL ;
    PORT
      LAYER M5 ;
        RECT  183.564 215.808 183.588 216 ;
    END
  END u_kt__kp_in[369]
  PIN u_kt__kp_in[370]
    DIRECTION INPUT ;
    USE SIGNAL ;
    PORT
      LAYER M5 ;
        RECT  183.708 215.808 183.732 216 ;
    END
  END u_kt__kp_in[370]
  PIN u_kt__kp_in[371]
    DIRECTION INPUT ;
    USE SIGNAL ;
    PORT
      LAYER M5 ;
        RECT  183.852 215.808 183.876 216 ;
    END
  END u_kt__kp_in[371]
  PIN u_kt__kp_in[372]
    DIRECTION INPUT ;
    USE SIGNAL ;
    PORT
      LAYER M5 ;
        RECT  184.044 215.808 184.068 216 ;
    END
  END u_kt__kp_in[372]
  PIN u_kt__kp_in[373]
    DIRECTION INPUT ;
    USE SIGNAL ;
    PORT
      LAYER M5 ;
        RECT  184.188 215.808 184.212 216 ;
    END
  END u_kt__kp_in[373]
  PIN u_kt__kp_in[374]
    DIRECTION INPUT ;
    USE SIGNAL ;
    PORT
      LAYER M5 ;
        RECT  184.332 215.808 184.356 216 ;
    END
  END u_kt__kp_in[374]
  PIN u_kt__kp_in[375]
    DIRECTION INPUT ;
    USE SIGNAL ;
    PORT
      LAYER M5 ;
        RECT  184.524 215.808 184.548 216 ;
    END
  END u_kt__kp_in[375]
  PIN u_kt__kp_in[376]
    DIRECTION INPUT ;
    USE SIGNAL ;
    PORT
      LAYER M5 ;
        RECT  184.668 215.808 184.692 216 ;
    END
  END u_kt__kp_in[376]
  PIN u_kt__kp_in[377]
    DIRECTION INPUT ;
    USE SIGNAL ;
    PORT
      LAYER M5 ;
        RECT  184.812 215.808 184.836 216 ;
    END
  END u_kt__kp_in[377]
  PIN u_kt__kp_in[378]
    DIRECTION INPUT ;
    USE SIGNAL ;
    PORT
      LAYER M5 ;
        RECT  185.004 215.808 185.028 216 ;
    END
  END u_kt__kp_in[378]
  PIN u_kt__kp_in[379]
    DIRECTION INPUT ;
    USE SIGNAL ;
    PORT
      LAYER M5 ;
        RECT  185.148 215.808 185.172 216 ;
    END
  END u_kt__kp_in[379]
  PIN u_kt__kp_in[380]
    DIRECTION INPUT ;
    USE SIGNAL ;
    PORT
      LAYER M5 ;
        RECT  185.292 215.808 185.316 216 ;
    END
  END u_kt__kp_in[380]
  PIN u_kt__kp_in[381]
    DIRECTION INPUT ;
    USE SIGNAL ;
    PORT
      LAYER M5 ;
        RECT  185.484 215.808 185.508 216 ;
    END
  END u_kt__kp_in[381]
  PIN u_kt__kp_in[382]
    DIRECTION INPUT ;
    USE SIGNAL ;
    PORT
      LAYER M5 ;
        RECT  185.628 215.808 185.652 216 ;
    END
  END u_kt__kp_in[382]
  PIN u_kt__kp_in[383]
    DIRECTION INPUT ;
    USE SIGNAL ;
    PORT
      LAYER M5 ;
        RECT  185.772 215.808 185.796 216 ;
    END
  END u_kt__kp_in[383]
  PIN u_kt__kp_in[384]
    DIRECTION INPUT ;
    USE SIGNAL ;
    PORT
      LAYER M5 ;
        RECT  185.916 215.808 185.94 216 ;
    END
  END u_kt__kp_in[384]
  PIN u_kt__kp_in[385]
    DIRECTION INPUT ;
    USE SIGNAL ;
    PORT
      LAYER M5 ;
        RECT  186.108 215.808 186.132 216 ;
    END
  END u_kt__kp_in[385]
  PIN u_kt__kp_in[386]
    DIRECTION INPUT ;
    USE SIGNAL ;
    PORT
      LAYER M5 ;
        RECT  186.252 215.808 186.276 216 ;
    END
  END u_kt__kp_in[386]
  PIN u_kt__kp_in[387]
    DIRECTION INPUT ;
    USE SIGNAL ;
    PORT
      LAYER M5 ;
        RECT  186.396 215.808 186.42 216 ;
    END
  END u_kt__kp_in[387]
  PIN u_kt__kp_in[388]
    DIRECTION INPUT ;
    USE SIGNAL ;
    PORT
      LAYER M5 ;
        RECT  186.588 215.808 186.612 216 ;
    END
  END u_kt__kp_in[388]
  PIN u_kt__kp_in[389]
    DIRECTION INPUT ;
    USE SIGNAL ;
    PORT
      LAYER M5 ;
        RECT  186.732 215.808 186.756 216 ;
    END
  END u_kt__kp_in[389]
  PIN u_kt__kp_in[390]
    DIRECTION INPUT ;
    USE SIGNAL ;
    PORT
      LAYER M5 ;
        RECT  186.876 215.808 186.9 216 ;
    END
  END u_kt__kp_in[390]
  PIN u_kt__kp_in[391]
    DIRECTION INPUT ;
    USE SIGNAL ;
    PORT
      LAYER M5 ;
        RECT  187.068 215.808 187.092 216 ;
    END
  END u_kt__kp_in[391]
  PIN u_kt__kp_in[392]
    DIRECTION INPUT ;
    USE SIGNAL ;
    PORT
      LAYER M5 ;
        RECT  187.212 215.808 187.236 216 ;
    END
  END u_kt__kp_in[392]
  PIN u_kt__kp_in[393]
    DIRECTION INPUT ;
    USE SIGNAL ;
    PORT
      LAYER M5 ;
        RECT  187.356 215.808 187.38 216 ;
    END
  END u_kt__kp_in[393]
  PIN u_kt__kp_in[394]
    DIRECTION INPUT ;
    USE SIGNAL ;
    PORT
      LAYER M5 ;
        RECT  187.548 215.808 187.572 216 ;
    END
  END u_kt__kp_in[394]
  PIN u_kt__kp_in[395]
    DIRECTION INPUT ;
    USE SIGNAL ;
    PORT
      LAYER M5 ;
        RECT  187.692 215.808 187.716 216 ;
    END
  END u_kt__kp_in[395]
  PIN u_kt__kp_in[396]
    DIRECTION INPUT ;
    USE SIGNAL ;
    PORT
      LAYER M5 ;
        RECT  187.836 215.808 187.86 216 ;
    END
  END u_kt__kp_in[396]
  PIN u_kt__kp_in[397]
    DIRECTION INPUT ;
    USE SIGNAL ;
    PORT
      LAYER M5 ;
        RECT  187.98 215.808 188.004 216 ;
    END
  END u_kt__kp_in[397]
  PIN u_kt__kp_in[398]
    DIRECTION INPUT ;
    USE SIGNAL ;
    PORT
      LAYER M5 ;
        RECT  188.172 215.808 188.196 216 ;
    END
  END u_kt__kp_in[398]
  PIN u_kt__kp_in[399]
    DIRECTION INPUT ;
    USE SIGNAL ;
    PORT
      LAYER M5 ;
        RECT  188.316 215.808 188.34 216 ;
    END
  END u_kt__kp_in[399]
  PIN u_kt__kp_in[400]
    DIRECTION INPUT ;
    USE SIGNAL ;
    PORT
      LAYER M5 ;
        RECT  188.46 215.808 188.484 216 ;
    END
  END u_kt__kp_in[400]
  PIN u_kt__kp_in[401]
    DIRECTION INPUT ;
    USE SIGNAL ;
    PORT
      LAYER M5 ;
        RECT  188.652 215.808 188.676 216 ;
    END
  END u_kt__kp_in[401]
  PIN u_kt__kp_in[402]
    DIRECTION INPUT ;
    USE SIGNAL ;
    PORT
      LAYER M5 ;
        RECT  188.796 215.808 188.82 216 ;
    END
  END u_kt__kp_in[402]
  PIN u_kt__kp_in[403]
    DIRECTION INPUT ;
    USE SIGNAL ;
    PORT
      LAYER M5 ;
        RECT  188.94 215.808 188.964 216 ;
    END
  END u_kt__kp_in[403]
  PIN u_kt__kp_in[404]
    DIRECTION INPUT ;
    USE SIGNAL ;
    PORT
      LAYER M5 ;
        RECT  189.132 215.808 189.156 216 ;
    END
  END u_kt__kp_in[404]
  PIN u_kt__kp_in[405]
    DIRECTION INPUT ;
    USE SIGNAL ;
    PORT
      LAYER M5 ;
        RECT  189.276 215.808 189.3 216 ;
    END
  END u_kt__kp_in[405]
  PIN u_kt__kp_in[406]
    DIRECTION INPUT ;
    USE SIGNAL ;
    PORT
      LAYER M5 ;
        RECT  189.42 215.808 189.444 216 ;
    END
  END u_kt__kp_in[406]
  PIN u_kt__kp_in[407]
    DIRECTION INPUT ;
    USE SIGNAL ;
    PORT
      LAYER M5 ;
        RECT  189.612 215.808 189.636 216 ;
    END
  END u_kt__kp_in[407]
  PIN u_kt__kp_in[408]
    DIRECTION INPUT ;
    USE SIGNAL ;
    PORT
      LAYER M5 ;
        RECT  189.756 215.808 189.78 216 ;
    END
  END u_kt__kp_in[408]
  PIN u_kt__kp_in[409]
    DIRECTION INPUT ;
    USE SIGNAL ;
    PORT
      LAYER M5 ;
        RECT  189.9 215.808 189.924 216 ;
    END
  END u_kt__kp_in[409]
  PIN u_kt__kp_in[410]
    DIRECTION INPUT ;
    USE SIGNAL ;
    PORT
      LAYER M5 ;
        RECT  190.092 215.808 190.116 216 ;
    END
  END u_kt__kp_in[410]
  PIN u_kt__kp_in[411]
    DIRECTION INPUT ;
    USE SIGNAL ;
    PORT
      LAYER M5 ;
        RECT  190.236 215.808 190.26 216 ;
    END
  END u_kt__kp_in[411]
  PIN u_kt__kp_in[412]
    DIRECTION INPUT ;
    USE SIGNAL ;
    PORT
      LAYER M5 ;
        RECT  190.38 215.808 190.404 216 ;
    END
  END u_kt__kp_in[412]
  PIN u_kt__kp_in[413]
    DIRECTION INPUT ;
    USE SIGNAL ;
    PORT
      LAYER M5 ;
        RECT  190.524 215.808 190.548 216 ;
    END
  END u_kt__kp_in[413]
  PIN u_kt__kp_in[414]
    DIRECTION INPUT ;
    USE SIGNAL ;
    PORT
      LAYER M5 ;
        RECT  190.716 215.808 190.74 216 ;
    END
  END u_kt__kp_in[414]
  PIN u_kt__kp_in[415]
    DIRECTION INPUT ;
    USE SIGNAL ;
    PORT
      LAYER M5 ;
        RECT  190.86 215.808 190.884 216 ;
    END
  END u_kt__kp_in[415]
  PIN u_kt__kp_in[416]
    DIRECTION INPUT ;
    USE SIGNAL ;
    PORT
      LAYER M5 ;
        RECT  191.004 215.808 191.028 216 ;
    END
  END u_kt__kp_in[416]
  PIN u_kt__kp_in[417]
    DIRECTION INPUT ;
    USE SIGNAL ;
    PORT
      LAYER M5 ;
        RECT  191.196 215.808 191.22 216 ;
    END
  END u_kt__kp_in[417]
  PIN u_kt__kp_in[418]
    DIRECTION INPUT ;
    USE SIGNAL ;
    PORT
      LAYER M5 ;
        RECT  191.34 215.808 191.364 216 ;
    END
  END u_kt__kp_in[418]
  PIN u_kt__kp_in[419]
    DIRECTION INPUT ;
    USE SIGNAL ;
    PORT
      LAYER M5 ;
        RECT  191.484 215.808 191.508 216 ;
    END
  END u_kt__kp_in[419]
  PIN u_kt__kp_in[420]
    DIRECTION INPUT ;
    USE SIGNAL ;
    PORT
      LAYER M5 ;
        RECT  191.676 215.808 191.7 216 ;
    END
  END u_kt__kp_in[420]
  PIN u_kt__kp_in[421]
    DIRECTION INPUT ;
    USE SIGNAL ;
    PORT
      LAYER M5 ;
        RECT  191.82 215.808 191.844 216 ;
    END
  END u_kt__kp_in[421]
  PIN u_kt__kp_in[422]
    DIRECTION INPUT ;
    USE SIGNAL ;
    PORT
      LAYER M5 ;
        RECT  191.964 215.808 191.988 216 ;
    END
  END u_kt__kp_in[422]
  PIN u_kt__kp_in[423]
    DIRECTION INPUT ;
    USE SIGNAL ;
    PORT
      LAYER M5 ;
        RECT  192.156 215.808 192.18 216 ;
    END
  END u_kt__kp_in[423]
  PIN u_kt__kp_in[424]
    DIRECTION INPUT ;
    USE SIGNAL ;
    PORT
      LAYER M5 ;
        RECT  192.3 215.808 192.324 216 ;
    END
  END u_kt__kp_in[424]
  PIN u_kt__kp_in[425]
    DIRECTION INPUT ;
    USE SIGNAL ;
    PORT
      LAYER M5 ;
        RECT  192.444 215.808 192.468 216 ;
    END
  END u_kt__kp_in[425]
  PIN u_kt__kp_in[426]
    DIRECTION INPUT ;
    USE SIGNAL ;
    PORT
      LAYER M5 ;
        RECT  192.636 215.808 192.66 216 ;
    END
  END u_kt__kp_in[426]
  PIN u_kt__kp_in[427]
    DIRECTION INPUT ;
    USE SIGNAL ;
    PORT
      LAYER M5 ;
        RECT  192.78 215.808 192.804 216 ;
    END
  END u_kt__kp_in[427]
  PIN u_kt__kp_in[428]
    DIRECTION INPUT ;
    USE SIGNAL ;
    PORT
      LAYER M5 ;
        RECT  192.924 215.808 192.948 216 ;
    END
  END u_kt__kp_in[428]
  PIN u_kt__kp_in[429]
    DIRECTION INPUT ;
    USE SIGNAL ;
    PORT
      LAYER M5 ;
        RECT  193.068 215.808 193.092 216 ;
    END
  END u_kt__kp_in[429]
  PIN u_kt__kp_in[430]
    DIRECTION INPUT ;
    USE SIGNAL ;
    PORT
      LAYER M5 ;
        RECT  193.26 215.808 193.284 216 ;
    END
  END u_kt__kp_in[430]
  PIN u_kt__kp_in[431]
    DIRECTION INPUT ;
    USE SIGNAL ;
    PORT
      LAYER M5 ;
        RECT  193.404 215.808 193.428 216 ;
    END
  END u_kt__kp_in[431]
  PIN u_kt__kp_in[432]
    DIRECTION INPUT ;
    USE SIGNAL ;
    PORT
      LAYER M5 ;
        RECT  193.548 215.808 193.572 216 ;
    END
  END u_kt__kp_in[432]
  PIN u_kt__kp_in[433]
    DIRECTION INPUT ;
    USE SIGNAL ;
    PORT
      LAYER M5 ;
        RECT  193.74 215.808 193.764 216 ;
    END
  END u_kt__kp_in[433]
  PIN u_kt__kp_in[434]
    DIRECTION INPUT ;
    USE SIGNAL ;
    PORT
      LAYER M5 ;
        RECT  193.884 215.808 193.908 216 ;
    END
  END u_kt__kp_in[434]
  PIN u_kt__kp_in[435]
    DIRECTION INPUT ;
    USE SIGNAL ;
    PORT
      LAYER M5 ;
        RECT  194.028 215.808 194.052 216 ;
    END
  END u_kt__kp_in[435]
  PIN u_kt__kp_in[436]
    DIRECTION INPUT ;
    USE SIGNAL ;
    PORT
      LAYER M5 ;
        RECT  194.22 215.808 194.244 216 ;
    END
  END u_kt__kp_in[436]
  PIN u_kt__kp_in[437]
    DIRECTION INPUT ;
    USE SIGNAL ;
    PORT
      LAYER M5 ;
        RECT  194.364 215.808 194.388 216 ;
    END
  END u_kt__kp_in[437]
  PIN u_kt__kp_in[438]
    DIRECTION INPUT ;
    USE SIGNAL ;
    PORT
      LAYER M5 ;
        RECT  194.508 215.808 194.532 216 ;
    END
  END u_kt__kp_in[438]
  PIN u_kt__kp_in[439]
    DIRECTION INPUT ;
    USE SIGNAL ;
    PORT
      LAYER M5 ;
        RECT  194.7 215.808 194.724 216 ;
    END
  END u_kt__kp_in[439]
  PIN u_kt__kp_in[440]
    DIRECTION INPUT ;
    USE SIGNAL ;
    PORT
      LAYER M5 ;
        RECT  194.844 215.808 194.868 216 ;
    END
  END u_kt__kp_in[440]
  PIN u_kt__kp_in[441]
    DIRECTION INPUT ;
    USE SIGNAL ;
    PORT
      LAYER M5 ;
        RECT  194.988 215.808 195.012 216 ;
    END
  END u_kt__kp_in[441]
  PIN u_kt__kp_in[442]
    DIRECTION INPUT ;
    USE SIGNAL ;
    PORT
      LAYER M5 ;
        RECT  195.132 215.808 195.156 216 ;
    END
  END u_kt__kp_in[442]
  PIN u_kt__kp_in[443]
    DIRECTION INPUT ;
    USE SIGNAL ;
    PORT
      LAYER M5 ;
        RECT  195.324 215.808 195.348 216 ;
    END
  END u_kt__kp_in[443]
  PIN u_kt__kp_in[444]
    DIRECTION INPUT ;
    USE SIGNAL ;
    PORT
      LAYER M5 ;
        RECT  195.468 215.808 195.492 216 ;
    END
  END u_kt__kp_in[444]
  PIN u_kt__kp_in[445]
    DIRECTION INPUT ;
    USE SIGNAL ;
    PORT
      LAYER M5 ;
        RECT  195.612 215.808 195.636 216 ;
    END
  END u_kt__kp_in[445]
  PIN u_kt__kp_in[446]
    DIRECTION INPUT ;
    USE SIGNAL ;
    PORT
      LAYER M5 ;
        RECT  195.804 215.808 195.828 216 ;
    END
  END u_kt__kp_in[446]
  PIN u_kt__kp_in[447]
    DIRECTION INPUT ;
    USE SIGNAL ;
    PORT
      LAYER M5 ;
        RECT  195.948 215.808 195.972 216 ;
    END
  END u_kt__kp_in[447]
  PIN u_kt__kp_in[448]
    DIRECTION INPUT ;
    USE SIGNAL ;
    PORT
      LAYER M5 ;
        RECT  196.092 215.808 196.116 216 ;
    END
  END u_kt__kp_in[448]
  PIN u_kt__kp_in[449]
    DIRECTION INPUT ;
    USE SIGNAL ;
    PORT
      LAYER M5 ;
        RECT  196.284 215.808 196.308 216 ;
    END
  END u_kt__kp_in[449]
  PIN u_kt__kp_in[450]
    DIRECTION INPUT ;
    USE SIGNAL ;
    PORT
      LAYER M5 ;
        RECT  196.428 215.808 196.452 216 ;
    END
  END u_kt__kp_in[450]
  PIN u_kt__kp_in[451]
    DIRECTION INPUT ;
    USE SIGNAL ;
    PORT
      LAYER M5 ;
        RECT  196.572 215.808 196.596 216 ;
    END
  END u_kt__kp_in[451]
  PIN u_kt__kp_in[452]
    DIRECTION INPUT ;
    USE SIGNAL ;
    PORT
      LAYER M5 ;
        RECT  196.764 215.808 196.788 216 ;
    END
  END u_kt__kp_in[452]
  PIN u_kt__kp_in[453]
    DIRECTION INPUT ;
    USE SIGNAL ;
    PORT
      LAYER M5 ;
        RECT  196.908 215.808 196.932 216 ;
    END
  END u_kt__kp_in[453]
  PIN u_kt__kp_in[454]
    DIRECTION INPUT ;
    USE SIGNAL ;
    PORT
      LAYER M5 ;
        RECT  197.052 215.808 197.076 216 ;
    END
  END u_kt__kp_in[454]
  PIN u_kt__kp_in[455]
    DIRECTION INPUT ;
    USE SIGNAL ;
    PORT
      LAYER M5 ;
        RECT  197.244 215.808 197.268 216 ;
    END
  END u_kt__kp_in[455]
  PIN u_kt__kp_in[456]
    DIRECTION INPUT ;
    USE SIGNAL ;
    PORT
      LAYER M5 ;
        RECT  197.388 215.808 197.412 216 ;
    END
  END u_kt__kp_in[456]
  PIN u_kt__kp_in[457]
    DIRECTION INPUT ;
    USE SIGNAL ;
    PORT
      LAYER M5 ;
        RECT  197.532 215.808 197.556 216 ;
    END
  END u_kt__kp_in[457]
  PIN u_kt__kp_in[458]
    DIRECTION INPUT ;
    USE SIGNAL ;
    PORT
      LAYER M5 ;
        RECT  197.676 215.808 197.7 216 ;
    END
  END u_kt__kp_in[458]
  PIN u_kt__kp_in[459]
    DIRECTION INPUT ;
    USE SIGNAL ;
    PORT
      LAYER M5 ;
        RECT  197.868 215.808 197.892 216 ;
    END
  END u_kt__kp_in[459]
  PIN u_kt__kp_in[460]
    DIRECTION INPUT ;
    USE SIGNAL ;
    PORT
      LAYER M5 ;
        RECT  198.012 215.808 198.036 216 ;
    END
  END u_kt__kp_in[460]
  PIN u_kt__kp_in[461]
    DIRECTION INPUT ;
    USE SIGNAL ;
    PORT
      LAYER M5 ;
        RECT  198.156 215.808 198.18 216 ;
    END
  END u_kt__kp_in[461]
  PIN u_kt__kp_in[462]
    DIRECTION INPUT ;
    USE SIGNAL ;
    PORT
      LAYER M5 ;
        RECT  198.348 215.808 198.372 216 ;
    END
  END u_kt__kp_in[462]
  PIN u_kt__kp_in[463]
    DIRECTION INPUT ;
    USE SIGNAL ;
    PORT
      LAYER M5 ;
        RECT  198.492 215.808 198.516 216 ;
    END
  END u_kt__kp_in[463]
  PIN u_kt__kp_in[464]
    DIRECTION INPUT ;
    USE SIGNAL ;
    PORT
      LAYER M5 ;
        RECT  198.636 215.808 198.66 216 ;
    END
  END u_kt__kp_in[464]
  PIN u_kt__kp_in[465]
    DIRECTION INPUT ;
    USE SIGNAL ;
    PORT
      LAYER M5 ;
        RECT  198.828 215.808 198.852 216 ;
    END
  END u_kt__kp_in[465]
  PIN u_kt__kp_in[466]
    DIRECTION INPUT ;
    USE SIGNAL ;
    PORT
      LAYER M5 ;
        RECT  198.972 215.808 198.996 216 ;
    END
  END u_kt__kp_in[466]
  PIN u_kt__kp_in[467]
    DIRECTION INPUT ;
    USE SIGNAL ;
    PORT
      LAYER M5 ;
        RECT  199.116 215.808 199.14 216 ;
    END
  END u_kt__kp_in[467]
  PIN u_kt__kp_in[468]
    DIRECTION INPUT ;
    USE SIGNAL ;
    PORT
      LAYER M5 ;
        RECT  199.308 215.808 199.332 216 ;
    END
  END u_kt__kp_in[468]
  PIN u_kt__kp_in[469]
    DIRECTION INPUT ;
    USE SIGNAL ;
    PORT
      LAYER M5 ;
        RECT  199.452 215.808 199.476 216 ;
    END
  END u_kt__kp_in[469]
  PIN u_kt__kp_in[470]
    DIRECTION INPUT ;
    USE SIGNAL ;
    PORT
      LAYER M5 ;
        RECT  199.596 215.808 199.62 216 ;
    END
  END u_kt__kp_in[470]
  PIN u_kt__kp_in[471]
    DIRECTION INPUT ;
    USE SIGNAL ;
    PORT
      LAYER M5 ;
        RECT  199.74 215.808 199.764 216 ;
    END
  END u_kt__kp_in[471]
  PIN u_kt__kp_in[472]
    DIRECTION INPUT ;
    USE SIGNAL ;
    PORT
      LAYER M5 ;
        RECT  199.932 215.808 199.956 216 ;
    END
  END u_kt__kp_in[472]
  PIN u_kt__kp_in[473]
    DIRECTION INPUT ;
    USE SIGNAL ;
    PORT
      LAYER M5 ;
        RECT  200.076 215.808 200.1 216 ;
    END
  END u_kt__kp_in[473]
  PIN u_kt__kp_in[474]
    DIRECTION INPUT ;
    USE SIGNAL ;
    PORT
      LAYER M5 ;
        RECT  200.22 215.808 200.244 216 ;
    END
  END u_kt__kp_in[474]
  PIN u_kt__kp_in[475]
    DIRECTION INPUT ;
    USE SIGNAL ;
    PORT
      LAYER M5 ;
        RECT  200.412 215.808 200.436 216 ;
    END
  END u_kt__kp_in[475]
  PIN u_kt__kp_in[476]
    DIRECTION INPUT ;
    USE SIGNAL ;
    PORT
      LAYER M5 ;
        RECT  200.556 215.808 200.58 216 ;
    END
  END u_kt__kp_in[476]
  PIN u_kt__kp_in[477]
    DIRECTION INPUT ;
    USE SIGNAL ;
    PORT
      LAYER M5 ;
        RECT  200.7 215.808 200.724 216 ;
    END
  END u_kt__kp_in[477]
  PIN u_kt__kp_in[478]
    DIRECTION INPUT ;
    USE SIGNAL ;
    PORT
      LAYER M5 ;
        RECT  200.892 215.808 200.916 216 ;
    END
  END u_kt__kp_in[478]
  PIN u_kt__kp_in[479]
    DIRECTION INPUT ;
    USE SIGNAL ;
    PORT
      LAYER M5 ;
        RECT  201.036 215.808 201.06 216 ;
    END
  END u_kt__kp_in[479]
  PIN u_kt__kp_in[480]
    DIRECTION INPUT ;
    USE SIGNAL ;
    PORT
      LAYER M5 ;
        RECT  201.18 215.808 201.204 216 ;
    END
  END u_kt__kp_in[480]
  PIN u_kt__kp_in[481]
    DIRECTION INPUT ;
    USE SIGNAL ;
    PORT
      LAYER M5 ;
        RECT  201.372 215.808 201.396 216 ;
    END
  END u_kt__kp_in[481]
  PIN u_kt__kp_in[482]
    DIRECTION INPUT ;
    USE SIGNAL ;
    PORT
      LAYER M5 ;
        RECT  201.516 215.808 201.54 216 ;
    END
  END u_kt__kp_in[482]
  PIN u_kt__kp_in[483]
    DIRECTION INPUT ;
    USE SIGNAL ;
    PORT
      LAYER M5 ;
        RECT  201.66 215.808 201.684 216 ;
    END
  END u_kt__kp_in[483]
  PIN u_kt__kp_in[484]
    DIRECTION INPUT ;
    USE SIGNAL ;
    PORT
      LAYER M5 ;
        RECT  201.852 215.808 201.876 216 ;
    END
  END u_kt__kp_in[484]
  PIN u_kt__kp_in[485]
    DIRECTION INPUT ;
    USE SIGNAL ;
    PORT
      LAYER M5 ;
        RECT  201.996 215.808 202.02 216 ;
    END
  END u_kt__kp_in[485]
  PIN u_kt__kp_in[486]
    DIRECTION INPUT ;
    USE SIGNAL ;
    PORT
      LAYER M5 ;
        RECT  202.14 215.808 202.164 216 ;
    END
  END u_kt__kp_in[486]
  PIN u_kt__kp_in[487]
    DIRECTION INPUT ;
    USE SIGNAL ;
    PORT
      LAYER M5 ;
        RECT  202.284 215.808 202.308 216 ;
    END
  END u_kt__kp_in[487]
  PIN u_kt__kp_in[488]
    DIRECTION INPUT ;
    USE SIGNAL ;
    PORT
      LAYER M5 ;
        RECT  202.476 215.808 202.5 216 ;
    END
  END u_kt__kp_in[488]
  PIN u_kt__kp_in[489]
    DIRECTION INPUT ;
    USE SIGNAL ;
    PORT
      LAYER M5 ;
        RECT  202.62 215.808 202.644 216 ;
    END
  END u_kt__kp_in[489]
  PIN u_kt__kp_in[490]
    DIRECTION INPUT ;
    USE SIGNAL ;
    PORT
      LAYER M5 ;
        RECT  202.764 215.808 202.788 216 ;
    END
  END u_kt__kp_in[490]
  PIN u_kt__kp_in[491]
    DIRECTION INPUT ;
    USE SIGNAL ;
    PORT
      LAYER M5 ;
        RECT  202.956 215.808 202.98 216 ;
    END
  END u_kt__kp_in[491]
  PIN u_kt__kp_in[492]
    DIRECTION INPUT ;
    USE SIGNAL ;
    PORT
      LAYER M5 ;
        RECT  203.1 215.808 203.124 216 ;
    END
  END u_kt__kp_in[492]
  PIN u_kt__kp_in[493]
    DIRECTION INPUT ;
    USE SIGNAL ;
    PORT
      LAYER M5 ;
        RECT  203.244 215.808 203.268 216 ;
    END
  END u_kt__kp_in[493]
  PIN u_kt__kp_in[494]
    DIRECTION INPUT ;
    USE SIGNAL ;
    PORT
      LAYER M5 ;
        RECT  203.436 215.808 203.46 216 ;
    END
  END u_kt__kp_in[494]
  PIN u_kt__kp_in[495]
    DIRECTION INPUT ;
    USE SIGNAL ;
    PORT
      LAYER M5 ;
        RECT  203.58 215.808 203.604 216 ;
    END
  END u_kt__kp_in[495]
  PIN u_kt__kp_in[496]
    DIRECTION INPUT ;
    USE SIGNAL ;
    PORT
      LAYER M5 ;
        RECT  203.724 215.808 203.748 216 ;
    END
  END u_kt__kp_in[496]
  PIN u_kt__kp_in[497]
    DIRECTION INPUT ;
    USE SIGNAL ;
    PORT
      LAYER M5 ;
        RECT  203.916 215.808 203.94 216 ;
    END
  END u_kt__kp_in[497]
  PIN u_kt__kp_in[498]
    DIRECTION INPUT ;
    USE SIGNAL ;
    PORT
      LAYER M5 ;
        RECT  204.06 215.808 204.084 216 ;
    END
  END u_kt__kp_in[498]
  PIN u_kt__kp_in[499]
    DIRECTION INPUT ;
    USE SIGNAL ;
    PORT
      LAYER M5 ;
        RECT  204.204 215.808 204.228 216 ;
    END
  END u_kt__kp_in[499]
  PIN u_kt__kp_in[500]
    DIRECTION INPUT ;
    USE SIGNAL ;
    PORT
      LAYER M5 ;
        RECT  204.396 215.808 204.42 216 ;
    END
  END u_kt__kp_in[500]
  PIN u_kt__kp_in[501]
    DIRECTION INPUT ;
    USE SIGNAL ;
    PORT
      LAYER M5 ;
        RECT  204.54 215.808 204.564 216 ;
    END
  END u_kt__kp_in[501]
  PIN u_kt__kp_in[502]
    DIRECTION INPUT ;
    USE SIGNAL ;
    PORT
      LAYER M5 ;
        RECT  204.684 215.808 204.708 216 ;
    END
  END u_kt__kp_in[502]
  PIN u_kt__kp_in[503]
    DIRECTION INPUT ;
    USE SIGNAL ;
    PORT
      LAYER M5 ;
        RECT  204.828 215.808 204.852 216 ;
    END
  END u_kt__kp_in[503]
  PIN u_kt__kp_in[504]
    DIRECTION INPUT ;
    USE SIGNAL ;
    PORT
      LAYER M5 ;
        RECT  205.02 215.808 205.044 216 ;
    END
  END u_kt__kp_in[504]
  PIN u_kt__kp_in[505]
    DIRECTION INPUT ;
    USE SIGNAL ;
    PORT
      LAYER M5 ;
        RECT  205.164 215.808 205.188 216 ;
    END
  END u_kt__kp_in[505]
  PIN u_kt__kp_in[506]
    DIRECTION INPUT ;
    USE SIGNAL ;
    PORT
      LAYER M5 ;
        RECT  205.308 215.808 205.332 216 ;
    END
  END u_kt__kp_in[506]
  PIN u_kt__kp_in[507]
    DIRECTION INPUT ;
    USE SIGNAL ;
    PORT
      LAYER M5 ;
        RECT  205.5 215.808 205.524 216 ;
    END
  END u_kt__kp_in[507]
  PIN u_kt__kp_in[508]
    DIRECTION INPUT ;
    USE SIGNAL ;
    PORT
      LAYER M5 ;
        RECT  205.644 215.808 205.668 216 ;
    END
  END u_kt__kp_in[508]
  PIN u_kt__kp_in[509]
    DIRECTION INPUT ;
    USE SIGNAL ;
    PORT
      LAYER M5 ;
        RECT  205.788 215.808 205.812 216 ;
    END
  END u_kt__kp_in[509]
  PIN u_kt__kp_in[510]
    DIRECTION INPUT ;
    USE SIGNAL ;
    PORT
      LAYER M5 ;
        RECT  205.98 215.808 206.004 216 ;
    END
  END u_kt__kp_in[510]
  PIN u_kt__kp_in[511]
    DIRECTION INPUT ;
    USE SIGNAL ;
    PORT
      LAYER M5 ;
        RECT  206.124 215.808 206.148 216 ;
    END
  END u_kt__kp_in[511]
  PIN u_kt__kp_in[64]
    DIRECTION INPUT ;
    USE SIGNAL ;
    PORT
      LAYER M5 ;
        RECT  135.084 215.808 135.108 216 ;
    END
  END u_kt__kp_in[64]
  PIN u_kt__kp_in[65]
    DIRECTION INPUT ;
    USE SIGNAL ;
    PORT
      LAYER M5 ;
        RECT  135.228 215.808 135.252 216 ;
    END
  END u_kt__kp_in[65]
  PIN u_kt__kp_in[66]
    DIRECTION INPUT ;
    USE SIGNAL ;
    PORT
      LAYER M5 ;
        RECT  135.42 215.808 135.444 216 ;
    END
  END u_kt__kp_in[66]
  PIN u_kt__kp_in[67]
    DIRECTION INPUT ;
    USE SIGNAL ;
    PORT
      LAYER M5 ;
        RECT  135.564 215.808 135.588 216 ;
    END
  END u_kt__kp_in[67]
  PIN u_kt__kp_in[68]
    DIRECTION INPUT ;
    USE SIGNAL ;
    PORT
      LAYER M5 ;
        RECT  135.708 215.808 135.732 216 ;
    END
  END u_kt__kp_in[68]
  PIN u_kt__kp_in[69]
    DIRECTION INPUT ;
    USE SIGNAL ;
    PORT
      LAYER M5 ;
        RECT  135.9 215.808 135.924 216 ;
    END
  END u_kt__kp_in[69]
  PIN u_kt__kp_in[70]
    DIRECTION INPUT ;
    USE SIGNAL ;
    PORT
      LAYER M5 ;
        RECT  136.044 215.808 136.068 216 ;
    END
  END u_kt__kp_in[70]
  PIN u_kt__kp_in[71]
    DIRECTION INPUT ;
    USE SIGNAL ;
    PORT
      LAYER M5 ;
        RECT  136.188 215.808 136.212 216 ;
    END
  END u_kt__kp_in[71]
  PIN u_kt__kp_in[72]
    DIRECTION INPUT ;
    USE SIGNAL ;
    PORT
      LAYER M5 ;
        RECT  136.332 215.808 136.356 216 ;
    END
  END u_kt__kp_in[72]
  PIN u_kt__kp_in[73]
    DIRECTION INPUT ;
    USE SIGNAL ;
    PORT
      LAYER M5 ;
        RECT  136.524 215.808 136.548 216 ;
    END
  END u_kt__kp_in[73]
  PIN u_kt__kp_in[74]
    DIRECTION INPUT ;
    USE SIGNAL ;
    PORT
      LAYER M5 ;
        RECT  136.668 215.808 136.692 216 ;
    END
  END u_kt__kp_in[74]
  PIN u_kt__kp_in[75]
    DIRECTION INPUT ;
    USE SIGNAL ;
    PORT
      LAYER M5 ;
        RECT  136.812 215.808 136.836 216 ;
    END
  END u_kt__kp_in[75]
  PIN u_kt__kp_in[76]
    DIRECTION INPUT ;
    USE SIGNAL ;
    PORT
      LAYER M5 ;
        RECT  137.004 215.808 137.028 216 ;
    END
  END u_kt__kp_in[76]
  PIN u_kt__kp_in[77]
    DIRECTION INPUT ;
    USE SIGNAL ;
    PORT
      LAYER M5 ;
        RECT  137.148 215.808 137.172 216 ;
    END
  END u_kt__kp_in[77]
  PIN u_kt__kp_in[78]
    DIRECTION INPUT ;
    USE SIGNAL ;
    PORT
      LAYER M5 ;
        RECT  137.292 215.808 137.316 216 ;
    END
  END u_kt__kp_in[78]
  PIN u_kt__kp_in[79]
    DIRECTION INPUT ;
    USE SIGNAL ;
    PORT
      LAYER M5 ;
        RECT  137.484 215.808 137.508 216 ;
    END
  END u_kt__kp_in[79]
  PIN u_kt__kp_in[80]
    DIRECTION INPUT ;
    USE SIGNAL ;
    PORT
      LAYER M5 ;
        RECT  137.628 215.808 137.652 216 ;
    END
  END u_kt__kp_in[80]
  PIN u_kt__kp_in[81]
    DIRECTION INPUT ;
    USE SIGNAL ;
    PORT
      LAYER M5 ;
        RECT  137.772 215.808 137.796 216 ;
    END
  END u_kt__kp_in[81]
  PIN u_kt__kp_in[82]
    DIRECTION INPUT ;
    USE SIGNAL ;
    PORT
      LAYER M5 ;
        RECT  137.964 215.808 137.988 216 ;
    END
  END u_kt__kp_in[82]
  PIN u_kt__kp_in[83]
    DIRECTION INPUT ;
    USE SIGNAL ;
    PORT
      LAYER M5 ;
        RECT  138.108 215.808 138.132 216 ;
    END
  END u_kt__kp_in[83]
  PIN u_kt__kp_in[84]
    DIRECTION INPUT ;
    USE SIGNAL ;
    PORT
      LAYER M5 ;
        RECT  138.252 215.808 138.276 216 ;
    END
  END u_kt__kp_in[84]
  PIN u_kt__kp_in[85]
    DIRECTION INPUT ;
    USE SIGNAL ;
    PORT
      LAYER M5 ;
        RECT  138.444 215.808 138.468 216 ;
    END
  END u_kt__kp_in[85]
  PIN u_kt__kp_in[86]
    DIRECTION INPUT ;
    USE SIGNAL ;
    PORT
      LAYER M5 ;
        RECT  138.588 215.808 138.612 216 ;
    END
  END u_kt__kp_in[86]
  PIN u_kt__kp_in[87]
    DIRECTION INPUT ;
    USE SIGNAL ;
    PORT
      LAYER M5 ;
        RECT  138.732 215.808 138.756 216 ;
    END
  END u_kt__kp_in[87]
  PIN u_kt__kp_in[88]
    DIRECTION INPUT ;
    USE SIGNAL ;
    PORT
      LAYER M5 ;
        RECT  138.876 215.808 138.9 216 ;
    END
  END u_kt__kp_in[88]
  PIN u_kt__kp_in[89]
    DIRECTION INPUT ;
    USE SIGNAL ;
    PORT
      LAYER M5 ;
        RECT  139.068 215.808 139.092 216 ;
    END
  END u_kt__kp_in[89]
  PIN u_kt__kp_in[90]
    DIRECTION INPUT ;
    USE SIGNAL ;
    PORT
      LAYER M5 ;
        RECT  139.212 215.808 139.236 216 ;
    END
  END u_kt__kp_in[90]
  PIN u_kt__kp_in[91]
    DIRECTION INPUT ;
    USE SIGNAL ;
    PORT
      LAYER M5 ;
        RECT  139.356 215.808 139.38 216 ;
    END
  END u_kt__kp_in[91]
  PIN u_kt__kp_in[92]
    DIRECTION INPUT ;
    USE SIGNAL ;
    PORT
      LAYER M5 ;
        RECT  139.548 215.808 139.572 216 ;
    END
  END u_kt__kp_in[92]
  PIN u_kt__kp_in[93]
    DIRECTION INPUT ;
    USE SIGNAL ;
    PORT
      LAYER M5 ;
        RECT  139.692 215.808 139.716 216 ;
    END
  END u_kt__kp_in[93]
  PIN u_kt__kp_in[94]
    DIRECTION INPUT ;
    USE SIGNAL ;
    PORT
      LAYER M5 ;
        RECT  139.836 215.808 139.86 216 ;
    END
  END u_kt__kp_in[94]
  PIN u_kt__kp_in[95]
    DIRECTION INPUT ;
    USE SIGNAL ;
    PORT
      LAYER M5 ;
        RECT  140.028 215.808 140.052 216 ;
    END
  END u_kt__kp_in[95]
  PIN u_kt__kp_in[96]
    DIRECTION INPUT ;
    USE SIGNAL ;
    PORT
      LAYER M5 ;
        RECT  140.172 215.808 140.196 216 ;
    END
  END u_kt__kp_in[96]
  PIN u_kt__kp_in[97]
    DIRECTION INPUT ;
    USE SIGNAL ;
    PORT
      LAYER M5 ;
        RECT  140.316 215.808 140.34 216 ;
    END
  END u_kt__kp_in[97]
  PIN u_kt__kp_in[98]
    DIRECTION INPUT ;
    USE SIGNAL ;
    PORT
      LAYER M5 ;
        RECT  140.508 215.808 140.532 216 ;
    END
  END u_kt__kp_in[98]
  PIN u_kt__kp_in[99]
    DIRECTION INPUT ;
    USE SIGNAL ;
    PORT
      LAYER M5 ;
        RECT  140.652 215.808 140.676 216 ;
    END
  END u_kt__kp_in[99]
  PIN u_kt__kpv_in[10]
    DIRECTION INPUT ;
    USE SIGNAL ;
    PORT
      LAYER M5 ;
        RECT  207.564 215.808 207.588 216 ;
    END
  END u_kt__kpv_in[10]
  PIN u_kt__kpv_in[11]
    DIRECTION INPUT ;
    USE SIGNAL ;
    PORT
      LAYER M5 ;
        RECT  207.708 215.808 207.732 216 ;
    END
  END u_kt__kpv_in[11]
  PIN u_kt__kpv_in[12]
    DIRECTION INPUT ;
    USE SIGNAL ;
    PORT
      LAYER M5 ;
        RECT  207.852 215.808 207.876 216 ;
    END
  END u_kt__kpv_in[12]
  PIN u_kt__kpv_in[13]
    DIRECTION INPUT ;
    USE SIGNAL ;
    PORT
      LAYER M5 ;
        RECT  208.044 215.808 208.068 216 ;
    END
  END u_kt__kpv_in[13]
  PIN u_kt__kpv_in[14]
    DIRECTION INPUT ;
    USE SIGNAL ;
    PORT
      LAYER M5 ;
        RECT  208.188 215.808 208.212 216 ;
    END
  END u_kt__kpv_in[14]
  PIN u_kt__kpv_in[15]
    DIRECTION INPUT ;
    USE SIGNAL ;
    PORT
      LAYER M5 ;
        RECT  208.332 215.808 208.356 216 ;
    END
  END u_kt__kpv_in[15]
  PIN u_kt__kpv_in[2]
    DIRECTION INPUT ;
    USE SIGNAL ;
    PORT
      LAYER M5 ;
        RECT  206.268 215.808 206.292 216 ;
    END
  END u_kt__kpv_in[2]
  PIN u_kt__kpv_in[3]
    DIRECTION INPUT ;
    USE SIGNAL ;
    PORT
      LAYER M5 ;
        RECT  206.46 215.808 206.484 216 ;
    END
  END u_kt__kpv_in[3]
  PIN u_kt__kpv_in[4]
    DIRECTION INPUT ;
    USE SIGNAL ;
    PORT
      LAYER M5 ;
        RECT  206.604 215.808 206.628 216 ;
    END
  END u_kt__kpv_in[4]
  PIN u_kt__kpv_in[5]
    DIRECTION INPUT ;
    USE SIGNAL ;
    PORT
      LAYER M5 ;
        RECT  206.748 215.808 206.772 216 ;
    END
  END u_kt__kpv_in[5]
  PIN u_kt__kpv_in[6]
    DIRECTION INPUT ;
    USE SIGNAL ;
    PORT
      LAYER M5 ;
        RECT  206.892 215.808 206.916 216 ;
    END
  END u_kt__kpv_in[6]
  PIN u_kt__kpv_in[7]
    DIRECTION INPUT ;
    USE SIGNAL ;
    PORT
      LAYER M5 ;
        RECT  207.084 215.808 207.108 216 ;
    END
  END u_kt__kpv_in[7]
  PIN u_kt__kpv_in[8]
    DIRECTION INPUT ;
    USE SIGNAL ;
    PORT
      LAYER M5 ;
        RECT  207.228 215.808 207.252 216 ;
    END
  END u_kt__kpv_in[8]
  PIN u_kt__kpv_in[9]
    DIRECTION INPUT ;
    USE SIGNAL ;
    PORT
      LAYER M5 ;
        RECT  207.372 215.808 207.396 216 ;
    END
  END u_kt__kpv_in[9]
  PIN u_kt__rst_n[0]
    DIRECTION INPUT ;
    USE SIGNAL ;
    PORT
      LAYER M5 ;
        RECT  208.524 215.808 208.548 216 ;
    END
  END u_kt__rst_n[0]
  PIN u_kt__sc_d[0]
    DIRECTION OUTPUT ;
    USE SIGNAL ;
    PORT
      LAYER M5 ;
        RECT  208.668 215.808 208.692 216 ;
    END
  END u_kt__sc_d[0]
  PIN u_kt__sc_d[10]
    DIRECTION OUTPUT ;
    USE SIGNAL ;
    PORT
      LAYER M5 ;
        RECT  210.252 215.808 210.276 216 ;
    END
  END u_kt__sc_d[10]
  PIN u_kt__sc_d[11]
    DIRECTION OUTPUT ;
    USE SIGNAL ;
    PORT
      LAYER M5 ;
        RECT  210.396 215.808 210.42 216 ;
    END
  END u_kt__sc_d[11]
  PIN u_kt__sc_d[12]
    DIRECTION OUTPUT ;
    USE SIGNAL ;
    PORT
      LAYER M5 ;
        RECT  210.588 215.808 210.612 216 ;
    END
  END u_kt__sc_d[12]
  PIN u_kt__sc_d[13]
    DIRECTION OUTPUT ;
    USE SIGNAL ;
    PORT
      LAYER M5 ;
        RECT  210.732 215.808 210.756 216 ;
    END
  END u_kt__sc_d[13]
  PIN u_kt__sc_d[14]
    DIRECTION OUTPUT ;
    USE SIGNAL ;
    PORT
      LAYER M5 ;
        RECT  210.876 215.808 210.9 216 ;
    END
  END u_kt__sc_d[14]
  PIN u_kt__sc_d[15]
    DIRECTION OUTPUT ;
    USE SIGNAL ;
    PORT
      LAYER M5 ;
        RECT  211.068 215.808 211.092 216 ;
    END
  END u_kt__sc_d[15]
  PIN u_kt__sc_d[16]
    DIRECTION OUTPUT ;
    USE SIGNAL ;
    PORT
      LAYER M5 ;
        RECT  211.212 215.808 211.236 216 ;
    END
  END u_kt__sc_d[16]
  PIN u_kt__sc_d[17]
    DIRECTION OUTPUT ;
    USE SIGNAL ;
    PORT
      LAYER M5 ;
        RECT  211.356 215.808 211.38 216 ;
    END
  END u_kt__sc_d[17]
  PIN u_kt__sc_d[18]
    DIRECTION OUTPUT ;
    USE SIGNAL ;
    PORT
      LAYER M5 ;
        RECT  211.5 215.808 211.524 216 ;
    END
  END u_kt__sc_d[18]
  PIN u_kt__sc_d[19]
    DIRECTION OUTPUT ;
    USE SIGNAL ;
    PORT
      LAYER M5 ;
        RECT  211.692 215.808 211.716 216 ;
    END
  END u_kt__sc_d[19]
  PIN u_kt__sc_d[1]
    DIRECTION OUTPUT ;
    USE SIGNAL ;
    PORT
      LAYER M5 ;
        RECT  208.812 215.808 208.836 216 ;
    END
  END u_kt__sc_d[1]
  PIN u_kt__sc_d[20]
    DIRECTION OUTPUT ;
    USE SIGNAL ;
    PORT
      LAYER M5 ;
        RECT  211.836 215.808 211.86 216 ;
    END
  END u_kt__sc_d[20]
  PIN u_kt__sc_d[21]
    DIRECTION OUTPUT ;
    USE SIGNAL ;
    PORT
      LAYER M5 ;
        RECT  211.98 215.808 212.004 216 ;
    END
  END u_kt__sc_d[21]
  PIN u_kt__sc_d[22]
    DIRECTION OUTPUT ;
    USE SIGNAL ;
    PORT
      LAYER M5 ;
        RECT  212.172 215.808 212.196 216 ;
    END
  END u_kt__sc_d[22]
  PIN u_kt__sc_d[23]
    DIRECTION OUTPUT ;
    USE SIGNAL ;
    PORT
      LAYER M5 ;
        RECT  212.316 215.808 212.34 216 ;
    END
  END u_kt__sc_d[23]
  PIN u_kt__sc_d[24]
    DIRECTION OUTPUT ;
    USE SIGNAL ;
    PORT
      LAYER M5 ;
        RECT  212.46 215.808 212.484 216 ;
    END
  END u_kt__sc_d[24]
  PIN u_kt__sc_d[25]
    DIRECTION OUTPUT ;
    USE SIGNAL ;
    PORT
      LAYER M5 ;
        RECT  212.652 215.808 212.676 216 ;
    END
  END u_kt__sc_d[25]
  PIN u_kt__sc_d[26]
    DIRECTION OUTPUT ;
    USE SIGNAL ;
    PORT
      LAYER M5 ;
        RECT  212.796 215.808 212.82 216 ;
    END
  END u_kt__sc_d[26]
  PIN u_kt__sc_d[27]
    DIRECTION OUTPUT ;
    USE SIGNAL ;
    PORT
      LAYER M5 ;
        RECT  212.94 215.808 212.964 216 ;
    END
  END u_kt__sc_d[27]
  PIN u_kt__sc_d[28]
    DIRECTION OUTPUT ;
    USE SIGNAL ;
    PORT
      LAYER M5 ;
        RECT  213.132 215.808 213.156 216 ;
    END
  END u_kt__sc_d[28]
  PIN u_kt__sc_d[29]
    DIRECTION OUTPUT ;
    USE SIGNAL ;
    PORT
      LAYER M5 ;
        RECT  213.276 215.808 213.3 216 ;
    END
  END u_kt__sc_d[29]
  PIN u_kt__sc_d[2]
    DIRECTION OUTPUT ;
    USE SIGNAL ;
    PORT
      LAYER M5 ;
        RECT  209.004 215.808 209.028 216 ;
    END
  END u_kt__sc_d[2]
  PIN u_kt__sc_d[30]
    DIRECTION OUTPUT ;
    USE SIGNAL ;
    PORT
      LAYER M5 ;
        RECT  213.42 215.808 213.444 216 ;
    END
  END u_kt__sc_d[30]
  PIN u_kt__sc_d[31]
    DIRECTION OUTPUT ;
    USE SIGNAL ;
    PORT
      LAYER M5 ;
        RECT  213.612 215.808 213.636 216 ;
    END
  END u_kt__sc_d[31]
  PIN u_kt__sc_d[3]
    DIRECTION OUTPUT ;
    USE SIGNAL ;
    PORT
      LAYER M5 ;
        RECT  209.148 215.808 209.172 216 ;
    END
  END u_kt__sc_d[3]
  PIN u_kt__sc_d[4]
    DIRECTION OUTPUT ;
    USE SIGNAL ;
    PORT
      LAYER M5 ;
        RECT  209.292 215.808 209.316 216 ;
    END
  END u_kt__sc_d[4]
  PIN u_kt__sc_d[5]
    DIRECTION OUTPUT ;
    USE SIGNAL ;
    PORT
      LAYER M5 ;
        RECT  209.436 215.808 209.46 216 ;
    END
  END u_kt__sc_d[5]
  PIN u_kt__sc_d[6]
    DIRECTION OUTPUT ;
    USE SIGNAL ;
    PORT
      LAYER M5 ;
        RECT  209.628 215.808 209.652 216 ;
    END
  END u_kt__sc_d[6]
  PIN u_kt__sc_d[7]
    DIRECTION OUTPUT ;
    USE SIGNAL ;
    PORT
      LAYER M5 ;
        RECT  209.772 215.808 209.796 216 ;
    END
  END u_kt__sc_d[7]
  PIN u_kt__sc_d[8]
    DIRECTION OUTPUT ;
    USE SIGNAL ;
    PORT
      LAYER M5 ;
        RECT  209.916 215.808 209.94 216 ;
    END
  END u_kt__sc_d[8]
  PIN u_kt__sc_d[9]
    DIRECTION OUTPUT ;
    USE SIGNAL ;
    PORT
      LAYER M5 ;
        RECT  210.108 215.808 210.132 216 ;
    END
  END u_kt__sc_d[9]
  PIN u_kt__sc_f[0]
    DIRECTION OUTPUT ;
    USE SIGNAL ;
    PORT
      LAYER M5 ;
        RECT  213.756 215.808 213.78 216 ;
    END
  END u_kt__sc_f[0]
  PIN VSS
    DIRECTION INOUT ;
    USE GROUND ;
    PORT
      LAYER M5 ;
        RECT  209.364 4.297 209.484 211.703 ;
        RECT  205.044 4.297 205.164 211.703 ;
        RECT  200.724 4.297 200.844 211.703 ;
        RECT  196.404 4.297 196.524 211.703 ;
        RECT  192.084 4.297 192.204 211.703 ;
        RECT  187.764 4.297 187.884 211.703 ;
        RECT  183.444 4.297 183.564 211.703 ;
        RECT  179.124 4.297 179.244 211.703 ;
        RECT  174.804 4.297 174.924 211.703 ;
        RECT  170.484 4.297 170.604 211.703 ;
        RECT  166.164 4.297 166.284 211.703 ;
        RECT  161.844 4.297 161.964 211.703 ;
        RECT  157.524 4.297 157.644 211.703 ;
        RECT  153.204 4.297 153.324 211.703 ;
        RECT  148.884 4.297 149.004 211.703 ;
        RECT  144.564 4.297 144.684 211.703 ;
        RECT  140.244 4.297 140.364 211.703 ;
        RECT  135.924 4.297 136.044 211.703 ;
        RECT  131.604 4.297 131.724 211.703 ;
        RECT  127.284 4.297 127.404 211.703 ;
        RECT  122.964 4.297 123.084 211.703 ;
        RECT  118.644 4.297 118.764 211.703 ;
        RECT  114.324 4.297 114.444 211.703 ;
        RECT  110.004 4.297 110.124 211.703 ;
        RECT  105.684 4.297 105.804 211.703 ;
        RECT  101.364 4.297 101.484 211.703 ;
        RECT  97.044 4.297 97.164 211.703 ;
        RECT  92.724 4.297 92.844 211.703 ;
        RECT  88.404 4.297 88.524 211.703 ;
        RECT  84.084 4.297 84.204 211.703 ;
        RECT  79.764 4.297 79.884 211.703 ;
        RECT  75.444 4.297 75.564 211.703 ;
        RECT  71.124 4.297 71.244 211.703 ;
        RECT  66.804 4.297 66.924 211.703 ;
        RECT  62.484 4.297 62.604 211.703 ;
        RECT  58.164 4.297 58.284 211.703 ;
        RECT  53.844 4.297 53.964 211.703 ;
        RECT  49.524 4.297 49.644 211.703 ;
        RECT  45.204 4.297 45.324 211.703 ;
        RECT  40.884 4.297 41.004 211.703 ;
        RECT  36.564 4.297 36.684 211.703 ;
        RECT  32.244 4.297 32.364 211.703 ;
        RECT  27.924 4.297 28.044 211.703 ;
        RECT  23.604 4.297 23.724 211.703 ;
        RECT  19.284 4.297 19.404 211.703 ;
        RECT  14.964 4.297 15.084 211.703 ;
        RECT  10.644 4.297 10.764 211.703 ;
        RECT  6.324 4.297 6.444 211.703 ;
    END
  END VSS
  PIN VDD
    DIRECTION INOUT ;
    USE POWER ;
    PORT
      LAYER M5 ;
        RECT  209.556 4.311 209.676 211.689 ;
        RECT  205.236 4.311 205.356 211.689 ;
        RECT  200.916 4.311 201.036 211.689 ;
        RECT  196.596 4.311 196.716 211.689 ;
        RECT  192.276 4.311 192.396 211.689 ;
        RECT  187.956 4.311 188.076 211.689 ;
        RECT  183.636 4.311 183.756 211.689 ;
        RECT  179.316 4.311 179.436 211.689 ;
        RECT  174.996 4.311 175.116 211.689 ;
        RECT  170.676 4.311 170.796 211.689 ;
        RECT  166.356 4.311 166.476 211.689 ;
        RECT  162.036 4.311 162.156 211.689 ;
        RECT  157.716 4.311 157.836 211.689 ;
        RECT  153.396 4.311 153.516 211.689 ;
        RECT  149.076 4.311 149.196 211.689 ;
        RECT  144.756 4.311 144.876 211.689 ;
        RECT  140.436 4.311 140.556 211.689 ;
        RECT  136.116 4.311 136.236 211.689 ;
        RECT  131.796 4.311 131.916 211.689 ;
        RECT  127.476 4.311 127.596 211.689 ;
        RECT  123.156 4.311 123.276 211.689 ;
        RECT  118.836 4.311 118.956 211.689 ;
        RECT  114.516 4.311 114.636 211.689 ;
        RECT  110.196 4.311 110.316 211.689 ;
        RECT  105.876 4.311 105.996 211.689 ;
        RECT  101.556 4.311 101.676 211.689 ;
        RECT  97.236 4.311 97.356 211.689 ;
        RECT  92.916 4.311 93.036 211.689 ;
        RECT  88.596 4.311 88.716 211.689 ;
        RECT  84.276 4.311 84.396 211.689 ;
        RECT  79.956 4.311 80.076 211.689 ;
        RECT  75.636 4.311 75.756 211.689 ;
        RECT  71.316 4.311 71.436 211.689 ;
        RECT  66.996 4.311 67.116 211.689 ;
        RECT  62.676 4.311 62.796 211.689 ;
        RECT  58.356 4.311 58.476 211.689 ;
        RECT  54.036 4.311 54.156 211.689 ;
        RECT  49.716 4.311 49.836 211.689 ;
        RECT  45.396 4.311 45.516 211.689 ;
        RECT  41.076 4.311 41.196 211.689 ;
        RECT  36.756 4.311 36.876 211.689 ;
        RECT  32.436 4.311 32.556 211.689 ;
        RECT  28.116 4.311 28.236 211.689 ;
        RECT  23.796 4.311 23.916 211.689 ;
        RECT  19.476 4.311 19.596 211.689 ;
        RECT  15.156 4.311 15.276 211.689 ;
        RECT  10.836 4.311 10.956 211.689 ;
        RECT  6.516 4.311 6.636 211.689 ;
    END
  END VDD
  OBS
    LAYER RVTN ;
     RECT  0 0 216 216 ;
    LAYER RVTP ;
     RECT  0 0 216 216 ;
    LAYER M1 ;
     RECT  0 0 216 216 ;
    LAYER M2 ;
     RECT  0 0 216 216 ;
    LAYER M3 ;
     RECT  0 0 216 216 ;
    LAYER M4 ;
     RECT  0 0 216 216 ;
    LAYER M5 ;
     RECT  0 0 216 216 ;
    LAYER M6 ;
     RECT  0 0 216 216 ;
    LAYER M7 ;
     RECT  0 0 216 216 ;
  END
END kv3_head_eighth_e0
END LIBRARY
